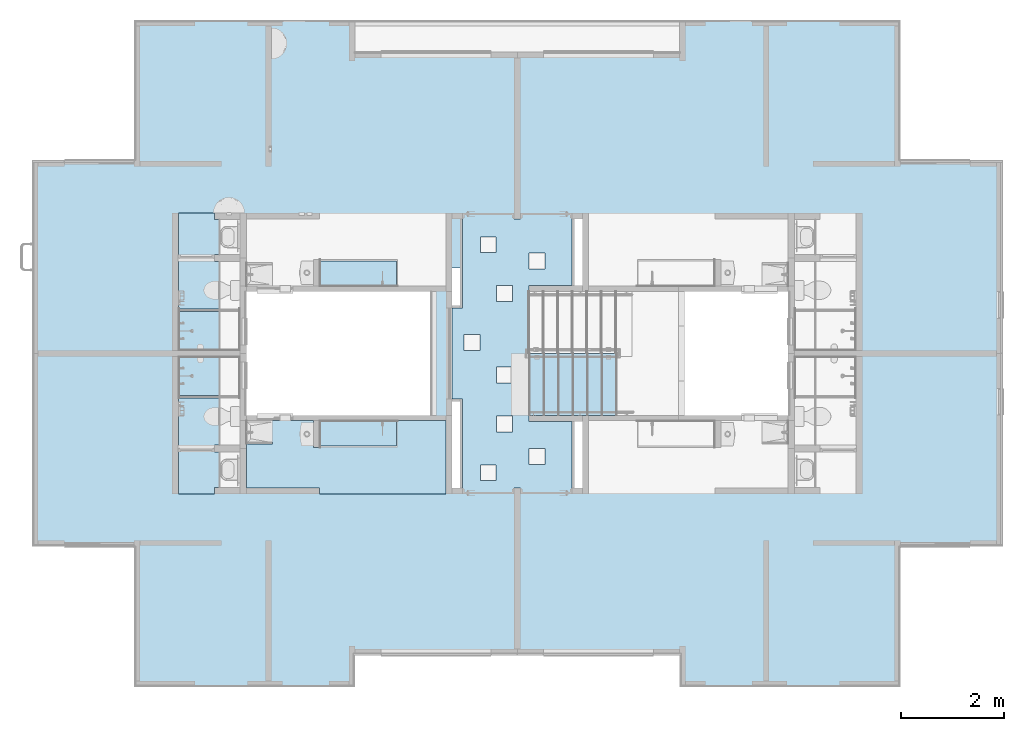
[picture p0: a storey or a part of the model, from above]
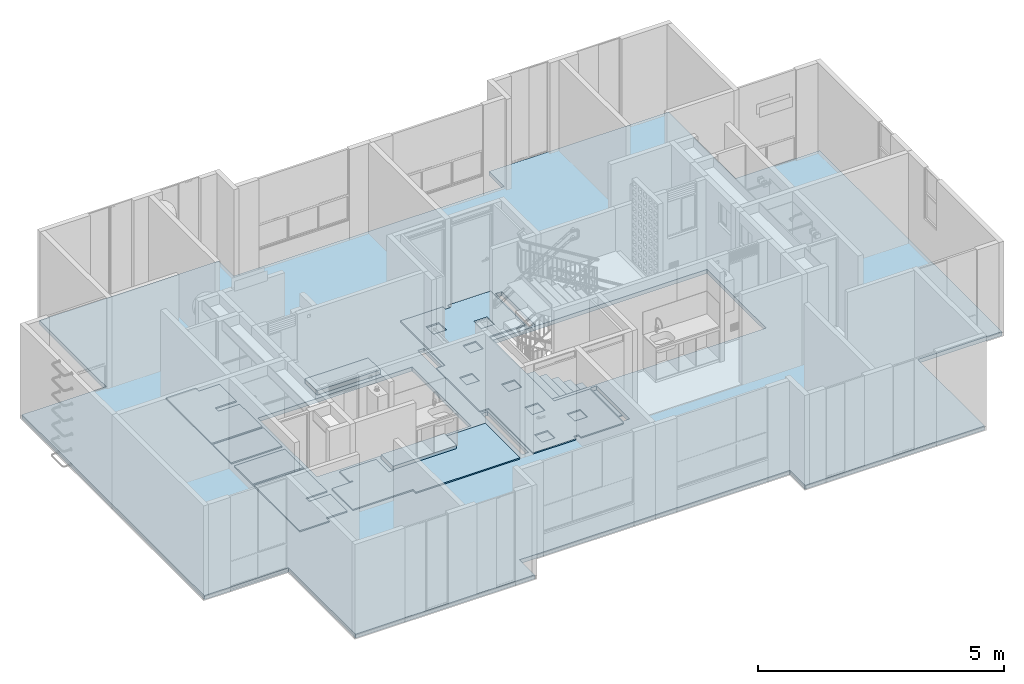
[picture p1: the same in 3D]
Properties of the parts of a building model (IFC4), part 1 of 6

# File
Description: ViewDefinition [ReferenceView_V1.2], RevitIdentifiers [VersionGUID: ac9cff58-8635-4e02-9c65-74fbef69012c, NumberOfSaves: 19], CoordinateReference [CoordinateBase: Shared Coordinates], ExchangeRequirement [Architecture]
Time: 2024-11-18T10:54:56-05:00
Written by: ODA SDAI 22.12
Made in: 23.1.40.56 - Exporter 23.2.5.0 - Alternate UI 23.2.5.0

# IfcSite, Default
RefLatitude: 4, 40, 21, 122360; RefLongitude: -74, -2, -58, -308105; RefElevation: 0 m
Pset_SiteCommon - Reference: Project Information

# IfcBuilding
Pset_BuildingCommon - Reference: Project Information; NumberOfStoreys: 7
Pset_BuildingElementProxyCommon - Reference: Project Information; IsExternal: no
Pset_BuildingStoreyCommon - Reference: Project Information; sets with these values: 2

# IfcBuildingStorey: Level:eBIM - Nivel (7)
Pset_BuildingStoreyCommon - Reference: eBIM - Nivel
Name | LongName | Elevation (m)
Nivel 1 | Nivel 1 | 0
Nivel 2 | Nivel 2 | 2.35
Nivel 3 | Nivel 3 | 4.7
Nivel 4 | Nivel 4 | 7.05
Nivel 5 | Nivel 5 | 9.4
Nivel 6 | Nivel 6 | 11.75
Nivel 7 | Nivel 7 | 14.1

# IfcSpace: APTO TIPO A 53:950452, 53
In: Nivel 2
LongName: APTO TIPO A; PredefinedType: SPACE; Group: Gross Building
Pset_SpaceCommon - IsExternal: no; Reference: APTO TIPO A 53
Pset_SpaceHeaterTypeCommon - Reference: APTO TIPO A 53
Qto_SpaceBaseQuantities - Height: 2.35 m

# IfcSpace: APTO TIPO A 54:950462, 54
In: Nivel 2
LongName: APTO TIPO A; PredefinedType: SPACE; Group: Gross Building
Pset_SpaceCommon - IsExternal: no; Reference: APTO TIPO A 54
Pset_SpaceHeaterTypeCommon - Reference: APTO TIPO A 54
Qto_SpaceBaseQuantities - Height: 2.35 m

# IfcSpace: APTO TIPO A 55:950468, 55
In: Nivel 3
LongName: APTO TIPO A; PredefinedType: SPACE; Group: Gross Building
Pset_SpaceCommon - IsExternal: no; Reference: APTO TIPO A 55
Pset_SpaceHeaterTypeCommon - Reference: APTO TIPO A 55
Qto_SpaceBaseQuantities - Height: 2.35 m

# IfcSpace: APTO TIPO A 56:950472, 56
In: Nivel 3
LongName: APTO TIPO A; PredefinedType: SPACE; Group: Gross Building
Pset_SpaceCommon - IsExternal: no; Reference: APTO TIPO A 56
Pset_SpaceHeaterTypeCommon - Reference: APTO TIPO A 56
Qto_SpaceBaseQuantities - Height: 2.35 m

# IfcSpace: APTO TIPO A 57:950475, 57
In: Nivel 3
LongName: APTO TIPO A; PredefinedType: SPACE; Group: Gross Building
Pset_SpaceCommon - IsExternal: no; Reference: APTO TIPO A 57
Pset_SpaceHeaterTypeCommon - Reference: APTO TIPO A 57
Qto_SpaceBaseQuantities - Height: 2.35 m

# IfcSpace: APTO TIPO A 58:950478, 58
In: Nivel 3
LongName: APTO TIPO A; PredefinedType: SPACE; Group: Gross Building
Pset_SpaceCommon - IsExternal: no; Reference: APTO TIPO A 58
Pset_SpaceHeaterTypeCommon - Reference: APTO TIPO A 58
Qto_SpaceBaseQuantities - Height: 2.35 m

# IfcSpace: APTO TIPO B 51:950442, 51
In: Nivel 2
LongName: APTO TIPO B; PredefinedType: SPACE; Group: Gross Building
Pset_SpaceCommon - IsExternal: no; Reference: APTO TIPO B 51
Pset_SpaceHeaterTypeCommon - Reference: APTO TIPO B 51
Qto_SpaceBaseQuantities - Height: 2.35 m

# IfcSpace: APTO TIPO B 52:950446, 52
In: Nivel 2
LongName: APTO TIPO B; PredefinedType: SPACE; Group: Gross Building
Pset_SpaceCommon - IsExternal: no; Reference: APTO TIPO B 52
Pset_SpaceHeaterTypeCommon - Reference: APTO TIPO B 52
Qto_SpaceBaseQuantities - Height: 2.35 m

# IfcSpace: APTO TIPO C 28:905856, 28
In: Nivel 1
LongName: APTO TIPO C; PredefinedType: SPACE; Group: Gross Building
Pset_SpaceCommon - IsExternal: no; Reference: APTO TIPO C 28
Pset_SpaceHeaterTypeCommon - Reference: APTO TIPO C 28
Qto_SpaceBaseQuantities - Height: 2.35 m

# IfcSpace: APTO TIPO C 29:905863, 29
In: Nivel 1
LongName: APTO TIPO C; PredefinedType: SPACE; Group: Gross Building
Pset_SpaceCommon - IsExternal: no; Reference: APTO TIPO C 29
Pset_SpaceHeaterTypeCommon - Reference: APTO TIPO C 29
Qto_SpaceBaseQuantities - Height: 2.35 m

# IfcSpace: APTO TIPO C 30:905869, 30
In: Nivel 1
LongName: APTO TIPO C; PredefinedType: SPACE; Group: Gross Building
Pset_SpaceCommon - IsExternal: no; Reference: APTO TIPO C 30
Pset_SpaceHeaterTypeCommon - Reference: APTO TIPO C 30
Qto_SpaceBaseQuantities - Height: 2.35 m

# IfcSpace: APTO TIPO D 27:905849, 27
In: Nivel 1
LongName: APTO TIPO D; PredefinedType: SPACE; Group: Gross Building
Pset_SpaceCommon - IsExternal: no; Reference: APTO TIPO D 27
Pset_SpaceHeaterTypeCommon - Reference: APTO TIPO D 27
Qto_SpaceBaseQuantities - Height: 2.35 m

# IfcSpace: Alcoba 145:749115, 145
In: Nivel 3
LongName: Alcoba; PredefinedType: SPACE
Pset_SpaceCommon - IsExternal: no; Reference: Alcoba 145
Pset_SpaceHeaterTypeCommon - Reference: Alcoba 145
Qto_SpaceBaseQuantities - Height: 2.25 m; GrossVolume: 14.4299 m3; NetVolume: 14.4299 m3

# IfcSpace: Alcoba 152:749459, 152
In: Nivel 3
LongName: Alcoba; PredefinedType: SPACE
Pset_SpaceCommon - IsExternal: no; Reference: Alcoba 152
Pset_SpaceHeaterTypeCommon - Reference: Alcoba 152
Qto_SpaceBaseQuantities - Height: 2.25 m; GrossVolume: 14.4299 m3; NetVolume: 14.4299 m3

# IfcSpace: Alcoba 160:749485, 160
In: Nivel 3
LongName: Alcoba; PredefinedType: SPACE
Pset_SpaceCommon - IsExternal: no; Reference: Alcoba 160
Pset_SpaceHeaterTypeCommon - Reference: Alcoba 160
Qto_SpaceBaseQuantities - Height: 2.25 m; GrossVolume: 14.4299 m3; NetVolume: 14.4299 m3

# IfcSpace: Alcoba 167:749660, 167
In: Nivel 3
LongName: Alcoba; PredefinedType: SPACE
Pset_SpaceCommon - IsExternal: no; Reference: Alcoba 167
Pset_SpaceHeaterTypeCommon - Reference: Alcoba 167
Qto_SpaceBaseQuantities - Height: 2.25 m; GrossVolume: 14.4299 m3; NetVolume: 14.4299 m3

# IfcSpace: Alcoba 203:750682, 203
In: Nivel 4
LongName: Alcoba; PredefinedType: SPACE
Pset_SpaceCommon - IsExternal: no; Reference: Alcoba 203
Pset_SpaceHeaterTypeCommon - Reference: Alcoba 203
Qto_SpaceBaseQuantities - Height: 2.25 m; GrossVolume: 14.4299 m3; NetVolume: 14.4299 m3

# IfcSpace: Alcoba 211:751026, 211
In: Nivel 4
LongName: Alcoba; PredefinedType: SPACE
Pset_SpaceCommon - IsExternal: no; Reference: Alcoba 211
Pset_SpaceHeaterTypeCommon - Reference: Alcoba 211
Qto_SpaceBaseQuantities - Height: 2.25 m; GrossVolume: 14.4299 m3; NetVolume: 14.4299 m3

# IfcSpace: Alcoba 219:751052, 219
In: Nivel 4
LongName: Alcoba; PredefinedType: SPACE
Pset_SpaceCommon - IsExternal: no; Reference: Alcoba 219
Pset_SpaceHeaterTypeCommon - Reference: Alcoba 219
Qto_SpaceBaseQuantities - Height: 2.25 m; GrossVolume: 14.4299 m3; NetVolume: 14.4299 m3

# IfcSpace: Alcoba 226:751227, 226
In: Nivel 4
LongName: Alcoba; PredefinedType: SPACE
Pset_SpaceCommon - IsExternal: no; Reference: Alcoba 226
Pset_SpaceHeaterTypeCommon - Reference: Alcoba 226
Qto_SpaceBaseQuantities - Height: 2.25 m; GrossVolume: 14.4299 m3; NetVolume: 14.4299 m3

# IfcSpace: Alcoba 262:752249, 262
In: Nivel 5
LongName: Alcoba; PredefinedType: SPACE
Pset_SpaceCommon - IsExternal: no; Reference: Alcoba 262
Pset_SpaceHeaterTypeCommon - Reference: Alcoba 262
Qto_SpaceBaseQuantities - Height: 2.25 m; GrossVolume: 14.4299 m3; NetVolume: 14.4299 m3

# IfcSpace: Alcoba 269:752593, 269
In: Nivel 5
LongName: Alcoba; PredefinedType: SPACE
Pset_SpaceCommon - IsExternal: no; Reference: Alcoba 269
Pset_SpaceHeaterTypeCommon - Reference: Alcoba 269
Qto_SpaceBaseQuantities - Height: 2.25 m; GrossVolume: 14.4299 m3; NetVolume: 14.4299 m3

# IfcSpace: Alcoba 277:752619, 277
In: Nivel 5
LongName: Alcoba; PredefinedType: SPACE
Pset_SpaceCommon - IsExternal: no; Reference: Alcoba 277
Pset_SpaceHeaterTypeCommon - Reference: Alcoba 277
Qto_SpaceBaseQuantities - Height: 2.25 m; GrossVolume: 14.4299 m3; NetVolume: 14.4299 m3

# IfcSpace: Alcoba 284:752794, 284
In: Nivel 5
LongName: Alcoba; PredefinedType: SPACE
Pset_SpaceCommon - IsExternal: no; Reference: Alcoba 284
Pset_SpaceHeaterTypeCommon - Reference: Alcoba 284
Qto_SpaceBaseQuantities - Height: 2.25 m; GrossVolume: 14.4299 m3; NetVolume: 14.4299 m3

# IfcSpace: Alcoba 31:728531, 31
In: Nivel 1
LongName: Alcoba; PredefinedType: SPACE
Pset_SpaceCommon - IsExternal: no; Reference: Alcoba 31
Pset_SpaceHeaterTypeCommon - Reference: Alcoba 31
Qto_SpaceBaseQuantities - Height: 2.25 m; GrossVolume: 14.4299 m3; NetVolume: 14.4299 m3

# IfcSpace: Alcoba 320:753816, 320
In: Nivel 6
LongName: Alcoba; PredefinedType: SPACE
Pset_SpaceCommon - IsExternal: no; Reference: Alcoba 320
Pset_SpaceHeaterTypeCommon - Reference: Alcoba 320
Qto_SpaceBaseQuantities - Height: 2.25 m; GrossVolume: 14.4299 m3; NetVolume: 14.4299 m3

# IfcSpace: Alcoba 327:754160, 327
In: Nivel 6
LongName: Alcoba; PredefinedType: SPACE
Pset_SpaceCommon - IsExternal: no; Reference: Alcoba 327
Pset_SpaceHeaterTypeCommon - Reference: Alcoba 327
Qto_SpaceBaseQuantities - Height: 2.25 m; GrossVolume: 14.3857 m3; NetVolume: 14.3857 m3

# IfcSpace: Alcoba 335:754186, 335
In: Nivel 6
LongName: Alcoba; PredefinedType: SPACE
Pset_SpaceCommon - IsExternal: no; Reference: Alcoba 335
Pset_SpaceHeaterTypeCommon - Reference: Alcoba 335
Qto_SpaceBaseQuantities - Height: 2.25 m; GrossVolume: 14.4299 m3; NetVolume: 14.4299 m3

# IfcSpace: Alcoba 342:754361, 342
In: Nivel 6
LongName: Alcoba; PredefinedType: SPACE
Pset_SpaceCommon - IsExternal: no; Reference: Alcoba 342
Pset_SpaceHeaterTypeCommon - Reference: Alcoba 342
Qto_SpaceBaseQuantities - Height: 2.25 m; GrossVolume: 14.4299 m3; NetVolume: 14.4299 m3

# IfcSpace: Alcoba 385:781398, 385
In: Nivel 1
LongName: Alcoba; PredefinedType: SPACE
Pset_SpaceCommon - IsExternal: no; Reference: Alcoba 385
Pset_SpaceHeaterTypeCommon - Reference: Alcoba 385
Qto_SpaceBaseQuantities - Height: 2.25 m; GrossVolume: 14.4299 m3; NetVolume: 14.4299 m3

# IfcSpace: Alcoba 405:791798, 405
In: Nivel 2
LongName: Alcoba; PredefinedType: SPACE
Pset_SpaceCommon - IsExternal: no; Reference: Alcoba 405
Pset_SpaceHeaterTypeCommon - Reference: Alcoba 405
Qto_SpaceBaseQuantities - Height: 2.25 m; GrossVolume: 14.4299 m3; NetVolume: 14.4299 m3

# IfcSpace: Alcoba 412:792138, 412
In: Nivel 2
LongName: Alcoba; PredefinedType: SPACE
Pset_SpaceCommon - IsExternal: no; Reference: Alcoba 412
Pset_SpaceHeaterTypeCommon - Reference: Alcoba 412
Qto_SpaceBaseQuantities - Height: 2.25 m; GrossVolume: 14.4299 m3; NetVolume: 14.4299 m3

# IfcSpace: Alcoba 420:792163, 420
In: Nivel 2
LongName: Alcoba; PredefinedType: SPACE
Pset_SpaceCommon - IsExternal: no; Reference: Alcoba 420
Pset_SpaceHeaterTypeCommon - Reference: Alcoba 420
Qto_SpaceBaseQuantities - Height: 2.25 m; GrossVolume: 14.4299 m3; NetVolume: 14.4299 m3

# IfcSpace: Alcoba 427:792336, 427
In: Nivel 2
LongName: Alcoba; PredefinedType: SPACE
Pset_SpaceCommon - IsExternal: no; Reference: Alcoba 427
Pset_SpaceHeaterTypeCommon - Reference: Alcoba 427
Qto_SpaceBaseQuantities - Height: 2.25 m; GrossVolume: 14.4299 m3; NetVolume: 14.4299 m3

# IfcSpace: Alcoba 474:872633, 474
In: Nivel 1
LongName: Alcoba; PredefinedType: SPACE
Pset_SpaceCommon - IsExternal: no; Reference: Alcoba 474
Pset_SpaceHeaterTypeCommon - Reference: Alcoba 474
Qto_SpaceBaseQuantities - Height: 2.25 m; GrossVolume: 14.4299 m3; NetVolume: 14.4299 m3

# IfcSpace: Alcoba 481:872831, 481
In: Nivel 1
LongName: Alcoba; PredefinedType: SPACE
Pset_SpaceCommon - IsExternal: no; Reference: Alcoba 481
Pset_SpaceHeaterTypeCommon - Reference: Alcoba 481
Qto_SpaceBaseQuantities - Height: 2.25 m; GrossVolume: 14.4161 m3; NetVolume: 14.4161 m3

# IfcSpace: Alcoba principal 143:749113, 143
In: Nivel 3
LongName: Alcoba principal; PredefinedType: SPACE
Pset_SpaceCommon - IsExternal: no; Reference: Alcoba principal 143
Pset_SpaceHeaterTypeCommon - Reference: Alcoba principal 143
Qto_SpaceBaseQuantities - Height: 2.25 m; GrossVolume: 20.8833 m3; NetVolume: 20.8833 m3

# IfcSpace: Alcoba principal 150:749457, 150
In: Nivel 3
LongName: Alcoba principal; PredefinedType: SPACE
Pset_SpaceCommon - IsExternal: no; Reference: Alcoba principal 150
Pset_SpaceHeaterTypeCommon - Reference: Alcoba principal 150
Qto_SpaceBaseQuantities - Height: 2.25 m; GrossVolume: 20.8833 m3; NetVolume: 20.8833 m3

# IfcSpace: Alcoba principal 158:749483, 158
In: Nivel 3
LongName: Alcoba principal; PredefinedType: SPACE
Pset_SpaceCommon - IsExternal: no; Reference: Alcoba principal 158
Pset_SpaceHeaterTypeCommon - Reference: Alcoba principal 158
Qto_SpaceBaseQuantities - Height: 2.25 m; GrossVolume: 20.8833 m3; NetVolume: 20.8833 m3

# IfcSpace: Alcoba principal 165:749658, 165
In: Nivel 3
LongName: Alcoba principal; PredefinedType: SPACE
Pset_SpaceCommon - IsExternal: no; Reference: Alcoba principal 165
Pset_SpaceHeaterTypeCommon - Reference: Alcoba principal 165
Qto_SpaceBaseQuantities - Height: 2.25 m; GrossVolume: 20.8833 m3; NetVolume: 20.8833 m3

# IfcSpace: Alcoba principal 201:750680, 201
In: Nivel 4
LongName: Alcoba principal; PredefinedType: SPACE
Pset_SpaceCommon - IsExternal: no; Reference: Alcoba principal 201
Pset_SpaceHeaterTypeCommon - Reference: Alcoba principal 201
Qto_SpaceBaseQuantities - Height: 2.25 m; GrossVolume: 20.8833 m3; NetVolume: 20.8833 m3

# IfcSpace: Alcoba principal 209:751024, 209
In: Nivel 4
LongName: Alcoba principal; PredefinedType: SPACE
Pset_SpaceCommon - IsExternal: no; Reference: Alcoba principal 209
Pset_SpaceHeaterTypeCommon - Reference: Alcoba principal 209
Qto_SpaceBaseQuantities - Height: 2.25 m; GrossVolume: 20.8833 m3; NetVolume: 20.8833 m3

# IfcSpace: Alcoba principal 217:751050, 217
In: Nivel 4
LongName: Alcoba principal; PredefinedType: SPACE
Pset_SpaceCommon - IsExternal: no; Reference: Alcoba principal 217
Pset_SpaceHeaterTypeCommon - Reference: Alcoba principal 217
Qto_SpaceBaseQuantities - Height: 2.25 m; GrossVolume: 20.8833 m3; NetVolume: 20.8833 m3

# IfcSpace: Alcoba principal 224:751225, 224
In: Nivel 4
LongName: Alcoba principal; PredefinedType: SPACE
Pset_SpaceCommon - IsExternal: no; Reference: Alcoba principal 224
Pset_SpaceHeaterTypeCommon - Reference: Alcoba principal 224
Qto_SpaceBaseQuantities - Height: 2.25 m; GrossVolume: 20.8833 m3; NetVolume: 20.8833 m3

# IfcSpace: Alcoba principal 260:752247, 260
In: Nivel 5
LongName: Alcoba principal; PredefinedType: SPACE
Pset_SpaceCommon - IsExternal: no; Reference: Alcoba principal 260
Pset_SpaceHeaterTypeCommon - Reference: Alcoba principal 260
Qto_SpaceBaseQuantities - Height: 2.25 m; GrossVolume: 20.8833 m3; NetVolume: 20.8833 m3

# IfcSpace: Alcoba principal 267:752591, 267
In: Nivel 5
LongName: Alcoba principal; PredefinedType: SPACE
Pset_SpaceCommon - IsExternal: no; Reference: Alcoba principal 267
Pset_SpaceHeaterTypeCommon - Reference: Alcoba principal 267
Qto_SpaceBaseQuantities - Height: 2.25 m; GrossVolume: 20.8833 m3; NetVolume: 20.8833 m3

# IfcSpace: Alcoba principal 275:752617, 275
In: Nivel 5
LongName: Alcoba principal; PredefinedType: SPACE
Pset_SpaceCommon - IsExternal: no; Reference: Alcoba principal 275
Pset_SpaceHeaterTypeCommon - Reference: Alcoba principal 275
Qto_SpaceBaseQuantities - Height: 2.25 m; GrossVolume: 20.8833 m3; NetVolume: 20.8833 m3

# IfcSpace: Alcoba principal 282:752792, 282
In: Nivel 5
LongName: Alcoba principal; PredefinedType: SPACE
Pset_SpaceCommon - IsExternal: no; Reference: Alcoba principal 282
Pset_SpaceHeaterTypeCommon - Reference: Alcoba principal 282
Qto_SpaceBaseQuantities - Height: 2.25 m; GrossVolume: 20.8833 m3; NetVolume: 20.8833 m3

# IfcSpace: Alcoba principal 29:728529, 29
In: Nivel 1
LongName: Alcoba principal; PredefinedType: SPACE
Pset_SpaceCommon - IsExternal: no; Reference: Alcoba principal 29
Pset_SpaceHeaterTypeCommon - Reference: Alcoba principal 29
Qto_SpaceBaseQuantities - Height: 2.25 m; GrossVolume: 20.8833 m3; NetVolume: 20.8833 m3

# IfcSpace: Alcoba principal 318:753814, 318
In: Nivel 6
LongName: Alcoba principal; PredefinedType: SPACE
Pset_SpaceCommon - IsExternal: no; Reference: Alcoba principal 318
Pset_SpaceHeaterTypeCommon - Reference: Alcoba principal 318
Qto_SpaceBaseQuantities - Height: 2.25 m; GrossVolume: 20.8833 m3; NetVolume: 20.8833 m3

# IfcSpace: Alcoba principal 325:754158, 325
In: Nivel 6
LongName: Alcoba principal; PredefinedType: SPACE
Pset_SpaceCommon - IsExternal: no; Reference: Alcoba principal 325
Pset_SpaceHeaterTypeCommon - Reference: Alcoba principal 325
Qto_SpaceBaseQuantities - Height: 2.25 m; GrossVolume: 20.8833 m3; NetVolume: 20.8833 m3

# IfcSpace: Alcoba principal 333:754184, 333
In: Nivel 6
LongName: Alcoba principal; PredefinedType: SPACE
Pset_SpaceCommon - IsExternal: no; Reference: Alcoba principal 333
Pset_SpaceHeaterTypeCommon - Reference: Alcoba principal 333
Qto_SpaceBaseQuantities - Height: 2.25 m; GrossVolume: 20.8833 m3; NetVolume: 20.8833 m3

# IfcSpace: Alcoba principal 340:754359, 340
In: Nivel 6
LongName: Alcoba principal; PredefinedType: SPACE
Pset_SpaceCommon - IsExternal: no; Reference: Alcoba principal 340
Pset_SpaceHeaterTypeCommon - Reference: Alcoba principal 340
Qto_SpaceBaseQuantities - Height: 2.25 m; GrossVolume: 20.8833 m3; NetVolume: 20.8833 m3

# IfcSpace: Alcoba principal 383:781396, 383
In: Nivel 1
LongName: Alcoba principal; PredefinedType: SPACE
Pset_SpaceCommon - IsExternal: no; Reference: Alcoba principal 383
Pset_SpaceHeaterTypeCommon - Reference: Alcoba principal 383
Qto_SpaceBaseQuantities - Height: 2.25 m; GrossVolume: 20.8833 m3; NetVolume: 20.8833 m3

# IfcSpace: Alcoba principal 403:791796, 403
In: Nivel 2
LongName: Alcoba principal; PredefinedType: SPACE
Pset_SpaceCommon - IsExternal: no; Reference: Alcoba principal 403
Pset_SpaceHeaterTypeCommon - Reference: Alcoba principal 403
Qto_SpaceBaseQuantities - Height: 2.25 m; GrossVolume: 20.8833 m3; NetVolume: 20.8833 m3

# IfcSpace: Alcoba principal 410:792136, 410
In: Nivel 2
LongName: Alcoba principal; PredefinedType: SPACE
Pset_SpaceCommon - IsExternal: no; Reference: Alcoba principal 410
Pset_SpaceHeaterTypeCommon - Reference: Alcoba principal 410
Qto_SpaceBaseQuantities - Height: 2.25 m; GrossVolume: 20.8833 m3; NetVolume: 20.8833 m3

# IfcSpace: Alcoba principal 418:792161, 418
In: Nivel 2
LongName: Alcoba principal; PredefinedType: SPACE
Pset_SpaceCommon - IsExternal: no; Reference: Alcoba principal 418
Pset_SpaceHeaterTypeCommon - Reference: Alcoba principal 418
Qto_SpaceBaseQuantities - Height: 2.25 m; GrossVolume: 20.8833 m3; NetVolume: 20.8833 m3

# IfcSpace: Alcoba principal 425:792334, 425
In: Nivel 2
LongName: Alcoba principal; PredefinedType: SPACE
Pset_SpaceCommon - IsExternal: no; Reference: Alcoba principal 425
Pset_SpaceHeaterTypeCommon - Reference: Alcoba principal 425
Qto_SpaceBaseQuantities - Height: 2.25 m; GrossVolume: 20.8833 m3; NetVolume: 20.8833 m3

# IfcSpace: Alcoba principal 472:872631, 472
In: Nivel 1
LongName: Alcoba principal; PredefinedType: SPACE
Pset_SpaceCommon - IsExternal: no; Reference: Alcoba principal 472
Pset_SpaceHeaterTypeCommon - Reference: Alcoba principal 472
Qto_SpaceBaseQuantities - Height: 2.25 m; GrossVolume: 20.8833 m3; NetVolume: 20.8833 m3

# IfcSpace: Alcoba principal 479:872829, 479
In: Nivel 1
LongName: Alcoba principal; PredefinedType: SPACE
Pset_SpaceCommon - IsExternal: no; Reference: Alcoba principal 479
Pset_SpaceHeaterTypeCommon - Reference: Alcoba principal 479
Qto_SpaceBaseQuantities - Height: 2.25 m; GrossVolume: 20.8833 m3; NetVolume: 20.8833 m3

# IfcSpace: Baño 144:749114, 144
In: Nivel 3
LongName: Baño; PredefinedType: SPACE
Pset_SpaceCommon - IsExternal: no; Reference: Baño 144
Pset_SpaceHeaterTypeCommon - Reference: Baño 144
Qto_SpaceBaseQuantities - Height: 2.22 m; NetVolume: 6.53629 m3

# IfcSpace: Baño 151:749458, 151
In: Nivel 3
LongName: Baño; PredefinedType: SPACE
Pset_SpaceCommon - IsExternal: no; Reference: Baño 151
Pset_SpaceHeaterTypeCommon - Reference: Baño 151
Qto_SpaceBaseQuantities - Height: 2.22 m; NetVolume: 6.53629 m3

# IfcSpace: Baño 159:749484, 159
In: Nivel 3
LongName: Baño; PredefinedType: SPACE
Pset_SpaceCommon - IsExternal: no; Reference: Baño 159
Pset_SpaceHeaterTypeCommon - Reference: Baño 159
Qto_SpaceBaseQuantities - Height: 2.22 m; NetVolume: 6.53629 m3

# IfcSpace: Baño 166:749659, 166
In: Nivel 3
LongName: Baño; PredefinedType: SPACE
Pset_SpaceCommon - IsExternal: no; Reference: Baño 166
Pset_SpaceHeaterTypeCommon - Reference: Baño 166
Qto_SpaceBaseQuantities - Height: 2.22 m; NetVolume: 6.53629 m3

# IfcSpace: Baño 202:750681, 202
In: Nivel 4
LongName: Baño; PredefinedType: SPACE
Pset_SpaceCommon - IsExternal: no; Reference: Baño 202
Pset_SpaceHeaterTypeCommon - Reference: Baño 202
Qto_SpaceBaseQuantities - Height: 2.22 m; NetVolume: 6.53629 m3

# IfcSpace: Baño 210:751025, 210
In: Nivel 4
LongName: Baño; PredefinedType: SPACE
Pset_SpaceCommon - IsExternal: no; Reference: Baño 210
Pset_SpaceHeaterTypeCommon - Reference: Baño 210
Qto_SpaceBaseQuantities - Height: 2.22 m; NetVolume: 6.53629 m3

# IfcSpace: Baño 218:751051, 218
In: Nivel 4
LongName: Baño; PredefinedType: SPACE
Pset_SpaceCommon - IsExternal: no; Reference: Baño 218
Pset_SpaceHeaterTypeCommon - Reference: Baño 218
Qto_SpaceBaseQuantities - Height: 2.22 m; NetVolume: 6.53629 m3

# IfcSpace: Baño 225:751226, 225
In: Nivel 4
LongName: Baño; PredefinedType: SPACE
Pset_SpaceCommon - IsExternal: no; Reference: Baño 225
Pset_SpaceHeaterTypeCommon - Reference: Baño 225
Qto_SpaceBaseQuantities - Height: 2.22 m; NetVolume: 6.53629 m3

# IfcSpace: Baño 261:752248, 261
In: Nivel 5
LongName: Baño; PredefinedType: SPACE
Pset_SpaceCommon - IsExternal: no; Reference: Baño 261
Pset_SpaceHeaterTypeCommon - Reference: Baño 261
Qto_SpaceBaseQuantities - Height: 2.22 m; NetVolume: 6.53629 m3

# IfcSpace: Baño 268:752592, 268
In: Nivel 5
LongName: Baño; PredefinedType: SPACE
Pset_SpaceCommon - IsExternal: no; Reference: Baño 268
Pset_SpaceHeaterTypeCommon - Reference: Baño 268
Qto_SpaceBaseQuantities - Height: 2.22 m; NetVolume: 6.53629 m3

# IfcSpace: Baño 276:752618, 276
In: Nivel 5
LongName: Baño; PredefinedType: SPACE
Pset_SpaceCommon - IsExternal: no; Reference: Baño 276
Pset_SpaceHeaterTypeCommon - Reference: Baño 276
Qto_SpaceBaseQuantities - Height: 2.22 m; NetVolume: 6.53629 m3

# IfcSpace: Baño 283:752793, 283
In: Nivel 5
LongName: Baño; PredefinedType: SPACE
Pset_SpaceCommon - IsExternal: no; Reference: Baño 283
Pset_SpaceHeaterTypeCommon - Reference: Baño 283
Qto_SpaceBaseQuantities - Height: 2.22 m; NetVolume: 6.53629 m3

# IfcSpace: Baño 30:728530, 30
In: Nivel 1
LongName: Baño; PredefinedType: SPACE
Pset_SpaceCommon - IsExternal: no; Reference: Baño 30
Pset_SpaceHeaterTypeCommon - Reference: Baño 30
Qto_SpaceBaseQuantities - Height: 2.22 m; NetVolume: 6.39589 m3

# IfcSpace: Baño 319:753815, 319
In: Nivel 6
LongName: Baño; PredefinedType: SPACE
Pset_SpaceCommon - IsExternal: no; Reference: Baño 319
Pset_SpaceHeaterTypeCommon - Reference: Baño 319
Qto_SpaceBaseQuantities - Height: 2.22 m; NetVolume: 6.53629 m3

# IfcSpace: Baño 326:754159, 326
In: Nivel 6
LongName: Baño; PredefinedType: SPACE
Pset_SpaceCommon - IsExternal: no; Reference: Baño 326
Pset_SpaceHeaterTypeCommon - Reference: Baño 326
Qto_SpaceBaseQuantities - Height: 2.22 m; NetVolume: 6.53629 m3

# IfcSpace: Baño 334:754185, 334
In: Nivel 6
LongName: Baño; PredefinedType: SPACE
Pset_SpaceCommon - IsExternal: no; Reference: Baño 334
Pset_SpaceHeaterTypeCommon - Reference: Baño 334
Qto_SpaceBaseQuantities - Height: 2.22 m; NetVolume: 6.53629 m3

# IfcSpace: Baño 341:754360, 341
In: Nivel 6
LongName: Baño; PredefinedType: SPACE
Pset_SpaceCommon - IsExternal: no; Reference: Baño 341
Pset_SpaceHeaterTypeCommon - Reference: Baño 341
Qto_SpaceBaseQuantities - Height: 2.22 m; NetVolume: 6.53629 m3

# IfcSpace: Baño 384:781397, 384
In: Nivel 1
LongName: Baño; PredefinedType: SPACE
Pset_SpaceCommon - IsExternal: no; Reference: Baño 384
Pset_SpaceHeaterTypeCommon - Reference: Baño 384
Qto_SpaceBaseQuantities - Height: 2.25 m; NetVolume: 4.26574 m3

# IfcSpace: Baño 404:791797, 404
In: Nivel 2
LongName: Baño; PredefinedType: SPACE
Pset_SpaceCommon - IsExternal: no; Reference: Baño 404
Pset_SpaceHeaterTypeCommon - Reference: Baño 404
Qto_SpaceBaseQuantities - Height: 2.22 m; NetVolume: 6.53629 m3

# IfcSpace: Baño 411:792137, 411
In: Nivel 2
LongName: Baño; PredefinedType: SPACE
Pset_SpaceCommon - IsExternal: no; Reference: Baño 411
Pset_SpaceHeaterTypeCommon - Reference: Baño 411
Qto_SpaceBaseQuantities - Height: 2.22 m; NetVolume: 6.53629 m3

# IfcSpace: Baño 419:792162, 419
In: Nivel 2
LongName: Baño; PredefinedType: SPACE
Pset_SpaceCommon - IsExternal: no; Reference: Baño 419
Pset_SpaceHeaterTypeCommon - Reference: Baño 419
Qto_SpaceBaseQuantities - Height: 2.22 m; NetVolume: 6.53629 m3

# IfcSpace: Baño 426:792335, 426
In: Nivel 2
LongName: Baño; PredefinedType: SPACE
Pset_SpaceCommon - IsExternal: no; Reference: Baño 426
Pset_SpaceHeaterTypeCommon - Reference: Baño 426
Qto_SpaceBaseQuantities - Height: 2.22 m; NetVolume: 6.53629 m3

# IfcSpace: Baño 473:872632, 473
In: Nivel 1
LongName: Baño; PredefinedType: SPACE
Pset_SpaceCommon - IsExternal: no; Reference: Baño 473
Pset_SpaceHeaterTypeCommon - Reference: Baño 473
Qto_SpaceBaseQuantities - Height: 2.22 m; NetVolume: 6.39589 m3

# IfcSpace: Baño 480:872830, 480
In: Nivel 1
LongName: Baño; PredefinedType: SPACE
Pset_SpaceCommon - IsExternal: no; Reference: Baño 480
Pset_SpaceHeaterTypeCommon - Reference: Baño 480
Qto_SpaceBaseQuantities - Height: 2.22 m; NetVolume: 6.35181 m3

# IfcSpace: Circulacion 36:1062875, 36
In: Nivel 2
LongName: Circulacion; PredefinedType: SPACE
Pset_SpaceCommon - IsExternal: no; Reference: Circulacion 36
Pset_SpaceHeaterTypeCommon - Reference: Circulacion 36
Qto_SpaceBaseQuantities - Height: 2.25 m; NetVolume: 20.3687 m3

# IfcSpace: Circulacion 37:1063138, 37
In: Nivel 3
LongName: Circulacion; PredefinedType: SPACE
Pset_SpaceCommon - IsExternal: no; Reference: Circulacion 37
Pset_SpaceHeaterTypeCommon - Reference: Circulacion 37
Qto_SpaceBaseQuantities - Height: 2.25 m; NetVolume: 20.3687 m3

# IfcSpace: Circulacion 38:1063140, 38
In: Nivel 4
LongName: Circulacion; PredefinedType: SPACE
Pset_SpaceCommon - IsExternal: no; Reference: Circulacion 38
Pset_SpaceHeaterTypeCommon - Reference: Circulacion 38
Qto_SpaceBaseQuantities - Height: 2.25 m; NetVolume: 20.3687 m3

# IfcSpace: Circulacion 39:1063142, 39
In: Nivel 5
LongName: Circulacion; PredefinedType: SPACE
Pset_SpaceCommon - IsExternal: no; Reference: Circulacion 39
Pset_SpaceHeaterTypeCommon - Reference: Circulacion 39
Qto_SpaceBaseQuantities - Height: 2.25 m; NetVolume: 20.3687 m3

# IfcSpace: Circulacion 40:1063144, 40
In: Nivel 6
LongName: Circulacion; PredefinedType: SPACE
Pset_SpaceCommon - IsExternal: no; Reference: Circulacion 40
Pset_SpaceHeaterTypeCommon - Reference: Circulacion 40
Qto_SpaceBaseQuantities - Height: 2.25 m; NetVolume: 20.4087 m3

# IfcSpace: Circulacion primer piso 401:788182, 401
In: Nivel 1
LongName: Circulacion primer piso; PredefinedType: SPACE
Pset_SpaceCommon - IsExternal: no; Reference: Circulacion primer piso 401
Pset_SpaceHeaterTypeCommon - Reference: Circulacion primer piso 401
Qto_SpaceBaseQuantities - Height: 2.25 m; NetVolume: 28.5942 m3

# IfcSpace: Cocina 147:749117, 147
In: Nivel 3
LongName: Cocina; PredefinedType: SPACE
Pset_SpaceCommon - IsExternal: no; Reference: Cocina 147
Pset_SpaceHeaterTypeCommon - Reference: Cocina 147
Qto_SpaceBaseQuantities - Height: 2.22 m; NetVolume: 7.61961 m3

# IfcSpace: Cocina 154:749461, 154
In: Nivel 3
LongName: Cocina; PredefinedType: SPACE
Pset_SpaceCommon - IsExternal: no; Reference: Cocina 154
Pset_SpaceHeaterTypeCommon - Reference: Cocina 154
Qto_SpaceBaseQuantities - Height: 2.22 m; NetVolume: 7.61961 m3

# IfcSpace: Cocina 162:749487, 162
In: Nivel 3
LongName: Cocina; PredefinedType: SPACE
Pset_SpaceCommon - IsExternal: no; Reference: Cocina 162
Pset_SpaceHeaterTypeCommon - Reference: Cocina 162
Qto_SpaceBaseQuantities - Height: 2.22 m; NetVolume: 7.61961 m3

# IfcSpace: Cocina 169:749662, 169
In: Nivel 3
LongName: Cocina; PredefinedType: SPACE
Pset_SpaceCommon - IsExternal: no; Reference: Cocina 169
Pset_SpaceHeaterTypeCommon - Reference: Cocina 169
Qto_SpaceBaseQuantities - Height: 2.22 m; NetVolume: 7.61961 m3

# IfcSpace: Cocina 205:750684, 205
In: Nivel 4
LongName: Cocina; PredefinedType: SPACE
Pset_SpaceCommon - IsExternal: no; Reference: Cocina 205
Pset_SpaceHeaterTypeCommon - Reference: Cocina 205
Qto_SpaceBaseQuantities - Height: 2.22 m; NetVolume: 7.61961 m3

# IfcSpace: Cocina 213:751028, 213
In: Nivel 4
LongName: Cocina; PredefinedType: SPACE
Pset_SpaceCommon - IsExternal: no; Reference: Cocina 213
Pset_SpaceHeaterTypeCommon - Reference: Cocina 213
Qto_SpaceBaseQuantities - Height: 2.22 m; NetVolume: 7.61961 m3

# IfcSpace: Cocina 221:751054, 221
In: Nivel 4
LongName: Cocina; PredefinedType: SPACE
Pset_SpaceCommon - IsExternal: no; Reference: Cocina 221
Pset_SpaceHeaterTypeCommon - Reference: Cocina 221
Qto_SpaceBaseQuantities - Height: 2.22 m; NetVolume: 7.61961 m3

# IfcSpace: Cocina 228:751229, 228
In: Nivel 4
LongName: Cocina; PredefinedType: SPACE
Pset_SpaceCommon - IsExternal: no; Reference: Cocina 228
Pset_SpaceHeaterTypeCommon - Reference: Cocina 228
Qto_SpaceBaseQuantities - Height: 2.22 m; NetVolume: 7.61961 m3

# IfcSpace: Cocina 264:752251, 264
In: Nivel 5
LongName: Cocina; PredefinedType: SPACE
Pset_SpaceCommon - IsExternal: no; Reference: Cocina 264
Pset_SpaceHeaterTypeCommon - Reference: Cocina 264
Qto_SpaceBaseQuantities - Height: 2.22 m; NetVolume: 7.61961 m3

# IfcSpace: Cocina 271:752595, 271
In: Nivel 5
LongName: Cocina; PredefinedType: SPACE
Pset_SpaceCommon - IsExternal: no; Reference: Cocina 271
Pset_SpaceHeaterTypeCommon - Reference: Cocina 271
Qto_SpaceBaseQuantities - Height: 2.22 m; NetVolume: 7.61961 m3

# IfcSpace: Cocina 279:752621, 279
In: Nivel 5
LongName: Cocina; PredefinedType: SPACE
Pset_SpaceCommon - IsExternal: no; Reference: Cocina 279
Pset_SpaceHeaterTypeCommon - Reference: Cocina 279
Qto_SpaceBaseQuantities - Height: 2.22 m; NetVolume: 7.61961 m3

# IfcSpace: Cocina 286:752796, 286
In: Nivel 5
LongName: Cocina; PredefinedType: SPACE
Pset_SpaceCommon - IsExternal: no; Reference: Cocina 286
Pset_SpaceHeaterTypeCommon - Reference: Cocina 286
Qto_SpaceBaseQuantities - Height: 2.22 m; NetVolume: 7.61961 m3

# IfcSpace: Cocina 322:753818, 322
In: Nivel 6
LongName: Cocina; PredefinedType: SPACE
Pset_SpaceCommon - IsExternal: no; Reference: Cocina 322
Pset_SpaceHeaterTypeCommon - Reference: Cocina 322
Qto_SpaceBaseQuantities - Height: 2.22 m; NetVolume: 7.61961 m3

# IfcSpace: Cocina 329:754162, 329
In: Nivel 6
LongName: Cocina; PredefinedType: SPACE
Pset_SpaceCommon - IsExternal: no; Reference: Cocina 329
Pset_SpaceHeaterTypeCommon - Reference: Cocina 329
Qto_SpaceBaseQuantities - Height: 2.22 m; NetVolume: 7.66454 m3

# IfcSpace: Cocina 337:754188, 337
In: Nivel 6
LongName: Cocina; PredefinedType: SPACE
Pset_SpaceCommon - IsExternal: no; Reference: Cocina 337
Pset_SpaceHeaterTypeCommon - Reference: Cocina 337
Qto_SpaceBaseQuantities - Height: 2.22 m; NetVolume: 7.61961 m3

# IfcSpace: Cocina 33:728533, 33
In: Nivel 1
LongName: Cocina; PredefinedType: SPACE
Pset_SpaceCommon - IsExternal: no; Reference: Cocina 33
Pset_SpaceHeaterTypeCommon - Reference: Cocina 33
Qto_SpaceBaseQuantities - Height: 2.22 m; NetVolume: 7.61967 m3

# IfcSpace: Cocina 344:754363, 344
In: Nivel 6
LongName: Cocina; PredefinedType: SPACE
Pset_SpaceCommon - IsExternal: no; Reference: Cocina 344
Pset_SpaceHeaterTypeCommon - Reference: Cocina 344
Qto_SpaceBaseQuantities - Height: 2.22 m; NetVolume: 7.61961 m3

# IfcSpace: Cocina 387:781400, 387
In: Nivel 1
LongName: Cocina; PredefinedType: SPACE
Pset_SpaceCommon - IsExternal: no; Reference: Cocina 387
Pset_SpaceHeaterTypeCommon - Reference: Cocina 387
Qto_SpaceBaseQuantities - Height: 2.22 m; NetVolume: 7.36176 m3

# IfcSpace: Cocina 407:791800, 407
In: Nivel 2
LongName: Cocina; PredefinedType: SPACE
Pset_SpaceCommon - IsExternal: no; Reference: Cocina 407
Pset_SpaceHeaterTypeCommon - Reference: Cocina 407
Qto_SpaceBaseQuantities - Height: 2.22 m; NetVolume: 7.61961 m3

# IfcSpace: Cocina 414:792140, 414
In: Nivel 2
LongName: Cocina; PredefinedType: SPACE
Pset_SpaceCommon - IsExternal: no; Reference: Cocina 414
Pset_SpaceHeaterTypeCommon - Reference: Cocina 414
Qto_SpaceBaseQuantities - Height: 2.22 m; NetVolume: 7.61961 m3

# IfcSpace: Cocina 422:792165, 422
In: Nivel 2
LongName: Cocina; PredefinedType: SPACE
Pset_SpaceCommon - IsExternal: no; Reference: Cocina 422
Pset_SpaceHeaterTypeCommon - Reference: Cocina 422
Qto_SpaceBaseQuantities - Height: 2.22 m; NetVolume: 7.61961 m3

# IfcSpace: Cocina 429:792338, 429
In: Nivel 2
LongName: Cocina; PredefinedType: SPACE
Pset_SpaceCommon - IsExternal: no; Reference: Cocina 429
Pset_SpaceHeaterTypeCommon - Reference: Cocina 429
Qto_SpaceBaseQuantities - Height: 2.22 m; NetVolume: 7.61961 m3

# IfcSpace: Cocina 476:872635, 476
In: Nivel 1
LongName: Cocina; PredefinedType: SPACE
Pset_SpaceCommon - IsExternal: no; Reference: Cocina 476
Pset_SpaceHeaterTypeCommon - Reference: Cocina 476
Qto_SpaceBaseQuantities - Height: 2.22 m; NetVolume: 7.58827 m3

# IfcSpace: Cocina 483:872833, 483
In: Nivel 1
LongName: Cocina; PredefinedType: SPACE
Pset_SpaceCommon - IsExternal: no; Reference: Cocina 483
Pset_SpaceHeaterTypeCommon - Reference: Cocina 483
Qto_SpaceBaseQuantities - Height: 2.22 m; NetVolume: 7.61961 m3

# IfcSpace: Contadores 41:1197159, 41
In: Nivel 1
LongName: Contadores; PredefinedType: SPACE
Pset_SpaceCommon - IsExternal: no; Reference: Contadores 41
Pset_SpaceHeaterTypeCommon - Reference: Contadores 41
Qto_SpaceBaseQuantities - Height: 2.25 m; NetVolume: 2.37509 m3

# IfcSpace: Hall 149:749119, 149
In: Nivel 3
LongName: Hall; PredefinedType: SPACE
Pset_SpaceCommon - IsExternal: no; Reference: Hall 149
Pset_SpaceHeaterTypeCommon - Reference: Hall 149
Qto_SpaceBaseQuantities - Height: 2.25 m; GrossVolume: 3.63487 m3; NetVolume: 3.63487 m3

# IfcSpace: Hall 156:749463, 156
In: Nivel 3
LongName: Hall; PredefinedType: SPACE
Pset_SpaceCommon - IsExternal: no; Reference: Hall 156
Pset_SpaceHeaterTypeCommon - Reference: Hall 156
Qto_SpaceBaseQuantities - Height: 2.25 m; GrossVolume: 3.63487 m3; NetVolume: 3.63487 m3

# IfcSpace: Hall 164:749489, 164
In: Nivel 3
LongName: Hall; PredefinedType: SPACE
Pset_SpaceCommon - IsExternal: no; Reference: Hall 164
Pset_SpaceHeaterTypeCommon - Reference: Hall 164
Qto_SpaceBaseQuantities - Height: 2.25 m; GrossVolume: 3.63487 m3; NetVolume: 3.63487 m3

# IfcSpace: Hall 171:749664, 171
In: Nivel 3
LongName: Hall; PredefinedType: SPACE
Pset_SpaceCommon - IsExternal: no; Reference: Hall 171
Pset_SpaceHeaterTypeCommon - Reference: Hall 171
Qto_SpaceBaseQuantities - Height: 2.25 m; GrossVolume: 3.63487 m3; NetVolume: 3.63487 m3

# IfcSpace: Hall 208:750686, 208
In: Nivel 4
LongName: Hall; PredefinedType: SPACE
Pset_SpaceCommon - IsExternal: no; Reference: Hall 208
Pset_SpaceHeaterTypeCommon - Reference: Hall 208
Qto_SpaceBaseQuantities - Height: 2.25 m; GrossVolume: 3.63487 m3; NetVolume: 3.63487 m3

# IfcSpace: Hall 215:751030, 215
In: Nivel 4
LongName: Hall; PredefinedType: SPACE
Pset_SpaceCommon - IsExternal: no; Reference: Hall 215
Pset_SpaceHeaterTypeCommon - Reference: Hall 215
Qto_SpaceBaseQuantities - Height: 2.25 m; GrossVolume: 3.63487 m3; NetVolume: 3.63487 m3

# IfcSpace: Hall 223:751056, 223
In: Nivel 4
LongName: Hall; PredefinedType: SPACE
Pset_SpaceCommon - IsExternal: no; Reference: Hall 223
Pset_SpaceHeaterTypeCommon - Reference: Hall 223
Qto_SpaceBaseQuantities - Height: 2.25 m; GrossVolume: 3.63487 m3; NetVolume: 3.63487 m3

# IfcSpace: Hall 230:751231, 230
In: Nivel 4
LongName: Hall; PredefinedType: SPACE
Pset_SpaceCommon - IsExternal: no; Reference: Hall 230
Pset_SpaceHeaterTypeCommon - Reference: Hall 230
Qto_SpaceBaseQuantities - Height: 2.25 m; GrossVolume: 3.63487 m3; NetVolume: 3.63487 m3

# IfcSpace: Hall 266:752253, 266
In: Nivel 5
LongName: Hall; PredefinedType: SPACE
Pset_SpaceCommon - IsExternal: no; Reference: Hall 266
Pset_SpaceHeaterTypeCommon - Reference: Hall 266
Qto_SpaceBaseQuantities - Height: 2.25 m; GrossVolume: 3.63487 m3; NetVolume: 3.63487 m3

# IfcSpace: Hall 273:752597, 273
In: Nivel 5
LongName: Hall; PredefinedType: SPACE
Pset_SpaceCommon - IsExternal: no; Reference: Hall 273
Pset_SpaceHeaterTypeCommon - Reference: Hall 273
Qto_SpaceBaseQuantities - Height: 2.25 m; GrossVolume: 3.63487 m3; NetVolume: 3.63487 m3

# IfcSpace: Hall 281:752623, 281
In: Nivel 5
LongName: Hall; PredefinedType: SPACE
Pset_SpaceCommon - IsExternal: no; Reference: Hall 281
Pset_SpaceHeaterTypeCommon - Reference: Hall 281
Qto_SpaceBaseQuantities - Height: 2.25 m; GrossVolume: 3.63487 m3; NetVolume: 3.63487 m3

# IfcSpace: Hall 288:752798, 288
In: Nivel 5
LongName: Hall; PredefinedType: SPACE
Pset_SpaceCommon - IsExternal: no; Reference: Hall 288
Pset_SpaceHeaterTypeCommon - Reference: Hall 288
Qto_SpaceBaseQuantities - Height: 2.25 m; GrossVolume: 3.63487 m3; NetVolume: 3.63487 m3

# IfcSpace: Hall 324:753820, 324
In: Nivel 6
LongName: Hall; PredefinedType: SPACE
Pset_SpaceCommon - IsExternal: no; Reference: Hall 324
Pset_SpaceHeaterTypeCommon - Reference: Hall 324
Qto_SpaceBaseQuantities - Height: 2.25 m; GrossVolume: 3.63487 m3; NetVolume: 3.63487 m3

# IfcSpace: Hall 331:754164, 331
In: Nivel 6
LongName: Hall; PredefinedType: SPACE
Pset_SpaceCommon - IsExternal: no; Reference: Hall 331
Pset_SpaceHeaterTypeCommon - Reference: Hall 331
Qto_SpaceBaseQuantities - Height: 2.25 m; GrossVolume: 3.67833 m3; NetVolume: 3.67833 m3

# IfcSpace: Hall 339:754190, 339
In: Nivel 6
LongName: Hall; PredefinedType: SPACE
Pset_SpaceCommon - IsExternal: no; Reference: Hall 339
Pset_SpaceHeaterTypeCommon - Reference: Hall 339
Qto_SpaceBaseQuantities - Height: 2.25 m; GrossVolume: 3.63487 m3; NetVolume: 3.63487 m3

# IfcSpace: Hall 346:754365, 346
In: Nivel 6
LongName: Hall; PredefinedType: SPACE
Pset_SpaceCommon - IsExternal: no; Reference: Hall 346
Pset_SpaceHeaterTypeCommon - Reference: Hall 346
Qto_SpaceBaseQuantities - Height: 2.25 m; GrossVolume: 3.63487 m3; NetVolume: 3.63487 m3

# IfcSpace: Hall 35:728535, 35
In: Nivel 1
LongName: Hall; PredefinedType: SPACE
Pset_SpaceCommon - IsExternal: no; Reference: Hall 35
Pset_SpaceHeaterTypeCommon - Reference: Hall 35
Qto_SpaceBaseQuantities - Height: 2.25 m; GrossVolume: 3.63487 m3; NetVolume: 3.63487 m3

# IfcSpace: Hall 386:781399, 386
In: Nivel 1
LongName: Hall; PredefinedType: SPACE
Pset_SpaceCommon - IsExternal: no; Reference: Hall 386
Pset_SpaceHeaterTypeCommon - Reference: Hall 386
Qto_SpaceBaseQuantities - Height: 2.25 m; GrossVolume: 3.63487 m3; NetVolume: 3.63487 m3

# IfcSpace: Hall 409:791802, 409
In: Nivel 2
LongName: Hall; PredefinedType: SPACE
Pset_SpaceCommon - IsExternal: no; Reference: Hall 409
Pset_SpaceHeaterTypeCommon - Reference: Hall 409
Qto_SpaceBaseQuantities - Height: 2.25 m; GrossVolume: 3.63487 m3; NetVolume: 3.63487 m3

# IfcSpace: Hall 416:792142, 416
In: Nivel 2
LongName: Hall; PredefinedType: SPACE
Pset_SpaceCommon - IsExternal: no; Reference: Hall 416
Pset_SpaceHeaterTypeCommon - Reference: Hall 416
Qto_SpaceBaseQuantities - Height: 2.25 m; GrossVolume: 3.63487 m3; NetVolume: 3.63487 m3

# IfcSpace: Hall 424:792167, 424
In: Nivel 2
LongName: Hall; PredefinedType: SPACE
Pset_SpaceCommon - IsExternal: no; Reference: Hall 424
Pset_SpaceHeaterTypeCommon - Reference: Hall 424
Qto_SpaceBaseQuantities - Height: 2.25 m; GrossVolume: 3.63487 m3; NetVolume: 3.63487 m3

# IfcSpace: Hall 431:792340, 431
In: Nivel 2
LongName: Hall; PredefinedType: SPACE
Pset_SpaceCommon - IsExternal: no; Reference: Hall 431
Pset_SpaceHeaterTypeCommon - Reference: Hall 431
Qto_SpaceBaseQuantities - Height: 2.25 m; GrossVolume: 3.63487 m3; NetVolume: 3.63487 m3

# IfcSpace: Hall 478:872637, 478
In: Nivel 1
LongName: Hall; PredefinedType: SPACE
Pset_SpaceCommon - IsExternal: no; Reference: Hall 478
Pset_SpaceHeaterTypeCommon - Reference: Hall 478
Qto_SpaceBaseQuantities - Height: 2.25 m; GrossVolume: 3.63487 m3; NetVolume: 3.63487 m3

# IfcSpace: Hall 485:872835, 485
In: Nivel 1
LongName: Hall; PredefinedType: SPACE
Pset_SpaceCommon - IsExternal: no; Reference: Hall 485
Pset_SpaceHeaterTypeCommon - Reference: Hall 485
Qto_SpaceBaseQuantities - Height: 2.25 m; GrossVolume: 3.67836 m3; NetVolume: 3.63336 m3

# IfcSpace: Punto fijo 157:749481, 157
In: Nivel 3
LongName: Punto fijo; PredefinedType: SPACE
Pset_SpaceCommon - IsExternal: no; Reference: Punto fijo 157
Pset_SpaceHeaterTypeCommon - Reference: Punto fijo 157
Qto_SpaceBaseQuantities - Height: 2.24988 m; NetVolume: 8.14759 m3

# IfcSpace: Punto fijo 207:728450, 207
In: Nivel 1
LongName: Punto fijo; PredefinedType: SPACE
Pset_SpaceCommon - Reference: Punto fijo 207; IsExternal: no
Pset_SpaceHeaterTypeCommon - Reference: Punto fijo 207
Qto_SpaceBaseQuantities - Height: 2.25 m; NetVolume: 8.57954 m3

# IfcSpace: Punto fijo 216:751048, 216
In: Nivel 4
LongName: Punto fijo; PredefinedType: SPACE
Pset_SpaceCommon - IsExternal: no; Reference: Punto fijo 216
Pset_SpaceHeaterTypeCommon - Reference: Punto fijo 216
Qto_SpaceBaseQuantities - Height: 2.24988 m; NetVolume: 8.14759 m3

# IfcSpace: Punto fijo 274:752615, 274
In: Nivel 5
LongName: Punto fijo; PredefinedType: SPACE
Pset_SpaceCommon - IsExternal: no; Reference: Punto fijo 274
Pset_SpaceHeaterTypeCommon - Reference: Punto fijo 274
Qto_SpaceBaseQuantities - Height: 2.24988 m; NetVolume: 8.14759 m3

# IfcSpace: Punto fijo 332:754182, 332
In: Nivel 6
LongName: Punto fijo; PredefinedType: SPACE
Pset_SpaceCommon - IsExternal: no; Reference: Punto fijo 332
Pset_SpaceHeaterTypeCommon - Reference: Punto fijo 332
Qto_SpaceBaseQuantities - Height: 2.24988 m; NetVolume: 15.601 m3

# IfcSpace: Punto fijo 417:792160, 417
In: Nivel 2
LongName: Punto fijo; PredefinedType: SPACE
Pset_SpaceCommon - IsExternal: no; Reference: Punto fijo 417
Pset_SpaceHeaterTypeCommon - Reference: Punto fijo 417
Qto_SpaceBaseQuantities - Height: 2.24988 m; NetVolume: 8.14759 m3

# IfcSpace: ROPAS 507:880551, 507
In: Nivel 1
LongName: ROPAS; PredefinedType: SPACE
Pset_SpaceCommon - IsExternal: no; Reference: ROPAS 507
Pset_SpaceHeaterTypeCommon - Reference: ROPAS 507
Qto_SpaceBaseQuantities - Height: 2.35 m; NetVolume: 9.40624 m3

# IfcSpace: ROPAS 508:880554, 508
In: Nivel 1
LongName: ROPAS; PredefinedType: SPACE
Pset_SpaceCommon - IsExternal: no; Reference: ROPAS 508
Pset_SpaceHeaterTypeCommon - Reference: ROPAS 508
Qto_SpaceBaseQuantities - Height: 2.35 m; NetVolume: 9.40624 m3

# IfcSpace: ROPAS 509:880557, 509
In: Nivel 1
LongName: ROPAS; PredefinedType: SPACE
Pset_SpaceCommon - IsExternal: no; Reference: ROPAS 509
Pset_SpaceHeaterTypeCommon - Reference: ROPAS 509
Qto_SpaceBaseQuantities - Height: 2.35 m; NetVolume: 5.27703 m3

# IfcSpace: ROPAS 510:880560, 510
In: Nivel 1
LongName: ROPAS; PredefinedType: SPACE
Pset_SpaceCommon - IsExternal: no; Reference: ROPAS 510
Pset_SpaceHeaterTypeCommon - Reference: ROPAS 510
Qto_SpaceBaseQuantities - Height: 2.35 m; NetVolume: 5.27703 m3

# IfcSpace: Ropas 146:749116, 146
In: Nivel 3
LongName: Ropas; PredefinedType: SPACE
Pset_SpaceCommon - IsExternal: no; Reference: Ropas 146
Pset_SpaceHeaterTypeCommon - Reference: Ropas 146
Qto_SpaceBaseQuantities - Height: 2.22 m; NetVolume: 3.89713 m3

# IfcSpace: Ropas 153:749460, 153
In: Nivel 3
LongName: Ropas; PredefinedType: SPACE
Pset_SpaceCommon - IsExternal: no; Reference: Ropas 153
Pset_SpaceHeaterTypeCommon - Reference: Ropas 153
Qto_SpaceBaseQuantities - Height: 2.22 m; NetVolume: 3.89713 m3

# IfcSpace: Ropas 161:749486, 161
In: Nivel 3
LongName: Ropas; PredefinedType: SPACE
Pset_SpaceCommon - IsExternal: no; Reference: Ropas 161
Pset_SpaceHeaterTypeCommon - Reference: Ropas 161
Qto_SpaceBaseQuantities - Height: 2.22 m; NetVolume: 3.89713 m3

# IfcSpace: Ropas 168:749661, 168
In: Nivel 3
LongName: Ropas; PredefinedType: SPACE
Pset_SpaceCommon - IsExternal: no; Reference: Ropas 168
Pset_SpaceHeaterTypeCommon - Reference: Ropas 168
Qto_SpaceBaseQuantities - Height: 2.22 m; NetVolume: 3.89713 m3

# IfcSpace: Ropas 204:750683, 204
In: Nivel 4
LongName: Ropas; PredefinedType: SPACE
Pset_SpaceCommon - IsExternal: no; Reference: Ropas 204
Pset_SpaceHeaterTypeCommon - Reference: Ropas 204
Qto_SpaceBaseQuantities - Height: 2.22 m; NetVolume: 3.89713 m3

# IfcSpace: Ropas 212:751027, 212
In: Nivel 4
LongName: Ropas; PredefinedType: SPACE
Pset_SpaceCommon - IsExternal: no; Reference: Ropas 212
Pset_SpaceHeaterTypeCommon - Reference: Ropas 212
Qto_SpaceBaseQuantities - Height: 2.22 m; NetVolume: 3.89713 m3

# IfcSpace: Ropas 220:751053, 220
In: Nivel 4
LongName: Ropas; PredefinedType: SPACE
Pset_SpaceCommon - IsExternal: no; Reference: Ropas 220
Pset_SpaceHeaterTypeCommon - Reference: Ropas 220
Qto_SpaceBaseQuantities - Height: 2.22 m; NetVolume: 3.89713 m3

# IfcSpace: Ropas 227:751228, 227
In: Nivel 4
LongName: Ropas; PredefinedType: SPACE
Pset_SpaceCommon - IsExternal: no; Reference: Ropas 227
Pset_SpaceHeaterTypeCommon - Reference: Ropas 227
Qto_SpaceBaseQuantities - Height: 2.22 m; NetVolume: 3.89713 m3

# IfcSpace: Ropas 263:752250, 263
In: Nivel 5
LongName: Ropas; PredefinedType: SPACE
Pset_SpaceCommon - IsExternal: no; Reference: Ropas 263
Pset_SpaceHeaterTypeCommon - Reference: Ropas 263
Qto_SpaceBaseQuantities - Height: 2.22 m; NetVolume: 3.89713 m3

# IfcSpace: Ropas 270:752594, 270
In: Nivel 5
LongName: Ropas; PredefinedType: SPACE
Pset_SpaceCommon - IsExternal: no; Reference: Ropas 270
Pset_SpaceHeaterTypeCommon - Reference: Ropas 270
Qto_SpaceBaseQuantities - Height: 2.22 m; NetVolume: 3.89713 m3

# IfcSpace: Ropas 278:752620, 278
In: Nivel 5
LongName: Ropas; PredefinedType: SPACE
Pset_SpaceCommon - IsExternal: no; Reference: Ropas 278
Pset_SpaceHeaterTypeCommon - Reference: Ropas 278
Qto_SpaceBaseQuantities - Height: 2.22 m; NetVolume: 3.89713 m3

# IfcSpace: Ropas 285:752795, 285
In: Nivel 5
LongName: Ropas; PredefinedType: SPACE
Pset_SpaceCommon - IsExternal: no; Reference: Ropas 285
Pset_SpaceHeaterTypeCommon - Reference: Ropas 285
Qto_SpaceBaseQuantities - Height: 2.22 m; NetVolume: 3.89713 m3

# IfcSpace: Ropas 321:753817, 321
In: Nivel 6
LongName: Ropas; PredefinedType: SPACE
Pset_SpaceCommon - IsExternal: no; Reference: Ropas 321
Pset_SpaceHeaterTypeCommon - Reference: Ropas 321
Qto_SpaceBaseQuantities - Height: 2.22 m; NetVolume: 3.89713 m3

# IfcSpace: Ropas 328:754161, 328
In: Nivel 6
LongName: Ropas; PredefinedType: SPACE
Pset_SpaceCommon - IsExternal: no; Reference: Ropas 328
Pset_SpaceHeaterTypeCommon - Reference: Ropas 328
Qto_SpaceBaseQuantities - Height: 2.22 m; NetVolume: 3.85021 m3

# IfcSpace: Ropas 32:728532, 32
In: Nivel 1
LongName: Ropas; PredefinedType: SPACE
Pset_SpaceCommon - IsExternal: no; Reference: Ropas 32
Pset_SpaceHeaterTypeCommon - Reference: Ropas 32
Qto_SpaceBaseQuantities - Height: 2.22 m; GrossVolume: 3.94949 m3; NetVolume: 3.94949 m3

# IfcSpace: Ropas 336:754187, 336
In: Nivel 6
LongName: Ropas; PredefinedType: SPACE
Pset_SpaceCommon - IsExternal: no; Reference: Ropas 336
Pset_SpaceHeaterTypeCommon - Reference: Ropas 336
Qto_SpaceBaseQuantities - Height: 2.22 m; NetVolume: 3.89713 m3

# IfcSpace: Ropas 343:754362, 343
In: Nivel 6
LongName: Ropas; PredefinedType: SPACE
Pset_SpaceCommon - IsExternal: no; Reference: Ropas 343
Pset_SpaceHeaterTypeCommon - Reference: Ropas 343
Qto_SpaceBaseQuantities - Height: 2.22 m; NetVolume: 3.89713 m3

# IfcSpace: Ropas 389:781402, 389
In: Nivel 1
LongName: Ropas; PredefinedType: SPACE
Pset_SpaceCommon - IsExternal: no; Reference: Ropas 389
Pset_SpaceHeaterTypeCommon - Reference: Ropas 389
Qto_SpaceBaseQuantities - Height: 2.25 m; GrossVolume: 3.94949 m3; NetVolume: 3.94949 m3

# IfcSpace: Ropas 406:791799, 406
In: Nivel 2
LongName: Ropas; PredefinedType: SPACE
Pset_SpaceCommon - IsExternal: no; Reference: Ropas 406
Pset_SpaceHeaterTypeCommon - Reference: Ropas 406
Qto_SpaceBaseQuantities - Height: 2.22 m; NetVolume: 3.89713 m3

# IfcSpace: Ropas 413:792139, 413
In: Nivel 2
LongName: Ropas; PredefinedType: SPACE
Pset_SpaceCommon - IsExternal: no; Reference: Ropas 413
Pset_SpaceHeaterTypeCommon - Reference: Ropas 413
Qto_SpaceBaseQuantities - Height: 2.22 m; NetVolume: 3.89713 m3

# IfcSpace: Ropas 421:792164, 421
In: Nivel 2
LongName: Ropas; PredefinedType: SPACE
Pset_SpaceCommon - IsExternal: no; Reference: Ropas 421
Pset_SpaceHeaterTypeCommon - Reference: Ropas 421
Qto_SpaceBaseQuantities - Height: 2.22 m; NetVolume: 3.89713 m3

# IfcSpace: Ropas 428:792337, 428
In: Nivel 2
LongName: Ropas; PredefinedType: SPACE
Pset_SpaceCommon - IsExternal: no; Reference: Ropas 428
Pset_SpaceHeaterTypeCommon - Reference: Ropas 428
Qto_SpaceBaseQuantities - Height: 2.22 m; NetVolume: 3.89713 m3

# IfcSpace: Ropas 475:872634, 475
In: Nivel 1
LongName: Ropas; PredefinedType: SPACE
Pset_SpaceCommon - IsExternal: no; Reference: Ropas 475
Pset_SpaceHeaterTypeCommon - Reference: Ropas 475
Qto_SpaceBaseQuantities - Height: 2.22 m; GrossVolume: 3.94949 m3; NetVolume: 3.94949 m3

# IfcSpace: Ropas 486:1723971, 486
In: Nivel 1
LongName: Ropas; PredefinedType: SPACE
Pset_SpaceCommon - IsExternal: no; Reference: Ropas 486
Pset_SpaceHeaterTypeCommon - Reference: Ropas 486
Qto_SpaceBaseQuantities - Height: 2.22 m; GrossVolume: 3.94215 m3; NetVolume: 3.94215 m3

# IfcSpace: Sala Comedor 148:749118, 148
In: Nivel 3
LongName: Sala Comedor; PredefinedType: SPACE
Pset_SpaceCommon - IsExternal: no; Reference: Sala Comedor 148
Pset_SpaceHeaterTypeCommon - Reference: Sala Comedor 148
Qto_SpaceBaseQuantities - Height: 2.25 m; GrossVolume: 33.8833 m3; NetVolume: 33.8833 m3

# IfcSpace: Sala Comedor 155:749462, 155
In: Nivel 3
LongName: Sala Comedor; PredefinedType: SPACE
Pset_SpaceCommon - IsExternal: no; Reference: Sala Comedor 155
Pset_SpaceHeaterTypeCommon - Reference: Sala Comedor 155
Qto_SpaceBaseQuantities - Height: 2.25 m; GrossVolume: 33.8833 m3; NetVolume: 33.8833 m3

# IfcSpace: Sala Comedor 163:749488, 163
In: Nivel 3
LongName: Sala Comedor; PredefinedType: SPACE
Pset_SpaceCommon - IsExternal: no; Reference: Sala Comedor 163
Pset_SpaceHeaterTypeCommon - Reference: Sala Comedor 163
Qto_SpaceBaseQuantities - Height: 2.25 m; GrossVolume: 33.8833 m3; NetVolume: 33.8833 m3

# IfcSpace: Sala Comedor 170:749663, 170
In: Nivel 3
LongName: Sala Comedor; PredefinedType: SPACE
Pset_SpaceCommon - IsExternal: no; Reference: Sala Comedor 170
Pset_SpaceHeaterTypeCommon - Reference: Sala Comedor 170
Qto_SpaceBaseQuantities - Height: 2.25 m; GrossVolume: 33.8833 m3; NetVolume: 33.8833 m3

# IfcSpace: Sala Comedor 206:750685, 206
In: Nivel 4
LongName: Sala Comedor; PredefinedType: SPACE
Pset_SpaceCommon - IsExternal: no; Reference: Sala Comedor 206
Pset_SpaceHeaterTypeCommon - Reference: Sala Comedor 206
Qto_SpaceBaseQuantities - Height: 2.25 m; GrossVolume: 33.8833 m3; NetVolume: 33.8833 m3

# IfcSpace: Sala Comedor 214:751029, 214
In: Nivel 4
LongName: Sala Comedor; PredefinedType: SPACE
Pset_SpaceCommon - IsExternal: no; Reference: Sala Comedor 214
Pset_SpaceHeaterTypeCommon - Reference: Sala Comedor 214
Qto_SpaceBaseQuantities - Height: 2.25 m; GrossVolume: 33.8833 m3; NetVolume: 33.8833 m3

# IfcSpace: Sala Comedor 222:751055, 222
In: Nivel 4
LongName: Sala Comedor; PredefinedType: SPACE
Pset_SpaceCommon - IsExternal: no; Reference: Sala Comedor 222
Pset_SpaceHeaterTypeCommon - Reference: Sala Comedor 222
Qto_SpaceBaseQuantities - Height: 2.25 m; GrossVolume: 33.8833 m3; NetVolume: 33.8833 m3

# IfcSpace: Sala Comedor 229:751230, 229
In: Nivel 4
LongName: Sala Comedor; PredefinedType: SPACE
Pset_SpaceCommon - IsExternal: no; Reference: Sala Comedor 229
Pset_SpaceHeaterTypeCommon - Reference: Sala Comedor 229
Qto_SpaceBaseQuantities - Height: 2.25 m; GrossVolume: 33.8833 m3; NetVolume: 33.8833 m3

# IfcSpace: Sala Comedor 265:752252, 265
In: Nivel 5
LongName: Sala Comedor; PredefinedType: SPACE
Pset_SpaceCommon - IsExternal: no; Reference: Sala Comedor 265
Pset_SpaceHeaterTypeCommon - Reference: Sala Comedor 265
Qto_SpaceBaseQuantities - Height: 2.25 m; GrossVolume: 33.8833 m3; NetVolume: 33.8833 m3

# IfcSpace: Sala Comedor 272:752596, 272
In: Nivel 5
LongName: Sala Comedor; PredefinedType: SPACE
Pset_SpaceCommon - IsExternal: no; Reference: Sala Comedor 272
Pset_SpaceHeaterTypeCommon - Reference: Sala Comedor 272
Qto_SpaceBaseQuantities - Height: 2.25 m; GrossVolume: 33.8833 m3; NetVolume: 33.8833 m3

# IfcSpace: Sala Comedor 280:752622, 280
In: Nivel 5
LongName: Sala Comedor; PredefinedType: SPACE
Pset_SpaceCommon - IsExternal: no; Reference: Sala Comedor 280
Pset_SpaceHeaterTypeCommon - Reference: Sala Comedor 280
Qto_SpaceBaseQuantities - Height: 2.25 m; GrossVolume: 33.8833 m3; NetVolume: 33.8833 m3

# IfcSpace: Sala Comedor 287:752797, 287
In: Nivel 5
LongName: Sala Comedor; PredefinedType: SPACE
Pset_SpaceCommon - IsExternal: no; Reference: Sala Comedor 287
Pset_SpaceHeaterTypeCommon - Reference: Sala Comedor 287
Qto_SpaceBaseQuantities - Height: 2.25 m; GrossVolume: 33.8833 m3; NetVolume: 33.8833 m3

# IfcSpace: Sala Comedor 323:753819, 323
In: Nivel 6
LongName: Sala Comedor; PredefinedType: SPACE
Pset_SpaceCommon - IsExternal: no; Reference: Sala Comedor 323
Pset_SpaceHeaterTypeCommon - Reference: Sala Comedor 323
Qto_SpaceBaseQuantities - Height: 2.25 m; GrossVolume: 33.8833 m3; NetVolume: 33.8833 m3

# IfcSpace: Sala Comedor 330:754163, 330
In: Nivel 6
LongName: Sala Comedor; PredefinedType: SPACE
Pset_SpaceCommon - IsExternal: no; Reference: Sala Comedor 330
Pset_SpaceHeaterTypeCommon - Reference: Sala Comedor 330
Qto_SpaceBaseQuantities - Height: 2.25 m; GrossVolume: 33.8833 m3; NetVolume: 33.8833 m3

# IfcSpace: Sala Comedor 338:754189, 338
In: Nivel 6
LongName: Sala Comedor; PredefinedType: SPACE
Pset_SpaceCommon - IsExternal: no; Reference: Sala Comedor 338
Pset_SpaceHeaterTypeCommon - Reference: Sala Comedor 338
Qto_SpaceBaseQuantities - Height: 2.25 m; GrossVolume: 33.8833 m3; NetVolume: 33.8833 m3

# IfcSpace: Sala Comedor 345:754364, 345
In: Nivel 6
LongName: Sala Comedor; PredefinedType: SPACE
Pset_SpaceCommon - IsExternal: no; Reference: Sala Comedor 345
Pset_SpaceHeaterTypeCommon - Reference: Sala Comedor 345
Qto_SpaceBaseQuantities - Height: 2.25 m; GrossVolume: 33.8833 m3; NetVolume: 33.8833 m3

# IfcSpace: Sala Comedor 34:728534, 34
In: Nivel 1
LongName: Sala Comedor; PredefinedType: SPACE
Pset_SpaceCommon - IsExternal: no; Reference: Sala Comedor 34
Pset_SpaceHeaterTypeCommon - Reference: Sala Comedor 34
Qto_SpaceBaseQuantities - Height: 2.25 m; GrossVolume: 33.8833 m3; NetVolume: 33.8833 m3

# IfcSpace: Sala Comedor 388:781401, 388
In: Nivel 1
LongName: Sala Comedor; PredefinedType: SPACE
Pset_SpaceCommon - IsExternal: no; Reference: Sala Comedor 388
Pset_SpaceHeaterTypeCommon - Reference: Sala Comedor 388
Qto_SpaceBaseQuantities - Height: 2.25 m; GrossVolume: 25.0071 m3; NetVolume: 25.0071 m3

# IfcSpace: Sala Comedor 408:791801, 408
In: Nivel 2
LongName: Sala Comedor; PredefinedType: SPACE
Pset_SpaceCommon - IsExternal: no; Reference: Sala Comedor 408
Pset_SpaceHeaterTypeCommon - Reference: Sala Comedor 408
Qto_SpaceBaseQuantities - Height: 2.25 m; GrossVolume: 33.8833 m3; NetVolume: 33.8833 m3

# IfcSpace: Sala Comedor 415:792141, 415
In: Nivel 2
LongName: Sala Comedor; PredefinedType: SPACE
Pset_SpaceCommon - IsExternal: no; Reference: Sala Comedor 415
Pset_SpaceHeaterTypeCommon - Reference: Sala Comedor 415
Qto_SpaceBaseQuantities - Height: 2.25 m; GrossVolume: 33.8833 m3; NetVolume: 33.8833 m3

# IfcSpace: Sala Comedor 423:792166, 423
In: Nivel 2
LongName: Sala Comedor; PredefinedType: SPACE
Pset_SpaceCommon - IsExternal: no; Reference: Sala Comedor 423
Pset_SpaceHeaterTypeCommon - Reference: Sala Comedor 423
Qto_SpaceBaseQuantities - Height: 2.25 m; GrossVolume: 33.8833 m3; NetVolume: 33.8833 m3

# IfcSpace: Sala Comedor 430:792339, 430
In: Nivel 2
LongName: Sala Comedor; PredefinedType: SPACE
Pset_SpaceCommon - IsExternal: no; Reference: Sala Comedor 430
Pset_SpaceHeaterTypeCommon - Reference: Sala Comedor 430
Qto_SpaceBaseQuantities - Height: 2.25 m; GrossVolume: 33.8833 m3; NetVolume: 33.8833 m3

# IfcSpace: Sala Comedor 477:872636, 477
In: Nivel 1
LongName: Sala Comedor; PredefinedType: SPACE
Pset_SpaceCommon - IsExternal: no; Reference: Sala Comedor 477
Pset_SpaceHeaterTypeCommon - Reference: Sala Comedor 477
Qto_SpaceBaseQuantities - Height: 2.25 m; GrossVolume: 33.8833 m3; NetVolume: 33.8833 m3

# IfcSpace: Sala Comedor 484:872834, 484
In: Nivel 1
LongName: Sala Comedor; PredefinedType: SPACE
Pset_SpaceCommon - IsExternal: no; Reference: Sala Comedor 484
Pset_SpaceHeaterTypeCommon - Reference: Sala Comedor 484
Qto_SpaceBaseQuantities - Height: 2.25 m; GrossVolume: 33.8833 m3; NetVolume: 33.8833 m3

# IfcBuildingElementProxy: D3020 - Calentador de agua - Metal1:D3020 - Calentador de agua - Metal (2)
Type - Material: Calentador, Plastic - Bradford White - UHMW Black, <Unnamed>
Type - Pset_BuildingElementProxyCommon - IsExternal: no
Type - Pset_ManufacturerTypeInformation - Manufacturer: Bradford White
Classification: 21-04 20 10 20 Uniformat (Uniformat)
Pset_BuildingElementProxyCommon - Reference: D3020 - Calentador de agua - Metal
Pset_EnvironmentalImpactIndicators - Reference: D3020 - Calentador de agua - Metal
Qto_BuildingElementProxyQuantities - NetSurfaceArea: 1.42632 m2; NetVolume: 0.0907033 m3
Name (D3020 - Calentador de agua - Metal1:D3020 - Calentador de agua - Metal:...) | In
728698 | 32 | Pset_BuildingElementProxyCommon - IsExternal: yes; Group: Mechanical Exhaust Air 3
872740 | 475

# IfcBuildingElementProxy: D3020 - Calentador de agua - Metal1:D3020 - Calentador de agua - Metal 2 (2)
Type - Material: Calentador, Plastic - Bradford White - UHMW Black, <Unnamed>
Type - Pset_BuildingElementProxyCommon - IsExternal: no
Type - Pset_ManufacturerTypeInformation - Manufacturer: Bradford White
Classification: 21-04 20 10 20 Uniformat (Uniformat)
Pset_BuildingElementProxyCommon - Reference: D3020 - Calentador de agua - Metal 2
Pset_EnvironmentalImpactIndicators - Reference: D3020 - Calentador de agua - Metal 2
Qto_BuildingElementProxyQuantities - NetSurfaceArea: 1.42632 m2; NetVolume: 0.0907033 m3
Name (D3020 - Calentador de agua - Metal1:D3020 - Calentador de agua - Metal 2:...) | In
781356 | 389 | Pset_BuildingElementProxyCommon - IsExternal: yes; Group: Mechanical Exhaust Air 2
872938 | 486

# IfcBuildingElementProxy: D3020 - Calentador de agua - Metal:D3020 - Calentador de agua - Metal (20)
Type - Material: Calentador, Plastic - Bradford White - UHMW Black, Metal - Bradford White - Steel Painted 421 Grey, <Unnamed>, Metal - Bradford White - Steel
Type - Pset_BuildingElementProxyCommon - IsExternal: no
Type - Pset_ManufacturerTypeInformation - Manufacturer: Bradford White
Classification: 21-04 20 10 20 Uniformat (Uniformat)
Pset_BuildingElementProxyCommon - Reference: D3020 - Calentador de agua - Metal
Pset_EnvironmentalImpactIndicators - Reference: D3020 - Calentador de agua - Metal
Qto_BuildingElementProxyQuantities - NetSurfaceArea: 1.42632 m2; NetVolume: 0.0907033 m3
Name (D3020 - Calentador de agua - Metal:D3020 - Calentador de agua - Metal:...) | In | Group
749247 | 146 | Mechanical Exhaust Air 25 | Pset_BuildingElementProxyCommon - IsExternal: yes
749413 | 153 | Mechanical Exhaust Air 27
749615 | 161 | Mechanical Exhaust Air 29
749789 | 168 | Mechanical Exhaust Air 31
750814 | 204 | Mechanical Exhaust Air 41
750980 | 212 | Mechanical Exhaust Air 43
751182 | 220 | Mechanical Exhaust Air 45
751356 | 227 | Mechanical Exhaust Air 47
752381 | 263 | Mechanical Exhaust Air 57
752547 | 270 | Mechanical Exhaust Air 59
752749 | 278 | Mechanical Exhaust Air 61
752923 | 285 | Mechanical Exhaust Air 63
753948 | 321 | Mechanical Exhaust Air 73
754114 | 328 | Mechanical Exhaust Air 75
754316 | 336 | Mechanical Exhaust Air 77
754490 | 343 | Mechanical Exhaust Air 79
791928 | 406 | Mechanical Exhaust Air 7
792093 | 413 | Mechanical Exhaust Air 10
792291 | 421 | Mechanical Exhaust Air 13
792464 | 428 | Mechanical Exhaust Air 15

# IfcBuildingElementProxy: ESCALERA gato.0001:B1080-0.60m-Escalera de gato-metálica, ESCALERA gato.0001:B1080-0.60m-Escalera de gato-metálica:2014640
In: Nivel 2
Type - Material: <Unnamed>
Type - Pset_BuildingElementProxyCommon - IsExternal: no
Classification: 21-02 10 80 80 Uniformat (Uniformat)
Pset_BuildingElementProxyCommon - IsExternal: yes; Reference: B1080-0.60m-Escalera de gato-metálica
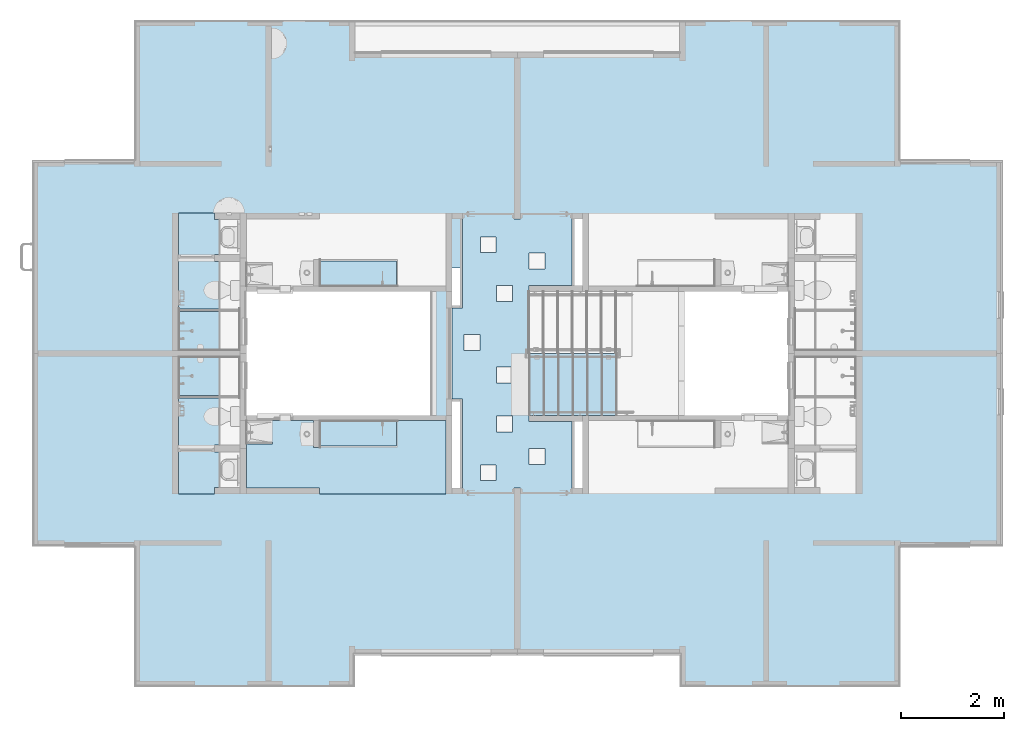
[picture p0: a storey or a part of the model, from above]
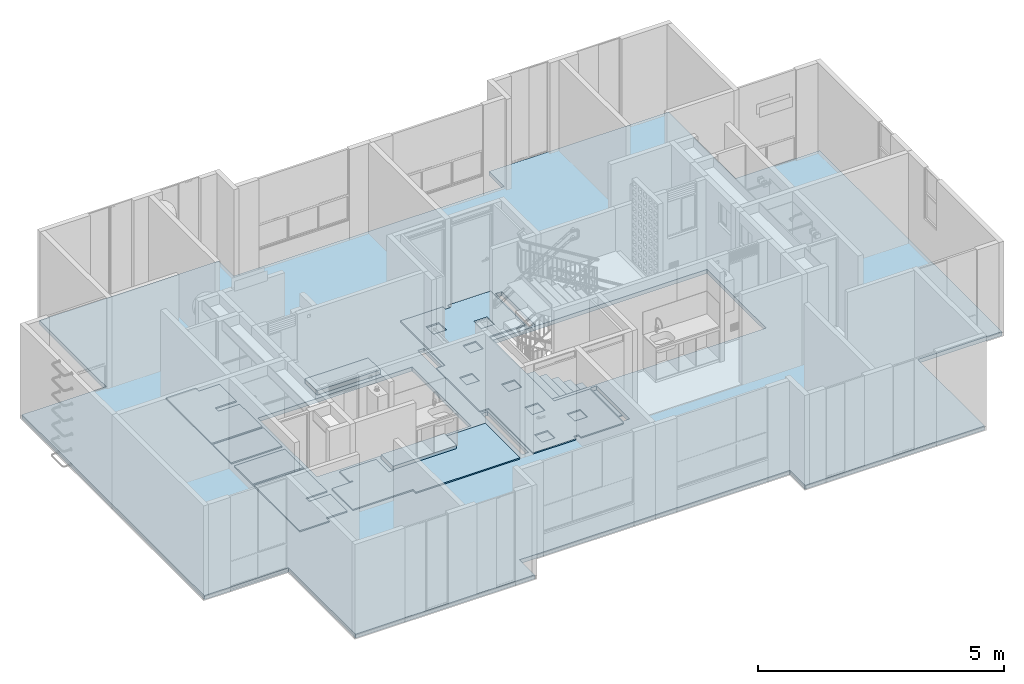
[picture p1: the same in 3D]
Properties of the parts of a building model (IFC4), part 2 of 6

# IfcBuildingElementProxy: ESCALERA gato.0001:B1080-0.60m-Escalera de gato-metálica, ESCALERA gato.0001:B1080-0.60m-Escalera de gato-metálica:2014640
Pset_EnvironmentalImpactIndicators - Reference: B1080-0.60m-Escalera de gato-metálica
Qto_BuildingElementProxyQuantities - NetSurfaceArea: 0.880911 m2; NetVolume: 0.00787152 m3

# IfcBuildingElementProxy: Interruptor Conmutable:Caja 5800, Interruptor Conmutable:Caja 5800:2062992
In: 408
Type - Material: <Unnamed>
Type - Pset_BuildingElementProxyCommon - IsExternal: no
Classification: D5040.10 Uniformat (Uniformat)
Pset_BuildingElementProxyCommon - Reference: Caja 5800
Pset_EnvironmentalImpactIndicators - Reference: Caja 5800
Qto_BuildingElementProxyQuantities - NetSurfaceArea: 0.0435184 m2; NetVolume: 0.000299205 m3

# IfcBuildingElementProxy: Interruptor Sencillo:Caja 2400, Interruptor Sencillo:Caja 2400:2061446
In: 409
Type - Material: <Unnamed>
Type - Pset_BuildingElementProxyCommon - IsExternal: no
Classification: D5040.10 Uniformat (Uniformat)
Pset_BuildingElementProxyCommon - Reference: Caja 2400
Pset_EnvironmentalImpactIndicators - Reference: Caja 2400
Qto_BuildingElementProxyQuantities - NetSurfaceArea: 0.0542377 m2; NetVolume: 0.000438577 m3

# IfcBuildingElementProxy: Model Text:600mm Arial, Model Text:600mm Arial:2063015
In: Nivel 1
Type - Pset_BuildingElementProxyCommon - IsExternal: no
Pset_BuildingElementProxyCommon - Reference: 600mm Arial
Pset_EnvironmentalImpactIndicators - Reference: 600mm Arial
Qto_BuildingElementProxyQuantities - NetSurfaceArea: 7.70456 m2; NetVolume: 0.186583 m3

# IfcBuildingElementProxy: Toma Citófono:Caja 5800, Toma Citófono:Caja 5800:2059904
In: 408
Type - Material: <Unnamed>
Type - Pset_BuildingElementProxyCommon - IsExternal: no
Classification: D6020 Uniformat (Uniformat)
Pset_BuildingElementProxyCommon - Reference: Caja 5800
Pset_EnvironmentalImpactIndicators - Reference: Caja 5800
Qto_BuildingElementProxyQuantities - NetSurfaceArea: 0.0456628 m2; NetVolume: 0.00030405 m3

# IfcBuildingElementProxy: Toma Doble Normal (Esclava):Caja 5800, Toma Doble Normal (Esclava):Caja 5800:2058754
In: 408
Type - Material: <Unnamed>
Type - Pset_BuildingElementProxyCommon - IsExternal: no
Classification: D5030.50 Uniformat (Uniformat)
Pset_BuildingElementProxyCommon - Reference: Caja 5800
Pset_EnvironmentalImpactIndicators - Reference: Caja 5800
Qto_BuildingElementProxyQuantities - NetSurfaceArea: 0.0456628 m2; NetVolume: 0.00030405 m3

# IfcBuildingElementProxy: Toma Doble Normal:Caja 2400, Toma Doble Normal:Caja 2400:2056649
In: 408
Type - Material: <Unnamed>
Type - Pset_BuildingElementProxyCommon - IsExternal: no
Classification: D5030.50 Uniformat (Uniformat)
Pset_BuildingElementProxyCommon - Reference: Caja 2400
Pset_EnvironmentalImpactIndicators - Reference: Caja 2400
Qto_BuildingElementProxyQuantities - NetSurfaceArea: 0.0563821 m2; NetVolume: 0.000443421 m3

# IfcCovering: Compound Ceiling:C1070 - 0.02m - Plafón - Drywall (24)
Type - PredefinedType: CEILING
Type - Pset_CoveringCommon - IsExternal: no
Classification: 21-03 10 70 20 Uniformat (Uniformat); Material: Plasterboard
Pset_CoveringCommon - Reference: C1070 - 0.02m - Plafón - Drywall
Pset_EnvironmentalImpactIndicators - Reference: C1070 - 0.02m - Plafón - Drywall
Name (Compound Ceiling:C1070 - 0.02m - Plafón - Drywall:...) | In | Width (m) | GrossArea (m2)
728658 | 30 | 0.41 | 0.2788
749220 | 144 | 0.69 | 0.2829
749386 | 151 | 0.41 | 0.2829
749588 | 159 | 0.41 | 0.2829
749762 | 166 | 0.69 | 0.2829
750787 | 202 | 0.69 | 0.2829
750953 | 210 | 0.41 | 0.2829
751155 | 218 | 0.41 | 0.2829
751329 | 225 | 0.69 | 0.2829
752354 | 261 | 0.69 | 0.2829
752520 | 268 | 0.41 | 0.2829
752722 | 276 | 0.41 | 0.2829
752896 | 283 | 0.69 | 0.2829
753921 | 319 | 0.69 | 0.2829
754087 | 326 | 0.41 | 0.2829
754289 | 334 | 0.41 | 0.2829
754463 | 341 | 0.69 | 0.2829
781329 | 384 | 0.685 | 0.28085
791901 | 404 | 0.69 | 0.2829
792066 | 411 | 0.41 | 0.2829
792264 | 419 | 0.41 | 0.2829
792437 | 426 | 0.69 | 0.2829
948610 | 473 | 0.68 | 0.2788
948639 | 480 | 0.41 | 0.2788

# IfcDistributionPort (223)
Description: Flow
Name | FlowDirection | PredefinedType | SystemType
Port_728676_5 | SOURCEANDSINK | PIPE | SEWAGE
Port_728676_6 | SOURCEANDSINK | PIPE | HEATING
Port_728676_7 | SOURCEANDSINK | PIPE | HEATING
Port_728676_8 | SOURCEANDSINK | PIPE | SEWAGE
InPort_728698_1 | SINK | PIPE | USERDEFINED
OutPort_728698_2 | SOURCE | PIPE | DOMESTICHOTWATER
InPort_728698_3 | SINK | PIPE | DOMESTICCOLDWATER
OutPort_728698_4 | SOURCE | DUCT | EXHAUST | Group: Mechanical Exhaust Air 3
Port_749238_5 | SOURCEANDSINK | PIPE | SEWAGE
Port_749238_6 | SOURCEANDSINK | PIPE | HEATING
Port_749238_7 | SOURCEANDSINK | PIPE | HEATING
Port_749238_8 | SOURCEANDSINK | PIPE | SEWAGE
InPort_749247_1 | SINK | PIPE | USERDEFINED
OutPort_749247_2 | SOURCE | PIPE | DOMESTICHOTWATER
InPort_749247_3 | SINK | PIPE | DOMESTICCOLDWATER
OutPort_749247_4 | SOURCE | DUCT | EXHAUST | Group: Mechanical Exhaust Air 25
Port_749275_1 | SOURCEANDSINK | PIPE | HEATING
Port_749404_5 | SOURCEANDSINK | PIPE | SEWAGE
Port_749404_6 | SOURCEANDSINK | PIPE | HEATING
Port_749404_7 | SOURCEANDSINK | PIPE | HEATING
Port_749404_8 | SOURCEANDSINK | PIPE | SEWAGE
InPort_749413_1 | SINK | PIPE | USERDEFINED
OutPort_749413_2 | SOURCE | PIPE | DOMESTICHOTWATER
InPort_749413_3 | SINK | PIPE | DOMESTICCOLDWATER
OutPort_749413_4 | SOURCE | DUCT | EXHAUST | Group: Mechanical Exhaust Air 27
Port_749441_1 | SOURCEANDSINK | PIPE | HEATING
Port_749606_5 | SOURCEANDSINK | PIPE | SEWAGE
Port_749606_6 | SOURCEANDSINK | PIPE | HEATING
Port_749606_7 | SOURCEANDSINK | PIPE | HEATING
Port_749606_8 | SOURCEANDSINK | PIPE | SEWAGE
InPort_749615_1 | SINK | PIPE | USERDEFINED
OutPort_749615_2 | SOURCE | PIPE | DOMESTICHOTWATER
InPort_749615_3 | SINK | PIPE | DOMESTICCOLDWATER
OutPort_749615_4 | SOURCE | DUCT | EXHAUST | Group: Mechanical Exhaust Air 29
Port_749643_1 | SOURCEANDSINK | PIPE | HEATING
Port_749780_5 | SOURCEANDSINK | PIPE | SEWAGE
Port_749780_6 | SOURCEANDSINK | PIPE | HEATING
Port_749780_7 | SOURCEANDSINK | PIPE | HEATING
Port_749780_8 | SOURCEANDSINK | PIPE | SEWAGE
InPort_749789_1 | SINK | PIPE | USERDEFINED
OutPort_749789_2 | SOURCE | PIPE | DOMESTICHOTWATER
InPort_749789_3 | SINK | PIPE | DOMESTICCOLDWATER
OutPort_749789_4 | SOURCE | DUCT | EXHAUST | Group: Mechanical Exhaust Air 31
Port_749817_1 | SOURCEANDSINK | PIPE | HEATING
Port_750805_5 | SOURCEANDSINK | PIPE | SEWAGE
Port_750805_6 | SOURCEANDSINK | PIPE | HEATING
Port_750805_7 | SOURCEANDSINK | PIPE | HEATING
Port_750805_8 | SOURCEANDSINK | PIPE | SEWAGE
InPort_750814_1 | SINK | PIPE | USERDEFINED
OutPort_750814_2 | SOURCE | PIPE | DOMESTICHOTWATER
InPort_750814_3 | SINK | PIPE | DOMESTICCOLDWATER
OutPort_750814_4 | SOURCE | DUCT | EXHAUST | Group: Mechanical Exhaust Air 41
Port_750842_1 | SOURCEANDSINK | PIPE | HEATING
Port_750971_5 | SOURCEANDSINK | PIPE | SEWAGE
Port_750971_6 | SOURCEANDSINK | PIPE | HEATING
Port_750971_7 | SOURCEANDSINK | PIPE | HEATING
Port_750971_8 | SOURCEANDSINK | PIPE | SEWAGE
InPort_750980_1 | SINK | PIPE | USERDEFINED
OutPort_750980_2 | SOURCE | PIPE | DOMESTICHOTWATER
InPort_750980_3 | SINK | PIPE | DOMESTICCOLDWATER
OutPort_750980_4 | SOURCE | DUCT | EXHAUST | Group: Mechanical Exhaust Air 43
Port_751008_1 | SOURCEANDSINK | PIPE | HEATING
Port_751173_5 | SOURCEANDSINK | PIPE | SEWAGE
Port_751173_6 | SOURCEANDSINK | PIPE | HEATING
Port_751173_7 | SOURCEANDSINK | PIPE | HEATING
Port_751173_8 | SOURCEANDSINK | PIPE | SEWAGE
InPort_751182_1 | SINK | PIPE | USERDEFINED
OutPort_751182_2 | SOURCE | PIPE | DOMESTICHOTWATER
InPort_751182_3 | SINK | PIPE | DOMESTICCOLDWATER
OutPort_751182_4 | SOURCE | DUCT | EXHAUST | Group: Mechanical Exhaust Air 45
Port_751210_1 | SOURCEANDSINK | PIPE | HEATING
Port_751347_5 | SOURCEANDSINK | PIPE | SEWAGE
Port_751347_6 | SOURCEANDSINK | PIPE | HEATING
Port_751347_7 | SOURCEANDSINK | PIPE | HEATING
Port_751347_8 | SOURCEANDSINK | PIPE | SEWAGE
InPort_751356_1 | SINK | PIPE | USERDEFINED
OutPort_751356_2 | SOURCE | PIPE | DOMESTICHOTWATER
InPort_751356_3 | SINK | PIPE | DOMESTICCOLDWATER
OutPort_751356_4 | SOURCE | DUCT | EXHAUST | Group: Mechanical Exhaust Air 47
Port_751384_1 | SOURCEANDSINK | PIPE | HEATING
Port_752372_5 | SOURCEANDSINK | PIPE | SEWAGE
Port_752372_6 | SOURCEANDSINK | PIPE | HEATING
Port_752372_7 | SOURCEANDSINK | PIPE | HEATING
Port_752372_8 | SOURCEANDSINK | PIPE | SEWAGE
InPort_752381_1 | SINK | PIPE | USERDEFINED
OutPort_752381_2 | SOURCE | PIPE | DOMESTICHOTWATER
InPort_752381_3 | SINK | PIPE | DOMESTICCOLDWATER
OutPort_752381_4 | SOURCE | DUCT | EXHAUST | Group: Mechanical Exhaust Air 57
Port_752409_1 | SOURCEANDSINK | PIPE | HEATING
Port_752538_5 | SOURCEANDSINK | PIPE | SEWAGE
Port_752538_6 | SOURCEANDSINK | PIPE | HEATING
Port_752538_7 | SOURCEANDSINK | PIPE | HEATING
Port_752538_8 | SOURCEANDSINK | PIPE | SEWAGE
InPort_752547_1 | SINK | PIPE | USERDEFINED
OutPort_752547_2 | SOURCE | PIPE | DOMESTICHOTWATER
InPort_752547_3 | SINK | PIPE | DOMESTICCOLDWATER
OutPort_752547_4 | SOURCE | DUCT | EXHAUST | Group: Mechanical Exhaust Air 59
Port_752575_1 | SOURCEANDSINK | PIPE | HEATING
Port_752740_5 | SOURCEANDSINK | PIPE | SEWAGE
Port_752740_6 | SOURCEANDSINK | PIPE | HEATING
Port_752740_7 | SOURCEANDSINK | PIPE | HEATING
Port_752740_8 | SOURCEANDSINK | PIPE | SEWAGE
InPort_752749_1 | SINK | PIPE | USERDEFINED
OutPort_752749_2 | SOURCE | PIPE | DOMESTICHOTWATER
InPort_752749_3 | SINK | PIPE | DOMESTICCOLDWATER
OutPort_752749_4 | SOURCE | DUCT | EXHAUST | Group: Mechanical Exhaust Air 61
Port_752777_1 | SOURCEANDSINK | PIPE | HEATING
Port_752914_5 | SOURCEANDSINK | PIPE | SEWAGE
Port_752914_6 | SOURCEANDSINK | PIPE | HEATING
Port_752914_7 | SOURCEANDSINK | PIPE | HEATING
Port_752914_8 | SOURCEANDSINK | PIPE | SEWAGE
InPort_752923_1 | SINK | PIPE | USERDEFINED
OutPort_752923_2 | SOURCE | PIPE | DOMESTICHOTWATER
InPort_752923_3 | SINK | PIPE | DOMESTICCOLDWATER
OutPort_752923_4 | SOURCE | DUCT | EXHAUST | Group: Mechanical Exhaust Air 63
Port_752951_1 | SOURCEANDSINK | PIPE | HEATING
Port_753939_5 | SOURCEANDSINK | PIPE | SEWAGE
Port_753939_6 | SOURCEANDSINK | PIPE | HEATING
Port_753939_7 | SOURCEANDSINK | PIPE | HEATING
Port_753939_8 | SOURCEANDSINK | PIPE | SEWAGE
InPort_753948_1 | SINK | PIPE | USERDEFINED
OutPort_753948_2 | SOURCE | PIPE | DOMESTICHOTWATER
InPort_753948_3 | SINK | PIPE | DOMESTICCOLDWATER
OutPort_753948_4 | SOURCE | DUCT | EXHAUST | Group: Mechanical Exhaust Air 73
Port_753976_1 | SOURCEANDSINK | PIPE | HEATING
Port_754105_5 | SOURCEANDSINK | PIPE | SEWAGE
Port_754105_6 | SOURCEANDSINK | PIPE | HEATING
Port_754105_7 | SOURCEANDSINK | PIPE | HEATING
Port_754105_8 | SOURCEANDSINK | PIPE | SEWAGE
InPort_754114_1 | SINK | PIPE | USERDEFINED
OutPort_754114_2 | SOURCE | PIPE | DOMESTICHOTWATER
InPort_754114_3 | SINK | PIPE | DOMESTICCOLDWATER
OutPort_754114_4 | SOURCE | DUCT | EXHAUST | Group: Mechanical Exhaust Air 75
Port_754142_1 | SOURCEANDSINK | PIPE | HEATING
Port_754307_5 | SOURCEANDSINK | PIPE | SEWAGE
Port_754307_6 | SOURCEANDSINK | PIPE | HEATING
Port_754307_7 | SOURCEANDSINK | PIPE | HEATING
Port_754307_8 | SOURCEANDSINK | PIPE | SEWAGE
InPort_754316_1 | SINK | PIPE | USERDEFINED
OutPort_754316_2 | SOURCE | PIPE | DOMESTICHOTWATER
InPort_754316_3 | SINK | PIPE | DOMESTICCOLDWATER
OutPort_754316_4 | SOURCE | DUCT | EXHAUST | Group: Mechanical Exhaust Air 77
Port_754344_1 | SOURCEANDSINK | PIPE | HEATING
Port_754481_5 | SOURCEANDSINK | PIPE | SEWAGE
Port_754481_6 | SOURCEANDSINK | PIPE | HEATING
Port_754481_7 | SOURCEANDSINK | PIPE | HEATING
Port_754481_8 | SOURCEANDSINK | PIPE | SEWAGE
InPort_754490_1 | SINK | PIPE | USERDEFINED
OutPort_754490_2 | SOURCE | PIPE | DOMESTICHOTWATER
InPort_754490_3 | SINK | PIPE | DOMESTICCOLDWATER
OutPort_754490_4 | SOURCE | DUCT | EXHAUST | Group: Mechanical Exhaust Air 79
Port_754518_1 | SOURCEANDSINK | PIPE | HEATING
Port_781347_5 | SOURCEANDSINK | PIPE | SEWAGE
Port_781347_6 | SOURCEANDSINK | PIPE | HEATING
Port_781347_7 | SOURCEANDSINK | PIPE | HEATING
Port_781347_8 | SOURCEANDSINK | PIPE | SEWAGE
InPort_781356_1 | SINK | PIPE | USERDEFINED
OutPort_781356_2 | SOURCE | PIPE | DOMESTICHOTWATER
InPort_781356_3 | SINK | PIPE | DOMESTICCOLDWATER
OutPort_781356_4 | SOURCE | DUCT | EXHAUST | Group: Mechanical Exhaust Air 2
Port_791919_5 | SOURCEANDSINK | PIPE | SEWAGE
Port_791919_6 | SOURCEANDSINK | PIPE | HEATING
Port_791919_7 | SOURCEANDSINK | PIPE | HEATING
Port_791919_8 | SOURCEANDSINK | PIPE | SEWAGE
InPort_791928_1 | SINK | PIPE | USERDEFINED
OutPort_791928_2 | SOURCE | PIPE | DOMESTICHOTWATER
InPort_791928_3 | SINK | PIPE | DOMESTICCOLDWATER
OutPort_791928_4 | SOURCE | DUCT | EXHAUST | Group: Mechanical Exhaust Air 7
Port_791956_1 | SOURCEANDSINK | PIPE | HEATING
Port_792084_5 | SOURCEANDSINK | PIPE | SEWAGE
Port_792084_6 | SOURCEANDSINK | PIPE | HEATING
Port_792084_7 | SOURCEANDSINK | PIPE | HEATING
Port_792084_8 | SOURCEANDSINK | PIPE | SEWAGE
InPort_792093_1 | SINK | PIPE | USERDEFINED
OutPort_792093_2 | SOURCE | PIPE | DOMESTICHOTWATER
InPort_792093_3 | SINK | PIPE | DOMESTICCOLDWATER
OutPort_792093_4 | SOURCE | DUCT | EXHAUST | Group: Mechanical Exhaust Air 10
Port_792121_1 | SOURCEANDSINK | PIPE | HEATING
Port_792282_5 | SOURCEANDSINK | PIPE | SEWAGE
Port_792282_6 | SOURCEANDSINK | PIPE | HEATING
Port_792282_7 | SOURCEANDSINK | PIPE | HEATING
Port_792282_8 | SOURCEANDSINK | PIPE | SEWAGE
InPort_792291_1 | SINK | PIPE | USERDEFINED
OutPort_792291_2 | SOURCE | PIPE | DOMESTICHOTWATER
InPort_792291_3 | SINK | PIPE | DOMESTICCOLDWATER
OutPort_792291_4 | SOURCE | DUCT | EXHAUST | Group: Mechanical Exhaust Air 13
Port_792319_1 | SOURCEANDSINK | PIPE | HEATING
Port_792455_5 | SOURCEANDSINK | PIPE | SEWAGE
Port_792455_6 | SOURCEANDSINK | PIPE | HEATING
Port_792455_7 | SOURCEANDSINK | PIPE | HEATING
Port_792455_8 | SOURCEANDSINK | PIPE | SEWAGE
InPort_792464_1 | SINK | PIPE | USERDEFINED
OutPort_792464_2 | SOURCE | PIPE | DOMESTICHOTWATER
InPort_792464_3 | SINK | PIPE | DOMESTICCOLDWATER
OutPort_792464_4 | SOURCE | DUCT | EXHAUST | Group: Mechanical Exhaust Air 15
Port_792492_1 | SOURCEANDSINK | PIPE | HEATING
Port_872736_5 | SOURCEANDSINK | PIPE | SEWAGE
Port_872736_6 | SOURCEANDSINK | PIPE | HEATING
Port_872736_7 | SOURCEANDSINK | PIPE | HEATING
Port_872736_8 | SOURCEANDSINK | PIPE | SEWAGE
InPort_872740_1 | SINK | PIPE | USERDEFINED
OutPort_872740_2 | SOURCE | PIPE | DOMESTICHOTWATER
InPort_872740_3 | SINK | PIPE | DOMESTICCOLDWATER
OutPort_872740_4 | SOURCE | DUCT
Port_872934_5 | SOURCEANDSINK | PIPE | SEWAGE
Port_872934_6 | SOURCEANDSINK | PIPE | HEATING
Port_872934_7 | SOURCEANDSINK | PIPE | HEATING
Port_872934_8 | SOURCEANDSINK | PIPE | SEWAGE
InPort_872938_1 | SINK | PIPE | USERDEFINED
OutPort_872938_2 | SOURCE | PIPE | DOMESTICHOTWATER
InPort_872938_3 | SINK | PIPE | DOMESTICCOLDWATER
OutPort_872938_4 | SOURCE | DUCT
Port_872985_1 | SOURCEANDSINK | PIPE | HEATING
Port_1311380_1 | SOURCEANDSINK | PIPE | HEATING
Port_1794235_1 | SOURCEANDSINK | PIPE | HEATING
Port_1795307_1 | SOURCEANDSINK | PIPE | HEATING
Port_2054834_1 | SOURCEANDSINK | CABLE | ELECTRICAL
Port_2054837_1 | SOURCEANDSINK | CABLE | ELECTRICAL
Port_2056649_2 | SOURCEANDSINK | CABLE | ELECTRICAL
Port_2058754_2 | SOURCEANDSINK | CABLE | ELECTRICAL
Port_2059904_8 | SOURCEANDSINK | CABLE | DATA
Port_2061446_6 | SOURCEANDSINK | CABLE | ELECTRICAL
Port_2062992_6 | SOURCEANDSINK | CABLE | ELECTRICAL

# IfcDistributionSystem: Exhaust Air (22)
PredefinedType: EXHAUST
Pset_DistributionSystemCommon - Reference: Exhaust Air
Name
Mechanical Exhaust Air 3
Mechanical Exhaust Air 25
Mechanical Exhaust Air 27
Mechanical Exhaust Air 29
Mechanical Exhaust Air 31
Mechanical Exhaust Air 41
Mechanical Exhaust Air 43
Mechanical Exhaust Air 45
Mechanical Exhaust Air 47
Mechanical Exhaust Air 57
Mechanical Exhaust Air 59
Mechanical Exhaust Air 61
Mechanical Exhaust Air 63
Mechanical Exhaust Air 73
Mechanical Exhaust Air 75
Mechanical Exhaust Air 77
Mechanical Exhaust Air 79
Mechanical Exhaust Air 2
Mechanical Exhaust Air 7
Mechanical Exhaust Air 10
Mechanical Exhaust Air 13
Mechanical Exhaust Air 15

# IfcDoor: C1030 - Puerta batiente - Aluminio+Vidrio:C1030 - 0.70 x 2.00 - Puerta batiente - Aluminio + Vidrio (2)
In: Nivel 1
Type - PredefinedType: DOOR; OperationType: SINGLE_SWING_LEFT; Material: Aluminio (2), <Unnamed>, Vidrio
Type - C1030 - Puerta batiente - Aluminio+Vidrio:C1030 - 0.70 x 2.00 - Puerta batiente - Aluminio + Vidrio:872982:1 - PanelOperation: SWINGING
Type - Pset_DoorCommon - IsExternal: no
OverallHeight: 2 m; OverallWidth: 0.7 m; Classification: 21-03 10 30 20 Uniformat (Uniformat); Material: Aluminio, <Unnamed>, Vidrio
Pset_DoorCommon - Reference: C1030 - 0.70 x 2.00 - Puerta batiente - Aluminio + Vidrio
Pset_EnvironmentalImpactIndicators - Reference: C1030 - 0.70 x 2.00 - Puerta batiente - Aluminio + Vidrio
Qto_DoorBaseQuantities - Width: 0.7 m; Height: 2 m; Area: 1.4 m2
Name (C1030 - Puerta batiente - Aluminio+Vidrio:C1030 - 0.70 x 2.00 - Puerta batiente - Aluminio + Vidrio:...)
872982
1311591

# IfcDoor: C1030 - Puerta batiente - Aluminio+Vidrio:C1030 - 0.70 x 2.00 - Puerta batiente - Aluminio + Vidrio (2)
In: Nivel 1
Type - PredefinedType: DOOR; OperationType: SINGLE_SWING_RIGHT; Material: Aluminio (2), <Unnamed>, Vidrio
Type - C1030 - Puerta batiente - Aluminio+Vidrio:C1030 - 0.70 x 2.00 - Puerta batiente - Aluminio + Vidrio:869196:1 - PanelOperation: SWINGING
Type - Pset_DoorCommon - IsExternal: no
OverallHeight: 2 m; OverallWidth: 0.7 m; Classification: 21-03 10 30 20 Uniformat (Uniformat); Material: Aluminio, <Unnamed>, Vidrio
Pset_DoorCommon - Reference: C1030 - 0.70 x 2.00 - Puerta batiente - Aluminio + Vidrio
Pset_EnvironmentalImpactIndicators - Reference: C1030 - 0.70 x 2.00 - Puerta batiente - Aluminio + Vidrio
Qto_DoorBaseQuantities - Width: 0.7 m; Height: 2 m; Area: 1.4 m2
Name (C1030 - Puerta batiente - Aluminio+Vidrio:C1030 - 0.70 x 2.00 - Puerta batiente - Aluminio + Vidrio:...)
869196
872795

# IfcDoor: C1030 - Puerta batiente - Madera + Metal:C1030 - 1.00 x 2.24 - Puerta batiente - Madera (12)
Type - PredefinedType: DOOR; Material: <Unnamed>
Type - Pset_DoorCommon - IsExternal: no; FireExit: yes; FireRating: 60
OverallHeight: 2.24 m; OverallWidth: 1 m; Classification: 21-03 10 30 10 Uniformat (Uniformat)
Pset_DoorCommon - Reference: C1030 - 1.00 x 2.24 - Puerta batiente - Madera
Pset_EnvironmentalImpactIndicators - Reference: C1030 - 1.00 x 2.24 - Puerta batiente - Madera
Qto_DoorBaseQuantities - Width: 1 m; Height: 2.24 m; Area: 2.24 m2
Name (C1030 - Puerta batiente - Madera + Metal:C1030 - 1.00 x 2.24 - Puerta batiente - Madera:...) | In
749688 | Nivel 3
751255 | Nivel 4
752822 | Nivel 5
754389 | Nivel 6
782048 | Nivel 1
792363 | Nivel 2
872660 | Nivel 1
998479 | Nivel 2
1075345 | Nivel 3
1084500 | Nivel 6
1084530 | Nivel 4
1084570 | Nivel 5

# IfcDoor: C1030 - Puerta batiente - Madera + Metal:C1030 - 1.00 x 2.24 - Puerta batiente - Madera (12)
Type - PredefinedType: DOOR; Material: <Unnamed>
Type - Pset_DoorCommon - IsExternal: no; FireRating: 60; FireExit: yes
OverallHeight: 2.24 m; OverallWidth: 1 m; Classification: 21-03 10 30 10 Uniformat (Uniformat)
Pset_DoorCommon - Reference: C1030 - 1.00 x 2.24 - Puerta batiente - Madera
Pset_EnvironmentalImpactIndicators - Reference: C1030 - 1.00 x 2.24 - Puerta batiente - Madera
Qto_DoorBaseQuantities - Width: 1 m; Height: 2.24 m; Area: 2.24 m2
Name (C1030 - Puerta batiente - Madera + Metal:C1030 - 1.00 x 2.24 - Puerta batiente - Madera:...) | In
728561 | Nivel 1
749312 | Nivel 3
749514 | Nivel 3
750879 | Nivel 4
751081 | Nivel 4
752446 | Nivel 5
752648 | Nivel 5
754013 | Nivel 6
754215 | Nivel 6
791992 | Nivel 2
792190 | Nivel 2
872858 | Nivel 1

# IfcDoor: C1030 - Puerta batiente - Madera+Aluminio:C1030 - 0.70 x 2.22 - Puerta batiente - Madera+ Metal (2)
In: Nivel 1
Type - PredefinedType: DOOR; OperationType: SINGLE_SWING_LEFT; Material: <Unnamed>
Type - C1030 - Puerta batiente - Madera+Aluminio:C1030 - 0.70 x 2.22 - Puerta batiente - Madera+ Metal:728650:1 - PanelOperation: SWINGING
Type - Pset_DoorCommon - IsExternal: no
OverallHeight: 2.22 m; OverallWidth: 0.7 m; Classification: 21-03 10 30 10 Uniformat (Uniformat)
Pset_DoorCommon - Reference: C1030 - 0.70 x 2.22 - Puerta batiente - Madera+ Metal
Pset_EnvironmentalImpactIndicators - Reference: C1030 - 0.70 x 2.22 - Puerta batiente - Madera+ Metal
Qto_DoorBaseQuantities - Width: 0.7 m; Height: 2.22 m; Area: 1.554 m2
Name (C1030 - Puerta batiente - Madera+Aluminio:C1030 - 0.70 x 2.22 - Puerta batiente - Madera+ Metal:...)
728650
872924

# IfcDoor: C1030 - Puerta batiente - Madera+Aluminio:C1030 - 0.70 x 2.22 - Puerta batiente - Madera+ Metal (10)
Type - PredefinedType: DOOR; OperationType: SINGLE_SWING_LEFT; Material: <Unnamed>
Type - C1030 - Puerta batiente - Madera+Aluminio:C1030 - 0.70 x 2.22 - Puerta batiente - Madera+ Metal:749379:1 - PanelOperation: SWINGING
Type - Pset_DoorCommon - IsExternal: no
OverallHeight: 2.22 m; OverallWidth: 0.7 m; Classification: 21-03 10 30 10 Uniformat (Uniformat)
Pset_DoorCommon - Reference: C1030 - 0.70 x 2.22 - Puerta batiente - Madera+ Metal
Pset_EnvironmentalImpactIndicators - Reference: C1030 - 0.70 x 2.22 - Puerta batiente - Madera+ Metal
Qto_DoorBaseQuantities - Width: 0.7 m; Height: 2.22 m; Area: 1.554 m2
Name (C1030 - Puerta batiente - Madera+Aluminio:C1030 - 0.70 x 2.22 - Puerta batiente - Madera+ Metal:...) | In
749379 | Nivel 3
749581 | Nivel 3
750946 | Nivel 4
751148 | Nivel 4
752513 | Nivel 5
752715 | Nivel 5
754080 | Nivel 6
754282 | Nivel 6
792059 | Nivel 2
792257 | Nivel 2

# IfcDoor: C1030 - Puerta batiente - Madera+Aluminio:C1030 - 0.70 x 2.22 - Puerta batiente - Madera+ Metal (11)
Type - PredefinedType: DOOR; OperationType: SINGLE_SWING_RIGHT; Material: <Unnamed>
Type - C1030 - Puerta batiente - Madera+Aluminio:C1030 - 0.70 x 2.22 - Puerta batiente - Madera+ Metal:749213:1 - PanelOperation: SWINGING
Type - Pset_DoorCommon - IsExternal: no
OverallHeight: 2.22 m; OverallWidth: 0.7 m; Classification: 21-03 10 30 10 Uniformat (Uniformat)
Pset_DoorCommon - Reference: C1030 - 0.70 x 2.22 - Puerta batiente - Madera+ Metal
Pset_EnvironmentalImpactIndicators - Reference: C1030 - 0.70 x 2.22 - Puerta batiente - Madera+ Metal
Qto_DoorBaseQuantities - Width: 0.7 m; Height: 2.22 m; Area: 1.554 m2
Name (C1030 - Puerta batiente - Madera+Aluminio:C1030 - 0.70 x 2.22 - Puerta batiente - Madera+ Metal:...) | In
749213 | Nivel 3
749755 | Nivel 3
750780 | Nivel 4
751322 | Nivel 4
752347 | Nivel 5
752889 | Nivel 5
753914 | Nivel 6
754456 | Nivel 6
781322 | Nivel 1
791894 | Nivel 2
792430 | Nivel 2

# IfcDoor: C1030 - Puerta batiente - Madera+Aluminio:C1030 - 0.70 x 2.22 - Puerta batiente - Madera+ Metal, C1030 - Puerta batiente - Madera+Aluminio:C1030 - 0.70 x 2.22 - Puerta batiente - Madera+ Metal:872726
In: Nivel 1
Type - PredefinedType: DOOR; OperationType: SINGLE_SWING_RIGHT; Material: <Unnamed>
Type - C1030 - Puerta batiente - Madera+Aluminio:C1030 - 0.70 x 2.22 - Puerta batiente - Madera+ Metal:872726:1 - PanelOperation: SWINGING
Type - Pset_DoorCommon - IsExternal: no
OverallHeight: 2.22 m; OverallWidth: 0.7 m; Classification: 21-03 10 30 10 Uniformat (Uniformat)
Pset_DoorCommon - Reference: C1030 - 0.70 x 2.22 - Puerta batiente - Madera+ Metal
Pset_EnvironmentalImpactIndicators - Reference: C1030 - 0.70 x 2.22 - Puerta batiente - Madera+ Metal
Qto_DoorBaseQuantities - Width: 0.7 m; Height: 2.22 m; Area: 1.554 m2

# IfcDoor: PUERTA escotilla batiente 1H:B3060- 0.94x0.94m- escotilla batiente 1H- Metálica, PUERTA escotilla batiente 1H:B3060- 0.94x0.94m- escotilla batiente 1H- Metálica:1871616
In: Nivel 7
Type - PredefinedType: DOOR; Material: <Unnamed>, Steel
Type - Pset_DoorCommon - IsExternal: no
OverallHeight: 1.18288 m; OverallWidth: 0.94 m; Classification: 21-02 30 60 50 Uniformat (Uniformat)
Pset_DoorCommon - Reference: B3060- 0.94x0.94m- escotilla batiente 1H- Metálica
Pset_EnvironmentalImpactIndicators - Reference: B3060- 0.94x0.94m- escotilla batiente 1H- Metálica
Qto_DoorBaseQuantities - Width: 0.94 m; Area: 1.00782 m2

# IfcFlowSegment: Gutter:D2030 - 0.115 m x 0.063m - Canal aguas lluvias - PVC:19886 (3)
In: Nivel 7
Type - ElementType: Gutter:D2030 - 0.115 m x 0.063m - Canal aguas lluvias - PVC:19886; PredefinedType: GUTTER
Classification: 21-02 30 20 30 Uniformat (Uniformat)
Pset_EnvironmentalImpactIndicators - Reference: D2030 - 0.115 m x 0.063m - Canal aguas lluvias - PVC; sets with these values: 2
Name (Gutter:D2030 - 0.115 m x 0.063m - Canal aguas lluvias - PVC:...)
810559
810565
810637

# IfcFlowTerminal: D2010 - Ducha - Acero Inoxidable:D2010 - Ducha - Acero Inoxidable (24)
Type - Material: <Unnamed>
Classification: 21-04 20 10 60 Uniformat (Uniformat)
Pset_EnvironmentalImpactIndicators - Reference: D2010 - Ducha - Acero Inoxidable
Name (D2010 - Ducha - Acero Inoxidable:D2010 - Ducha - Acero Inoxidable:...) | In
728691 | 30
749240 | 144
749406 | 151
749608 | 159
749782 | 166
750807 | 202
750973 | 210
751175 | 218
751349 | 225
752374 | 261
752540 | 268
752742 | 276
752916 | 283
753941 | 319
754107 | 326
754309 | 334
754483 | 341
781349 | 384
791921 | 404
792086 | 411
792284 | 419
792457 | 426
872738 | 473
1808462 | 480

# IfcFlowTerminal: D2010 - Griferia Lavaplatos - Acero Inoxidable + Plastico:D2010 - Griferia Lavaplatos - Acero Inoxidable + Plastico (24)
Type - Material: Grifería lavaplatos
Type - Pset_ManufacturerTypeInformation - ArticleNumber: 732167; Manufacturer: Mora Armatur
Classification: 21-04 20 10 60 Uniformat (Uniformat)
Pset_EnvironmentalImpactIndicators - Reference: D2010 - Griferia Lavaplatos - Acero Inoxidable + Plastico
Name (D2010 - Griferia Lavaplatos - Acero Inoxidable + Plastico:D2010 - Griferia Lavaplatos - Acero Inoxidable + Plastico:...) | In
1130231 | 33
1680339 | 476
1914648 | 387
1915302 | 483
1918805 | 422
1920277 | 147
1920288 | 154
1920299 | 162
1920310 | 169
1920321 | 205
1920332 | 213
1920343 | 221
1920354 | 228
1920365 | 264
1920376 | 271
1920387 | 279
1920398 | 286
1920409 | 322
1920420 | 329
1920431 | 337
1920442 | 344
1920453 | 407
1920464 | 414
1920475 | 429

# IfcFlowTerminal: D2010 - Grifo de Ducha - Acero Inoxidable:D2010 - Grifo de Ducha - Acero Inoxidable (24)
Type - Material: Ducha, <Unnamed>
Classification: 21-04 20 10 60 Uniformat (Uniformat)
Pset_EnvironmentalImpactIndicators - Reference: D2010 - Grifo de Ducha - Acero Inoxidable
Name (D2010 - Grifo de Ducha - Acero Inoxidable:D2010 - Grifo de Ducha - Acero Inoxidable:...) | In
728692 | 29
749241 | 143
749407 | 150
749609 | 158
749783 | 165
750808 | 201
750974 | 209
751176 | 217
751350 | 224
752375 | 260
752541 | 267
752743 | 275
752917 | 282
753942 | 318
754108 | 325
754310 | 333
754484 | 340
781350 | 383
791922 | 403
792087 | 410
792285 | 418
792458 | 425
872739 | 472
872937 | 479

# IfcFlowTerminal: D2010 - Lavadero - Granito:D2010 - Lavadero - Concreto (24)
Type - Material: Lavadero
Classification: 21-04 20 10 60 Uniformat (Uniformat)
Pset_EnvironmentalImpactIndicators - Reference: D2010 - Lavadero - Concreto
Name (D2010 - Lavadero - Granito:D2010 - Lavadero - Concreto:...) | In
749211 | 146
749377 | 153
749579 | 161
749753 | 168
750778 | 204
750944 | 212
751146 | 220
751320 | 227
752345 | 263
752511 | 270
752713 | 278
752887 | 285
753912 | 321
754078 | 328
754280 | 336
754454 | 343
791892 | 406
792057 | 413
792255 | 421
792428 | 428
1793706 | 510
1794374 | 507
1795305 | 508
1795635 | 509

# IfcFlowTerminal: D2010 - Lavamanos Ravello - Cerámica:D2010 - 0.36m x 0.41m - Lavamanos Ravello - Cerámica (24)
Type - Material: CERAMICA APARATOS, <Unnamed>
Classification: 21-04 20 10 60 Uniformat (Uniformat)
Pset_EnvironmentalImpactIndicators - Reference: D2010 - 0.36m x 0.41m - Lavamanos Ravello - Cerámica
Name (D2010 - Lavamanos Ravello - Cerámica:D2010 - 0.36m x 0.41m - Lavamanos Ravello - Cerámica:...) | In
728676 | 30
749238 | 144
749404 | 151
749606 | 159
749780 | 166
750805 | 202
750971 | 210
751173 | 218
751347 | 225
752372 | 261
752538 | 268
752740 | 276
752914 | 283
753939 | 319
754105 | 326
754307 | 334
754481 | 341
781347 | Nivel 1
791919 | 404
792084 | 411
792282 | 419
792455 | 426
872736 | 473
872934 | 480

# IfcFlowTerminal: D2020 - Sanitario - Cerámica:D2020 - Sanitario - Cerámica (24)
Type - Material: CERAMICA APARATOS
Classification: 21-04 20 10 60 Uniformat (Uniformat)
Pset_EnvironmentalImpactIndicators - Reference: D2020 - Sanitario - Cerámica
Name (D2020 - Sanitario - Cerámica:D2020 - Sanitario - Cerámica:...) | In
728591 | 30
749174 | 144
749342 | 151
749544 | 159
749718 | 166
750741 | 202
750909 | 210
751111 | 218
751285 | 225
752308 | 261
752476 | 268
752678 | 276
752852 | 283
753875 | 319
754043 | 326
754245 | 334
754419 | 341
781285 | 384
791855 | 404
792022 | 411
792220 | 419
792393 | 426
872690 | 473
872888 | 480

# IfcFurniture: Barra baño:E2050- Barra Baño- Acero inoxidable (24)
Type - Material: <Unnamed>
Classification: 21-03 10 90 40 Uniformat (Uniformat)
Pset_EnvironmentalImpactIndicators - Reference: E2050- Barra Baño- Acero inoxidable; sets with these values: 2
Name (Barra baño:E2050- Barra Baño- Acero inoxidable:...) | In
1087401 | 480
1087699 | 30
1087703 | 473
1088241 | 384
1088282 | 411
1089536 | 144
1089575 | 151
1089614 | 159
1089653 | 166
1089692 | 202
1089731 | 210
1089770 | 218
1089809 | 225
1089848 | 261
1089887 | 268
1089926 | 276
1089965 | 283
1090004 | 319
1090043 | 326
1090082 | 334
1090121 | 341
1090160 | 404
1090199 | 419
1090238 | 426

# IfcFurniture: E1060 - Meson Socoda Radiante - 1.50 X 0.52 - Acero inoxidable:E1060 - 1.50 x 0.52 - Meson de cocina, lavadero y estufa - Acero inoxidable (24)
Type - Material: Mesón cocina
Classification: 21-05 20 10 30 Uniformat (Uniformat)
Pset_EnvironmentalImpactIndicators - Reference: E1060 - 1.50 x 0.52 - Meson de cocina, lavadero y estufa - Acero inoxidable; sets with these values: 2
Name (E1060 - Meson Socoda Radiante - 1.50 X 0.52 - Acero inoxidable:E1060 - 1.50 x 0.52 - Meson de cocina, lavadero y estufa - Acero inoxidable:...) | In
1130230 | 33
1680338 | 476
1914647 | 387
1915301 | 483
1918804 | 422
1920276 | 147
1920287 | 154
1920298 | 162
1920309 | 169
1920320 | 205
1920331 | 213
1920342 | 221
1920353 | 228
1920364 | 264
1920375 | 271
1920386 | 279
1920397 | 286
1920408 | 322
1920419 | 329
1920430 | 337
1920441 | 344
1920452 | 407
1920463 | 414
1920474 | 429

# IfcFurniture: E2010 - Mueble bajo de cocina - Madera:E2010 - 1.50 x 0.52 - Mueble bajo de cocina - Madera (24)
Type - Material: mueble cocina
Classification: 21-05 20 10 30 Uniformat (Uniformat)
Pset_EnvironmentalImpactIndicators - Reference: E2010 - 1.50 x 0.52 - Mueble bajo de cocina - Madera; sets with these values: 2
Name (E2010 - Mueble bajo de cocina - Madera:E2010 - 1.50 x 0.52 - Mueble bajo de cocina - Madera:...) | In
1130229 | 33
1680337 | 476
1914646 | 387
1915300 | 483
1918803 | 422
1920275 | 147
1920286 | 154
1920297 | 162
1920308 | 169
1920319 | 205
1920330 | 213
1920341 | 221
1920352 | 228
1920363 | 264
1920374 | 271
1920385 | 279
1920396 | 286
1920407 | 322
1920418 | 329
1920429 | 337
1920440 | 344
1920451 | 407
1920462 | 414
1920473 | 429

# IfcFurniture: E2050 - Espejo:E2050 - 0.60m x 0.87m - Espejo (24)
Type - Material: Aluminio, ESPEJO
Classification: 21-03 10 90 90 Uniformat (Uniformat)
Pset_EnvironmentalImpactIndicators - Reference: E2050 - 0.60m x 0.87m - Espejo; sets with these values: 2
Name (E2050 - Espejo:E2050 - 0.60m x 0.87m - Espejo:...) | In
728690 | Nivel 1
749239 | Nivel 3
749405 | Nivel 3
749607 | Nivel 3
749781 | Nivel 3
750806 | Nivel 4
750972 | Nivel 4
751174 | Nivel 4
751348 | Nivel 4
752373 | Nivel 5
752539 | Nivel 5
752741 | Nivel 5
752915 | Nivel 5
753940 | Nivel 6
754106 | Nivel 6
754308 | Nivel 6
754482 | Nivel 6
781348 | Nivel 1
791920 | Nivel 2
792085 | Nivel 2
792283 | Nivel 2
792456 | Nivel 2
872737 | Nivel 1
872935 | Nivel 1

# IfcFurniture: E2050 - Jabonera:E2050 - Jabonera - Ceramica (24)
Type - Material: CERAMICA APARATOS
Classification: 21-03 10 90 40 Uniformat (Uniformat)
Pset_EnvironmentalImpactIndicators - Reference: E2050 - Jabonera - Ceramica; sets with these values: 2
Name (E2050 - Jabonera:E2050 - Jabonera - Ceramica:...) | In
728719 | 30
749268 | 144
749434 | 151
749636 | 159
749810 | 166
750835 | 202
751001 | 210
751203 | 218
751377 | 225
752402 | 261
752568 | 268
752770 | 276
752944 | 283
753969 | 319
754135 | 326
754337 | 334
754511 | 341
781376 | 384
791949 | 404
792114 | 411
792312 | 419
792485 | 426
872742 | 473
872940 | 480

# IfcFurniture: E2050 - Papelera:E2050 - Papelera - Ceramica (23)
Type - Material: CERAMICA APARATOS
Classification: 21-03 10 90 40 Uniformat (Uniformat)
Pset_EnvironmentalImpactIndicators - Reference: E2050 - Papelera - Ceramica; sets with these values: 2
Name (E2050 - Papelera:E2050 - Papelera - Ceramica:...) | In
910031 | 480
911092 | 30
911121 | 473
937830 | 419
937979 | 144
937981 | 151
937983 | 159
937985 | 166
937987 | 202
937989 | 210
937991 | 218
937993 | 225
937995 | 261
937997 | 268
937999 | 276
938001 | 283
938003 | 319
938005 | 326
938007 | 334
938009 | 341
938011 | 404
938013 | 411
938015 | 426

# IfcFurniture: E2050 - Toallero:E2050 - Toallero - Ceramica (24)
Type - Material: CERAMICA APARATOS
Classification: 21-03 10 90 40 Uniformat (Uniformat)
Pset_EnvironmentalImpactIndicators - Reference: E2050 - Toallero - Ceramica; sets with these values: 2
Name (E2050 - Toallero:E2050 - Toallero - Ceramica:...) | In
728724 | 30
749273 | 144
749439 | 151
749641 | 159
749815 | 166
750840 | 202
751006 | 210
751208 | 218
751382 | 225
752407 | 261
752573 | 268
752775 | 276
752949 | 283
753974 | 319
754140 | 326
754342 | 334
754516 | 341
781381 | 384
791954 | 404
792119 | 411
792317 | 419
792490 | 426
872747 | 473
872945 | 480

# IfcFurniture: flanche:flanche, flanche:flanche:1926351
In: Nivel 7
Type - Material: flacnhe
Classification: 21-02 30 40 90 Uniformat (Uniformat)
Pset_EnvironmentalImpactIndicators - Reference: flanche; sets with these values: 2

# IfcLightFixture: Aplique:60W - 120V (2)
Type - Material: Default Light Source, <Unnamed>
Classification: D5040.50 Uniformat (Uniformat)
Pset_EnvironmentalImpactIndicators - Reference: 60W - 120V; sets with these values: 2
Name (Aplique:60W - 120V:...) | In
2054834 | 409
2054837 | 408

# IfcOpeningElement (605)
PredefinedType: OPENING
Name | In | Classification | Height (m) | Width (m) | Reference | sets with these values
2 x Basic Wall:B2010 - 0.12m - Muro interior en concreto:724971 | Nivel 1 | 21-03 10 10 10 Uniformat (Uniformat) | 2.24 | 0.115 | C1030 - 1.00 x 2.24 - Puerta batiente - Madera | 2 | Qto_OpeningElementBaseQuantities - Depth: 1 m
Basic Wall:B2010 - 0.115m - ME mampostería no estructural - Ladrillo:728538 | Nivel 1 | 21-02 20 10 20 Uniformat (Uniformat) | 2.25 | 1.35 | B2020 - 1.35m x 2.25m - Ventana corrediza 2C - Aluminio + Vidrio | 2 | Qto_OpeningElementBaseQuantities - Depth: 3.048 m
Basic Wall:B2010 - 0.115m - Muro interior en mampostería - Ladrillo + Pañete:728545 | Nivel 1 | 21-03 10 10 10 Uniformat (Uniformat) | 2.22 | 0.135 | C1030 - 0.70 x 2.22 - Puerta batiente - Madera+ Metal | 2 | Qto_OpeningElementBaseQuantities - Depth: 0.7 m
4 x Basic Wall:C2010 - 0.25 x 0.35 - Enchape cerámico:446299 | Nivel 1 | 21-03 20 10 10 Uniformat (Uniformat) | 0.52 | 0.52 | C2010 - 0.25 x 0.35 - Enchape cerámico | 2
75 x Basic Wall:B2010 - 0.2x0.2 - Muro calado- concreto:1814582 | Nivel 1 | 21-02 20 10 20 Uniformat (Uniformat) | 0.12 | 0.12 | B2010 - 0.2x0.2 - Muro calado- concreto | 2
Basic Wall:B2010 - 0.115m - Muro interior en mampostería - Ladrillo + Pañete:749129 | Nivel 3 | 21-03 10 10 10 Uniformat (Uniformat) | 2.22 | 0.135 | C1030 - 0.70 x 2.22 - Puerta batiente - Madera+ Metal | 2 | Qto_OpeningElementBaseQuantities - Depth: 0.7 m
4 x Basic Wall:C2010 - 0.25 x 0.35 - Enchape cerámico:446299 | Nivel 3 | 21-03 20 10 10 Uniformat (Uniformat) | 0.52 | 0.52 | C2010 - 0.25 x 0.35 - Enchape cerámico | 2
Basic Wall:B2010 - 0.115m - Muro interior en mampostería - Ladrillo + Pañete:749297 | Nivel 3 | 21-03 10 10 10 Uniformat (Uniformat) | 2.22 | 0.135 | C1030 - 0.70 x 2.22 - Puerta batiente - Madera+ Metal | 2 | Qto_OpeningElementBaseQuantities - Depth: 0.7 m
Basic Wall:B2010 - 0.115m - Muro interior en mampostería - Ladrillo + Pañete:749499 | Nivel 3 | 21-03 10 10 10 Uniformat (Uniformat) | 2.22 | 0.135 | C1030 - 0.70 x 2.22 - Puerta batiente - Madera+ Metal | 2 | Qto_OpeningElementBaseQuantities - Depth: 0.7 m
Basic Wall:B2010 - 0.115m - Muro interior en mampostería - Ladrillo + Pañete:749673 | Nivel 3 | 21-03 10 10 10 Uniformat (Uniformat) | 2.22 | 0.135 | C1030 - 0.70 x 2.22 - Puerta batiente - Madera+ Metal | 2 | Qto_OpeningElementBaseQuantities - Depth: 0.7 m
Basic Wall:B2010 - 0.115m - Muro interior en mampostería - Ladrillo + Pañete:750696 | Nivel 4 | 21-03 10 10 10 Uniformat (Uniformat) | 2.22 | 0.135 | C1030 - 0.70 x 2.22 - Puerta batiente - Madera+ Metal | 2 | Qto_OpeningElementBaseQuantities - Depth: 0.7 m
4 x Basic Wall:C2010 - 0.25 x 0.35 - Enchape cerámico:446299 | Nivel 4 | 21-03 20 10 10 Uniformat (Uniformat) | 0.52 | 0.52 | C2010 - 0.25 x 0.35 - Enchape cerámico | 2
Basic Wall:B2010 - 0.115m - Muro interior en mampostería - Ladrillo + Pañete:750864 | Nivel 4 | 21-03 10 10 10 Uniformat (Uniformat) | 2.22 | 0.135 | C1030 - 0.70 x 2.22 - Puerta batiente - Madera+ Metal | 2 | Qto_OpeningElementBaseQuantities - Depth: 0.7 m
Basic Wall:B2010 - 0.115m - Muro interior en mampostería - Ladrillo + Pañete:751066 | Nivel 4 | 21-03 10 10 10 Uniformat (Uniformat) | 2.22 | 0.135 | C1030 - 0.70 x 2.22 - Puerta batiente - Madera+ Metal | 2 | Qto_OpeningElementBaseQuantities - Depth: 0.7 m
Basic Wall:B2010 - 0.115m - Muro interior en mampostería - Ladrillo + Pañete:751240 | Nivel 4 | 21-03 10 10 10 Uniformat (Uniformat) | 2.22 | 0.135 | C1030 - 0.70 x 2.22 - Puerta batiente - Madera+ Metal | 2 | Qto_OpeningElementBaseQuantities - Depth: 0.7 m
Basic Wall:B2010 - 0.115m - Muro interior en mampostería - Ladrillo + Pañete:752263 | Nivel 5 | 21-03 10 10 10 Uniformat (Uniformat) | 2.22 | 0.135 | C1030 - 0.70 x 2.22 - Puerta batiente - Madera+ Metal | 2 | Qto_OpeningElementBaseQuantities - Depth: 0.7 m
4 x Basic Wall:C2010 - 0.25 x 0.35 - Enchape cerámico:446299 | Nivel 5 | 21-03 20 10 10 Uniformat (Uniformat) | 0.52 | 0.52 | C2010 - 0.25 x 0.35 - Enchape cerámico | 2
Basic Wall:B2010 - 0.115m - Muro interior en mampostería - Ladrillo + Pañete:752431 | Nivel 5 | 21-03 10 10 10 Uniformat (Uniformat) | 2.22 | 0.135 | C1030 - 0.70 x 2.22 - Puerta batiente - Madera+ Metal | 2 | Qto_OpeningElementBaseQuantities - Depth: 0.7 m
Basic Wall:B2010 - 0.115m - Muro interior en mampostería - Ladrillo + Pañete:752633 | Nivel 5 | 21-03 10 10 10 Uniformat (Uniformat) | 2.22 | 0.135 | C1030 - 0.70 x 2.22 - Puerta batiente - Madera+ Metal | 2 | Qto_OpeningElementBaseQuantities - Depth: 0.7 m
Basic Wall:B2010 - 0.115m - Muro interior en mampostería - Ladrillo + Pañete:752807 | Nivel 5 | 21-03 10 10 10 Uniformat (Uniformat) | 2.22 | 0.135 | C1030 - 0.70 x 2.22 - Puerta batiente - Madera+ Metal | 2 | Qto_OpeningElementBaseQuantities - Depth: 0.7 m
Basic Wall:B2010 - 0.115m - Muro interior en mampostería - Ladrillo + Pañete:753830 | Nivel 6 | 21-03 10 10 10 Uniformat (Uniformat) | 2.22 | 0.135 | C1030 - 0.70 x 2.22 - Puerta batiente - Madera+ Metal | 2 | Qto_OpeningElementBaseQuantities - Depth: 0.7 m
4 x Basic Wall:C2010 - 0.25 x 0.35 - Enchape cerámico:446299 | Nivel 6 | 21-03 20 10 10 Uniformat (Uniformat) | 0.52 | 0.52 | C2010 - 0.25 x 0.35 - Enchape cerámico | 2
Basic Wall:B2010 - 0.115m - Muro interior en mampostería - Ladrillo + Pañete:753998 | Nivel 6 | 21-03 10 10 10 Uniformat (Uniformat) | 2.22 | 0.135 | C1030 - 0.70 x 2.22 - Puerta batiente - Madera+ Metal | 2 | Qto_OpeningElementBaseQuantities - Depth: 0.7 m
Basic Wall:B2010 - 0.115m - Muro interior en mampostería - Ladrillo + Pañete:754200 | Nivel 6 | 21-03 10 10 10 Uniformat (Uniformat) | 2.22 | 0.135 | C1030 - 0.70 x 2.22 - Puerta batiente - Madera+ Metal | 2 | Qto_OpeningElementBaseQuantities - Depth: 0.7 m
Basic Wall:B2010 - 0.115m - Muro interior en mampostería - Ladrillo + Pañete:754374 | Nivel 6 | 21-03 10 10 10 Uniformat (Uniformat) | 2.22 | 0.135 | C1030 - 0.70 x 2.22 - Puerta batiente - Madera+ Metal | 2 | Qto_OpeningElementBaseQuantities - Depth: 0.7 m
3 x Basic Wall:B2010 - 0.115m - Muro exterior en mampostería - Ladrillo:197669 | Nivel 7 | 21-02 20 10 20 Uniformat (Uniformat) | 1.2468 | 0.085 | B2010 - 0.115m - Muro exterior en mampostería - Ladrillo | 2
3 x Basic Wall:B2010 - 0.115m - Muro exterior en mampostería - Ladrillo:197669 | Nivel 7 | 21-02 20 10 20 Uniformat (Uniformat) | 0.085 | 1.2468 | B2010 - 0.115m - Muro exterior en mampostería - Ladrillo | 2
Basic Wall:B2010 - 0.115m - Muro interior en mampostería - Ladrillo + Pañete:781240 | Nivel 1 | 21-03 10 10 10 Uniformat (Uniformat) | 2.22 | 0.135 | C1030 - 0.70 x 2.22 - Puerta batiente - Madera+ Metal | 2 | Qto_OpeningElementBaseQuantities - Depth: 0.7 m
Basic Wall:B2010 - 0.115m - Muro interior en mampostería - Ladrillo + Pañete:791811 | Nivel 2 | 21-03 10 10 10 Uniformat (Uniformat) | 2.22 | 0.135 | C1030 - 0.70 x 2.22 - Puerta batiente - Madera+ Metal | 2 | Qto_OpeningElementBaseQuantities - Depth: 0.7 m
Basic Wall:B2010 - 0.10m - MI no estructural- Concreto + repello+ pintura blanca:791815 | Nivel 2 | 21-02 20 10 20 Uniformat (Uniformat) | 1.15 | 0.7 | B2020 - 1.15 x 0.70 - Ventana corrediza con rejilla - Aluminio+Vidrio | 2 | Qto_OpeningElementBaseQuantities - Depth: 3.048 m
4 x Basic Wall:C2010 - 0.25 x 0.35 - Enchape cerámico:446299 | Nivel 2 | 21-03 20 10 10 Uniformat (Uniformat) | 0.52 | 0.52 | C2010 - 0.25 x 0.35 - Enchape cerámico | 2
Basic Wall:B2010 - 0.115m - Muro interior en mampostería - Ladrillo + Pañete:791978 | Nivel 2 | 21-03 10 10 10 Uniformat (Uniformat) | 2.22 | 0.135 | C1030 - 0.70 x 2.22 - Puerta batiente - Madera+ Metal | 2 | Qto_OpeningElementBaseQuantities - Depth: 0.7 m
Basic Wall:B2010 - 0.115m - Muro interior en mampostería - Ladrillo + Pañete:792176 | Nivel 2 | 21-03 10 10 10 Uniformat (Uniformat) | 2.22 | 0.135 | C1030 - 0.70 x 2.22 - Puerta batiente - Madera+ Metal | 2 | Qto_OpeningElementBaseQuantities - Depth: 0.7 m
Basic Wall:B2010 - 0.115m - Muro interior en mampostería - Ladrillo + Pañete:792349 | Nivel 2 | 21-03 10 10 10 Uniformat (Uniformat) | 2.22 | 0.135 | C1030 - 0.70 x 2.22 - Puerta batiente - Madera+ Metal | 2 | Qto_OpeningElementBaseQuantities - Depth: 0.7 m
Basic Wall:B2010 - 0.115m - Muro interior en mampostería - Ladrillo + Pañete:872646 | Nivel 1 | 21-03 10 10 10 Uniformat (Uniformat) | 2.22 | 0.135 | C1030 - 0.70 x 2.22 - Puerta batiente - Madera+ Metal | 2 | Qto_OpeningElementBaseQuantities - Depth: 0.7 m
Basic Wall:B2010 - 0.115m - Muro interior en mampostería - Ladrillo + Pañete:872844 | Nivel 1 | 21-03 10 10 10 Uniformat (Uniformat) | 2.22 | 0.135 | C1030 - 0.70 x 2.22 - Puerta batiente - Madera+ Metal | 2 | Qto_OpeningElementBaseQuantities - Depth: 0.7 m
Basic Wall:B2010 - 0.10m - MI Concreto- Concreto+Graniplast:1318258 | Nivel 7 | 21-02 20 10 20 Uniformat (Uniformat) | 0.3 | 0.035 | B2010 - 0.10m - MI Concreto- Concreto+Graniplast | 2
Basic Wall:B2010 - 0.115m - Muro exterior en mampostería - Ladrillo:906980:1 | Nivel 7 | 21-02 20 10 20 Uniformat (Uniformat) |  | 0.115 | B2010 - 0.115m - Muro exterior en mampostería - Ladrillo | 2 | Qto_OpeningElementBaseQuantities - Area: 7.27947 m2; Volume: 2.72388 m3
Basic Wall:B2010 - 0.115m - MI mampostería no estructural - Ladrillo:1218486 | Nivel 1 | 21-02 20 10 20 Uniformat (Uniformat) | 1.75 | 0.115 | B2020 -1.26m x 1.750m - Ventana corrediza 2C - Aluminio + Vidrio | 2 | Qto_OpeningElementBaseQuantities - Depth: 1.26 m
Basic Wall:B2010 - 0.115m - MI mampostería no estructural - Ladrillo:1218486 | Nivel 1 | 21-02 20 10 20 Uniformat (Uniformat) | 2.24 | 1 | C1030 - 1.00 x 2.24 - Puerta batiente - Madera | 2 | Qto_OpeningElementBaseQuantities - Depth: 3.048 m
Basic Wall:B2010 - 0.115m - MI mampostería no estructural - Ladrillo:1218550 | Nivel 1 | 21-02 20 10 20 Uniformat (Uniformat) | 2.0575 | 0.15 | B2010 - 0.115m - MI mampostería no estructural - Ladrillo | 2
Basic Wall:B2010 - 0.10m - MI Concreto- Concreto+repello+ pintura blanca:1221018 | Nivel 1 | 21-02 20 10 20 Uniformat (Uniformat) | 0.076 | 0.076 | B2010 - 0.10m - MI Concreto- Concreto+repello+ pintura blanca | 2 | Qto_OpeningElementBaseQuantities - Depth: 0.101 m
Basic Wall:B2010 - 0.10m - MI Concreto- Concreto+repello+ pintura blanca:1223333 | Nivel 1 | 21-02 20 10 20 Uniformat (Uniformat) | 0.076 | 0.076 | B2010 - 0.10m - MI Concreto- Concreto+repello+ pintura blanca | 2 | Qto_OpeningElementBaseQuantities - Depth: 0.101 m
Basic Wall:B2010 - 0.10m - MI Concreto- Concreto+repello+ pintura blanca:1223333 | Nivel 1 | 21-02 20 10 20 Uniformat (Uniformat) | 2 | 0.7 | C1030 - 0.70 x 2.00 - Puerta batiente - Aluminio + Vidrio | 2 | Qto_OpeningElementBaseQuantities - Depth: 3.048 m
Basic Wall:B2010 - 0.115m - ME mampostería no estructural - Ladrillo:1223871 | Nivel 1 | 21-02 20 10 20 Uniformat (Uniformat) | 2.25 | 1.02 | B2020 - 1.02m x 2.25m - Ventana corrediza 2C - Aluminio + Vidrio | 2 | Qto_OpeningElementBaseQuantities - Depth: 3.048 m
Basic Wall:B2010 - 0.10m - MI Concreto- Concreto+repello+ pintura blanca:1224992 | Nivel 1 | 21-02 20 10 20 Uniformat (Uniformat) | 0.076 | 0.076 | B2010 - 0.10m - MI Concreto- Concreto+repello+ pintura blanca | 2 | Qto_OpeningElementBaseQuantities - Depth: 0.101 m
Basic Wall:B2010 - 0.10m - MI Concreto- Concreto+repello+ pintura blanca:1228554 | Nivel 1 | 21-02 20 10 20 Uniformat (Uniformat) | 0.076 | 0.076 | B2010 - 0.10m - MI Concreto- Concreto+repello+ pintura blanca | 2 | Qto_OpeningElementBaseQuantities - Depth: 0.101 m
Basic Wall:B2010 - 0.10m - MI Concreto- Concreto+repello+ pintura blanca:1228554 | Nivel 1 | 21-02 20 10 20 Uniformat (Uniformat) | 2 | 0.7 | C1030 - 0.70 x 2.00 - Puerta batiente - Aluminio + Vidrio | 2 | Qto_OpeningElementBaseQuantities - Depth: 3.048 m
Basic Wall:B2010 - 0.115m - ME mampostería no estructural - Ladrillo:1251704 | Nivel 2 | 21-02 20 10 20 Uniformat (Uniformat) | 2.25 | 1.02 | B2020 - 1.02m x 2.25m - Ventana corrediza 2C - Aluminio + Vidrio | 2 | Qto_OpeningElementBaseQuantities - Depth: 3.048 m
Basic Wall:B2010 - 0.115m - ME mampostería no estructural - Ladrillo:1252218 | Nivel 4 | 21-02 20 10 20 Uniformat (Uniformat) | 2.25 | 1.02 | B2020 - 1.02m x 2.25m - Ventana corrediza 2C - Aluminio + Vidrio | 2 | Qto_OpeningElementBaseQuantities - Depth: 3.048 m
4 x Basic Wall:B2010 - 0.10m - MI Concreto- Concreto+repello+ pintura blanca:1593868 | Nivel 2 | 21-02 20 10 20 Uniformat (Uniformat) | 0.076 | 0.076 | B2010 - 0.10m - MI Concreto- Concreto+repello+ pintura blanca | 2
Basic Wall:B2010 - 0.10m - MI no estructural- Concreto + repello+ pintura blanca:1332194 | Nivel 3 | 21-02 20 10 20 Uniformat (Uniformat) | 1.15 | 0.7 | B2020 - 1.15 x 0.70 - Ventana corrediza con rejilla - Aluminio+Vidrio | 2 | Qto_OpeningElementBaseQuantities - Depth: 3.048 m
4 x Basic Wall:B2010 - 0.10m - MI Concreto- Concreto+repello+ pintura blanca:1593868 | Nivel 3 | 21-02 20 10 20 Uniformat (Uniformat) | 0.076 | 0.076 | B2010 - 0.10m - MI Concreto- Concreto+repello+ pintura blanca | 2
Basic Wall:B2010 - 0.10m - MI no estructural- Concreto + repello+ pintura blanca:1332206 | Nivel 4 | 21-02 20 10 20 Uniformat (Uniformat) | 1.15 | 0.7 | B2020 - 1.15 x 0.70 - Ventana corrediza con rejilla - Aluminio+Vidrio | 2 | Qto_OpeningElementBaseQuantities - Depth: 3.048 m
4 x Basic Wall:B2010 - 0.10m - MI Concreto- Concreto+repello+ pintura blanca:1593868 | Nivel 4 | 21-02 20 10 20 Uniformat (Uniformat) | 0.076 | 0.076 | B2010 - 0.10m - MI Concreto- Concreto+repello+ pintura blanca | 2
Basic Wall:B2010 - 0.10m - MI no estructural- Concreto + repello+ pintura blanca:1332218 | Nivel 5 | 21-02 20 10 20 Uniformat (Uniformat) | 1.15 | 0.7 | B2020 - 1.15 x 0.70 - Ventana corrediza con rejilla - Aluminio+Vidrio | 2 | Qto_OpeningElementBaseQuantities - Depth: 3.048 m
4 x Basic Wall:B2010 - 0.10m - MI Concreto- Concreto+repello+ pintura blanca:1593868 | Nivel 5 | 21-02 20 10 20 Uniformat (Uniformat) | 0.076 | 0.076 | B2010 - 0.10m - MI Concreto- Concreto+repello+ pintura blanca | 2
Basic Wall:B2010 - 0.10m - MI no estructural- Concreto + repello+ pintura blanca:1332230 | Nivel 6 | 21-02 20 10 20 Uniformat (Uniformat) | 1.15 | 0.7 | B2020 - 1.15 x 0.70 - Ventana corrediza con rejilla - Aluminio+Vidrio | 2 | Qto_OpeningElementBaseQuantities - Depth: 3.048 m
4 x Basic Wall:B2010 - 0.10m - MI Concreto- Concreto+repello+ pintura blanca:1593868 | Nivel 6 | 21-02 20 10 20 Uniformat (Uniformat) | 0.076 | 0.076 | B2010 - 0.10m - MI Concreto- Concreto+repello+ pintura blanca | 2
Basic Wall:B2010 - 0.10m - MI no estructural- Concreto + repello+ pintura blanca:1332443 | Nivel 3 | 21-02 20 10 20 Uniformat (Uniformat) | 1.15 | 0.7 | B2020 - 1.15 x 0.70 - Ventana corrediza con rejilla - Aluminio+Vidrio | 2 | Qto_OpeningElementBaseQuantities - Depth: 3.048 m
Basic Wall:B2010 - 0.10m - MI no estructural- Concreto + repello+ pintura blanca:1332470 | Nivel 4 | 21-02 20 10 20 Uniformat (Uniformat) | 1.15 | 0.7 | B2020 - 1.15 x 0.70 - Ventana corrediza con rejilla - Aluminio+Vidrio | 2 | Qto_OpeningElementBaseQuantities - Depth: 3.048 m
Basic Wall:B2010 - 0.10m - MI no estructural- Concreto + repello+ pintura blanca:1332497 | Nivel 5 | 21-02 20 10 20 Uniformat (Uniformat) | 1.15 | 0.7 | B2020 - 1.15 x 0.70 - Ventana corrediza con rejilla - Aluminio+Vidrio | 2 | Qto_OpeningElementBaseQuantities - Depth: 3.048 m
Basic Wall:B2010 - 0.10m - MI no estructural- Concreto + repello+ pintura blanca:1332543 | Nivel 6 | 21-02 20 10 20 Uniformat (Uniformat) | 1.15 | 0.7 | B2020 - 1.15 x 0.70 - Ventana corrediza con rejilla - Aluminio+Vidrio | 2 | Qto_OpeningElementBaseQuantities - Depth: 3.048 m
50 x Basic Wall:B2010 - 0.2x0.2 - Muro calado- concreto:1814582 | Nivel 2 | 21-02 20 10 20 Uniformat (Uniformat) | 0.12 | 0.12 | B2010 - 0.2x0.2 - Muro calado- concreto | 2
50 x Basic Wall:B2010 - 0.2x0.2 - Muro calado- concreto:1814582 | Nivel 3 | 21-02 20 10 20 Uniformat (Uniformat) | 0.12 | 0.12 | B2010 - 0.2x0.2 - Muro calado- concreto | 2
50 x Basic Wall:B2010 - 0.2x0.2 - Muro calado- concreto:1814582 | Nivel 4 | 21-02 20 10 20 Uniformat (Uniformat) | 0.12 | 0.12 | B2010 - 0.2x0.2 - Muro calado- concreto | 2
50 x Basic Wall:B2010 - 0.2x0.2 - Muro calado- concreto:1814582 | Nivel 5 | 21-02 20 10 20 Uniformat (Uniformat) | 0.12 | 0.12 | B2010 - 0.2x0.2 - Muro calado- concreto | 2
30 x Basic Wall:B2010 - 0.2x0.2 - Muro calado- concreto:1814582 | Nivel 6 | 21-02 20 10 20 Uniformat (Uniformat) | 0.12 | 0.12 | B2010 - 0.2x0.2 - Muro calado- concreto | 2
B2020 - Ventana corrediza 2C - Aluminio + Vidrio:B2020 - 1.02m x 2.25m - Ventana corrediza 2C - Aluminio + Vidrio:728563:1 | Nivel 1 |  | 1.02 | 2.25 | Qto_OpeningElementBaseQuantities - Depth: 0.115 m
B2020 - Ventana corrediza 2C - Aluminio + Vidrio:B2020 - 0.90m x 2.25m - Ventana corrediza 2C - Aluminio + Vidrio:728562:1 | Nivel 1 |  | 0.9 | 2.25 | Qto_OpeningElementBaseQuantities - Depth: 0.115 m
B2020 - 6c Ventana corrediza - Aluminio + Vidrio:B2020 -2.13m x 1.750m - Ventana corrediza 2C - Aluminio + Vidrio:728590:1 | Nivel 1 |  | 2.125 | 1.75 | Qto_OpeningElementBaseQuantities - Depth: 0.115 m
C1030 - Puerta batiente - Aluminio+Vidrio:C1030 - 0.70 x 2.00 - Puerta batiente - Aluminio + Vidrio:1311591:1 | Nivel 1 |  | 0.7 | 2 | Qto_OpeningElementBaseQuantities - Depth: 0.101 m
C1030 - Puerta batiente - Madera + Metal:C1030 - 1.00 x 2.24 - Puerta batiente - Madera:728561:1 | Nivel 1 |  | 1 | 2.24 | Qto_OpeningElementBaseQuantities - Depth: 0.115 m
B2020 - Ventana corrediza - Aluminio + Vidrio:B2020 - 1.35m x 2.25m - Ventana corrediza 2C - Aluminio + Vidrio:728564:1 | Nivel 1 |  | 1.35 | 2.25 | Qto_OpeningElementBaseQuantities - Depth: 0.115 m
B2020 - Ventana corrediza - Aluminio+Vidrio:B2020 - 0.52 x 0.52 - Ventana corrediza - Aluminio+Vidrio:728614:1 | Nivel 1 |  | 0.52 | 0.52 | Qto_OpeningElementBaseQuantities - Depth: 0.125 m
B2020 - Ventana corrediza 2C - Aluminio + Vidrio:B2020 - 0.90m x 2.25m - Ventana corrediza 2C - Aluminio + Vidrio:749145:1 | Nivel 3 |  | 0.9 | 2.25 | Qto_OpeningElementBaseQuantities - Depth: 0.115 m
B2020 - Ventana corrediza 2C - Aluminio + Vidrio:B2020 - 1.02m x 2.25m - Ventana corrediza 2C - Aluminio + Vidrio:2050076:1 | Nivel 3 |  | 1.02 | 2.25 | Qto_OpeningElementBaseQuantities - Depth: 0.115 m
C1030 - Puerta batiente - Madera + Metal:C1030 - 1.00 x 2.24 - Puerta batiente - Madera:1075345:1 | Nivel 3 |  | 1 | 2.24 | Qto_OpeningElementBaseQuantities - Depth: 0.115 m
B2020 - Ventana corrediza - Aluminio+Vidrio:B2020 - 0.52 x 0.52 - Ventana corrediza - Aluminio+Vidrio:749197:1 | Nivel 3 |  | 0.52 | 0.52 | Qto_OpeningElementBaseQuantities - Depth: 0.125 m
C1030 - Puerta batiente - Madera+Aluminio:C1030 - 0.70 x 2.22 - Puerta batiente - Madera+ Metal:749213:1 | Nivel 3 |  | 0.7 | 2.22 | Qto_OpeningElementBaseQuantities - Depth: 0.135 m
B2020 - Ventana corrediza 2C - Aluminio + Vidrio:B2020 - 0.90m x 2.25m - Ventana corrediza 2C - Aluminio + Vidrio:749313:1 | Nivel 3 |  | 0.9 | 2.25 | Qto_OpeningElementBaseQuantities - Depth: 0.115 m
B2020 - Ventana corrediza 2C - Aluminio + Vidrio:B2020 - 1.02m x 2.25m - Ventana corrediza 2C - Aluminio + Vidrio:749314:1 | Nivel 3 |  | 1.02 | 2.25 | Qto_OpeningElementBaseQuantities - Depth: 0.115 m
C1030 - Puerta batiente - Madera + Metal:C1030 - 1.00 x 2.24 - Puerta batiente - Madera:749312:1 | Nivel 3 |  | 1 | 2.24 | Qto_OpeningElementBaseQuantities - Depth: 0.115 m
B2020 - Ventana corrediza - Aluminio+Vidrio:B2020 - 0.52 x 0.52 - Ventana corrediza - Aluminio+Vidrio:749365:1 | Nivel 3 |  | 0.52 | 0.52 | Qto_OpeningElementBaseQuantities - Depth: 0.125 m
C1030 - Puerta batiente - Madera+Aluminio:C1030 - 0.70 x 2.22 - Puerta batiente - Madera+ Metal:749379:1 | Nivel 3 |  | 0.7 | 2.22 | Qto_OpeningElementBaseQuantities - Depth: 0.135 m
B2020 - Ventana batiente - Aluminio + Vidrio:B2020 -0.52m x 1.1.25m - Ventana batiente 2C - Aluminio + Vidrio:1145669:1 | Nivel 3 |  | 0.52 | 1.25 | Qto_OpeningElementBaseQuantities - Depth: 0.115 m
B2020 - Ventana corrediza 2C - Aluminio + Vidrio:B2020 - 0.90m x 2.25m - Ventana corrediza 2C - Aluminio + Vidrio:749515:1 | Nivel 3 |  | 0.9 | 2.25 | Qto_OpeningElementBaseQuantities - Depth: 0.115 m
B2020 - Ventana corrediza 2C - Aluminio + Vidrio:B2020 - 1.02m x 2.25m - Ventana corrediza 2C - Aluminio + Vidrio:749516:1 | Nivel 3 |  | 1.02 | 2.25 | Qto_OpeningElementBaseQuantities - Depth: 0.115 m
C1030 - Puerta batiente - Madera + Metal:C1030 - 1.00 x 2.24 - Puerta batiente - Madera:749514:1 | Nivel 3 |  | 1 | 2.24 | Qto_OpeningElementBaseQuantities - Depth: 0.115 m
B2020 - Ventana corrediza - Aluminio+Vidrio:B2020 - 0.52 x 0.52 - Ventana corrediza - Aluminio+Vidrio:749567:1 | Nivel 3 |  | 0.52 | 0.52 | Qto_OpeningElementBaseQuantities - Depth: 0.125 m
C1030 - Puerta batiente - Madera+Aluminio:C1030 - 0.70 x 2.22 - Puerta batiente - Madera+ Metal:749581:1 | Nivel 3 |  | 0.7 | 2.22 | Qto_OpeningElementBaseQuantities - Depth: 0.135 m
B2020 - Ventana batiente - Aluminio + Vidrio:B2020 -0.52m x 1.1.25m - Ventana batiente 2C - Aluminio + Vidrio:1145670:1 | Nivel 3 |  | 0.52 | 1.25 | Qto_OpeningElementBaseQuantities - Depth: 0.115 m
B2020 - Ventana corrediza 2C - Aluminio + Vidrio:B2020 - 0.90m x 2.25m - Ventana corrediza 2C - Aluminio + Vidrio:749689:1 | Nivel 3 |  | 0.9 | 2.25 | Qto_OpeningElementBaseQuantities - Depth: 0.115 m
B2020 - Ventana corrediza 2C - Aluminio + Vidrio:B2020 - 1.02m x 2.25m - Ventana corrediza 2C - Aluminio + Vidrio:749690:1 | Nivel 3 |  | 1.02 | 2.25 | Qto_OpeningElementBaseQuantities - Depth: 0.115 m
C1030 - Puerta batiente - Madera + Metal:C1030 - 1.00 x 2.24 - Puerta batiente - Madera:749688:1 | Nivel 3 |  | 1 | 2.24 | Qto_OpeningElementBaseQuantities - Depth: 0.115 m
B2020 - Ventana corrediza - Aluminio+Vidrio:B2020 - 0.52 x 0.52 - Ventana corrediza - Aluminio+Vidrio:749741:1 | Nivel 3 |  | 0.52 | 0.52 | Qto_OpeningElementBaseQuantities - Depth: 0.125 m
C1030 - Puerta batiente - Madera+Aluminio:C1030 - 0.70 x 2.22 - Puerta batiente - Madera+ Metal:749755:1 | Nivel 3 |  | 0.7 | 2.22 | Qto_OpeningElementBaseQuantities - Depth: 0.135 m
C1030 - Puerta batiente - Madera + Metal:C1030 - 1.00 x 2.24 - Puerta batiente - Madera:1084530:1 | Nivel 4 |  | 1 | 2.24 | Qto_OpeningElementBaseQuantities - Depth: 0.115 m
B2020 - Ventana corrediza - Aluminio+Vidrio:B2020 - 0.52 x 0.52 - Ventana corrediza - Aluminio+Vidrio:750764:1 | Nivel 4 |  | 0.52 | 0.52 | Qto_OpeningElementBaseQuantities - Depth: 0.125 m
C1030 - Puerta batiente - Madera+Aluminio:C1030 - 0.70 x 2.22 - Puerta batiente - Madera+ Metal:750780:1 | Nivel 4 |  | 0.7 | 2.22 | Qto_OpeningElementBaseQuantities - Depth: 0.135 m
C1030 - Puerta batiente - Madera + Metal:C1030 - 1.00 x 2.24 - Puerta batiente - Madera:750879:1 | Nivel 4 |  | 1 | 2.24 | Qto_OpeningElementBaseQuantities - Depth: 0.115 m
B2020 - Ventana corrediza - Aluminio+Vidrio:B2020 - 0.52 x 0.52 - Ventana corrediza - Aluminio+Vidrio:750932:1 | Nivel 4 |  | 0.52 | 0.52 | Qto_OpeningElementBaseQuantities - Depth: 0.125 m
C1030 - Puerta batiente - Madera+Aluminio:C1030 - 0.70 x 2.22 - Puerta batiente - Madera+ Metal:750946:1 | Nivel 4 |  | 0.7 | 2.22 | Qto_OpeningElementBaseQuantities - Depth: 0.135 m
B2020 - Ventana batiente - Aluminio + Vidrio:B2020 -0.52m x 1.1.25m - Ventana batiente 2C - Aluminio + Vidrio:1145675:1 | Nivel 4 |  | 0.52 | 1.25 | Qto_OpeningElementBaseQuantities - Depth: 0.115 m
C1030 - Puerta batiente - Madera + Metal:C1030 - 1.00 x 2.24 - Puerta batiente - Madera:751081:1 | Nivel 4 |  | 1 | 2.24 | Qto_OpeningElementBaseQuantities - Depth: 0.115 m
B2020 - Ventana corrediza - Aluminio+Vidrio:B2020 - 0.52 x 0.52 - Ventana corrediza - Aluminio+Vidrio:751134:1 | Nivel 4 |  | 0.52 | 0.52 | Qto_OpeningElementBaseQuantities - Depth: 0.125 m
C1030 - Puerta batiente - Madera+Aluminio:C1030 - 0.70 x 2.22 - Puerta batiente - Madera+ Metal:751148:1 | Nivel 4 |  | 0.7 | 2.22 | Qto_OpeningElementBaseQuantities - Depth: 0.135 m
B2020 - Ventana batiente - Aluminio + Vidrio:B2020 -0.52m x 1.1.25m - Ventana batiente 2C - Aluminio + Vidrio:1145676:1 | Nivel 4 |  | 0.52 | 1.25 | Qto_OpeningElementBaseQuantities - Depth: 0.115 m
C1030 - Puerta batiente - Madera + Metal:C1030 - 1.00 x 2.24 - Puerta batiente - Madera:751255:1 | Nivel 4 |  | 1 | 2.24 | Qto_OpeningElementBaseQuantities - Depth: 0.115 m
B2020 - Ventana corrediza - Aluminio+Vidrio:B2020 - 0.52 x 0.52 - Ventana corrediza - Aluminio+Vidrio:751308:1 | Nivel 4 |  | 0.52 | 0.52 | Qto_OpeningElementBaseQuantities - Depth: 0.125 m
C1030 - Puerta batiente - Madera+Aluminio:C1030 - 0.70 x 2.22 - Puerta batiente - Madera+ Metal:751322:1 | Nivel 4 |  | 0.7 | 2.22 | Qto_OpeningElementBaseQuantities - Depth: 0.135 m
B2020 - Ventana corrediza 2C - Aluminio + Vidrio:B2020 - 0.90m x 2.25m - Ventana corrediza 2C - Aluminio + Vidrio:752279:1 | Nivel 5 |  | 0.9 | 2.25 | Qto_OpeningElementBaseQuantities - Depth: 0.115 m
B2020 - Ventana corrediza 2C - Aluminio + Vidrio:B2020 - 1.02m x 2.25m - Ventana corrediza 2C - Aluminio + Vidrio:752280:1 | Nivel 5 |  | 1.02 | 2.25 | Qto_OpeningElementBaseQuantities - Depth: 0.115 m
C1030 - Puerta batiente - Madera + Metal:C1030 - 1.00 x 2.24 - Puerta batiente - Madera:1084570:1 | Nivel 5 |  | 1 | 2.24 | Qto_OpeningElementBaseQuantities - Depth: 0.115 m
B2020 - Ventana corrediza - Aluminio+Vidrio:B2020 - 0.52 x 0.52 - Ventana corrediza - Aluminio+Vidrio:752331:1 | Nivel 5 |  | 0.52 | 0.52 | Qto_OpeningElementBaseQuantities - Depth: 0.125 m
C1030 - Puerta batiente - Madera+Aluminio:C1030 - 0.70 x 2.22 - Puerta batiente - Madera+ Metal:752347:1 | Nivel 5 |  | 0.7 | 2.22 | Qto_OpeningElementBaseQuantities - Depth: 0.135 m
B2020 - Ventana corrediza 2C - Aluminio + Vidrio:B2020 - 1.02m x 2.25m - Ventana corrediza 2C - Aluminio + Vidrio:752448:1 | Nivel 5 |  | 1.02 | 2.25 | Qto_OpeningElementBaseQuantities - Depth: 0.115 m
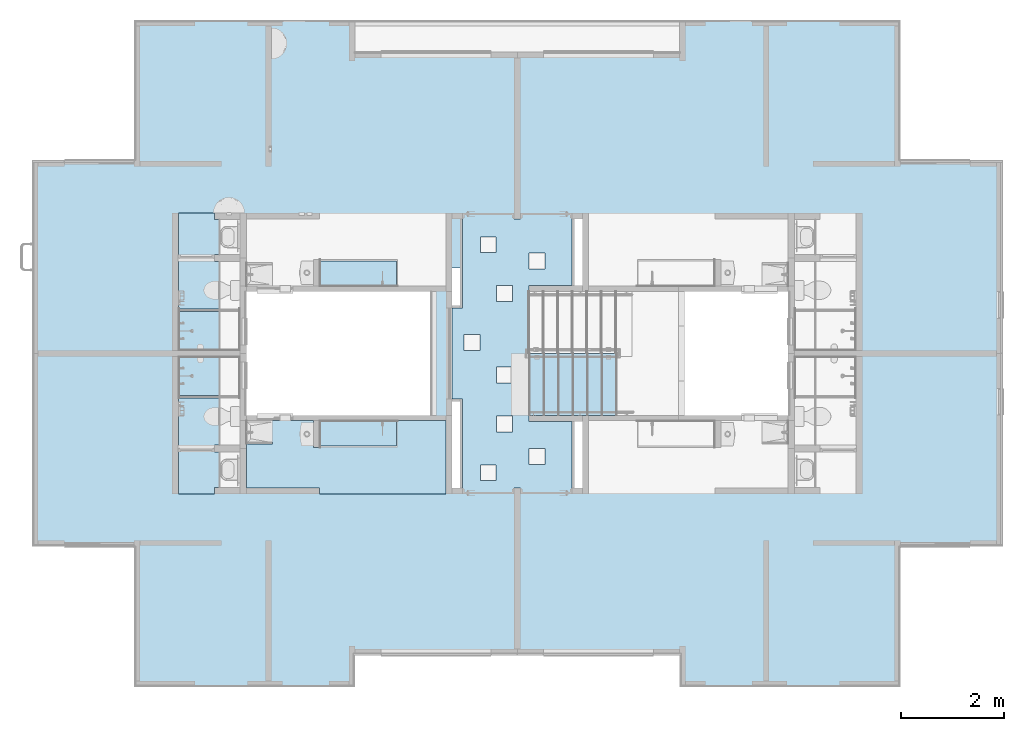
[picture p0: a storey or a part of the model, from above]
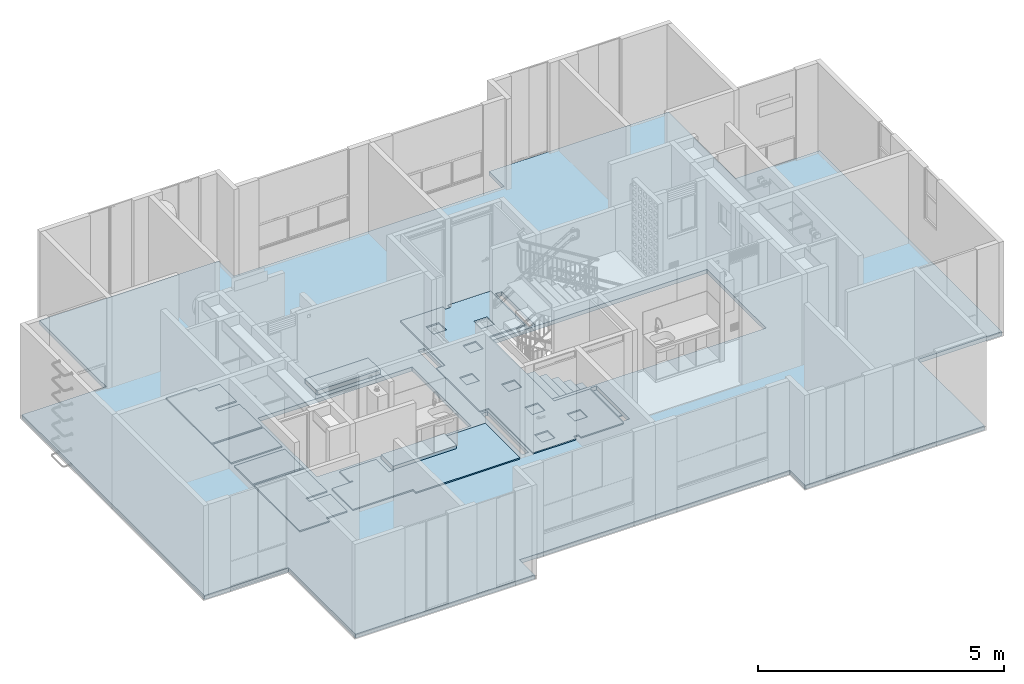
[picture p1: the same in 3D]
Properties of the parts of a building model (IFC4), part 3 of 6

# IfcOpeningElement (605)
Name | In | Classification | Height (m) | Width (m) | Reference | sets with these values
B2020 - Ventana corrediza 2C - Aluminio + Vidrio:B2020 - 0.90m x 2.25m - Ventana corrediza 2C - Aluminio + Vidrio:752447:1 | Nivel 5 |  | 0.9 | 2.25 | Qto_OpeningElementBaseQuantities - Depth: 0.115 m
C1030 - Puerta batiente - Madera + Metal:C1030 - 1.00 x 2.24 - Puerta batiente - Madera:752446:1 | Nivel 5 |  | 1 | 2.24 | Qto_OpeningElementBaseQuantities - Depth: 0.115 m
B2020 - Ventana corrediza - Aluminio+Vidrio:B2020 - 0.52 x 0.52 - Ventana corrediza - Aluminio+Vidrio:752499:1 | Nivel 5 |  | 0.52 | 0.52 | Qto_OpeningElementBaseQuantities - Depth: 0.125 m
C1030 - Puerta batiente - Madera+Aluminio:C1030 - 0.70 x 2.22 - Puerta batiente - Madera+ Metal:752513:1 | Nivel 5 |  | 0.7 | 2.22 | Qto_OpeningElementBaseQuantities - Depth: 0.135 m
B2020 - Ventana batiente - Aluminio + Vidrio:B2020 -0.52m x 1.1.25m - Ventana batiente 2C - Aluminio + Vidrio:1145681:1 | Nivel 5 |  | 0.52 | 1.25 | Qto_OpeningElementBaseQuantities - Depth: 0.115 m
B2020 - Ventana corrediza 2C - Aluminio + Vidrio:B2020 - 0.90m x 2.25m - Ventana corrediza 2C - Aluminio + Vidrio:752649:1 | Nivel 5 |  | 0.9 | 2.25 | Qto_OpeningElementBaseQuantities - Depth: 0.115 m
B2020 - Ventana corrediza 2C - Aluminio + Vidrio:B2020 - 1.02m x 2.25m - Ventana corrediza 2C - Aluminio + Vidrio:752650:1 | Nivel 5 |  | 1.02 | 2.25 | Qto_OpeningElementBaseQuantities - Depth: 0.115 m
C1030 - Puerta batiente - Madera + Metal:C1030 - 1.00 x 2.24 - Puerta batiente - Madera:752648:1 | Nivel 5 |  | 1 | 2.24 | Qto_OpeningElementBaseQuantities - Depth: 0.115 m
B2020 - Ventana corrediza - Aluminio+Vidrio:B2020 - 0.52 x 0.52 - Ventana corrediza - Aluminio+Vidrio:752701:1 | Nivel 5 |  | 0.52 | 0.52 | Qto_OpeningElementBaseQuantities - Depth: 0.125 m
C1030 - Puerta batiente - Madera+Aluminio:C1030 - 0.70 x 2.22 - Puerta batiente - Madera+ Metal:752715:1 | Nivel 5 |  | 0.7 | 2.22 | Qto_OpeningElementBaseQuantities - Depth: 0.135 m
B2020 - Ventana batiente - Aluminio + Vidrio:B2020 -0.52m x 1.1.25m - Ventana batiente 2C - Aluminio + Vidrio:1145682:1 | Nivel 5 |  | 0.52 | 1.25 | Qto_OpeningElementBaseQuantities - Depth: 0.115 m
B2020 - Ventana corrediza 2C - Aluminio + Vidrio:B2020 - 0.90m x 2.25m - Ventana corrediza 2C - Aluminio + Vidrio:752823:1 | Nivel 5 |  | 0.9 | 2.25 | Qto_OpeningElementBaseQuantities - Depth: 0.115 m
B2020 - Ventana corrediza 2C - Aluminio + Vidrio:B2020 - 1.02m x 2.25m - Ventana corrediza 2C - Aluminio + Vidrio:752824:1 | Nivel 5 |  | 1.02 | 2.25 | Qto_OpeningElementBaseQuantities - Depth: 0.115 m
C1030 - Puerta batiente - Madera + Metal:C1030 - 1.00 x 2.24 - Puerta batiente - Madera:752822:1 | Nivel 5 |  | 1 | 2.24 | Qto_OpeningElementBaseQuantities - Depth: 0.115 m
B2020 - Ventana corrediza - Aluminio+Vidrio:B2020 - 0.52 x 0.52 - Ventana corrediza - Aluminio+Vidrio:752875:1 | Nivel 5 |  | 0.52 | 0.52 | Qto_OpeningElementBaseQuantities - Depth: 0.125 m
C1030 - Puerta batiente - Madera+Aluminio:C1030 - 0.70 x 2.22 - Puerta batiente - Madera+ Metal:752889:1 | Nivel 5 |  | 0.7 | 2.22 | Qto_OpeningElementBaseQuantities - Depth: 0.135 m
C1030 - Puerta batiente - Madera + Metal:C1030 - 1.00 x 2.24 - Puerta batiente - Madera:1084500:1 | Nivel 6 |  | 1 | 2.24 | Qto_OpeningElementBaseQuantities - Depth: 0.115 m
B2020 - Ventana corrediza - Aluminio+Vidrio:B2020 - 0.52 x 0.52 - Ventana corrediza - Aluminio+Vidrio:753898:1 | Nivel 6 |  | 0.52 | 0.52 | Qto_OpeningElementBaseQuantities - Depth: 0.125 m
C1030 - Puerta batiente - Madera+Aluminio:C1030 - 0.70 x 2.22 - Puerta batiente - Madera+ Metal:753914:1 | Nivel 6 |  | 0.7 | 2.22 | Qto_OpeningElementBaseQuantities - Depth: 0.135 m
C1030 - Puerta batiente - Madera + Metal:C1030 - 1.00 x 2.24 - Puerta batiente - Madera:754013:1 | Nivel 6 |  | 1 | 2.24 | Qto_OpeningElementBaseQuantities - Depth: 0.115 m
B2020 - Ventana corrediza - Aluminio+Vidrio:B2020 - 0.52 x 0.52 - Ventana corrediza - Aluminio+Vidrio:754066:1 | Nivel 6 |  | 0.52 | 0.52 | Qto_OpeningElementBaseQuantities - Depth: 0.125 m
C1030 - Puerta batiente - Madera+Aluminio:C1030 - 0.70 x 2.22 - Puerta batiente - Madera+ Metal:754080:1 | Nivel 6 |  | 0.7 | 2.22 | Qto_OpeningElementBaseQuantities - Depth: 0.135 m
B2020 - Ventana batiente - Aluminio + Vidrio:B2020 -0.52m x 1.1.25m - Ventana batiente 2C - Aluminio + Vidrio:1145687:1 | Nivel 6 |  | 0.52 | 1.25 | Qto_OpeningElementBaseQuantities - Depth: 0.115 m
C1030 - Puerta batiente - Madera + Metal:C1030 - 1.00 x 2.24 - Puerta batiente - Madera:754215:1 | Nivel 6 |  | 1 | 2.24 | Qto_OpeningElementBaseQuantities - Depth: 0.115 m
B2020 - Ventana corrediza - Aluminio+Vidrio:B2020 - 0.52 x 0.52 - Ventana corrediza - Aluminio+Vidrio:754268:1 | Nivel 6 |  | 0.52 | 0.52 | Qto_OpeningElementBaseQuantities - Depth: 0.125 m
C1030 - Puerta batiente - Madera+Aluminio:C1030 - 0.70 x 2.22 - Puerta batiente - Madera+ Metal:754282:1 | Nivel 6 |  | 0.7 | 2.22 | Qto_OpeningElementBaseQuantities - Depth: 0.135 m
B2020 - Ventana batiente - Aluminio + Vidrio:B2020 -0.52m x 1.1.25m - Ventana batiente 2C - Aluminio + Vidrio:1145688:1 | Nivel 6 |  | 0.52 | 1.25 | Qto_OpeningElementBaseQuantities - Depth: 0.115 m
C1030 - Puerta batiente - Madera + Metal:C1030 - 1.00 x 2.24 - Puerta batiente - Madera:754389:1 | Nivel 6 |  | 1 | 2.24 | Qto_OpeningElementBaseQuantities - Depth: 0.115 m
B2020 - Ventana corrediza - Aluminio+Vidrio:B2020 - 0.52 x 0.52 - Ventana corrediza - Aluminio+Vidrio:754442:1 | Nivel 6 |  | 0.52 | 0.52 | Qto_OpeningElementBaseQuantities - Depth: 0.125 m
C1030 - Puerta batiente - Madera+Aluminio:C1030 - 0.70 x 2.22 - Puerta batiente - Madera+ Metal:754456:1 | Nivel 6 |  | 0.7 | 2.22 | Qto_OpeningElementBaseQuantities - Depth: 0.135 m
B2020 - Ventana corrediza 2C - Aluminio + Vidrio:B2020 - 1.02m x 2.25m - Ventana corrediza 2C - Aluminio + Vidrio:781257:1 | Nivel 1 |  | 1.02 | 2.25 | Qto_OpeningElementBaseQuantities - Depth: 0.115 m
B2020 - Ventana corrediza 2C - Aluminio + Vidrio:B2020 - 0.90m x 2.25m - Ventana corrediza 2C - Aluminio + Vidrio:781256:1 | Nivel 1 |  | 0.9 | 2.25 | Qto_OpeningElementBaseQuantities - Depth: 0.115 m
C1030 - Puerta batiente - Madera+Aluminio:C1030 - 0.70 x 2.22 - Puerta batiente - Madera+ Metal:781322:1 | Nivel 1 |  | 0.7 | 2.22 | Qto_OpeningElementBaseQuantities - Depth: 0.135 m
C1030 - Puerta batiente - Aluminio+Vidrio:C1030 - 0.70 x 2.00 - Puerta batiente - Aluminio + Vidrio:869196:1 | Nivel 1 |  | 0.7 | 2 | Qto_OpeningElementBaseQuantities - Depth: 0.101 m
C1030 - Puerta batiente - Madera + Metal:C1030 - 1.00 x 2.24 - Puerta batiente - Madera:782048:1 | Nivel 1 |  | 1 | 2.24 | Qto_OpeningElementBaseQuantities - Depth: 0.115 m
B2020 - Ventana corrediza - Aluminio+Vidrio:B2020 - 0.52 x 0.52 - Ventana corrediza - Aluminio+Vidrio:781308:1 | Nivel 1 |  | 0.52 | 0.52 | Qto_OpeningElementBaseQuantities - Depth: 0.125 m
B2020 - Ventana corrediza - Aluminio + Vidrio:B2020 - 1.35m x 2.25m - Ventana corrediza 2C - Aluminio + Vidrio:781258:1 | Nivel 1 |  | 1.35 | 2.25 | Qto_OpeningElementBaseQuantities - Depth: 0.115 m
C1030 - Puerta batiente - Madera + Metal:C1030 - 1.00 x 2.24 - Puerta batiente - Madera:998479:1 | Nivel 2 |  | 1 | 2.24 | Qto_OpeningElementBaseQuantities - Depth: 0.115 m
B2020 - Ventana corrediza - Aluminio+Vidrio:B2020 - 0.52 x 0.52 - Ventana corrediza - Aluminio+Vidrio:791878:1 | Nivel 2 |  | 0.52 | 0.52 | Qto_OpeningElementBaseQuantities - Depth: 0.125 m
C1030 - Puerta batiente - Madera+Aluminio:C1030 - 0.70 x 2.22 - Puerta batiente - Madera+ Metal:791894:1 | Nivel 2 |  | 0.7 | 2.22 | Qto_OpeningElementBaseQuantities - Depth: 0.135 m
B2020 - Ventana corrediza con rejilla - Aluminio+Vidrio:B2020 - 1.15 x 0.70 - Ventana corrediza con rejilla - Aluminio+Vidrio:791896:1 | Nivel 2 |  | 0.7 | 1.15 | Qto_OpeningElementBaseQuantities - Depth: 0.101 m
B2070 - Rejilla de ventilación - Aluminio:B2070 - 0.15m x 0.20m - Rejilla de ventilación - Aluminio:791957:1 | Nivel 2 |  | 0.2 | 0.15 | Qto_OpeningElementBaseQuantities - Depth: 0.101 m
C1030 - Puerta batiente - Madera + Metal:C1030 - 1.00 x 2.24 - Puerta batiente - Madera:791992:1 | Nivel 2 |  | 1 | 2.24 | Qto_OpeningElementBaseQuantities - Depth: 0.115 m
B2020 - Ventana corrediza - Aluminio+Vidrio:B2020 - 0.52 x 0.52 - Ventana corrediza - Aluminio+Vidrio:792045:1 | Nivel 2 |  | 0.52 | 0.52 | Qto_OpeningElementBaseQuantities - Depth: 0.125 m
C1030 - Puerta batiente - Madera+Aluminio:C1030 - 0.70 x 2.22 - Puerta batiente - Madera+ Metal:792059:1 | Nivel 2 |  | 0.7 | 2.22 | Qto_OpeningElementBaseQuantities - Depth: 0.135 m
B2020 - Ventana batiente - Aluminio + Vidrio:B2020 -0.52m x 1.1.25m - Ventana batiente 2C - Aluminio + Vidrio:1143134:1 | Nivel 2 |  | 0.52 | 1.25 | Qto_OpeningElementBaseQuantities - Depth: 0.115 m
C1030 - Puerta batiente - Madera + Metal:C1030 - 1.00 x 2.24 - Puerta batiente - Madera:792190:1 | Nivel 2 |  | 1 | 2.24 | Qto_OpeningElementBaseQuantities - Depth: 0.115 m
B2020 - Ventana corrediza - Aluminio+Vidrio:B2020 - 0.52 x 0.52 - Ventana corrediza - Aluminio+Vidrio:792243:1 | Nivel 2 |  | 0.52 | 0.52 | Qto_OpeningElementBaseQuantities - Depth: 0.125 m
C1030 - Puerta batiente - Madera+Aluminio:C1030 - 0.70 x 2.22 - Puerta batiente - Madera+ Metal:792257:1 | Nivel 2 |  | 0.7 | 2.22 | Qto_OpeningElementBaseQuantities - Depth: 0.135 m
B2020 - Ventana corrediza con rejilla - Aluminio+Vidrio:B2020 - 1.15 x 0.70 - Ventana corrediza con rejilla - Aluminio+Vidrio:792259:1 | Nivel 2 |  | 0.7 | 1.15 | Qto_OpeningElementBaseQuantities - Depth: 0.101 m
B2070 - Rejilla de ventilación - Aluminio:B2070 - 0.15m x 0.20m - Rejilla de ventilación - Aluminio:792320:1 | Nivel 2 |  | 0.2 | 0.15 | Qto_OpeningElementBaseQuantities - Depth: 0.101 m
B2020 - Ventana batiente - Aluminio + Vidrio:B2020 -0.52m x 1.1.25m - Ventana batiente 2C - Aluminio + Vidrio:1145660:1 | Nivel 2 |  | 0.52 | 1.25 | Qto_OpeningElementBaseQuantities - Depth: 0.115 m
C1030 - Puerta batiente - Madera + Metal:C1030 - 1.00 x 2.24 - Puerta batiente - Madera:792363:1 | Nivel 2 |  | 1 | 2.24 | Qto_OpeningElementBaseQuantities - Depth: 0.115 m
B2020 - Ventana corrediza - Aluminio+Vidrio:B2020 - 0.52 x 0.52 - Ventana corrediza - Aluminio+Vidrio:792416:1 | Nivel 2 |  | 0.52 | 0.52 | Qto_OpeningElementBaseQuantities - Depth: 0.125 m
C1030 - Puerta batiente - Madera+Aluminio:C1030 - 0.70 x 2.22 - Puerta batiente - Madera+ Metal:792430:1 | Nivel 2 |  | 0.7 | 2.22 | Qto_OpeningElementBaseQuantities - Depth: 0.135 m
B2020 - Ventana corrediza 2C - Aluminio + Vidrio:B2020 - 0.90m x 2.25m - Ventana corrediza 2C - Aluminio + Vidrio:801582:1 | Nivel 2 |  | 0.9 | 2.25 | Qto_OpeningElementBaseQuantities - Depth: 0.115 m
B2020 - Ventana corrediza 2C - Aluminio + Vidrio:B2020 - 1.02m x 2.25m - Ventana corrediza 2C - Aluminio + Vidrio:801583:1 | Nivel 2 |  | 1.02 | 2.25 | Qto_OpeningElementBaseQuantities - Depth: 0.115 m
B2020 - Ventana corrediza 2C - Aluminio + Vidrio:B2020 - 0.90m x 2.25m - Ventana corrediza 2C - Aluminio + Vidrio:801631:1 | Nivel 2 |  | 0.9 | 2.25 | Qto_OpeningElementBaseQuantities - Depth: 0.115 m
B2020 - Ventana corrediza 2C - Aluminio + Vidrio:B2020 - 1.02m x 2.25m - Ventana corrediza 2C - Aluminio + Vidrio:801632:1 | Nivel 2 |  | 1.02 | 2.25 | Qto_OpeningElementBaseQuantities - Depth: 0.115 m
B2020 - Ventana corrediza 2C - Aluminio + Vidrio:B2020 - 0.90m x 2.25m - Ventana corrediza 2C - Aluminio + Vidrio:801680:1 | Nivel 2 |  | 0.9 | 2.25 | Qto_OpeningElementBaseQuantities - Depth: 0.115 m
B2020 - Ventana corrediza 2C - Aluminio + Vidrio:B2020 - 1.02m x 2.25m - Ventana corrediza 2C - Aluminio + Vidrio:801681:1 | Nivel 2 |  | 1.02 | 2.25 | Qto_OpeningElementBaseQuantities - Depth: 0.115 m
B2020 - Ventana corrediza 2C - Aluminio + Vidrio:B2020 - 0.90m x 2.25m - Ventana corrediza 2C - Aluminio + Vidrio:801907:1 | Nivel 4 |  | 0.9 | 2.25 | Qto_OpeningElementBaseQuantities - Depth: 0.115 m
B2020 - Ventana corrediza 2C - Aluminio + Vidrio:B2020 - 1.02m x 2.25m - Ventana corrediza 2C - Aluminio + Vidrio:801908:1 | Nivel 4 |  | 1.02 | 2.25 | Qto_OpeningElementBaseQuantities - Depth: 0.115 m
B2020 - Ventana corrediza 2C - Aluminio + Vidrio:B2020 - 0.90m x 2.25m - Ventana corrediza 2C - Aluminio + Vidrio:801925:1 | Nivel 4 |  | 0.9 | 2.25 | Qto_OpeningElementBaseQuantities - Depth: 0.115 m
B2020 - Ventana corrediza 2C - Aluminio + Vidrio:B2020 - 1.02m x 2.25m - Ventana corrediza 2C - Aluminio + Vidrio:801926:1 | Nivel 4 |  | 1.02 | 2.25 | Qto_OpeningElementBaseQuantities - Depth: 0.115 m
B2020 - Ventana corrediza 2C - Aluminio + Vidrio:B2020 - 0.90m x 2.25m - Ventana corrediza 2C - Aluminio + Vidrio:801943:1 | Nivel 4 |  | 0.9 | 2.25 | Qto_OpeningElementBaseQuantities - Depth: 0.115 m
B2020 - Ventana corrediza 2C - Aluminio + Vidrio:B2020 - 1.02m x 2.25m - Ventana corrediza 2C - Aluminio + Vidrio:801944:1 | Nivel 4 |  | 1.02 | 2.25 | Qto_OpeningElementBaseQuantities - Depth: 0.115 m
B2020 - Ventana corrediza 2C - Aluminio + Vidrio:B2020 - 0.90m x 2.25m - Ventana corrediza 2C - Aluminio + Vidrio:801961:1 | Nivel 4 |  | 0.9 | 2.25 | Qto_OpeningElementBaseQuantities - Depth: 0.115 m
B2020 - Ventana corrediza 2C - Aluminio + Vidrio:B2020 - 1.02m x 2.25m - Ventana corrediza 2C - Aluminio + Vidrio:801962:1 | Nivel 4 |  | 1.02 | 2.25 | Qto_OpeningElementBaseQuantities - Depth: 0.115 m
B2020 - Ventana corrediza 2C - Aluminio + Vidrio:B2020 - 1.02m x 2.25m - Ventana corrediza 2C - Aluminio + Vidrio:802128:1 | Nivel 6 |  | 1.02 | 2.25 | Qto_OpeningElementBaseQuantities - Depth: 0.115 m
B2020 - Ventana corrediza 2C - Aluminio + Vidrio:B2020 - 0.90m x 2.25m - Ventana corrediza 2C - Aluminio + Vidrio:802127:1 | Nivel 6 |  | 0.9 | 2.25 | Qto_OpeningElementBaseQuantities - Depth: 0.115 m
B2020 - Ventana corrediza 2C - Aluminio + Vidrio:B2020 - 1.02m x 2.25m - Ventana corrediza 2C - Aluminio + Vidrio:802146:1 | Nivel 6 |  | 1.02 | 2.25 | Qto_OpeningElementBaseQuantities - Depth: 0.115 m
B2020 - Ventana corrediza 2C - Aluminio + Vidrio:B2020 - 0.90m x 2.25m - Ventana corrediza 2C - Aluminio + Vidrio:802145:1 | Nivel 6 |  | 0.9 | 2.25 | Qto_OpeningElementBaseQuantities - Depth: 0.115 m
B2020 - Ventana corrediza 2C - Aluminio + Vidrio:B2020 - 1.02m x 2.25m - Ventana corrediza 2C - Aluminio + Vidrio:802164:1 | Nivel 6 |  | 1.02 | 2.25 | Qto_OpeningElementBaseQuantities - Depth: 0.115 m
B2020 - Ventana corrediza 2C - Aluminio + Vidrio:B2020 - 0.90m x 2.25m - Ventana corrediza 2C - Aluminio + Vidrio:802163:1 | Nivel 6 |  | 0.9 | 2.25 | Qto_OpeningElementBaseQuantities - Depth: 0.115 m
B2020 - Ventana corrediza 2C - Aluminio + Vidrio:B2020 - 0.90m x 2.25m - Ventana corrediza 2C - Aluminio + Vidrio:802181:1 | Nivel 6 |  | 0.9 | 2.25 | Qto_OpeningElementBaseQuantities - Depth: 0.115 m
B2020 - Ventana corrediza 2C - Aluminio + Vidrio:B2020 - 1.02m x 2.25m - Ventana corrediza 2C - Aluminio + Vidrio:802182:1 | Nivel 6 |  | 1.02 | 2.25 | Qto_OpeningElementBaseQuantities - Depth: 0.115 m
B2020 - Ventana corrediza 2C - Aluminio + Vidrio:B2020 - 1.02m x 2.25m - Ventana corrediza 2C - Aluminio + Vidrio:872662:1 | Nivel 1 |  | 1.02 | 2.25 | Qto_OpeningElementBaseQuantities - Depth: 0.115 m
B2020 - Ventana corrediza 2C - Aluminio + Vidrio:B2020 - 0.90m x 2.25m - Ventana corrediza 2C - Aluminio + Vidrio:872661:1 | Nivel 1 |  | 0.9 | 2.25 | Qto_OpeningElementBaseQuantities - Depth: 0.115 m
B2020 - 6c Ventana corrediza - Aluminio + Vidrio:B2020 -2.13m x 1.750m - Ventana corrediza 2C - Aluminio + Vidrio:872689:1 | Nivel 1 |  | 2.125 | 1.75 | Qto_OpeningElementBaseQuantities - Depth: 0.115 m
C1030 - Puerta batiente - Aluminio+Vidrio:C1030 - 0.70 x 2.00 - Puerta batiente - Aluminio + Vidrio:872795:1 | Nivel 1 |  | 0.7 | 2 | Qto_OpeningElementBaseQuantities - Depth: 0.101 m
C1030 - Puerta batiente - Madera + Metal:C1030 - 1.00 x 2.24 - Puerta batiente - Madera:872660:1 | Nivel 1 |  | 1 | 2.24 | Qto_OpeningElementBaseQuantities - Depth: 0.115 m
B2020 - Ventana corrediza - Aluminio+Vidrio:B2020 - 0.52 x 0.52 - Ventana corrediza - Aluminio+Vidrio:872713:1 | Nivel 1 |  | 0.52 | 0.52 | Qto_OpeningElementBaseQuantities - Depth: 0.125 m
B2020 - Ventana corrediza - Aluminio + Vidrio:B2020 - 1.35m x 2.25m - Ventana corrediza 2C - Aluminio + Vidrio:872663:1 | Nivel 1 |  | 1.35 | 2.25 | Qto_OpeningElementBaseQuantities - Depth: 0.115 m
B2020 - Ventana corrediza 2C - Aluminio + Vidrio:B2020 - 1.02m x 2.25m - Ventana corrediza 2C - Aluminio + Vidrio:872860:1 | Nivel 1 |  | 1.02 | 2.25 | Qto_OpeningElementBaseQuantities - Depth: 0.115 m
B2020 - Ventana corrediza 2C - Aluminio + Vidrio:B2020 - 0.90m x 2.25m - Ventana corrediza 2C - Aluminio + Vidrio:872859:1 | Nivel 1 |  | 0.9 | 2.25 | Qto_OpeningElementBaseQuantities - Depth: 0.115 m
B2020 - 6c Ventana corrediza - Aluminio + Vidrio:B2020 -2.13m x 1.750m - Ventana corrediza 2C - Aluminio + Vidrio:872887:1 | Nivel 1 |  | 2.125 | 1.75 | Qto_OpeningElementBaseQuantities - Depth: 0.115 m
C1030 - Puerta batiente - Aluminio+Vidrio:C1030 - 0.70 x 2.00 - Puerta batiente - Aluminio + Vidrio:872982:1 | Nivel 1 |  | 0.7 | 2 | Qto_OpeningElementBaseQuantities - Depth: 0.101 m
C1030 - Puerta batiente - Madera + Metal:C1030 - 1.00 x 2.24 - Puerta batiente - Madera:872858:1 | Nivel 1 |  | 1 | 2.24 | Qto_OpeningElementBaseQuantities - Depth: 0.115 m
B2020 - Ventana corrediza - Aluminio+Vidrio:B2020 - 0.52 x 0.52 - Ventana corrediza - Aluminio+Vidrio:872911:1 | Nivel 1 |  | 0.52 | 0.52 | Qto_OpeningElementBaseQuantities - Depth: 0.125 m
B2020 - Ventana corrediza - Aluminio + Vidrio:B2020 - 1.35m x 2.25m - Ventana corrediza 2C - Aluminio + Vidrio:872861:1 | Nivel 1 |  | 1.35 | 2.25 | Qto_OpeningElementBaseQuantities - Depth: 0.115 m
B2020 - Ventana corrediza 2C - Aluminio + Vidrio:B2020 - 0.90m x 2.25m - Ventana corrediza 2C - Aluminio + Vidrio:998480:1 | Nivel 2 |  | 0.9 | 2.25 | Qto_OpeningElementBaseQuantities - Depth: 0.115 m
B2020 - Ventana corrediza 2C - Aluminio + Vidrio:B2020 - 1.02m x 2.25m - Ventana corrediza 2C - Aluminio + Vidrio:998481:1 | Nivel 2 |  | 1.02 | 2.25 | Qto_OpeningElementBaseQuantities - Depth: 0.115 m
B2020 - Ventana corrediza - Aluminio + Vidrio:B2020 - 1.35m x 2.25m - Ventana corrediza 2C - Aluminio + Vidrio:1250795:1 | Nivel 6 |  | 1.35 | 2.25 | Qto_OpeningElementBaseQuantities - Depth: 0.115 m
B2020 - Ventana corrediza - Aluminio + Vidrio:B2020 -1.26m x 1.750m - Ventana corrediza 2C - Aluminio + Vidrio:1141275:1 | Nivel 1 |  | 1.26 | 1.75 | Qto_OpeningElementBaseQuantities - Depth: 0.115 m
B2020 - 6c Ventana corrediza - Aluminio + Vidrio:B2020 -2.13m x 1.750m - Ventana corrediza 2C - Aluminio + Vidrio:1984315:1 | Nivel 2 |  | 2.125 | 1.75 | Qto_OpeningElementBaseQuantities - Depth: 0.115 m
B2020 - 6c Ventana corrediza - Aluminio + Vidrio:B2020 -2.13m x 1.750m - Ventana corrediza 2C - Aluminio + Vidrio:1984267:1 | Nivel 3 |  | 2.125 | 1.75 | Qto_OpeningElementBaseQuantities - Depth: 0.115 m
B2020 - 6c Ventana corrediza - Aluminio + Vidrio:B2020 -2.13m x 1.750m - Ventana corrediza 2C - Aluminio + Vidrio:1984270:1 | Nivel 3 |  | 2.125 | 1.75 | Qto_OpeningElementBaseQuantities - Depth: 0.115 m
B2020 - 6c Ventana corrediza - Aluminio + Vidrio:B2020 -2.13m x 1.750m - Ventana corrediza 2C - Aluminio + Vidrio:1984273:1 | Nivel 3 |  | 2.125 | 1.75 | Qto_OpeningElementBaseQuantities - Depth: 0.115 m
B2020 - 6c Ventana corrediza - Aluminio + Vidrio:B2020 -2.13m x 1.750m - Ventana corrediza 2C - Aluminio + Vidrio:1984276:1 | Nivel 3 |  | 2.125 | 1.75 | Qto_OpeningElementBaseQuantities - Depth: 0.115 m
B2020 - 6c Ventana corrediza - Aluminio + Vidrio:B2020 -2.13m x 1.750m - Ventana corrediza 2C - Aluminio + Vidrio:1984279:1 | Nivel 4 |  | 2.125 | 1.75 | Qto_OpeningElementBaseQuantities - Depth: 0.115 m
B2020 - 6c Ventana corrediza - Aluminio + Vidrio:B2020 -2.13m x 1.750m - Ventana corrediza 2C - Aluminio + Vidrio:1984282:1 | Nivel 4 |  | 2.125 | 1.75 | Qto_OpeningElementBaseQuantities - Depth: 0.115 m
B2020 - 6c Ventana corrediza - Aluminio + Vidrio:B2020 -2.13m x 1.750m - Ventana corrediza 2C - Aluminio + Vidrio:1984285:1 | Nivel 4 |  | 2.125 | 1.75 | Qto_OpeningElementBaseQuantities - Depth: 0.115 m
B2020 - 6c Ventana corrediza - Aluminio + Vidrio:B2020 -2.13m x 1.750m - Ventana corrediza 2C - Aluminio + Vidrio:1984288:1 | Nivel 4 |  | 2.125 | 1.75 | Qto_OpeningElementBaseQuantities - Depth: 0.115 m
B2020 - 6c Ventana corrediza - Aluminio + Vidrio:B2020 -2.13m x 1.750m - Ventana corrediza 2C - Aluminio + Vidrio:1984291:1 | Nivel 5 |  | 2.125 | 1.75 | Qto_OpeningElementBaseQuantities - Depth: 0.115 m
B2020 - 6c Ventana corrediza - Aluminio + Vidrio:B2020 -2.13m x 1.750m - Ventana corrediza 2C - Aluminio + Vidrio:1984294:1 | Nivel 5 |  | 2.125 | 1.75 | Qto_OpeningElementBaseQuantities - Depth: 0.115 m
B2020 - 6c Ventana corrediza - Aluminio + Vidrio:B2020 -2.13m x 1.750m - Ventana corrediza 2C - Aluminio + Vidrio:1984297:1 | Nivel 5 |  | 2.125 | 1.75 | Qto_OpeningElementBaseQuantities - Depth: 0.115 m
B2020 - 6c Ventana corrediza - Aluminio + Vidrio:B2020 -2.13m x 1.750m - Ventana corrediza 2C - Aluminio + Vidrio:1984300:1 | Nivel 5 |  | 2.125 | 1.75 | Qto_OpeningElementBaseQuantities - Depth: 0.115 m
B2020 - 6c Ventana corrediza - Aluminio + Vidrio:B2020 -2.13m x 1.750m - Ventana corrediza 2C - Aluminio + Vidrio:1984303:1 | Nivel 6 |  | 2.125 | 1.75 | Qto_OpeningElementBaseQuantities - Depth: 0.115 m
B2020 - 6c Ventana corrediza - Aluminio + Vidrio:B2020 -2.13m x 1.750m - Ventana corrediza 2C - Aluminio + Vidrio:1984306:1 | Nivel 6 |  | 2.125 | 1.75 | Qto_OpeningElementBaseQuantities - Depth: 0.115 m
B2020 - 6c Ventana corrediza - Aluminio + Vidrio:B2020 -2.13m x 1.750m - Ventana corrediza 2C - Aluminio + Vidrio:1984309:1 | Nivel 6 |  | 2.125 | 1.75 | Qto_OpeningElementBaseQuantities - Depth: 0.115 m
B2020 - 6c Ventana corrediza - Aluminio + Vidrio:B2020 -2.13m x 1.750m - Ventana corrediza 2C - Aluminio + Vidrio:1984312:1 | Nivel 6 |  | 2.125 | 1.75 | Qto_OpeningElementBaseQuantities - Depth: 0.115 m
B2020 - 6c Ventana corrediza - Aluminio + Vidrio:B2020 -2.13m x 1.750m - Ventana corrediza 2C - Aluminio + Vidrio:1984318:1 | Nivel 2 |  | 2.125 | 1.75 | Qto_OpeningElementBaseQuantities - Depth: 0.115 m
B2020 - 6c Ventana corrediza - Aluminio + Vidrio:B2020 -2.13m x 1.750m - Ventana corrediza 2C - Aluminio + Vidrio:1984321:1 | Nivel 2 |  | 2.125 | 1.75 | Qto_OpeningElementBaseQuantities - Depth: 0.115 m
B2020 - 6c Ventana corrediza - Aluminio + Vidrio:B2020 -2.13m x 1.750m - Ventana corrediza 2C - Aluminio + Vidrio:1984143:1 | Nivel 2 |  | 2.125 | 1.75 | Qto_OpeningElementBaseQuantities - Depth: 0.115 m
B2020 - Ventana corrediza con rejilla - Aluminio+Vidrio:B2020 - 1.15 x 0.70 - Ventana corrediza con rejilla - Aluminio+Vidrio:1330990:1 | Nivel 2 |  | 0.7 | 1.15 | Qto_OpeningElementBaseQuantities - Depth: 0.101 m
B2070 - Rejilla de ventilación - Aluminio:B2070 - 0.15m x 0.20m - Rejilla de ventilación - Aluminio:1330991:1 | Nivel 2 |  | 0.2 | 0.15 | Qto_OpeningElementBaseQuantities - Depth: 0.101 m
B2020 - Ventana corrediza con rejilla - Aluminio+Vidrio:B2020 - 1.15 x 0.70 - Ventana corrediza con rejilla - Aluminio+Vidrio:1330992:1 | Nivel 2 |  | 0.7 | 1.15 | Qto_OpeningElementBaseQuantities - Depth: 0.101 m
B2070 - Rejilla de ventilación - Aluminio:B2070 - 0.15m x 0.20m - Rejilla de ventilación - Aluminio:1330993:1 | Nivel 2 |  | 0.2 | 0.15 | Qto_OpeningElementBaseQuantities - Depth: 0.101 m
B2020 - Ventana corrediza con rejilla - Aluminio+Vidrio:B2020 - 1.15 x 0.70 - Ventana corrediza con rejilla - Aluminio+Vidrio:1332195:1 | Nivel 3 |  | 0.7 | 1.15 | Qto_OpeningElementBaseQuantities - Depth: 0.101 m
B2070 - Rejilla de ventilación - Aluminio:B2070 - 0.15m x 0.20m - Rejilla de ventilación - Aluminio:1332196:1 | Nivel 3 |  | 0.2 | 0.15 | Qto_OpeningElementBaseQuantities - Depth: 0.101 m
B2020 - Ventana corrediza con rejilla - Aluminio+Vidrio:B2020 - 1.15 x 0.70 - Ventana corrediza con rejilla - Aluminio+Vidrio:1332198:1 | Nivel 3 |  | 0.7 | 1.15 | Qto_OpeningElementBaseQuantities - Depth: 0.101 m
B2070 - Rejilla de ventilación - Aluminio:B2070 - 0.15m x 0.20m - Rejilla de ventilación - Aluminio:1332199:1 | Nivel 3 |  | 0.2 | 0.15 | Qto_OpeningElementBaseQuantities - Depth: 0.101 m
B2020 - Ventana corrediza con rejilla - Aluminio+Vidrio:B2020 - 1.15 x 0.70 - Ventana corrediza con rejilla - Aluminio+Vidrio:1332207:1 | Nivel 4 |  | 0.7 | 1.15 | Qto_OpeningElementBaseQuantities - Depth: 0.101 m
B2070 - Rejilla de ventilación - Aluminio:B2070 - 0.15m x 0.20m - Rejilla de ventilación - Aluminio:1332208:1 | Nivel 4 |  | 0.2 | 0.15 | Qto_OpeningElementBaseQuantities - Depth: 0.101 m
B2020 - Ventana corrediza con rejilla - Aluminio+Vidrio:B2020 - 1.15 x 0.70 - Ventana corrediza con rejilla - Aluminio+Vidrio:1332210:1 | Nivel 4 |  | 0.7 | 1.15 | Qto_OpeningElementBaseQuantities - Depth: 0.101 m
B2070 - Rejilla de ventilación - Aluminio:B2070 - 0.15m x 0.20m - Rejilla de ventilación - Aluminio:1332211:1 | Nivel 4 |  | 0.2 | 0.15 | Qto_OpeningElementBaseQuantities - Depth: 0.101 m
B2020 - Ventana corrediza con rejilla - Aluminio+Vidrio:B2020 - 1.15 x 0.70 - Ventana corrediza con rejilla - Aluminio+Vidrio:1332219:1 | Nivel 5 |  | 0.7 | 1.15 | Qto_OpeningElementBaseQuantities - Depth: 0.101 m
B2070 - Rejilla de ventilación - Aluminio:B2070 - 0.15m x 0.20m - Rejilla de ventilación - Aluminio:1332220:1 | Nivel 5 |  | 0.2 | 0.15 | Qto_OpeningElementBaseQuantities - Depth: 0.101 m
B2020 - Ventana corrediza con rejilla - Aluminio+Vidrio:B2020 - 1.15 x 0.70 - Ventana corrediza con rejilla - Aluminio+Vidrio:1332222:1 | Nivel 5 |  | 0.7 | 1.15 | Qto_OpeningElementBaseQuantities - Depth: 0.101 m
B2070 - Rejilla de ventilación - Aluminio:B2070 - 0.15m x 0.20m - Rejilla de ventilación - Aluminio:1332223:1 | Nivel 5 |  | 0.2 | 0.15 | Qto_OpeningElementBaseQuantities - Depth: 0.101 m
B2020 - Ventana corrediza con rejilla - Aluminio+Vidrio:B2020 - 1.15 x 0.70 - Ventana corrediza con rejilla - Aluminio+Vidrio:1332231:1 | Nivel 6 |  | 0.7 | 1.15 | Qto_OpeningElementBaseQuantities - Depth: 0.101 m
B2070 - Rejilla de ventilación - Aluminio:B2070 - 0.15m x 0.20m - Rejilla de ventilación - Aluminio:1332232:1 | Nivel 6 |  | 0.2 | 0.15 | Qto_OpeningElementBaseQuantities - Depth: 0.101 m
B2020 - Ventana corrediza con rejilla - Aluminio+Vidrio:B2020 - 1.15 x 0.70 - Ventana corrediza con rejilla - Aluminio+Vidrio:1332234:1 | Nivel 6 |  | 0.7 | 1.15 | Qto_OpeningElementBaseQuantities - Depth: 0.101 m
B2070 - Rejilla de ventilación - Aluminio:B2070 - 0.15m x 0.20m - Rejilla de ventilación - Aluminio:1332235:1 | Nivel 6 |  | 0.2 | 0.15 | Qto_OpeningElementBaseQuantities - Depth: 0.101 m
B2020 - Ventana corrediza con rejilla - Aluminio+Vidrio:B2020 - 1.15 x 0.70 - Ventana corrediza con rejilla - Aluminio+Vidrio:1332444:1 | Nivel 3 |  | 0.7 | 1.15 | Qto_OpeningElementBaseQuantities - Depth: 0.101 m
B2070 - Rejilla de ventilación - Aluminio:B2070 - 0.15m x 0.20m - Rejilla de ventilación - Aluminio:1332445:1 | Nivel 3 |  | 0.2 | 0.15 | Qto_OpeningElementBaseQuantities - Depth: 0.101 m
B2020 - Ventana corrediza con rejilla - Aluminio+Vidrio:B2020 - 1.15 x 0.70 - Ventana corrediza con rejilla - Aluminio+Vidrio:1332447:1 | Nivel 3 |  | 0.7 | 1.15 | Qto_OpeningElementBaseQuantities - Depth: 0.101 m
B2070 - Rejilla de ventilación - Aluminio:B2070 - 0.15m x 0.20m - Rejilla de ventilación - Aluminio:1332448:1 | Nivel 3 |  | 0.2 | 0.15 | Qto_OpeningElementBaseQuantities - Depth: 0.101 m
B2020 - Ventana corrediza con rejilla - Aluminio+Vidrio:B2020 - 1.15 x 0.70 - Ventana corrediza con rejilla - Aluminio+Vidrio:1332471:1 | Nivel 4 |  | 0.7 | 1.15 | Qto_OpeningElementBaseQuantities - Depth: 0.101 m
B2070 - Rejilla de ventilación - Aluminio:B2070 - 0.15m x 0.20m - Rejilla de ventilación - Aluminio:1332472:1 | Nivel 4 |  | 0.2 | 0.15 | Qto_OpeningElementBaseQuantities - Depth: 0.101 m
B2020 - Ventana corrediza con rejilla - Aluminio+Vidrio:B2020 - 1.15 x 0.70 - Ventana corrediza con rejilla - Aluminio+Vidrio:1332474:1 | Nivel 4 |  | 0.7 | 1.15 | Qto_OpeningElementBaseQuantities - Depth: 0.101 m
B2070 - Rejilla de ventilación - Aluminio:B2070 - 0.15m x 0.20m - Rejilla de ventilación - Aluminio:1332475:1 | Nivel 4 |  | 0.2 | 0.15 | Qto_OpeningElementBaseQuantities - Depth: 0.101 m
B2020 - Ventana corrediza con rejilla - Aluminio+Vidrio:B2020 - 1.15 x 0.70 - Ventana corrediza con rejilla - Aluminio+Vidrio:1332498:1 | Nivel 5 |  | 0.7 | 1.15 | Qto_OpeningElementBaseQuantities - Depth: 0.101 m
B2070 - Rejilla de ventilación - Aluminio:B2070 - 0.15m x 0.20m - Rejilla de ventilación - Aluminio:1332499:1 | Nivel 5 |  | 0.2 | 0.15 | Qto_OpeningElementBaseQuantities - Depth: 0.101 m
B2020 - Ventana corrediza con rejilla - Aluminio+Vidrio:B2020 - 1.15 x 0.70 - Ventana corrediza con rejilla - Aluminio+Vidrio:1332501:1 | Nivel 5 |  | 0.7 | 1.15 | Qto_OpeningElementBaseQuantities - Depth: 0.101 m
B2070 - Rejilla de ventilación - Aluminio:B2070 - 0.15m x 0.20m - Rejilla de ventilación - Aluminio:1332502:1 | Nivel 5 |  | 0.2 | 0.15 | Qto_OpeningElementBaseQuantities - Depth: 0.101 m
B2020 - Ventana corrediza con rejilla - Aluminio+Vidrio:B2020 - 1.15 x 0.70 - Ventana corrediza con rejilla - Aluminio+Vidrio:1332544:1 | Nivel 6 |  | 0.7 | 1.15 | Qto_OpeningElementBaseQuantities - Depth: 0.101 m
B2070 - Rejilla de ventilación - Aluminio:B2070 - 0.15m x 0.20m - Rejilla de ventilación - Aluminio:1332545:1 | Nivel 6 |  | 0.2 | 0.15 | Qto_OpeningElementBaseQuantities - Depth: 0.101 m
B2020 - Ventana corrediza con rejilla - Aluminio+Vidrio:B2020 - 1.15 x 0.70 - Ventana corrediza con rejilla - Aluminio+Vidrio:1332547:1 | Nivel 6 |  | 0.7 | 1.15 | Qto_OpeningElementBaseQuantities - Depth: 0.101 m
B2070 - Rejilla de ventilación - Aluminio:B2070 - 0.15m x 0.20m - Rejilla de ventilación - Aluminio:1332548:1 | Nivel 6 |  | 0.2 | 0.15 | Qto_OpeningElementBaseQuantities - Depth: 0.101 m

# IfcRailing: Baranda perimetral piso 1:B1080- Baranda Piso Tipo- metálica (5)
Type - Material: platina, PASAMANOS
Type - Pset_RailingCommon - IsExternal: no
Classification: 21-02 10 80 50 Uniformat (Uniformat)
Pset_EnvironmentalImpactIndicators - Reference: B1080- Baranda Piso Tipo- metálica
Pset_RailingCommon - Reference: B1080- Baranda Piso Tipo- metálica
Name (Baranda perimetral piso 1:B1080- Baranda Piso Tipo- metálica:...) | In
1837755 | Nivel 1
1839284 | Nivel 2
1839301 | Nivel 3
1839303 | Nivel 4
1839305 | Nivel 5

# IfcRailing: Pasamanos anclaje lateral y perfiles verticales 1:B1080- Baranda Piso 1- metálica, Pasamanos anclaje lateral y perfiles verticales 1:B1080- Baranda Piso 1- metálica:1837754
In: Nivel 2
Type - Material: PASAMANOS, <Unnamed>
Type - Pset_RailingCommon - IsExternal: no
Classification: 21-02 10 80 50 Uniformat (Uniformat)
Pset_EnvironmentalImpactIndicators - Reference: B1080- Baranda Piso 1- metálica
Pset_RailingCommon - Reference: B1080- Baranda Piso 1- metálica

# IfcRailing: Pasamanos anclaje lateral y perfiles verticales piso tipo1:Baranda Piso Tipo 2 (3)
Type - Material: BARANDA, Perfil vertical, PASAMANOS, platina cuadrada
Type - Pset_RailingCommon - IsExternal: no
Classification: 21-02 10 80 50 Uniformat (Uniformat)
Pset_EnvironmentalImpactIndicators - Reference: Baranda Piso Tipo 2
Pset_RailingCommon - Reference: Baranda Piso Tipo 2
Name (Pasamanos anclaje lateral y perfiles verticales piso tipo1:Baranda Piso Tipo 2:...) | In
1839136 | Nivel 2
1839199 | Nivel 3
1839202 | Nivel 4

# IfcRailing: Pasamanos anclaje lateral y perfiles verticales ultimo piso1:Baranda Piso Tipo 2, Pasamanos anclaje lateral y perfiles verticales ultimo piso1:Baranda Piso Tipo 2:1840811
In: Nivel 6
Type - Material: BARANDA, platina cuadrada, Perfil vertical, PASAMANOS
Type - Pset_RailingCommon - IsExternal: no
Classification: 21-02 10 80 50 Uniformat (Uniformat)
Pset_EnvironmentalImpactIndicators - Reference: Baranda Piso Tipo 2
Pset_RailingCommon - Reference: Baranda Piso Tipo 2

# IfcRailing: Railing:C1090 - Baranda - Aluminio (5)
Classification: 21-03 10 90 10 Uniformat (Uniformat); Material: <Unnamed>, Aluminio
Pset_EnvironmentalImpactIndicators - Reference: C1090 - Baranda - Aluminio
Pset_RailingCommon - IsExternal: no; Reference: C1090 - Baranda - Aluminio; Height: 1.2192 m
Qto_RailingBaseQuantities - Length: 1.76 m
Name (Railing:C1090 - Baranda - Aluminio:...) | In
749476 | Nivel 3
751043 | Nivel 4
752610 | Nivel 5
754177 | Nivel 6
792155 | Nivel 2

# IfcRoof: Basic Roof:B3010 - 0.0825 m - Teja Ondulada - Fibrocemento, Basic Roof:B3010 - 0.0825 m - Teja Ondulada - Fibrocemento:755540
In: Nivel 7
Classification: 21-02 30 10 10 Uniformat (Uniformat)
Pset_EnvironmentalImpactIndicators - Reference: B3010 - 0.0825 m - Teja Ondulada - Fibrocemento
Pset_RoofCommon - IsExternal: yes; Reference: B3010 - 0.0825 m - Teja Ondulada - Fibrocemento
Qto_RoofBaseQuantities - ProjectedArea: 88.8702 m2

# IfcRoof: Basic Roof:B3010 - 0.0825 m - Teja Ondulada - Fibrocemento, Basic Roof:B3010 - 0.0825 m - Teja Ondulada - Fibrocemento:764547
In: Nivel 7
Type - Pset_RoofCommon - IsExternal: yes
Classification: 21-02 30 10 10 Uniformat (Uniformat); Material: Fibrocemento
Pset_EnvironmentalImpactIndicators - Reference: B3010 - 0.0825 m - Teja Ondulada - Fibrocemento
Pset_RoofCommon - Reference: B3010 - 0.0825 m - Teja Ondulada - Fibrocemento
Qto_RoofBaseQuantities - ProjectedArea: 88.7902 m2

# IfcRoof: Basic Roof:B3010 - cubierta - policarbonato, Basic Roof:B3010 - cubierta - policarbonato:1910617
In: Nivel 7
Classification: 21-02 30 10 10 Uniformat (Uniformat)
Pset_EnvironmentalImpactIndicators - Reference: B3010 - cubierta - policarbonato
Pset_RoofCommon - IsExternal: yes; Reference: B3010 - cubierta - policarbonato
Qto_RoofBaseQuantities - ProjectedArea: 3.59925 m2

# IfcSlab: Basic Roof:B3010 - 0.0825 m - Teja Ondulada - Fibrocemento, Basic Roof:B3010 - 0.0825 m - Teja Ondulada - Fibrocemento:755540
In: Nivel 7
Type - PredefinedType: ROOF
Type - Pset_ReinforcementBarPitchOfSlab - Description: Teja Ondulada
Type - Pset_SlabCommon - IsExternal: yes
Classification: 21-02 30 10 10 Uniformat (Uniformat); Material: Fibrocemento
Pset_EnvironmentalImpactIndicators - Reference: B3010 - 0.0825 m - Teja Ondulada - Fibrocemento; sets with these values: 2
Pset_SlabCommon - Reference: B3010 - 0.0825 m - Teja Ondulada - Fibrocemento; PitchAngle: 8.53077 deg
Qto_SlabBaseQuantities - Length: 0.0875 m; Perimeter: 53.7443 m; GrossArea: 8.34868 m2; GrossVolume: 0.730509 m3; NetVolume: 7.86314 m3

# IfcSlab: Basic Roof:B3010 - cubierta - policarbonato, Basic Roof:B3010 - cubierta - policarbonato:1910617
In: Nivel 7
Type - PredefinedType: ROOF
Type - Pset_ReinforcementBarPitchOfSlab - Description: Teja Policarbonato
Type - Pset_SlabCommon - IsExternal: yes
Classification: 21-02 30 10 10 Uniformat (Uniformat); Material: cubierta policarbonato
Pset_EnvironmentalImpactIndicators - Reference: B3010 - cubierta - policarbonato; sets with these values: 2
Pset_SlabCommon - Reference: B3010 - cubierta - policarbonato; PitchAngle: 8.53077 deg
Qto_SlabBaseQuantities - Length: 0.0875 m; Perimeter: 7.83256 m; GrossArea: 0.338122 m2; GrossVolume: 0.0295857 m3; NetVolume: 0.318458 m3

# IfcSlab: Floor:A4010 - 0.15m - Placa Contrapiso - Concreto (6)
In: Nivel 1
Type - PredefinedType: FLOOR; Material: Concreto (Aire)
Type - Pset_SlabCommon - IsExternal: no; ThermalTransmittance: 0.166667 kg/K/s3
Classification: 21-01 40 10 10 Uniformat (Uniformat)
Pset_EnvironmentalImpactIndicators - Reference: A4010 - 0.15m - Placa Contrapiso - Concreto; sets with these values: 2
Pset_SlabCommon - LoadBearing: no; PitchAngle: 0 deg; Reference: A4010 - 0.15m - Placa Contrapiso - Concreto
Name (Floor:A4010 - 0.15m - Placa Contrapiso - Concreto:...) | Perimeter (m) | GrossArea (m2) | NetVolume (m3)
732289 | 331.955 | 176.563 | 26.4845 | Qto_SlabBaseQuantities - Depth: 0.15 m; GrossVolume: 26.4845 m3
1310024 | 124.016 | 36.0698 | 5.41046 | Qto_SlabBaseQuantities - Depth: 0.15 m; GrossVolume: 5.41046 m3
1898158 | 348.556 | 3.8622 | 15.3004
1898158:2 | 348.556 | 47.139 | 15.3004
1898158:3 | 348.556 | 3.8622 | 15.3004
1898158:4 | 348.556 | 47.139 | 15.3004

# IfcSlab: Floor:B1010 - 0.10m - Placa Entrepiso - Concreto (15)
Type - PredefinedType: FLOOR; Material: Concreto (Aire)
Type - Pset_SlabCommon - IsExternal: no; LoadBearing: yes; ThermalTransmittance: 0.25 kg/K/s3; FireRating: 45
Classification: 21-02 10 10 20 Uniformat (Uniformat)
Pset_EnvironmentalImpactIndicators - Reference: B1010 - 0.10m - Placa Entrepiso - Concreto; sets with these values: 2
Pset_SlabCommon - LoadBearing: no; PitchAngle: 0 deg; Reference: B1010 - 0.10m - Placa Entrepiso - Concreto
Name (Floor:B1010 - 0.10m - Placa Entrepiso - Concreto:...) | In | Perimeter (m) | NetVolume (m3) | GrossArea (m2)
750381 | Nivel 3 | 305.217 | 18.8276
751948 | Nivel 4 | 305.217 | 18.8276
753515 | Nivel 5 | 305.217 | 18.8276
755082 | Nivel 6 | 305.217 | 18.8276
793047 | Nivel 2 | 303.212 | 18.9153
1578333 | Nivel 7 | 242.717 | 0.30719 | 0.342975
1578333:2 | Nivel 7 | 242.717 | 0.30719 | 0.5338
1578333:3 | Nivel 7 | 242.717 | 0.30719 | 0.342975
1578333:4 | Nivel 7 | 242.717 | 0.30719 | 0.1581
1578333:5 | Nivel 7 | 242.717 | 0.30719 | 0.1581
1578333:6 | Nivel 7 | 242.717 | 0.30719 | 0.342975
1578333:7 | Nivel 7 | 242.717 | 0.30719 | 0.5338
1578333:8 | Nivel 7 | 242.717 | 0.30719 | 0.342975
1578333:9 | Nivel 7 | 242.717 | 0.30719 | 0.1581
1578333:10 | Nivel 7 | 242.717 | 0.30719 | 0.1581

# IfcSlab: Floor:B1010 - 0.10m - Poyo - Concreto (24)
Type - PredefinedType: FLOOR; Material: Concreto (Aire)
Type - Pset_SlabCommon - IsExternal: no; ThermalTransmittance: 0.227273 kg/K/s3
Classification: 21-03 20 30 20 Uniformat (Uniformat)
Pset_EnvironmentalImpactIndicators - Reference: B1010 - 0.10m - Poyo - Concreto; sets with these values: 2
Pset_SlabCommon - LoadBearing: no; PitchAngle: 0 deg; Reference: B1010 - 0.10m - Poyo - Concreto
Qto_SlabBaseQuantities - Width: 1.485 m; Length: 0.4895 m; Depth: 0.11 m; Perimeter: 12.956 m; GrossVolume: 0.0799598 m3; NetVolume: 0.0799598 m3
Name (Floor:B1010 - 0.10m - Poyo - Concreto:...) | In | GrossArea (m2)
1946363 | Nivel 1 | 0.726907
1946536 | Nivel 1 | 0.726907
1946949 | Nivel 1 | 0.726908
1947667 | Nivel 1 | 0.726907
1947876 | Nivel 2 | 0.726908
1950195 | Nivel 3 | 0.726908
1950205 | Nivel 3 | 0.726908
1950215 | Nivel 3 | 0.726908
1950226 | Nivel 3 | 0.726908
1950236 | Nivel 4 | 0.726908
1950246 | Nivel 4 | 0.726908
1950256 | Nivel 4 | 0.726908
1950267 | Nivel 4 | 0.726908
1950277 | Nivel 5 | 0.726908
1950287 | Nivel 5 | 0.726908
1950297 | Nivel 5 | 0.726908
1950308 | Nivel 5 | 0.726908
1950318 | Nivel 6 | 0.726908
1950328 | Nivel 6 | 0.726908
1950338 | Nivel 6 | 0.726908
1950349 | Nivel 6 | 0.726908
1950359 | Nivel 2 | 0.726908
1950369 | Nivel 2 | 0.726908
1950379 | Nivel 2 | 0.726908

# IfcSlab: Floor:B1010 - 0.10m - Poyo - Concreto+ cerámica (20)
Type - PredefinedType: FLOOR; Material: Ceramica 0.45m x 0.45m gris, Concreto (Aire)
Type - Pset_SlabCommon - IsExternal: no; ThermalTransmittance: 0.25 kg/K/s3
Classification: 21-03 20 30 20 Uniformat (Uniformat)
Pset_EnvironmentalImpactIndicators - Reference: B1010 - 0.10m - Poyo - Concreto+ cerámica; sets with these values: 2
Pset_SlabCommon - LoadBearing: no; PitchAngle: 0 deg; Reference: B1010 - 0.10m - Poyo - Concreto+ cerámica
Qto_SlabBaseQuantities - Ceramica 0.45m x 0.45m gris, Width: 0.01 m; Concreto (Aire), Width: 0.1 m; Width: 0.11 m; Depth: 0.1 m; Perimeter: 5.61352 m; GrossArea: 0.18282 m2; GrossVolume: 0.018282 m3; NetVolume: 0.0201102 m3
Name (Floor:B1010 - 0.10m - Poyo - Concreto+ cerámica:...) | In | Length (m)
1950451 | Nivel 2 | 0.44
1952393 | Nivel 3 | 0.44
1952422 | Nivel 3 | 0.4155
1952451 | Nivel 3 | 0.4155
1952480 | Nivel 3 | 0.44
1952509 | Nivel 4 | 0.44
1952538 | Nivel 4 | 0.4155
1952567 | Nivel 4 | 0.4155
1952596 | Nivel 4 | 0.44
1952625 | Nivel 5 | 0.44
1952654 | Nivel 5 | 0.4155
1952683 | Nivel 5 | 0.4155
1952712 | Nivel 5 | 0.44
1952741 | Nivel 6 | 0.44
1952770 | Nivel 6 | 0.4155
1952799 | Nivel 6 | 0.4155
1952828 | Nivel 6 | 0.44
1952857 | Nivel 2 | 0.4155
1952886 | Nivel 2 | 0.4155
1952915 | Nivel 2 | 0.44

# IfcSlab: Floor:B1020 - 0.10m - Placa de cubierta - Concreto (4)
Type - PredefinedType: FLOOR; Material: Concreto (Aire)
Type - Pset_SlabCommon - IsExternal: no; ThermalTransmittance: 0.25 kg/K/s3
Classification: 21-02 10 20 20 Uniformat (Uniformat)
Pset_EnvironmentalImpactIndicators - Reference: B1020 - 0.10m - Placa de cubierta - Concreto; sets with these values: 2
Pset_SlabCommon - LoadBearing: no; PitchAngle: 0 deg; Reference: B1020 - 0.10m - Placa de cubierta - Concreto
Name (Floor:B1020 - 0.10m - Placa de cubierta - Concreto:...) | In | Width (m) | Length (m) | Depth (m) | Perimeter (m) | GrossArea (m2) | GrossVolume (m3) | NetVolume (m3)
755915 | Nivel 7 | 4.0575 | 1.2 | 0.1 | 34.498 | 4.869 | 0.4869 | 0.4869
756409 | Nivel 7 |  |  |  | 56.168 |  |  | 1.13345
757272 | Nivel 7 | 4.0575 | 1.2 | 0.1 | 34.498 | 4.869 | 0.4869 | 0.4869
810065 | Nivel 2 | 6.28 | 0.585 | 0.1 | 45.0459 | 3.6738 | 0.36738 | 0.36738

# IfcSlab: Floor:C2030.20 - 0.45 x 0.45 - Enchape cerámico - Mortero de Pega + Cerámica gris (48)
Type - PredefinedType: FLOOR; Material: Ceramica 0.45m x 0.45m gris, Mortero de pega
Type - Pset_SlabCommon - IsExternal: no; ThermalTransmittance: 52.3 kg/K/s3
Classification: 21-03 20 30 20 Uniformat (Uniformat)
Pset_EnvironmentalImpactIndicators - Reference: C2030.20 - 0.45 x 0.45 - Enchape cerámico - Mortero de Pega + Cerámica gris; sets with these values: 2
Pset_SlabCommon - LoadBearing: no; Reference: C2030.20 - 0.45 x 0.45 - Enchape cerámico - Mortero de Pega + Cerámica gris; PitchAngle: 0 deg
Qto_SlabBaseQuantities - Ceramica 0.45m x 0.45m gris, Width: 0.01 m; Mortero de pega, Width: 0.02 m; Width: 0.03 m; Depth: 0.02 m
Name (Floor:C2030.20 - 0.45 x 0.45 - Enchape cerámico - Mortero de Pega + Cerámica gris:...) | In | Perimeter (m) | GrossArea (m2) | GrossVolume (m3) | NetVolume (m3)
728567 | Nivel 1 | 35.8924 | 0.888749 | 0.017775 | 0.0887654 | Qto_SlabBaseQuantities - Length: 1.185 m
728578 | Nivel 1 | 38.0184 | 4.51059 | 0.0902119 | 0.135318
749150 | Nivel 3 | 35.8924 | 0.888749 | 0.017775 | 0.0887654 | Qto_SlabBaseQuantities - Length: 0.75 m
749161 | Nivel 3 | 38.4121 | 4.31077 | 0.0862155 | 0.129323
749318 | Nivel 3 | 35.8924 | 0.888749 | 0.017775 | 0.0887654 | Qto_SlabBaseQuantities - Length: 1.185 m
749329 | Nivel 3 | 38.4121 | 4.31077 | 0.0862155 | 0.129323
749520 | Nivel 3 | 35.8924 | 0.888749 | 0.017775 | 0.0887654 | Qto_SlabBaseQuantities - Length: 1.185 m
749531 | Nivel 3 | 38.4121 | 4.31077 | 0.0862155 | 0.129323
749694 | Nivel 3 | 35.8924 | 0.888749 | 0.017775 | 0.0887654 | Qto_SlabBaseQuantities - Length: 0.75 m
749705 | Nivel 3 | 38.4121 | 4.31077 | 0.0862155 | 0.129323
750717 | Nivel 4 | 35.8924 | 0.888749 | 0.017775 | 0.0887654 | Qto_SlabBaseQuantities - Length: 0.75 m
750728 | Nivel 4 | 38.4121 | 4.31077 | 0.0862155 | 0.129323
750885 | Nivel 4 | 35.8924 | 0.888749 | 0.017775 | 0.0887654 | Qto_SlabBaseQuantities - Length: 1.185 m
750896 | Nivel 4 | 38.4121 | 4.31077 | 0.0862155 | 0.129323
751087 | Nivel 4 | 35.8924 | 0.888749 | 0.017775 | 0.0887654 | Qto_SlabBaseQuantities - Length: 1.185 m
751098 | Nivel 4 | 38.4121 | 4.31077 | 0.0862155 | 0.129323
751261 | Nivel 4 | 35.8924 | 0.888749 | 0.017775 | 0.0887654 | Qto_SlabBaseQuantities - Length: 0.75 m
751272 | Nivel 4 | 38.4121 | 4.31077 | 0.0862155 | 0.129323
752284 | Nivel 5 | 35.8924 | 0.888749 | 0.017775 | 0.0887654 | Qto_SlabBaseQuantities - Length: 0.75 m
752295 | Nivel 5 | 38.4121 | 4.31077 | 0.0862155 | 0.129323
752452 | Nivel 5 | 35.8924 | 0.888749 | 0.017775 | 0.0887654 | Qto_SlabBaseQuantities - Length: 1.185 m
752463 | Nivel 5 | 38.4121 | 4.31077 | 0.0862155 | 0.129323
752654 | Nivel 5 | 35.8924 | 0.888749 | 0.017775 | 0.0887654 | Qto_SlabBaseQuantities - Length: 1.185 m
752665 | Nivel 5 | 38.4121 | 4.31077 | 0.0862155 | 0.129323
752828 | Nivel 5 | 35.8924 | 0.888749 | 0.017775 | 0.0887654 | Qto_SlabBaseQuantities - Length: 0.75 m
752839 | Nivel 5 | 38.4121 | 4.31077 | 0.0862155 | 0.129323
753851 | Nivel 6 | 35.8924 | 0.888749 | 0.017775 | 0.0887654 | Qto_SlabBaseQuantities - Length: 0.75 m
753862 | Nivel 6 | 38.4121 | 4.31077 | 0.0862155 | 0.129323
754019 | Nivel 6 | 35.8924 | 0.888749 | 0.017775 | 0.0887654 | Qto_SlabBaseQuantities - Length: 1.185 m
754030 | Nivel 6 | 38.4121 | 4.31077 | 0.0862155 | 0.129323
754221 | Nivel 6 | 35.8924 | 0.888749 | 0.017775 | 0.0887654 | Qto_SlabBaseQuantities - Length: 1.185 m
754232 | Nivel 6 | 38.4121 | 4.31077 | 0.0862155 | 0.129323
754395 | Nivel 6 | 35.8924 | 0.888749 | 0.017775 | 0.0887654 | Qto_SlabBaseQuantities - Length: 0.75 m
754406 | Nivel 6 | 38.4121 | 4.31077 | 0.0862155 | 0.129323
781261 | Nivel 1 | 35.8268 | 0.900599 | 0.018012 | 0.0888059 | Qto_SlabBaseQuantities - Length: 0.76 m
781272 | Nivel 1 | 38.0184 | 4.39444 | 0.0878889 | 0.131833
791831 | Nivel 2 | 35.8924 | 0.888749 | 0.017775 | 0.0887654 | Qto_SlabBaseQuantities - Length: 0.75 m
791842 | Nivel 2 | 38.4121 | 4.31077 | 0.0862155 | 0.129323
791998 | Nivel 2 | 35.8924 | 0.888749 | 0.017775 | 0.0887654 | Qto_SlabBaseQuantities - Length: 1.185 m
792009 | Nivel 2 | 38.4121 | 4.31077 | 0.0862155 | 0.129323
792196 | Nivel 2 | 35.8924 | 0.888749 | 0.017775 | 0.0887654 | Qto_SlabBaseQuantities - Length: 1.185 m
792207 | Nivel 2 | 38.4121 | 4.31077 | 0.0862155 | 0.129323
792369 | Nivel 2 | 35.8924 | 0.888749 | 0.017775 | 0.0887654 | Qto_SlabBaseQuantities - Length: 0.75 m
792380 | Nivel 2 | 38.4121 | 4.31077 | 0.0862155 | 0.129323
872666 | Nivel 1 | 35.8924 | 0.888749 | 0.017775 | 0.0887654 | Qto_SlabBaseQuantities - Length: 0.75 m
872677 | Nivel 1 | 37.9528 | 4.49645 | 0.089929 | 0.134893
872864 | Nivel 1 | 35.8924 | 0.888749 | 0.017775 | 0.0887654 | Qto_SlabBaseQuantities - Length: 1.185 m
872875 | Nivel 1 | 38.0184 | 4.51059 | 0.0902119 | 0.135318

# IfcSlab: Floor:C2030.20 - 30x30- Piso en gres - Gres (8)
Type - PredefinedType: FLOOR; Material: PISO GRES SAHARA 30X30, Mortero de pega
Type - Pset_SlabCommon - IsExternal: no; ThermalTransmittance: 36.4248 kg/K/s3
Classification: 21-03 20 30 20 Uniformat (Uniformat)
Pset_EnvironmentalImpactIndicators - Reference: C2030.20 - 30x30- Piso en gres - Gres; sets with these values: 2
Pset_SlabCommon - LoadBearing: no; Reference: C2030.20 - 30x30- Piso en gres - Gres
Qto_SlabBaseQuantities - PISO GRES SAHARA 30X30, Width: 0.01 m; Mortero de pega, Width: 0.02 m; Width: 0.03 m
Name (Floor:C2030.20 - 30x30- Piso en gres - Gres:...) | In | PitchAngle (deg) | Perimeter (m) | NetVolume (m3) | Depth (m) | GrossArea (m2) | GrossVolume (m3)
997936 | Nivel 1 | 3.81407 | 23.393 | 0.0462021
1813046 | Nivel 1 | 0 | 23.6877 | 0.08712 | 0.02 | 2.904 | 0.05808 | Qto_SlabBaseQuantities - Length: 1.21 m
1817239 | Nivel 2 | 0 | 89.357 | 0.265107 | 0.02 | 8.8369 | 0.176738
1819820 | Nivel 3 | 0 | 89.357 | 0.265107 | 0.02 | 8.8369 | 0.176738
1820134 | Nivel 4 | 0 | 89.357 | 0.265107 | 0.02 | 8.8369 | 0.176738
1820448 | Nivel 5 | 0 | 89.357 | 0.265107 | 0.02 | 8.8369 | 0.176738
1820762 | Nivel 6 | 0 | 89.357 | 0.265107 | 0.02 | 8.8369 | 0.176738
1960763 | Nivel 1 | 0 | 28.7927 | 0.01164 | 0.02 | 0.097 | 0.00194 | Qto_SlabBaseQuantities - Length: 0.097 m

# IfcSlab: Floor:C2030.20 - Piso en gres - Gres (4)
In: Nivel 1
Type - PredefinedType: FLOOR; Material: Tile, Porcelain, 6in, Mortero de pega
Type - Pset_SlabCommon - IsExternal: no; ThermalTransmittance: 36.4248 kg/K/s3
Classification: 21-03 20 30 20 Uniformat (Uniformat)
Pset_EnvironmentalImpactIndicators - Reference: C2030.20 - Piso en gres - Gres; sets with these values: 2
Pset_SlabCommon - LoadBearing: no; PitchAngle: 0 deg; Reference: C2030.20 - Piso en gres - Gres
Qto_SlabBaseQuantities - Tile, Porcelain, 6in, Width: 0.01 m; Mortero de pega, Width: 0.02 m; Width: 0.03 m; Depth: 0.02 m
Name (Floor:C2030.20 - Piso en gres - Gres:...) | Perimeter (m) | GrossArea (m2) | GrossVolume (m3) | NetVolume (m3)
950092 | 30.8169 | 3.14683 | 0.0629365 | 0.0944048
950276 | 20.6135 | 1.68202 | 0.0336403 | 0.0504605
950324 | 20.6135 | 1.68202 | 0.0336403 | 0.0504605
1549319 | 30.8169 | 3.14683 | 0.0629365 | 0.0944048

# IfcSlab: Floor:C2030.20 - Piso en gres - Gres + relleno, Floor:C2030.20 - Piso en gres - Gres + relleno:1812702
In: Nivel 1
Type - PredefinedType: FLOOR; Material: PISO GRES SAHARA 30X30, Mortero de pega, Tierra
Type - Pset_SlabCommon - IsExternal: no; ThermalTransmittance: 6.80605 kg/K/s3
Classification: 21-03 20 30 20 Uniformat (Uniformat)
Pset_EnvironmentalImpactIndicators - Reference: C2030.20 - Piso en gres - Gres + relleno; sets with these values: 2
Pset_SlabCommon - LoadBearing: no; PitchAngle: 0 deg; Reference: C2030.20 - Piso en gres - Gres + relleno
Qto_SlabBaseQuantities - PISO GRES SAHARA 30X30, Width: 0.01 m; Mortero de pega, Width: 0.02 m; Tierra, Width: 0.1 m; Width: 0.13 m; Depth: 0.1 m; Perimeter: 140.184 m; GrossArea: 17.7292 m2; GrossVolume: 1.77292 m3; NetVolume: 2.30479 m3

# IfcSlab: Floor:C2030.20 - Piso en gres - Gres moca (6)
Type - PredefinedType: FLOOR; Material: PISO GRES moca 30X30, Mortero de pega
Type - Pset_SlabCommon - IsExternal: no; ThermalTransmittance: 36.4248 kg/K/s3
Classification: 21-03 20 30 20 Uniformat (Uniformat)
Pset_EnvironmentalImpactIndicators - Reference: C2030.20 - Piso en gres - Gres moca; sets with these values: 2
Pset_SlabCommon - LoadBearing: no; Reference: C2030.20 - Piso en gres - Gres moca
Qto_SlabBaseQuantities - PISO GRES moca 30X30, Width: 0.01 m; Mortero de pega, Width: 0.02 m; Width: 0.03 m
Name (Floor:C2030.20 - Piso en gres - Gres moca:...) | In | PitchAngle (deg) | Depth (m) | Perimeter (m) | GrossArea (m2) | GrossVolume (m3) | NetVolume (m3) | Length (m)
1961538 | Nivel 1 | 3.81407 | 0.305 | 11.6686 | 0.00611537 | 0.00186519 | 0.00791776
1962961 | Nivel 2 | 0 | 0.02 | 32.021 | 0.093025 | 0.0018605 | 0.022326 | 0.305
1964505 | Nivel 3 | 0 | 0.02 | 32.021 | 0.093025 | 0.0018605 | 0.022326 | 0.305
1964573 | Nivel 4 | 0 | 0.02 | 32.021 | 0.093025 | 0.0018605 | 0.022326 | 0.305
1964641 | Nivel 5 | 0 | 0.02 | 32.021 | 0.093025 | 0.0018605 | 0.022326 | 0.305
1964709 | Nivel 6 | 0 | 0.02 | 32.021 | 0.093025 | 0.0018605 | 0.022326 | 0.305

# IfcSlab: Floor:C2030.20 - Piso en gres - Gres moca + relleno, Floor:C2030.20 - Piso en gres - Gres moca + relleno:1961814
In: Nivel 1
Type - PredefinedType: FLOOR; Material: PISO GRES moca 30X30, Mortero de pega, Tierra
Type - Pset_SlabCommon - IsExternal: no; ThermalTransmittance: 6.80605 kg/K/s3
Classification: 21-03 20 30 20 Uniformat (Uniformat)
Pset_EnvironmentalImpactIndicators - Reference: C2030.20 - Piso en gres - Gres moca + relleno; sets with these values: 2
Pset_SlabCommon - LoadBearing: no; PitchAngle: 0 deg; Reference: C2030.20 - Piso en gres - Gres moca + relleno
Qto_SlabBaseQuantities - PISO GRES moca 30X30, Width: 0.01 m; Mortero de pega, Width: 0.02 m; Tierra, Width: 0.1 m; Width: 0.13 m; Length: 0.305 m; Depth: 0.1 m; Perimeter: 43.7008 m; GrossArea: 0.093025 m2; GrossVolume: 0.0093025 m3; NetVolume: 0.131043 m3

# IfcSlab: Floor:C2030.20 -30x30- Escalgres - Gres (67)
Type - PredefinedType: FLOOR; Material: escalgres, Mortero de pega
Type - Pset_SlabCommon - IsExternal: no; ThermalTransmittance: 36.4248 kg/K/s3
Classification: 21-03 20 40 20 Uniformat (Uniformat)
Pset_EnvironmentalImpactIndicators - Reference: C2030.20 -30x30- Escalgres - Gres; sets with these values: 2
Pset_SlabCommon - LoadBearing: no; PitchAngle: 0 deg; Reference: C2030.20 -30x30- Escalgres - Gres
Qto_SlabBaseQuantities - escalgres, Width: 0.01 m; Mortero de pega, Width: 0.02 m; Width: 0.03 m; Depth: 0.02 m
Name (Floor:C2030.20 -30x30- Escalgres - Gres:...) | In | Length (m) | Perimeter (m) | GrossArea (m2) | GrossVolume (m3) | NetVolume (m3)
1813016 | Nivel 1 | 0.295 | 9.80971 | 0.354 | 0.00708 | 0.01062
1813022 | Nivel 1 | 0.295 | 9.80971 | 0.354 | 0.00708 | 0.01062
1813028 | Nivel 1 | 0.295 | 9.80971 | 0.354 | 0.00708 | 0.01062
1813034 | Nivel 1 | 0.295 | 9.80971 | 0.354 | 0.00708 | 0.01062
1813040 | Nivel 1 | 0.295 | 9.80971 | 0.354 | 0.00708 | 0.01062
1813599 | Nivel 2 | 1.2 | 9.80971 | 0.354 | 0.00708 | 0.01062
1813605 | Nivel 2 | 1.2 | 9.80971 | 0.354 | 0.00708 | 0.01062
1813611 | Nivel 2 | 1.2 | 9.80971 | 0.354 | 0.00708 | 0.01062
1813617 | Nivel 2 | 1.2 | 9.80971 | 0.354 | 0.00708 | 0.01062
1813623 | Nivel 2 | 1.2 | 9.80971 | 0.354 | 0.00708 | 0.01062
1813629 | Nivel 2 | 1.2 | 9.80971 | 0.354 | 0.00708 | 0.01062
1817256 | Nivel 2 | 0.295 | 9.80971 | 0.354 | 0.00708 | 0.01062
1817262 | Nivel 2 | 0.295 | 9.80971 | 0.354 | 0.00708 | 0.01062
1817268 | Nivel 2 | 0.295 | 9.80971 | 0.354 | 0.00708 | 0.01062
1817274 | Nivel 2 | 0.295 | 9.80971 | 0.354 | 0.00708 | 0.01062
1817280 | Nivel 2 | 0.295 | 9.80971 | 0.354 | 0.00708 | 0.01062
1817286 | Nivel 2 | 0.295 | 9.80971 | 0.354 | 0.00708 | 0.01062
1817292 | Nivel 2 |  | 23.6877 | 2.51955 | 0.050391 | 0.0755864
1817420 | Nivel 3 | 1.2 | 9.80971 | 0.354 | 0.00708 | 0.01062
1817426 | Nivel 3 | 1.2 | 9.80971 | 0.354 | 0.00708 | 0.01062
1817432 | Nivel 3 | 1.2 | 9.80971 | 0.354 | 0.00708 | 0.01062
1817438 | Nivel 3 | 1.2 | 9.80971 | 0.354 | 0.00708 | 0.01062
1817444 | Nivel 3 | 1.2 | 9.80971 | 0.354 | 0.00708 | 0.01062
1817450 | Nivel 3 | 1.2 | 9.80971 | 0.354 | 0.00708 | 0.01062
1819837 | Nivel 3 | 0.295 | 9.80971 | 0.354 | 0.00708 | 0.01062
1819843 | Nivel 3 | 0.295 | 9.80971 | 0.354 | 0.00708 | 0.01062
1819849 | Nivel 3 | 0.295 | 9.80971 | 0.354 | 0.00708 | 0.01062
1819855 | Nivel 3 | 0.295 | 9.80971 | 0.354 | 0.00708 | 0.01062
1819861 | Nivel 3 | 0.295 | 9.80971 | 0.354 | 0.00708 | 0.01062
1819867 | Nivel 3 | 0.295 | 9.80971 | 0.354 | 0.00708 | 0.01062
1819873 | Nivel 3 |  | 23.6877 | 2.51955 | 0.050391 | 0.0755864
1820001 | Nivel 4 | 1.2 | 9.80971 | 0.354 | 0.00708 | 0.01062
1820007 | Nivel 4 | 1.2 | 9.80971 | 0.354 | 0.00708 | 0.01062
1820013 | Nivel 4 | 1.2 | 9.80971 | 0.354 | 0.00708 | 0.01062
1820019 | Nivel 4 | 1.2 | 9.80971 | 0.354 | 0.00708 | 0.01062
1820025 | Nivel 4 | 1.2 | 9.80971 | 0.354 | 0.00708 | 0.01062
1820031 | Nivel 4 | 1.2 | 9.80971 | 0.354 | 0.00708 | 0.01062
1820151 | Nivel 4 | 0.295 | 9.80971 | 0.354 | 0.00708 | 0.01062
1820157 | Nivel 4 | 0.295 | 9.80971 | 0.354 | 0.00708 | 0.01062
1820163 | Nivel 4 | 0.295 | 9.80971 | 0.354 | 0.00708 | 0.01062
1820169 | Nivel 4 | 0.295 | 9.80971 | 0.354 | 0.00708 | 0.01062
1820175 | Nivel 4 | 0.295 | 9.80971 | 0.354 | 0.00708 | 0.01062
1820181 | Nivel 4 | 0.295 | 9.80971 | 0.354 | 0.00708 | 0.01062
1820187 | Nivel 4 |  | 23.6877 | 2.51955 | 0.050391 | 0.0755864
1820315 | Nivel 5 | 1.2 | 9.80971 | 0.354 | 0.00708 | 0.01062
1820321 | Nivel 5 | 1.2 | 9.80971 | 0.354 | 0.00708 | 0.01062
1820327 | Nivel 5 | 1.2 | 9.80971 | 0.354 | 0.00708 | 0.01062
1820333 | Nivel 5 | 1.2 | 9.80971 | 0.354 | 0.00708 | 0.01062
1820339 | Nivel 5 | 1.2 | 9.80971 | 0.354 | 0.00708 | 0.01062
1820345 | Nivel 5 | 1.2 | 9.80971 | 0.354 | 0.00708 | 0.01062
1820465 | Nivel 5 | 0.295 | 9.80971 | 0.354 | 0.00708 | 0.01062
1820471 | Nivel 5 | 0.295 | 9.80971 | 0.354 | 0.00708 | 0.01062
1820477 | Nivel 5 | 0.295 | 9.80971 | 0.354 | 0.00708 | 0.01062
1820483 | Nivel 5 | 0.295 | 9.80971 | 0.354 | 0.00708 | 0.01062
1820489 | Nivel 5 | 0.295 | 9.80971 | 0.354 | 0.00708 | 0.01062
1820495 | Nivel 5 | 0.295 | 9.80971 | 0.354 | 0.00708 | 0.01062
1820501 | Nivel 5 |  | 23.6877 | 2.51955 | 0.050391 | 0.0755864
1820629 | Nivel 6 | 1.2 | 9.80971 | 0.354 | 0.00708 | 0.01062
1820635 | Nivel 6 | 1.2 | 9.80971 | 0.354 | 0.00708 | 0.01062
1820641 | Nivel 6 | 1.2 | 9.80971 | 0.354 | 0.00708 | 0.01062
1820647 | Nivel 6 | 1.2 | 9.80971 | 0.354 | 0.00708 | 0.01062
1820653 | Nivel 6 | 1.2 | 9.80971 | 0.354 | 0.00708 | 0.01062
1820659 | Nivel 6 | 1.2 | 9.80971 | 0.354 | 0.00708 | 0.01062
1958269 | Nivel 2 |  | 10.3707 | 0.402453 | 0.00804905 | 0.0120736
1958942 | Nivel 3 |  | 10.3707 | 0.402453 | 0.00804905 | 0.0120736
1958955 | Nivel 4 |  | 10.3707 | 0.402453 | 0.00804905 | 0.0120736
1958968 | Nivel 5 |  | 10.3707 | 0.402453 | 0.00804905 | 0.0120736

# IfcSlab: Floors 11:Floors 1, Floors 11:Floors 1:1968432
In: Nivel 1
Type - PredefinedType: FLOOR; Material: PISO GRES SAHARA 30X30 guardaescoba sin hatch
Type - Pset_ReinforcementBarPitchOfSlab - Description: Guardaescobas Escalera Gres
Type - Pset_SlabCommon - IsExternal: no
Classification: 21-03 20 40 20 Uniformat (Uniformat)
Pset_EnvironmentalImpactIndicators - Reference: Floors 1; sets with these values: 2
Pset_SlabCommon - Reference: Floors 1
Qto_SlabBaseQuantities - Depth: 0.01 m; Perimeter: 7.95429 m; GrossArea: 0.311771 m2; GrossVolume: 0.00311771 m3; NetVolume: 0.00311771 m3

# IfcSlab: Floors 12:Floors 2, Floors 12:Floors 2:1968465
In: Nivel 1
Type - PredefinedType: FLOOR; Material: PISO GRES SAHARA 30X30 guardaescoba sin hatch
Type - Pset_ReinforcementBarPitchOfSlab - Description: Guardaescobas Escalera Gres
Type - Pset_SlabCommon - IsExternal: no
Classification: 21-03 20 40 20 Uniformat (Uniformat)
Pset_EnvironmentalImpactIndicators - Reference: Floors 2; sets with these values: 2
Pset_SlabCommon - Reference: Floors 2
Qto_SlabBaseQuantities - Depth: 0.01 m; Perimeter: 8.23976 m; GrossArea: 0.323191 m2; GrossVolume: 0.00323191 m3; NetVolume: 0.00323191 m3

# IfcSlab: Floors 1:Floors 1, Floors 1:Floors 1:1965090
In: Nivel 3
Type - PredefinedType: FLOOR; Material: PISO GRES SAHARA 30X30 guardaescoba sin hatch
Type - Pset_ReinforcementBarPitchOfSlab - Description: Guardaescobas Escalera en Gres
Type - Pset_SlabCommon - IsExternal: no
Classification: 21-03 20 40 20 Uniformat (Uniformat)
Pset_EnvironmentalImpactIndicators - Reference: Floors 1; sets with these values: 2
Pset_SlabCommon - Reference: Floors 1
Qto_SlabBaseQuantities - Depth: 0.01 m; Perimeter: 7.95429 m; GrossArea: 0.311771 m2; GrossVolume: 0.00311771 m3; NetVolume: 0.00311771 m3

# IfcSlab: Floors 2:Floors 2, Floors 2:Floors 2:1965123
In: Nivel 3
Type - PredefinedType: FLOOR; Material: PISO GRES SAHARA 30X30 guardaescoba sin hatch
Type - Pset_ReinforcementBarPitchOfSlab - Description: Guardaescobas Escalera Gres
Type - Pset_SlabCommon - IsExternal: no
Classification: 21-03 20 40 20 Uniformat (Uniformat)
Pset_EnvironmentalImpactIndicators - Reference: Floors 2; sets with these values: 2
Pset_SlabCommon - Reference: Floors 2
Qto_SlabBaseQuantities - Depth: 0.01 m; Perimeter: 8.23976 m; GrossArea: 0.323191 m2; GrossVolume: 0.00323191 m3; NetVolume: 0.00323191 m3

# IfcSlab: Floors 3:Floors 1, Floors 3:Floors 1:1966619
In: Nivel 4
Type - PredefinedType: FLOOR; Material: PISO GRES SAHARA 30X30 guardaescoba sin hatch
Type - Pset_ReinforcementBarPitchOfSlab - Description: Guardaescobas Escalera en Gres
Type - Pset_SlabCommon - IsExternal: no
Classification: 21-03 20 40 20 Uniformat (Uniformat)
Pset_EnvironmentalImpactIndicators - Reference: Floors 1; sets with these values: 2
Pset_SlabCommon - Reference: Floors 1
Qto_SlabBaseQuantities - Depth: 0.01 m; Perimeter: 7.95429 m; GrossArea: 0.311771 m2; GrossVolume: 0.00311771 m3; NetVolume: 0.00311771 m3

# IfcSlab: Floors 4:Floors 2, Floors 4:Floors 2:1966652
In: Nivel 4
Type - PredefinedType: FLOOR; Material: PISO GRES SAHARA 30X30 guardaescoba sin hatch
Type - Pset_ReinforcementBarPitchOfSlab - Description: Guardaescobas Escalera Gres
Type - Pset_SlabCommon - IsExternal: no
Classification: 21-03 20 40 20 Uniformat (Uniformat)
Pset_EnvironmentalImpactIndicators - Reference: Floors 2; sets with these values: 2
Pset_SlabCommon - Reference: Floors 2
Qto_SlabBaseQuantities - Depth: 0.01 m; Perimeter: 8.23976 m; GrossArea: 0.323191 m2; GrossVolume: 0.00323191 m3; NetVolume: 0.00323191 m3

# IfcSlab: Floors 5:Floors 1, Floors 5:Floors 1:1966687
In: Nivel 5
Type - PredefinedType: FLOOR; Material: PISO GRES SAHARA 30X30 guardaescoba sin hatch
Type - Pset_ReinforcementBarPitchOfSlab - Description: Guardaescobas Escalera en Gres
Type - Pset_SlabCommon - IsExternal: no
Classification: 21-03 20 40 20 Uniformat (Uniformat)
Pset_EnvironmentalImpactIndicators - Reference: Floors 1; sets with these values: 2
Pset_SlabCommon - Reference: Floors 1
Qto_SlabBaseQuantities - Depth: 0.01 m; Perimeter: 7.95429 m; GrossArea: 0.311771 m2; GrossVolume: 0.00311771 m3; NetVolume: 0.00311771 m3

# IfcSlab: Floors 6:Floors 2, Floors 6:Floors 2:1966720
In: Nivel 5
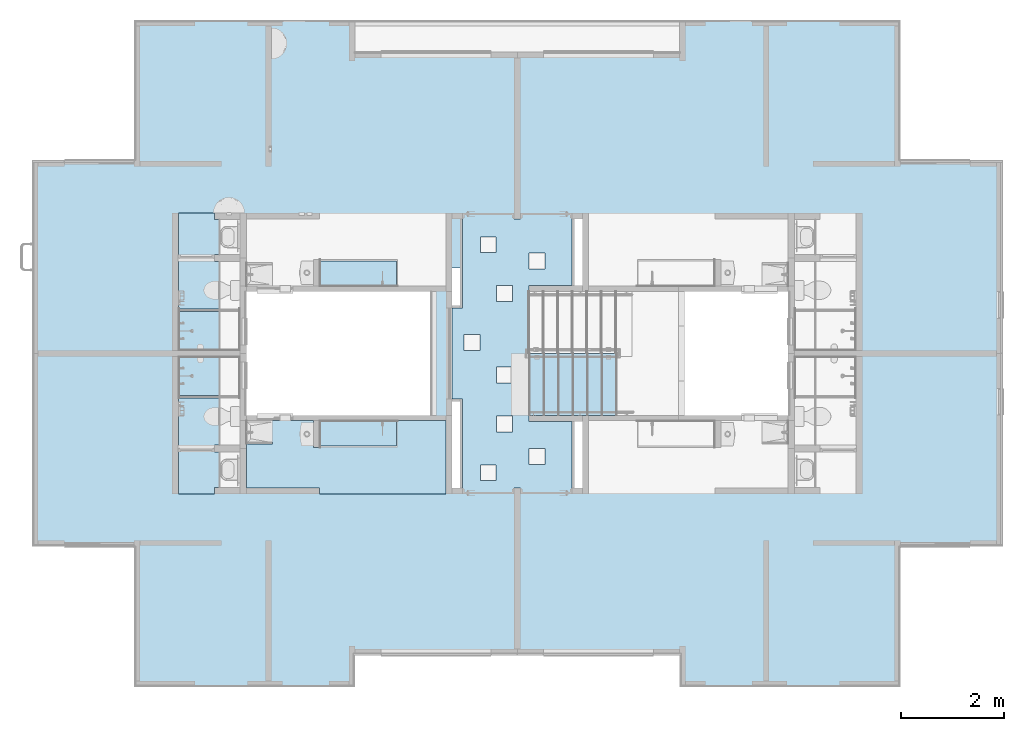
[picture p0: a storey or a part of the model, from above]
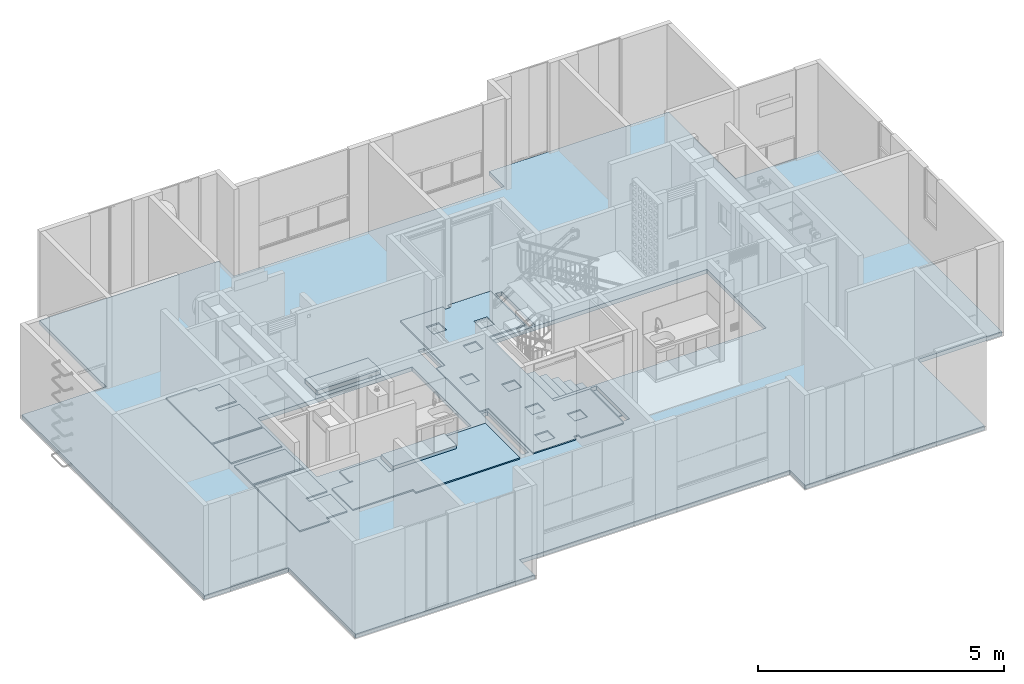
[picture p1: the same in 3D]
Properties of the parts of a building model (IFC4), part 4 of 6

# IfcSlab: Floors 6:Floors 2, Floors 6:Floors 2:1966720
Type - PredefinedType: FLOOR; Material: PISO GRES SAHARA 30X30 guardaescoba sin hatch
Type - Pset_ReinforcementBarPitchOfSlab - Description: Guardaescobas Escalera Gres
Type - Pset_SlabCommon - IsExternal: no
Classification: 21-03 20 40 20 Uniformat (Uniformat)
Pset_EnvironmentalImpactIndicators - Reference: Floors 2; sets with these values: 2
Pset_SlabCommon - Reference: Floors 2
Qto_SlabBaseQuantities - Depth: 0.01 m; Perimeter: 8.23976 m; GrossArea: 0.323191 m2; GrossVolume: 0.00323191 m3; NetVolume: 0.00323191 m3

# IfcSlab: Floors 7:Floors 1, Floors 7:Floors 1:1966755
In: Nivel 6
Type - PredefinedType: FLOOR; Material: PISO GRES SAHARA 30X30 guardaescoba sin hatch
Type - Pset_ReinforcementBarPitchOfSlab - Description: Guardaescobas Escalera en Gres
Type - Pset_SlabCommon - IsExternal: no
Classification: 21-03 20 40 20 Uniformat (Uniformat)
Pset_EnvironmentalImpactIndicators - Reference: Floors 1; sets with these values: 2
Pset_SlabCommon - Reference: Floors 1
Qto_SlabBaseQuantities - Depth: 0.01 m; Perimeter: 7.95429 m; GrossArea: 0.311771 m2; GrossVolume: 0.00311771 m3; NetVolume: 0.00311771 m3

# IfcSlab: Floors 8:Floors 2, Floors 8:Floors 2:1966788
In: Nivel 6
Type - PredefinedType: FLOOR; Material: PISO GRES SAHARA 30X30 guardaescoba sin hatch
Type - Pset_ReinforcementBarPitchOfSlab - Description: Guardaescobas Escalera Gres
Type - Pset_SlabCommon - IsExternal: no
Classification: 21-03 20 40 20 Uniformat (Uniformat)
Pset_EnvironmentalImpactIndicators - Reference: Floors 2; sets with these values: 2
Pset_SlabCommon - Reference: Floors 2
Qto_SlabBaseQuantities - Depth: 0.01 m; Perimeter: 8.23976 m; GrossArea: 0.323191 m2; GrossVolume: 0.00323191 m3; NetVolume: 0.00323191 m3

# IfcStair: ESCALON1:ESCALON, ESCALON1:ESCALON:1096037
In: Nivel 2
Type - Pset_StairCommon - IsExternal: no; NosingLength: 0 m; NumberOfRiser: 0; NumberOfTreads: 0
Type - Pset_StairFlightCommon - NosingLength: 0 m; NumberOfRiser: 0; NumberOfTreads: 0
Classification: 21-02 10 80 10 Uniformat (Uniformat); Material: Concreto (Aire)
Pset_EnvironmentalImpactIndicators - Reference: ESCALON; sets with these values: 2
Pset_StairCommon - Reference: ESCALON

# IfcStair: ESCALON3:ESCALON, ESCALON3:ESCALON:1096537
In: Nivel 3
Type - Pset_StairCommon - IsExternal: no; NosingLength: 0 m; NumberOfRiser: 0; NumberOfTreads: 0
Type - Pset_StairFlightCommon - NosingLength: 0 m; NumberOfRiser: 0; NumberOfTreads: 0
Classification: 21-02 10 80 10 Uniformat (Uniformat); Material: Concreto (Aire)
Pset_EnvironmentalImpactIndicators - Reference: ESCALON; sets with these values: 2
Pset_StairCommon - Reference: ESCALON

# IfcStair: ESCALON4:ESCALON, ESCALON4:ESCALON:1096594
In: Nivel 4
Type - Pset_StairCommon - IsExternal: no; NosingLength: 0 m; NumberOfRiser: 0; NumberOfTreads: 0
Type - Pset_StairFlightCommon - NosingLength: 0 m; NumberOfRiser: 0; NumberOfTreads: 0
Classification: 21-02 10 80 10 Uniformat (Uniformat); Material: Concreto (Aire)
Pset_EnvironmentalImpactIndicators - Reference: ESCALON; sets with these values: 2
Pset_StairCommon - Reference: ESCALON

# IfcStair: ESCALON5:ESCALON, ESCALON5:ESCALON:1096651
In: Nivel 5
Type - Pset_StairCommon - IsExternal: no; NosingLength: 0 m; NumberOfRiser: 0; NumberOfTreads: 0
Type - Pset_StairFlightCommon - NosingLength: 0 m; NumberOfRiser: 0; NumberOfTreads: 0
Classification: 21-02 10 80 10 Uniformat (Uniformat); Material: Concreto (Aire)
Pset_EnvironmentalImpactIndicators - Reference: ESCALON; sets with these values: 2
Pset_StairCommon - Reference: ESCALON

# IfcStair: ESCALON:ESCALON, ESCALON:ESCALON:1095251
In: Nivel 1
Type - Pset_StairCommon - IsExternal: no; NumberOfRiser: 0; NumberOfTreads: 0; NosingLength: 0 m
Type - Pset_StairFlightCommon - NosingLength: 0 m; NumberOfRiser: 0; NumberOfTreads: 0
Classification: 21-02 10 80 10 Uniformat (Uniformat); Material: Concreto (Aire)
Pset_EnvironmentalImpactIndicators - Reference: ESCALON; sets with these values: 2
Pset_StairCommon - Reference: ESCALON

# IfcStair: Stair:B1080 - 2.40 x 2.88 - Escalera en concreto de dos tramos piso 1, Stair:B1080 - 2.40 x 2.88 - Escalera en concreto de dos tramos piso 1:1812085
In: Nivel 1
Type - Pset_StairCommon - IsExternal: no; LoadBearing: yes; FireExit: yes; NumberOfRiser: 0; NumberOfTreads: 0; NosingLength: 0.025 m
Type - Pset_StairFlightCommon - NumberOfRiser: 0; NumberOfTreads: 0; NosingLength: 0.025 m
Classification: 21-02 10 80 10 Uniformat (Uniformat); Material: Concreto (Aire)
Pset_EnvironmentalImpactIndicators - Reference: B1080 - 2.40 x 2.88 - Escalera en concreto de dos tramos piso 1
Pset_StairCommon - NosingLength: 0 m; Reference: B1080 - 2.40 x 2.88 - Escalera en concreto de dos tramos piso 1; NumberOfRiser: 14; NumberOfTreads: 13; RiserHeight: 0.167857 m; TreadLength: 0.25 m; TreadLengthAtOffset: 0.25 m; HandicapAccessible: yes; HasNonSkidSurface: yes
Pset_StairFlightCommon - NosingLength: 0 m; Reference: B1080 - 2.40 x 2.88 - Escalera en concreto de dos tramos piso 1; NumberOfRiser: 14; NumberOfTreads: 13; RiserHeight: 0.167857 m; TreadLength: 0.25 m; TreadLengthAtOffset: 0.25 m

# IfcStair: Stair:B1080 - 2.40 x 2.88 - Escalera en concreto de dos tramos piso tipo (4)
Type - Pset_StairCommon - IsExternal: no; NosingLength: 0 m; NumberOfRiser: 0; NumberOfTreads: 0
Type - Pset_StairFlightCommon - NosingLength: 0 m; NumberOfRiser: 0; NumberOfTreads: 0
Classification: 21-02 10 80 10 Uniformat (Uniformat); Material: Concreto (Aire)
Pset_EnvironmentalImpactIndicators - Reference: B1080 - 2.40 x 2.88 - Escalera en concreto de dos tramos piso tipo
Pset_StairCommon - Reference: B1080 - 2.40 x 2.88 - Escalera en concreto de dos tramos piso tipo; NumberOfRiser: 14; NumberOfTreads: 13; RiserHeight: 0.167857 m; TreadLength: 0.25 m; TreadLengthAtOffset: 0.25 m
Pset_StairFlightCommon - Reference: B1080 - 2.40 x 2.88 - Escalera en concreto de dos tramos piso tipo; NumberOfRiser: 14; NumberOfTreads: 13; RiserHeight: 0.167857 m; TreadLength: 0.25 m; TreadLengthAtOffset: 0.25 m
Name (Stair:B1080 - 2.40 x 2.88 - Escalera en concreto de dos tramos piso tipo:...) | In
1096047 | Nivel 2
1096540 | Nivel 3
1096597 | Nivel 4
1096654 | Nivel 5

# IfcValve: D2010 - Llave pesada de suministro - Metal:D2010 - Llave pesada de suministro - Metal (24)
Type - Material: Acero inoxidable
Classification: 21-04 20 10 60 Uniformat (Uniformat)
Pset_EnvironmentalImpactIndicators - Reference: D2010 - Llave pesada de suministro - Metal; sets with these values: 2
Name (D2010 - Llave pesada de suministro - Metal:D2010 - Llave pesada de suministro - Metal:...) | In
749275 | 146
749441 | 153
749643 | 161
749817 | 168
750842 | 204
751008 | 212
751210 | 220
751384 | 227
752409 | 263
752575 | 270
752777 | 278
752951 | 285
753976 | 321
754142 | 328
754344 | 336
754518 | 343
791956 | 406
792121 | 413
792319 | 421
792492 | 428
872985 | 507
1311380 | 509
1794235 | 510
1795307 | 508

# IfcWall: Basic Wall:B2010 - 0.015-Enchape- Gres (70)
Type - PredefinedType: STANDARD
Type - Pset_WallCommon - IsExternal: yes; ThermalTransmittance: 80 kg/K/s3
Classification: 21-03 20 10 10 Uniformat (Uniformat); Material: PISO GRES SAHARA 30X30
Qto_WallBaseQuantities - Height: 0.137857 m; Width: 0.015 m
Pset_EnvironmentalImpactIndicators - Reference: B2010 - 0.015-Enchape- Gres; sets with these values: 2
Pset_WallCommon - LoadBearing: no; ExtendToStructure: no; Reference: B2010 - 0.015-Enchape- Gres
Name (Basic Wall:B2010 - 0.015-Enchape- Gres:...) | In | Length (m) | GrossFootprintArea (m2) | GrossVolume (m3) = NetVolume (m3) | GrossSideArea (m2) = NetSideArea (m2)
1813056 | Nivel 1 | 1.2 | 0.018 | 0.00248143 | 0.165429
1813057 | Nivel 1 | 1.2 | 0.018 | 0.00248143 | 0.165429
1813058 | Nivel 1 | 1.2 | 0.018 | 0.00248143 | 0.165429
1813059 | Nivel 1 | 1.2 | 0.018 | 0.00248143 | 0.165429
1813060 | Nivel 1 | 1.1995 | 0.0179925 | 0.00248039 | 0.16536
1813061 | Nivel 1 | 1.1995 | 0.0179925 | 0.00248039 | 0.16536
1813062 | Nivel 1 | 1.1995 | 0.0179925 | 0.00248039 | 0.16536
1813634 | Nivel 1 | 1.2 | 0.018 | 0.00248143 | 0.165429
1813635 | Nivel 1 | 1.2 | 0.018 | 0.00248143 | 0.165429
1813636 | Nivel 1 | 1.2 | 0.018 | 0.00248143 | 0.165429
1813637 | Nivel 1 | 1.2 | 0.018 | 0.00248143 | 0.165429
1813638 | Nivel 1 | 1.2 | 0.018 | 0.00248143 | 0.165429
1813639 | Nivel 1 | 1.2 | 0.018 | 0.00248143 | 0.165429
1813640 | Nivel 1 | 1.2 | 0.018 | 0.00248143 | 0.165429
1817302 | Nivel 2 | 1.2 | 0.018 | 0.00248143 | 0.165429
1817303 | Nivel 2 | 1.2 | 0.018 | 0.00248143 | 0.165429
1817304 | Nivel 2 | 1.2 | 0.018 | 0.00248143 | 0.165429
1817305 | Nivel 2 | 1.2 | 0.018 | 0.00248143 | 0.165429
1817306 | Nivel 2 | 1.2 | 0.018 | 0.00248143 | 0.165429
1817307 | Nivel 2 | 1.2 | 0.018 | 0.00248143 | 0.165429
1817308 | Nivel 2 | 1.2 | 0.018 | 0.00248143 | 0.165429
1817455 | Nivel 2 | 1.2 | 0.018 | 0.00248143 | 0.165429
1817456 | Nivel 2 | 1.2 | 0.018 | 0.00248143 | 0.165429
1817457 | Nivel 2 | 1.2 | 0.018 | 0.00248143 | 0.165429
1817458 | Nivel 2 | 1.2 | 0.018 | 0.00248143 | 0.165429
1817459 | Nivel 2 | 1.2 | 0.018 | 0.00248143 | 0.165429
1817460 | Nivel 2 | 1.2 | 0.018 | 0.00248143 | 0.165429
1817461 | Nivel 2 | 1.2 | 0.018 | 0.00248143 | 0.165429
1819883 | Nivel 3 | 1.2 | 0.018 | 0.00248143 | 0.165429
1819884 | Nivel 3 | 1.2 | 0.018 | 0.00248143 | 0.165429
1819885 | Nivel 3 | 1.2 | 0.018 | 0.00248143 | 0.165429
1819886 | Nivel 3 | 1.2 | 0.018 | 0.00248143 | 0.165429
1819887 | Nivel 3 | 1.2 | 0.018 | 0.00248143 | 0.165429
1819888 | Nivel 3 | 1.2 | 0.018 | 0.00248143 | 0.165429
1819889 | Nivel 3 | 1.2 | 0.018 | 0.00248143 | 0.165429
1820036 | Nivel 3 | 1.2 | 0.018 | 0.00248143 | 0.165429
1820037 | Nivel 3 | 1.2 | 0.018 | 0.00248143 | 0.165429
1820038 | Nivel 3 | 1.2 | 0.018 | 0.00248143 | 0.165429
1820039 | Nivel 3 | 1.2 | 0.018 | 0.00248143 | 0.165429
1820040 | Nivel 3 | 1.2 | 0.018 | 0.00248143 | 0.165429
1820041 | Nivel 3 | 1.2 | 0.018 | 0.00248143 | 0.165429
1820042 | Nivel 3 | 1.2 | 0.018 | 0.00248143 | 0.165429
1820197 | Nivel 4 | 1.2 | 0.018 | 0.00248143 | 0.165429
1820198 | Nivel 4 | 1.2 | 0.018 | 0.00248143 | 0.165429
1820199 | Nivel 4 | 1.2 | 0.018 | 0.00248143 | 0.165429
1820200 | Nivel 4 | 1.2 | 0.018 | 0.00248143 | 0.165429
1820201 | Nivel 4 | 1.2 | 0.018 | 0.00248143 | 0.165429
1820202 | Nivel 4 | 1.2 | 0.018 | 0.00248143 | 0.165429
1820203 | Nivel 4 | 1.2 | 0.018 | 0.00248143 | 0.165429
1820350 | Nivel 4 | 1.2 | 0.018 | 0.00248143 | 0.165429
1820351 | Nivel 4 | 1.2 | 0.018 | 0.00248143 | 0.165429
1820352 | Nivel 4 | 1.2 | 0.018 | 0.00248143 | 0.165429
1820353 | Nivel 4 | 1.2 | 0.018 | 0.00248143 | 0.165429
1820354 | Nivel 4 | 1.2 | 0.018 | 0.00248143 | 0.165429
1820355 | Nivel 4 | 1.2 | 0.018 | 0.00248143 | 0.165429
1820356 | Nivel 4 | 1.2 | 0.018 | 0.00248143 | 0.165429
1820511 | Nivel 5 | 1.2 | 0.018 | 0.00248143 | 0.165429
1820512 | Nivel 5 | 1.2 | 0.018 | 0.00248143 | 0.165429
1820513 | Nivel 5 | 1.2 | 0.018 | 0.00248143 | 0.165429
1820514 | Nivel 5 | 1.2 | 0.018 | 0.00248143 | 0.165429
1820515 | Nivel 5 | 1.2 | 0.018 | 0.00248143 | 0.165429
1820516 | Nivel 5 | 1.2 | 0.018 | 0.00248143 | 0.165429
1820517 | Nivel 5 | 1.2 | 0.018 | 0.00248143 | 0.165429
1820664 | Nivel 5 | 1.2 | 0.018 | 0.00248143 | 0.165429
1820665 | Nivel 5 | 1.2 | 0.018 | 0.00248143 | 0.165429
1820666 | Nivel 5 | 1.2 | 0.018 | 0.00248143 | 0.165429
1820667 | Nivel 5 | 1.2 | 0.018 | 0.00248143 | 0.165429
1820668 | Nivel 5 | 1.2 | 0.018 | 0.00248143 | 0.165429
1820669 | Nivel 5 | 1.2 | 0.018 | 0.00248143 | 0.165429
1820670 | Nivel 5 | 1.2 | 0.018 | 0.00248143 | 0.165429

# IfcWall: Basic Wall:B2010 - 0.03m - ME enchape no estructural - Ladrillo (256)
Type - PredefinedType: STANDARD
Type - Pset_WallCommon - IsExternal: yes; ThermalTransmittance: 24 kg/K/s3
Classification: 21-02 20 10 10 Uniformat (Uniformat); Material: LADRILLO CLARO
Qto_WallBaseQuantities - Height: 0.1 m; Width: 0.03 m
Pset_EnvironmentalImpactIndicators - Reference: B2010 - 0.03m - ME enchape no estructural - Ladrillo; sets with these values: 2
Pset_WallCommon - LoadBearing: no; ExtendToStructure: no; Reference: B2010 - 0.03m - ME enchape no estructural - Ladrillo
Name (Basic Wall:B2010 - 0.03m - ME enchape no estructural - Ladrillo:...) | In | Length (m) | GrossFootprintArea (m2) | GrossVolume (m3) = NetVolume (m3) | GrossSideArea (m2) = NetSideArea (m2)
1269139 | Nivel 3 | 2.4 | 0.072 | 0.0072 | 0.24
1269363 | Nivel 4 | 2.4 | 0.072 | 0.0072 | 0.24
1269365 | Nivel 5 | 2.4 | 0.072 | 0.0072 | 0.24
1269367 | Nivel 6 | 2.4 | 0.072 | 0.0072 | 0.24
1279103 | Nivel 7 | 4.25 | 0.1275 | 0.01275 | 0.425
1279240 | Nivel 7 | 6.28 | 0.1884 | 0.01884 | 0.628
1279357 | Nivel 7 | 4.25 | 0.1275 | 0.01275 | 0.425
1279526 | Nivel 7 | 1.86 | 0.0558 | 0.00558 | 0.186
1279634 | Nivel 7 | 1.875 | 0.05625 | 0.005625 | 0.1875
1279755 | Nivel 7 | 4.265 | 0.12795 | 0.012795 | 0.4265
1279873 | Nivel 7 | 6.28 | 0.1884 | 0.01884 | 0.628
1279969 | Nivel 7 | 4.15 | 0.1245 | 0.01245 | 0.415
1280102 | Nivel 7 | 1.975 | 0.05925 | 0.005925 | 0.1975
1280211 | Nivel 7 | 1.975 | 0.05925 | 0.005925 | 0.1975
1285233 | Nivel 5 | 0.505 | 0.01515 | 0.001515 | 0.0505
1285234 | Nivel 5 | 0.615 | 0.01845 | 0.001845 | 0.0615
1285235 | Nivel 5 | 0.47 | 0.0141 | 0.00141 | 0.047
1285236 | Nivel 5 | 2.68366 | 0.0805098 | 0.00805098 | 0.268366
1285237 | Nivel 5 | 0.625 | 0.01875 | 0.001875 | 0.0625
1285238 | Nivel 5 | 3.7 | 0.111 | 0.0111 | 0.37
1285240 | Nivel 5 | 0.505 | 0.01515 | 0.001515 | 0.0505
1285241 | Nivel 5 | 0.615 | 0.01845 | 0.001845 | 0.0615
1285242 | Nivel 5 | 0.47 | 0.0141 | 0.00141 | 0.047
1285243 | Nivel 5 | 2.68366 | 0.0805098 | 0.00805098 | 0.268366
1285244 | Nivel 5 | 0.625 | 0.01875 | 0.001875 | 0.0625
1285245 | Nivel 5 | 3.7 | 0.111 | 0.0111 | 0.37
1285247 | Nivel 5 | 0.505 | 0.01515 | 0.001515 | 0.0505
1285248 | Nivel 5 | 0.615 | 0.01845 | 0.001845 | 0.0615
1285249 | Nivel 5 | 0.47 | 0.0141 | 0.00141 | 0.047
1285250 | Nivel 5 | 2.68366 | 0.0805098 | 0.00805098 | 0.268366
1285251 | Nivel 5 | 0.625 | 0.01875 | 0.001875 | 0.0625
1285252 | Nivel 5 | 3.7 | 0.111 | 0.0111 | 0.37
1285254 | Nivel 5 | 0.505 | 0.01515 | 0.001515 | 0.0505
1285255 | Nivel 5 | 0.615 | 0.01845 | 0.001845 | 0.0615
1285256 | Nivel 5 | 0.47 | 0.0141 | 0.00141 | 0.047
1285257 | Nivel 5 | 2.68366 | 0.0805098 | 0.00805098 | 0.268366
1285258 | Nivel 5 | 0.625 | 0.01875 | 0.001875 | 0.0625
1285259 | Nivel 5 | 3.7 | 0.111 | 0.0111 | 0.37
1285261 | Nivel 6 | 0.505 | 0.01515 | 0.001515 | 0.0505
1285262 | Nivel 6 | 0.615 | 0.01845 | 0.001845 | 0.0615
1285263 | Nivel 6 | 0.47 | 0.0141 | 0.00141 | 0.047
1285264 | Nivel 6 | 2.68366 | 0.0805098 | 0.00805098 | 0.268366
1285265 | Nivel 6 | 0.625 | 0.01875 | 0.001875 | 0.0625
1285266 | Nivel 6 | 3.7 | 0.111 | 0.0111 | 0.37
1285268 | Nivel 6 | 0.505 | 0.01515 | 0.001515 | 0.0505
1285269 | Nivel 6 | 0.615 | 0.01845 | 0.001845 | 0.0615
1285270 | Nivel 6 | 0.47 | 0.0141 | 0.00141 | 0.047
1285271 | Nivel 6 | 2.68366 | 0.0805098 | 0.00805098 | 0.268366
1285272 | Nivel 6 | 0.625 | 0.01875 | 0.001875 | 0.0625
1285273 | Nivel 6 | 3.7 | 0.111 | 0.0111 | 0.37
1285275 | Nivel 6 | 0.505 | 0.01515 | 0.001515 | 0.0505
1285276 | Nivel 6 | 0.615 | 0.01845 | 0.001845 | 0.0615
1285277 | Nivel 6 | 0.47 | 0.0141 | 0.00141 | 0.047
1285278 | Nivel 6 | 2.68366 | 0.0805098 | 0.00805098 | 0.268366
1285279 | Nivel 6 | 0.625 | 0.01875 | 0.001875 | 0.0625
1285280 | Nivel 6 | 3.7 | 0.111 | 0.0111 | 0.37
1285282 | Nivel 6 | 0.505 | 0.01515 | 0.001515 | 0.0505
1285283 | Nivel 6 | 0.615 | 0.01845 | 0.001845 | 0.0615
1285284 | Nivel 6 | 0.47 | 0.0141 | 0.00141 | 0.047
1285285 | Nivel 6 | 2.68366 | 0.0805098 | 0.00805098 | 0.268366
1285286 | Nivel 6 | 0.625 | 0.01875 | 0.001875 | 0.0625
1285287 | Nivel 6 | 3.7 | 0.111 | 0.0111 | 0.37
1286119 | Nivel 5 | 1.175 | 0.03525 | 0.003525 | 0.1175
1286120 | Nivel 5 | 2.59 | 0.0777 | 0.00777 | 0.259
1286122 | Nivel 5 | 1.175 | 0.03525 | 0.003525 | 0.1175
1286123 | Nivel 5 | 2.59 | 0.0777 | 0.00777 | 0.259
1286125 | Nivel 5 | 1.175 | 0.03525 | 0.003525 | 0.1175
1286126 | Nivel 5 | 2.59 | 0.0777 | 0.00777 | 0.259
1286128 | Nivel 5 | 1.175 | 0.03525 | 0.003525 | 0.1175
1286129 | Nivel 5 | 2.59 | 0.0777 | 0.00777 | 0.259
1286131 | Nivel 6 | 1.175 | 0.03525 | 0.003525 | 0.1175
1286132 | Nivel 6 | 2.59 | 0.0777 | 0.00777 | 0.259
1286134 | Nivel 6 | 1.175 | 0.03525 | 0.003525 | 0.1175
1286135 | Nivel 6 | 2.59 | 0.0777 | 0.00777 | 0.259
1286137 | Nivel 6 | 1.175 | 0.03525 | 0.003525 | 0.1175
1286138 | Nivel 6 | 2.59 | 0.0777 | 0.00777 | 0.259
1286140 | Nivel 6 | 1.175 | 0.03525 | 0.003525 | 0.1175
1286141 | Nivel 6 | 2.59 | 0.0777 | 0.00777 | 0.259
1286833 | Nivel 5 | 1.35 | 0.0405 | 0.00405 | 0.135
1286835 | Nivel 5 | 1.35 | 0.0405 | 0.00405 | 0.135
1286837 | Nivel 5 | 1.35 | 0.0405 | 0.00405 | 0.135
1286839 | Nivel 5 | 1.35 | 0.0405 | 0.00405 | 0.135
1286841 | Nivel 6 | 1.35 | 0.0405 | 0.00405 | 0.135
1286843 | Nivel 6 | 1.35 | 0.0405 | 0.00405 | 0.135
1286845 | Nivel 6 | 1.35 | 0.0405 | 0.00405 | 0.135
1286847 | Nivel 6 | 1.35 | 0.0405 | 0.00405 | 0.135
1287062 | Nivel 2 | 0.5 | 0.015 | 0.0015 | 0.05
1287063 | Nivel 2 | 2.68366 | 0.0805098 | 0.00805098 | 0.268366
1287064 | Nivel 2 | 0.625 | 0.01875 | 0.001875 | 0.0625
1287065 | Nivel 2 | 3.7 | 0.111 | 0.0111 | 0.37
1287066 | Nivel 2 | 0.505 | 0.01515 | 0.001515 | 0.0505
1287067 | Nivel 2 | 0.615 | 0.01845 | 0.001845 | 0.0615
1287068 | Nivel 2 | 0.47 | 0.0141 | 0.00141 | 0.047
1287069 | Nivel 2 | 2.68366 | 0.0805098 | 0.00805098 | 0.268366
1287070 | Nivel 2 | 0.625 | 0.01875 | 0.001875 | 0.0625
1287071 | Nivel 2 | 3.7 | 0.111 | 0.0111 | 0.37
1287074 | Nivel 2 | 0.5 | 0.015 | 0.0015 | 0.05
1287075 | Nivel 2 | 2.68366 | 0.0805098 | 0.00805098 | 0.268366
1287076 | Nivel 2 | 0.625 | 0.01875 | 0.001875 | 0.0625
1287077 | Nivel 2 | 3.7 | 0.111 | 0.0111 | 0.37
1287078 | Nivel 2 | 0.505 | 0.01515 | 0.001515 | 0.0505
1287079 | Nivel 2 | 0.615 | 0.01845 | 0.001845 | 0.0615
1287080 | Nivel 2 | 0.47 | 0.0141 | 0.00141 | 0.047
1287081 | Nivel 2 | 2.68366 | 0.0805098 | 0.00805098 | 0.268366
1287082 | Nivel 2 | 0.625 | 0.01875 | 0.001875 | 0.0625
1287083 | Nivel 2 | 3.7 | 0.111 | 0.0111 | 0.37
1287084 | Nivel 2 | 1.175 | 0.03525 | 0.003525 | 0.1175
1287085 | Nivel 2 | 2.59 | 0.0777 | 0.00777 | 0.259
1287086 | Nivel 2 | 1.175 | 0.03525 | 0.003525 | 0.1175
1287087 | Nivel 2 | 2.59 | 0.0777 | 0.00777 | 0.259
1287088 | Nivel 2 | 1.175 | 0.03525 | 0.003525 | 0.1175
1287089 | Nivel 2 | 2.59 | 0.0777 | 0.00777 | 0.259
1287090 | Nivel 2 | 1.175 | 0.03525 | 0.003525 | 0.1175
1287091 | Nivel 2 | 2.59 | 0.0777 | 0.00777 | 0.259
1287092 | Nivel 2 | 1.35 | 0.0405 | 0.00405 | 0.135
1287093 | Nivel 2 | 1.35 | 0.0405 | 0.00405 | 0.135
1287094 | Nivel 2 | 1.35 | 0.0405 | 0.00405 | 0.135
1287095 | Nivel 2 | 1.35 | 0.0405 | 0.00405 | 0.135
1287098 | Nivel 4 | 0.505 | 0.01515 | 0.001515 | 0.0505
1287099 | Nivel 4 | 0.615 | 0.01845 | 0.001845 | 0.0615
1287100 | Nivel 4 | 0.47 | 0.0141 | 0.00141 | 0.047
1287101 | Nivel 4 | 2.68366 | 0.0805098 | 0.00805098 | 0.268366
1287102 | Nivel 4 | 0.625 | 0.01875 | 0.001875 | 0.0625
1287103 | Nivel 4 | 3.7 | 0.111 | 0.0111 | 0.37
1287104 | Nivel 4 | 0.505 | 0.01515 | 0.001515 | 0.0505
1287105 | Nivel 4 | 0.615 | 0.01845 | 0.001845 | 0.0615
1287106 | Nivel 4 | 0.47 | 0.0141 | 0.00141 | 0.047
1287107 | Nivel 4 | 2.68366 | 0.0805098 | 0.00805098 | 0.268366
1287108 | Nivel 4 | 0.625 | 0.01875 | 0.001875 | 0.0625
1287109 | Nivel 4 | 3.7 | 0.111 | 0.0111 | 0.37
1287110 | Nivel 4 | 0.505 | 0.01515 | 0.001515 | 0.0505
1287111 | Nivel 4 | 0.615 | 0.01845 | 0.001845 | 0.0615
1287112 | Nivel 4 | 0.47 | 0.0141 | 0.00141 | 0.047
1287113 | Nivel 4 | 2.68366 | 0.0805098 | 0.00805098 | 0.268366
1287114 | Nivel 4 | 0.625 | 0.01875 | 0.001875 | 0.0625
1287115 | Nivel 4 | 3.7 | 0.111 | 0.0111 | 0.37
1287116 | Nivel 4 | 0.505 | 0.01515 | 0.001515 | 0.0505
1287117 | Nivel 4 | 0.615 | 0.01845 | 0.001845 | 0.0615
1287118 | Nivel 4 | 0.47 | 0.0141 | 0.00141 | 0.047
1287119 | Nivel 4 | 2.68366 | 0.0805098 | 0.00805098 | 0.268366
1287120 | Nivel 4 | 0.625 | 0.01875 | 0.001875 | 0.0625
1287121 | Nivel 4 | 3.7 | 0.111 | 0.0111 | 0.37
1287122 | Nivel 4 | 1.175 | 0.03525 | 0.003525 | 0.1175
1287123 | Nivel 4 | 2.59 | 0.0777 | 0.00777 | 0.259
1287124 | Nivel 4 | 1.175 | 0.03525 | 0.003525 | 0.1175
1287125 | Nivel 4 | 2.59 | 0.0777 | 0.00777 | 0.259
1287126 | Nivel 4 | 1.175 | 0.03525 | 0.003525 | 0.1175
1287127 | Nivel 4 | 2.59 | 0.0777 | 0.00777 | 0.259
1287128 | Nivel 4 | 1.175 | 0.03525 | 0.003525 | 0.1175
1287129 | Nivel 4 | 2.59 | 0.0777 | 0.00777 | 0.259
1287130 | Nivel 4 | 1.35 | 0.0405 | 0.00405 | 0.135
1287131 | Nivel 4 | 1.35 | 0.0405 | 0.00405 | 0.135
1287132 | Nivel 4 | 1.35 | 0.0405 | 0.00405 | 0.135
1287133 | Nivel 4 | 1.35 | 0.0405 | 0.00405 | 0.135
1287224 | Nivel 3 | 0.505 | 0.01515 | 0.001515 | 0.0505
1287225 | Nivel 3 | 0.615 | 0.01845 | 0.001845 | 0.0615
1287226 | Nivel 3 | 0.47 | 0.0141 | 0.00141 | 0.047
1287227 | Nivel 3 | 2.68366 | 0.0805098 | 0.00805098 | 0.268366
1287228 | Nivel 3 | 0.625 | 0.01875 | 0.001875 | 0.0625
1287229 | Nivel 3 | 3.7 | 0.111 | 0.0111 | 0.37
1287230 | Nivel 3 | 0.505 | 0.01515 | 0.001515 | 0.0505
1287231 | Nivel 3 | 0.615 | 0.01845 | 0.001845 | 0.0615
1287232 | Nivel 3 | 0.47 | 0.0141 | 0.00141 | 0.047
1287233 | Nivel 3 | 2.68366 | 0.0805098 | 0.00805098 | 0.268366
1287234 | Nivel 3 | 0.625 | 0.01875 | 0.001875 | 0.0625
1287235 | Nivel 3 | 3.7 | 0.111 | 0.0111 | 0.37
1287236 | Nivel 3 | 0.505 | 0.01515 | 0.001515 | 0.0505
1287237 | Nivel 3 | 0.615 | 0.01845 | 0.001845 | 0.0615
1287238 | Nivel 3 | 0.47 | 0.0141 | 0.00141 | 0.047
1287239 | Nivel 3 | 2.68366 | 0.0805098 | 0.00805098 | 0.268366
1287240 | Nivel 3 | 0.625 | 0.01875 | 0.001875 | 0.0625
1287241 | Nivel 3 | 3.7 | 0.111 | 0.0111 | 0.37
1287242 | Nivel 3 | 0.505 | 0.01515 | 0.001515 | 0.0505
1287243 | Nivel 3 | 0.615 | 0.01845 | 0.001845 | 0.0615
1287244 | Nivel 3 | 0.47 | 0.0141 | 0.00141 | 0.047
1287245 | Nivel 3 | 2.68366 | 0.0805098 | 0.00805098 | 0.268366
1287246 | Nivel 3 | 0.625 | 0.01875 | 0.001875 | 0.0625
1287247 | Nivel 3 | 3.7 | 0.111 | 0.0111 | 0.37
1287248 | Nivel 3 | 1.175 | 0.03525 | 0.003525 | 0.1175
1287249 | Nivel 3 | 2.59 | 0.0777 | 0.00777 | 0.259
1287250 | Nivel 3 | 1.175 | 0.03525 | 0.003525 | 0.1175
1287251 | Nivel 3 | 2.59 | 0.0777 | 0.00777 | 0.259
1287252 | Nivel 3 | 1.175 | 0.03525 | 0.003525 | 0.1175
1287253 | Nivel 3 | 2.59 | 0.0777 | 0.00777 | 0.259
1287254 | Nivel 3 | 1.175 | 0.03525 | 0.003525 | 0.1175
1287255 | Nivel 3 | 2.59 | 0.0777 | 0.00777 | 0.259
1287256 | Nivel 3 | 1.35 | 0.0405 | 0.00405 | 0.135
1287257 | Nivel 3 | 1.35 | 0.0405 | 0.00405 | 0.135
1287258 | Nivel 3 | 1.35 | 0.0405 | 0.00405 | 0.135
1287259 | Nivel 3 | 1.35 | 0.0405 | 0.00405 | 0.135
1289247 | Nivel 3 | 2.125 | 0.06375 | 0.006375 | 0.2125
1289279 | Nivel 3 | 0.54 | 0.0162 | 0.00162 | 0.054
1289326 | Nivel 3 | 2.125 | 0.06375 | 0.006375 | 0.2125
1289424 | Nivel 3 | 0.54 | 0.0162 | 0.00162 | 0.054
1289455 | Nivel 5 | 2.125 | 0.06375 | 0.006375 | 0.2125
1289456 | Nivel 5 | 0.54 | 0.0162 | 0.00162 | 0.054
1289457 | Nivel 5 | 2.125 | 0.06375 | 0.006375 | 0.2125
1289458 | Nivel 5 | 0.54 | 0.0162 | 0.00162 | 0.054
1289588 | Nivel 3 | 0.54 | 0.0162 | 0.00162 | 0.054
1289638 | Nivel 3 | 2.125 | 0.06375 | 0.006375 | 0.2125
1289700 | Nivel 3 | 2.125 | 0.06375 | 0.006375 | 0.2125
1289747 | Nivel 3 | 0.54 | 0.0162 | 0.00162 | 0.054
1289778 | Nivel 5 | 0.54 | 0.0162 | 0.00162 | 0.054
1289779 | Nivel 5 | 2.125 | 0.06375 | 0.006375 | 0.2125
1289780 | Nivel 5 | 2.125 | 0.06375 | 0.006375 | 0.2125
1289781 | Nivel 5 | 0.54 | 0.0162 | 0.00162 | 0.054
1289855 | Nivel 2 | 0.54 | 0.0162 | 0.00162 | 0.054
1289926 | Nivel 2 | 2.125 | 0.06375 | 0.006375 | 0.2125
1290053 | Nivel 2 | 2.125 | 0.06375 | 0.006375 | 0.2125
1290091 | Nivel 2 | 0.54 | 0.0162 | 0.00162 | 0.054
1290130 | Nivel 6 | 0.54 | 0.0162 | 0.00162 | 0.054
1290131 | Nivel 6 | 2.125 | 0.06375 | 0.006375 | 0.2125
1290132 | Nivel 6 | 2.125 | 0.06375 | 0.006375 | 0.2125
1290133 | Nivel 6 | 0.54 | 0.0162 | 0.00162 | 0.054
1290140 | Nivel 4 | 0.54 | 0.0162 | 0.00162 | 0.054
1290141 | Nivel 4 | 2.125 | 0.06375 | 0.006375 | 0.2125
1290142 | Nivel 4 | 2.125 | 0.06375 | 0.006375 | 0.2125
1290143 | Nivel 4 | 0.54 | 0.0162 | 0.00162 | 0.054
1290267 | Nivel 4 | 2.125 | 0.06375 | 0.006375 | 0.2125
1290431 | Nivel 4 | 0.54 | 0.0162 | 0.00162 | 0.054
1290556 | Nivel 4 | 2.125 | 0.06375 | 0.006375 | 0.2125
1290585 | Nivel 4 | 0.54 | 0.0162 | 0.00162 | 0.054
1290657 | Nivel 6 | 2.125 | 0.06375 | 0.006375 | 0.2125
1290658 | Nivel 6 | 0.54 | 0.0162 | 0.00162 | 0.054
1290659 | Nivel 6 | 2.125 | 0.06375 | 0.006375 | 0.2125
1290660 | Nivel 6 | 0.54 | 0.0162 | 0.00162 | 0.054
1290671 | Nivel 2 | 2.125 | 0.06375 | 0.006375 | 0.2125
1290672 | Nivel 2 | 0.525 | 0.01575 | 0.001575 | 0.0525
1290673 | Nivel 2 | 2.125 | 0.06375 | 0.006375 | 0.2125
1290674 | Nivel 2 | 0.525 | 0.01575 | 0.001575 | 0.0525
1299793 | Nivel 4 | 1.2 | 0.036 | 0.0036 | 0.12
1299882 | Nivel 3 | 1.2 | 0.036 | 0.0036 | 0.12
1299884 | Nivel 3 | 1.2 | 0.036 | 0.0036 | 0.12
1299886 | Nivel 3 | 1.2 | 0.036 | 0.0036 | 0.12
1299888 | Nivel 3 | 1.2 | 0.036 | 0.0036 | 0.12
1299890 | Nivel 4 | 1.2 | 0.036 | 0.0036 | 0.12
1299892 | Nivel 4 | 1.2 | 0.036 | 0.0036 | 0.12
1299894 | Nivel 4 | 1.2 | 0.036 | 0.0036 | 0.12
1299896 | Nivel 5 | 1.2 | 0.036 | 0.0036 | 0.12
1299898 | Nivel 5 | 1.2 | 0.036 | 0.0036 | 0.12
1299900 | Nivel 5 | 1.2 | 0.036 | 0.0036 | 0.12
1299902 | Nivel 5 | 1.2 | 0.036 | 0.0036 | 0.12
1299904 | Nivel 6 | 1.2 | 0.036 | 0.0036 | 0.12
1299906 | Nivel 6 | 1.2 | 0.036 | 0.0036 | 0.12
1299908 | Nivel 6 | 1.2 | 0.036 | 0.0036 | 0.12
1299910 | Nivel 6 | 1.2 | 0.036 | 0.0036 | 0.12
1299912 | Nivel 2 | 1.2 | 0.036 | 0.0036 | 0.12
1299914 | Nivel 2 | 1.2 | 0.036 | 0.0036 | 0.12
1299916 | Nivel 2 | 1.2 | 0.036 | 0.0036 | 0.12
1299918 | Nivel 2 | 1.2 | 0.036 | 0.0036 | 0.12
1300566 | Nivel 7 | 2.3995 | 0.071985 | 0.0071985 | 0.23995
1300822 | Nivel 7 | 2.3995 | 0.071985 | 0.0071985 | 0.23995
1300927 | Nivel 7 | 2.399 | 0.07197 | 0.007197 | 0.2399
1300982 | Nivel 7 | 2.399 | 0.07197 | 0.007197 | 0.2399
1302764 | Nivel 2 | 6.28 | 0.1884 | 0.01884 | 0.628
1339187 | Nivel 2 | 2.4 | 0.072 | 0.0072 | 0.24

# IfcWall: Basic Wall:B2010 - 0.03m - Muro exterior- pintura+ concreto+ pintura (4)
In: Nivel 1
Type - PredefinedType: STANDARD; Material: PINTURA BLANCA PARA EXTERIORES (2), 0 muro divisorio
Type - Pset_WallCommon - IsExternal: yes
Classification: 21-02 20 10 20 Uniformat (Uniformat)
Qto_WallBaseQuantities - PINTURA BLANCA PARA EXTERIORES, Width: 0.002 m; 0 muro divisorio, Width: 0.03 m; PINTURA BLANCA PARA EXTERIORES (2), Width: 0.002 m; Width: 0.034 m; Height: 0.79 m; Length: 0.495 m; GrossVolume: 0.0132957 m3; GrossSideArea: 0.39105 m2; NetSideArea: 0.39105 m2; NetVolume: 0.0132957 m3
Pset_EnvironmentalImpactIndicators - Reference: B2010 - 0.03m - Muro exterior- pintura+ concreto+ pintura; sets with these values: 2
Pset_WallCommon - LoadBearing: no; ExtendToStructure: no; Reference: B2010 - 0.03m - Muro exterior- pintura+ concreto+ pintura
Name (Basic Wall:B2010 - 0.03m - Muro exterior- pintura+ concreto+ pintura:...)
1793721
1794375
1794849
1795650

# IfcWall: Basic Wall:B2010 - 0.03m - Muro interior en estuco+pintura+ concreto+ estuco+ pintura (20)
Type - PredefinedType: STANDARD; Material: Estuco y pintura (2), 0 muro divisorio
Type - Pset_WallCommon - IsExternal: yes; ThermalTransmittance: 52.25 kg/K/s3
Classification: 21-03 10 10 10 Uniformat (Uniformat)
Qto_WallBaseQuantities - Estuco y pintura, Width: 0.002 m; 0 muro divisorio, Width: 0.03 m; Estuco y pintura (2), Width: 0.002 m; Width: 0.034 m; Height: 0.78 m; Length: 0.5625 m; GrossVolume: 0.01326 m3; GrossSideArea: 0.39 m2; NetSideArea: 0.39 m2; NetVolume: 0.01326 m3
Pset_EnvironmentalImpactIndicators - Reference: B2010 - 0.03m - Muro interior en estuco+pintura+ concreto+ estuco+ pintura; sets with these values: 2
Pset_WallCommon - LoadBearing: no; ExtendToStructure: no; Reference: B2010 - 0.03m - Muro interior en estuco+pintura+ concreto+ estuco+ pintura
Name (Basic Wall:B2010 - 0.03m - Muro interior en estuco+pintura+ concreto+ estuco+ pintura:...) | In
1111730 | Nivel 2
1113538 | Nivel 3
1113543 | Nivel 3
1113548 | Nivel 3
1113553 | Nivel 3
1113558 | Nivel 4
1113563 | Nivel 4
1113568 | Nivel 4
1113573 | Nivel 4
1113578 | Nivel 5
1113583 | Nivel 5
1113588 | Nivel 5
1113593 | Nivel 5
1113598 | Nivel 6
1113603 | Nivel 6
1113608 | Nivel 6
1113613 | Nivel 6
1113618 | Nivel 2
1113623 | Nivel 2
1113628 | Nivel 2

# IfcWall: Basic Wall:B2010 - 0.05m - MI No estructural- Concreto (44)
Type - PredefinedType: STANDARD
Type - Pset_WallCommon - IsExternal: yes
Classification: 21-03 10 10 10 Uniformat (Uniformat); Material: 0 muro divisorio
Qto_WallBaseQuantities - Width: 0.05 m
Pset_EnvironmentalImpactIndicators - Reference: B2010 - 0.05m - MI No estructural- Concreto; sets with these values: 2
Pset_WallCommon - LoadBearing: no; Reference: B2010 - 0.05m - MI No estructural- Concreto
Name (Basic Wall:B2010 - 0.05m - MI No estructural- Concreto:...) | In | Height (m) | Length (m) | GrossFootprintArea (m2) | GrossVolume (m3) = NetVolume (m3) | GrossSideArea (m2) = NetSideArea (m2) | ExtendToStructure
728553 | Nivel 1 | 2.35 | 1.285 | 0.06425 | 0.150988 | 3.01975 | no
760622 | Nivel 7 | 0.5762 | 1.3 | 0.065 | 0.0311155 | 0.62231 | yes
764404 | Nivel 7 | 0.5762 | 1.3 | 0.065 | 0.0311155 | 0.62231 | yes
767780 | Nivel 7 | 0.5762 | 1.3 | 0.065 | 0.0311155 | 0.62231 | yes
767979 | Nivel 7 | 0.8 | 1.35 | 0.0675 | 0.054 | 1.08 | no
791819 | Nivel 2 | 2.25 | 1.72 | 0.086 | 0.1935 | 3.87 | no
791820 | Nivel 2 | 2.25 | 0.15 | 0.0075 | 0.016875 | 0.3375 | no
791986 | Nivel 2 | 2.25 | 1.72 | 0.086 | 0.1935 | 3.87 | no
791987 | Nivel 2 | 2.25 | 0.15 | 0.0075 | 0.016875 | 0.3375 | no
792184 | Nivel 2 | 2.25 | 1.285 | 0.06425 | 0.144562 | 2.89125 | no
792357 | Nivel 2 | 2.25 | 1.285 | 0.06425 | 0.144562 | 2.89125 | no
872654 | Nivel 1 | 2.35 | 1.285 | 0.06425 | 0.150988 | 3.01975 | no
872852 | Nivel 1 | 2.35 | 1.72 | 0.086 | 0.2021 | 4.042 | no
872853 | Nivel 1 | 2.35 | 0.15 | 0.0075 | 0.017625 | 0.3525 | no
1195791 | Nivel 1 | 2.35 | 0.32 | 0.016 | 0.0376 | 0.752 | no
1196225 | Nivel 1 | 2.35 | 0.2 | 0.01 | 0.0235 | 0.47 | no
1196327 | Nivel 1 | 2.35 | 0.71832 | 0.035916 | 0.0844026 | 1.68805 | no
1196389 | Nivel 1 | 2.35 | 0.25 | 0.0125 | 0.029375 | 0.5875 | no
1196447 | Nivel 1 | 2.35 | 0.27 | 0.0135 | 0.031725 | 0.6345 | no
1200354 | Nivel 3 | 2.25 | 1.72 | 0.086 | 0.1935 | 3.87 | no
1200355 | Nivel 3 | 2.25 | 0.15 | 0.0075 | 0.016875 | 0.3375 | no
1200356 | Nivel 3 | 2.25 | 1.72 | 0.086 | 0.1935 | 3.87 | no
1200357 | Nivel 3 | 2.25 | 0.15 | 0.0075 | 0.016875 | 0.3375 | no
1200358 | Nivel 3 | 2.25 | 1.285 | 0.06425 | 0.144562 | 2.89125 | no
1200360 | Nivel 3 | 2.25 | 1.285 | 0.06425 | 0.144562 | 2.89125 | no
1200365 | Nivel 4 | 2.25 | 1.72 | 0.086 | 0.1935 | 3.87 | no
1200366 | Nivel 4 | 2.25 | 0.15 | 0.0075 | 0.016875 | 0.3375 | no
1200367 | Nivel 4 | 2.25 | 1.72 | 0.086 | 0.1935 | 3.87 | no
1200368 | Nivel 4 | 2.25 | 0.15 | 0.0075 | 0.016875 | 0.3375 | no
1200369 | Nivel 4 | 2.25 | 1.285 | 0.06425 | 0.144562 | 2.89125 | no
1200371 | Nivel 4 | 2.25 | 1.285 | 0.06425 | 0.144562 | 2.89125 | no
1200376 | Nivel 5 | 2.25 | 1.72 | 0.086 | 0.1935 | 3.87 | no
1200377 | Nivel 5 | 2.25 | 0.15 | 0.0075 | 0.016875 | 0.3375 | no
1200378 | Nivel 5 | 2.25 | 1.72 | 0.086 | 0.1935 | 3.87 | no
1200379 | Nivel 5 | 2.25 | 0.15 | 0.0075 | 0.016875 | 0.3375 | no
1200380 | Nivel 5 | 2.25 | 1.285 | 0.06425 | 0.144562 | 2.89125 | no
1200382 | Nivel 5 | 2.25 | 1.285 | 0.06425 | 0.144562 | 2.89125 | no
1200387 | Nivel 6 | 2.25 | 1.72 | 0.086 | 0.1935 | 3.87 | no
1200388 | Nivel 6 | 2.25 | 0.15 | 0.0075 | 0.016875 | 0.3375 | no
1200389 | Nivel 6 | 2.25 | 1.72 | 0.086 | 0.1935 | 3.87 | no
1200390 | Nivel 6 | 2.25 | 0.15 | 0.0075 | 0.016875 | 0.3375 | no
1200391 | Nivel 6 | 2.25 | 1.285 | 0.06425 | 0.144562 | 2.89125 | no
1200393 | Nivel 6 | 2.25 | 1.285 | 0.06425 | 0.144562 | 2.89125 | no
1209527 | Nivel 7 | 0.7 | 0.2 | 0.01 | 0.007 | 0.14 | no

# IfcWall: Basic Wall:B2010 - 0.05m - Poyo para duchas - Concreto (24)
Type - PredefinedType: STANDARD
Type - Pset_WallCommon - IsExternal: yes
Classification: 21-03 20 10 10 Uniformat (Uniformat); Material: 0 muro divisorio
Qto_WallBaseQuantities - Height: 0.11 m; Length: 1.175 m; Width: 0.05 m; GrossFootprintArea: 0.0587499 m2; GrossVolume: 0.00646249 m3; GrossSideArea: 0.12925 m2; NetSideArea: 0.12925 m2; NetVolume: 0.00646249 m3
Pset_EnvironmentalImpactIndicators - Reference: B2010 - 0.05m - Poyo para duchas - Concreto; sets with these values: 2
Pset_WallCommon - LoadBearing: no; ExtendToStructure: no; Reference: B2010 - 0.05m - Poyo para duchas - Concreto
Name (Basic Wall:B2010 - 0.05m - Poyo para duchas - Concreto:...) | In
728631 | Nivel 1
749200 | Nivel 3
749366 | Nivel 3
749568 | Nivel 3
749742 | Nivel 3
750767 | Nivel 4
750933 | Nivel 4
751135 | Nivel 4
751309 | Nivel 4
752334 | Nivel 5
752500 | Nivel 5
752702 | Nivel 5
752876 | Nivel 5
753901 | Nivel 6
754067 | Nivel 6
754269 | Nivel 6
754443 | Nivel 6
781309 | Nivel 1
791881 | Nivel 2
792046 | Nivel 2
792244 | Nivel 2
792417 | Nivel 2
872714 | Nivel 1
872912 | Nivel 1

# IfcWall: Basic Wall:B2010 - 0.10m - MI Concreto- Concreto+ Pintura (12)
Type - PredefinedType: STANDARD; Material: Pintura blanca, Concreto (Aire)
Type - Pset_WallCommon - LoadBearing: yes; IsExternal: yes; ThermalTransmittance: 0.25 kg/K/s3
Classification: 21-03 10 10 10 Uniformat (Uniformat)
Qto_WallBaseQuantities - Pintura blanca, Width: 0.001 m; Concreto (Aire), Width: 0.1 m; Width: 0.101 m; Height: 2.25 m
Pset_EnvironmentalImpactIndicators - Reference: B2010 - 0.10m - MI Concreto- Concreto+ Pintura; sets with these values: 2
Pset_WallCommon - LoadBearing: no; ExtendToStructure: no; Reference: B2010 - 0.10m - MI Concreto- Concreto+ Pintura
Name (Basic Wall:B2010 - 0.10m - MI Concreto- Concreto+ Pintura:...) | In | Length (m) | GrossVolume (m3) = NetVolume (m3) | GrossSideArea (m2) = NetSideArea (m2)
1330995 | Nivel 2 | 1.745 | 0.396551 | 3.92625
1331411 | Nivel 2 | 1.745 | 0.396551 | 3.92625
1332203 | Nivel 3 | 1.745 | 0.396551 | 3.92625
1332215 | Nivel 4 | 1.745 | 0.396551 | 3.92625
1332227 | Nivel 5 | 1.745 | 0.396551 | 3.92625
1332239 | Nivel 6 | 1.745 | 0.396551 | 3.92625
1332452 | Nivel 3 | 1.745 | 0.396551 | 3.92625
1332479 | Nivel 4 | 1.745 | 0.396551 | 3.92625
1332506 | Nivel 5 | 1.745 | 0.396551 | 3.92625
1332552 | Nivel 6 | 1.745 | 0.396551 | 3.92625
1336081 | Nivel 1 | 1.9175 | 0.422685 | 4.185
1336605 | Nivel 1 | 1.9075 | 0.420413 | 4.1625

# IfcWall: Basic Wall:B2010 - 0.10m - MI Concreto- Concreto+Graniplast (4)
In: Nivel 7
Type - PredefinedType: STANDARD; Material: Graniplast, Concreto (Aire)
Type - Pset_WallCommon - IsExternal: yes; ThermalTransmittance: 0.25 kg/K/s3
Classification: 21-02 20 10 20 Uniformat (Uniformat)
Qto_WallBaseQuantities - Graniplast, Width: 0.001 m; Concreto (Aire), Width: 0.1 m; Width: 0.101 m
Pset_EnvironmentalImpactIndicators - Reference: B2010 - 0.10m - MI Concreto- Concreto+Graniplast; sets with these values: 2
Pset_WallCommon - ExtendToStructure: yes; Reference: B2010 - 0.10m - MI Concreto- Concreto+Graniplast
Name (Basic Wall:B2010 - 0.10m - MI Concreto- Concreto+Graniplast:...) | Height (m) | Length (m) | GrossVolume (m3) | GrossSideArea (m2) = NetSideArea (m2) | NetVolume (m3) | LoadBearing
757987 | 0.381275 | 3.975 | 0.148644 | 1.47172 | 0.145691 | yes
758166 | 0.38135 | 3.975 | 0.148673 | 1.47201 | 0.14572 | yes
882883 | 0.381275 | 2.0875 | 0.0771785 | 0.764144 | 0.0756522 | no
882884 | 0.381275 | 2.115 | 0.0770175 | 0.76255 | 0.0754874 | no

# IfcWall: Basic Wall:B2010 - 0.10m - MI Concreto- Concreto+repello+ pintura blanca (24)
Type - PredefinedType: STANDARD; Material: PINTURA BLANCA PARA EXTERIORES, Concreto (Aire)
Type - Pset_WallCommon - LoadBearing: yes; IsExternal: yes; ThermalTransmittance: 0.25 kg/K/s3; FireRating: 60
Classification: 21-02 20 10 20 Uniformat (Uniformat)
Qto_WallBaseQuantities - PINTURA BLANCA PARA EXTERIORES, Width: 0.001 m; Concreto (Aire), Width: 0.1 m; Width: 0.101 m; Height: 2.25 m
Pset_EnvironmentalImpactIndicators - Reference: B2010 - 0.10m - MI Concreto- Concreto+repello+ pintura blanca; sets with these values: 2
Pset_WallCommon - LoadBearing: no; ExtendToStructure: no; Reference: B2010 - 0.10m - MI Concreto- Concreto+repello+ pintura blanca
Name (Basic Wall:B2010 - 0.10m - MI Concreto- Concreto+repello+ pintura blanca:...) | In | Length (m) | GrossVolume (m3) | GrossSideArea (m2) | NetSideArea (m2) | NetVolume (m3)
1221018 | Nivel 1 | 1.1 | 0.249975 | 2.475 | 2.46922 | 0.249392
1223333 | Nivel 1 | 1.1 | 0.249975 | 2.475 | 2.46922 | 0.249392
1224992 | Nivel 1 | 2.655 | 0.603349 | 5.97375 | 5.96797 | 0.602765
1228554 | Nivel 1 | 2.7125 | 0.603349 | 5.97375 | 5.96797 | 0.602765
1328799 | Nivel 2 | 3.66 | 0.75043 | 7.43 | 7.39422 | 0.746817
1330994 | Nivel 2 | 3.66 | 0.75043 | 7.43 | 7.39422 | 0.746817
1331168 | Nivel 2 | 1.915 | 0.353879 | 3.50375 | 3.46797 | 0.350265
1331365 | Nivel 2 | 1.915 | 0.353879 | 3.50375 | 3.46797 | 0.350265
1332200 | Nivel 3 | 3.66 | 0.75043 | 7.43 | 7.39422 | 0.746817
1332202 | Nivel 3 | 1.915 | 0.353879 | 3.50375 | 3.46797 | 0.350265
1332212 | Nivel 4 | 3.66 | 0.75043 | 7.43 | 7.39422 | 0.746817
1332214 | Nivel 4 | 1.915 | 0.353879 | 3.50375 | 3.46797 | 0.350265
1332224 | Nivel 5 | 3.66 | 0.75043 | 7.43 | 7.39422 | 0.746817
1332226 | Nivel 5 | 1.915 | 0.353879 | 3.50375 | 3.46797 | 0.350265
1332236 | Nivel 6 | 3.66 | 0.75043 | 7.43 | 7.39422 | 0.746817
1332238 | Nivel 6 | 1.915 | 0.353879 | 3.50375 | 3.46797 | 0.350265
1332449 | Nivel 3 | 3.66 | 0.75043 | 7.43 | 7.39422 | 0.746817
1332451 | Nivel 3 | 1.915 | 0.353879 | 3.50375 | 3.46797 | 0.350265
1332476 | Nivel 4 | 3.66 | 0.75043 | 7.43 | 7.39422 | 0.746817
1332478 | Nivel 4 | 1.915 | 0.353879 | 3.50375 | 3.46797 | 0.350265
1332503 | Nivel 5 | 3.66 | 0.75043 | 7.43 | 7.39422 | 0.746817
1332505 | Nivel 5 | 1.915 | 0.353879 | 3.50375 | 3.46797 | 0.350265
1332549 | Nivel 6 | 3.66 | 0.75043 | 7.43 | 7.39422 | 0.746817
1332551 | Nivel 6 | 1.915 | 0.353879 | 3.50375 | 3.46797 | 0.350265

# IfcWall: Basic Wall:B2010 - 0.10m - MI no estructural- Concreto, Basic Wall:B2010 - 0.10m - MI no estructural- Concreto:766049
In: Nivel 7
Type - PredefinedType: STANDARD
Type - Pset_WallCommon - IsExternal: yes
Classification: 21-02 20 10 20 Uniformat (Uniformat); Material: Concreto - Fundido in situ
Qto_WallBaseQuantities - Height: 0.2812 m; Length: 2.315 m; Width: 0.1 m; GrossFootprintArea: 0.2315 m2; GrossVolume: 0.0650978 m3; GrossSideArea: 0.650978 m2; NetSideArea: 0.650978 m2; NetVolume: 0.0633615 m3
Pset_EnvironmentalImpactIndicators - Reference: B2010 - 0.10m - MI no estructural- Concreto; sets with these values: 2
Pset_WallCommon - LoadBearing: no; ExtendToStructure: yes; Reference: B2010 - 0.10m - MI no estructural- Concreto

# IfcWall: Basic Wall:B2010 - 0.10m - MI no estructural- Concreto + repello+ pintura blanca (24)
Type - PredefinedType: STANDARD; Material: PINTURA BLANCA PARA EXTERIORES, Concreto - Fundido in situ
Type - Pset_WallCommon - IsExternal: yes
Classification: 21-02 20 10 20 Uniformat (Uniformat)
Qto_WallBaseQuantities - PINTURA BLANCA PARA EXTERIORES, Width: 0.001 m; Concreto - Fundido in situ, Width: 0.1 m; Width: 0.101 m; Height: 2.25 m
Pset_EnvironmentalImpactIndicators - Reference: B2010 - 0.10m - MI no estructural- Concreto + repello+ pintura blanca; sets with these values: 2
Pset_WallCommon - LoadBearing: no; ExtendToStructure: no; Reference: B2010 - 0.10m - MI no estructural- Concreto + repello+ pintura blanca
Name (Basic Wall:B2010 - 0.10m - MI no estructural- Concreto + repello+ pintura blanca:...) | In | Length (m) | GrossVolume (m3) = NetVolume (m3) | GrossSideArea (m2) = NetSideArea (m2)
728549 | Nivel 1 | 0.9 | 0.063125 | 0.625
781244 | Nivel 1 | 0.9 | 0.063125 | 0.625
791815 | Nivel 2 | 0.2 | 0.04545 | 0.45
792180 | Nivel 2 | 0.2 | 0.04545 | 0.45
872650 | Nivel 1 | 0.9 | 0.063125 | 0.625
872848 | Nivel 1 | 0.9 | 0.063125 | 0.625
1330989 | Nivel 2 | 0.2 | 0.04545 | 0.45
1332030 | Nivel 2 | 0.2 | 0.04545 | 0.45
1332194 | Nivel 3 | 0.2 | 0.04545 | 0.45
1332197 | Nivel 3 | 0.2 | 0.04545 | 0.45
1332206 | Nivel 4 | 0.2 | 0.04545 | 0.45
1332209 | Nivel 4 | 0.2 | 0.04545 | 0.45
1332218 | Nivel 5 | 0.2 | 0.04545 | 0.45
1332221 | Nivel 5 | 0.2 | 0.04545 | 0.45
1332230 | Nivel 6 | 0.2 | 0.04545 | 0.45
1332233 | Nivel 6 | 0.2 | 0.04545 | 0.45
1332443 | Nivel 3 | 0.2 | 0.04545 | 0.45
1332446 | Nivel 3 | 0.2 | 0.04545 | 0.45
1332470 | Nivel 4 | 0.2 | 0.04545 | 0.45
1332473 | Nivel 4 | 0.2 | 0.04545 | 0.45
1332497 | Nivel 5 | 0.2 | 0.04545 | 0.45
1332500 | Nivel 5 | 0.2 | 0.04545 | 0.45
1332543 | Nivel 6 | 0.2 | 0.04545 | 0.45
1332546 | Nivel 6 | 0.2 | 0.04545 | 0.45

# IfcWall: Basic Wall:B2010 - 0.10m - Muro interior en concreto (31)
Type - PredefinedType: STANDARD
Type - Pset_WallCommon - IsExternal: yes; ThermalTransmittance: 0.25 kg/K/s3
Classification: 21-03 10 10 10 Uniformat (Uniformat); Material: Concreto (Aire)
Qto_WallBaseQuantities - Width: 0.1 m
Pset_EnvironmentalImpactIndicators - Reference: B2010 - 0.10m - Muro interior en concreto; sets with these values: 2
Pset_WallCommon - LoadBearing: no; Reference: B2010 - 0.10m - Muro interior en concreto
Name (Basic Wall:B2010 - 0.10m - Muro interior en concreto:...) | In | Height (m) | Length (m) | GrossFootprintArea (m2) | GrossVolume (m3) | GrossSideArea (m2) = NetSideArea (m2) | NetVolume (m3) | ExtendToStructure
728544 | Nivel 1 | 2.25 | 1.57 | 0.157 | 0.35325 | 3.5325 | 0.35325 | no
749128 | Nivel 3 | 2.25 | 1.57 | 0.157 | 0.35325 | 3.5325 | 0.35325 | no
749296 | Nivel 3 | 2.25 | 1.57 | 0.157 | 0.35325 | 3.5325 | 0.35325 | no
749498 | Nivel 3 | 2.25 | 1.57 | 0.157 | 0.35325 | 3.5325 | 0.35325 | no
749672 | Nivel 3 | 2.25 | 1.57 | 0.157 | 0.35325 | 3.5325 | 0.35325 | no
750695 | Nivel 4 | 2.25 | 1.57 | 0.157 | 0.35325 | 3.5325 | 0.35325 | no
750863 | Nivel 4 | 2.25 | 1.57 | 0.157 | 0.35325 | 3.5325 | 0.35325 | no
751065 | Nivel 4 | 2.25 | 1.57 | 0.157 | 0.35325 | 3.5325 | 0.35325 | no
751239 | Nivel 4 | 2.25 | 1.57 | 0.157 | 0.35325 | 3.5325 | 0.35325 | no
752262 | Nivel 5 | 2.25 | 1.57 | 0.157 | 0.35325 | 3.5325 | 0.35325 | no
752430 | Nivel 5 | 2.25 | 1.57 | 0.157 | 0.35325 | 3.5325 | 0.35325 | no
752632 | Nivel 5 | 2.25 | 1.57 | 0.157 | 0.35325 | 3.5325 | 0.35325 | no
752806 | Nivel 5 | 2.25 | 1.57 | 0.157 | 0.35325 | 3.5325 | 0.35325 | no
753829 | Nivel 6 | 2.25 | 1.57 | 0.157 | 0.35325 | 3.5325 | 0.35325 | no
753997 | Nivel 6 | 2.25 | 1.57 | 0.157 | 0.35325 | 3.5325 | 0.35325 | no
754199 | Nivel 6 | 2.25 | 1.57 | 0.157 | 0.35325 | 3.5325 | 0.35325 | no
754373 | Nivel 6 | 2.25 | 1.57 | 0.157 | 0.35325 | 3.5325 | 0.35325 | no
760154 | Nivel 7 | 0.74345 | 1.57 | 0.157 | 0.116722 | 1.16722 | 0.115544 | yes
764400 | Nivel 7 | 0.74345 | 1.57 | 0.157 | 0.116722 | 1.16722 | 0.115544 | yes
767776 | Nivel 7 | 0.74345 | 1.57 | 0.157 | 0.116722 | 1.16722 | 0.115544 | yes
767975 | Nivel 7 | 0.74345 | 1.57 | 0.157 | 0.116722 | 1.16722 | 0.115544 | yes
781239 | Nivel 1 | 2.25 | 1.57 | 0.157 | 0.35325 | 3.5325 | 0.35325 | no
791810 | Nivel 2 | 2.25 | 1.57 | 0.157 | 0.35325 | 3.5325 | 0.35325 | no
791977 | Nivel 2 | 2.25 | 1.57 | 0.157 | 0.35325 | 3.5325 | 0.35325 | no
792175 | Nivel 2 | 2.25 | 1.57 | 0.157 | 0.35325 | 3.5325 | 0.35325 | no
792348 | Nivel 2 | 2.25 | 1.57 | 0.157 | 0.35325 | 3.5325 | 0.35325 | no
872645 | Nivel 1 | 2.25 | 1.57 | 0.157 | 0.35325 | 3.5325 | 0.35325 | no
872843 | Nivel 1 | 2.25 | 1.57 | 0.157 | 0.35325 | 3.5325 | 0.35325 | no
1209565 | Nivel 7 | 0.2812 | 1.745 | 0.1745 | 0.0490694 | 0.490694 | 0.0477606 | yes
1335434 | Nivel 1 | 2.25 | 0.305 | 0.0305 | 0.068625 | 0.68625 | 0.068625 | no
1336770 | Nivel 1 | 2.25 | 0.305 | 0.0305 | 0.068625 | 0.68625 | 0.068625 | no

# IfcWall: Basic Wall:B2010 - 0.115m - ME mampostería no estructural - Ladrillo (115)
Type - PredefinedType: STANDARD
Type - Pset_WallCommon - IsExternal: yes; FireRating: 120; ThermalTransmittance: 6.26087 kg/K/s3
Classification: 21-02 20 10 20 Uniformat (Uniformat); Material: LADRILLO CLARO
Qto_WallBaseQuantities - Width: 0.115 m
Pset_EnvironmentalImpactIndicators - Reference: B2010 - 0.115m - ME mampostería no estructural - Ladrillo; sets with these values: 2
Pset_WallCommon - LoadBearing: no; Reference: B2010 - 0.115m - ME mampostería no estructural - Ladrillo
Name (Basic Wall:B2010 - 0.115m - ME mampostería no estructural - Ladrillo:...) | In | Height (m) | Length (m) | GrossFootprintArea (m2) | GrossVolume (m3) = NetVolume (m3) | GrossSideArea (m2) = NetSideArea (m2) | ExtendToStructure
728538 | Nivel 1 | 2.25 | 0.51 | 0.05865 | 0.131963 | 1.1475 | no
728542 | Nivel 1 | 2.25 | 3.2 | 0.368 | 0.400344 | 3.48125 | no
749122 | Nivel 3 | 2.25 | 0.51 | 0.05865 | 0.131962 | 1.1475 | no
749126 | Nivel 3 | 2.25 | 0.51 | 0.05865 | 0.131963 | 1.1475 | no
749290 | Nivel 3 | 2.25 | 0.51 | 0.05865 | 0.131962 | 1.1475 | no
749294 | Nivel 3 | 2.25 | 0.51 | 0.05865 | 0.131963 | 1.1475 | no
749492 | Nivel 3 | 2.25 | 0.51 | 0.05865 | 0.131962 | 1.1475 | no
749496 | Nivel 3 | 2.25 | 0.51 | 0.05865 | 0.131963 | 1.1475 | no
749666 | Nivel 3 | 2.25 | 0.51 | 0.05865 | 0.131962 | 1.1475 | no
749670 | Nivel 3 | 2.25 | 0.51 | 0.05865 | 0.131963 | 1.1475 | no
750689 | Nivel 4 | 2.25 | 0.51 | 0.05865 | 0.131962 | 1.1475 | no
750693 | Nivel 4 | 2.25 | 0.51 | 0.05865 | 0.131963 | 1.1475 | no
750857 | Nivel 4 | 2.25 | 0.51 | 0.05865 | 0.131962 | 1.1475 | no
750861 | Nivel 4 | 2.25 | 0.51 | 0.05865 | 0.131963 | 1.1475 | no
751059 | Nivel 4 | 2.25 | 0.51 | 0.05865 | 0.131962 | 1.1475 | no
751063 | Nivel 4 | 2.25 | 0.51 | 0.05865 | 0.131963 | 1.1475 | no
751233 | Nivel 4 | 2.25 | 0.51 | 0.05865 | 0.131962 | 1.1475 | no
751237 | Nivel 4 | 2.25 | 0.51 | 0.05865 | 0.131963 | 1.1475 | no
752256 | Nivel 5 | 2.25 | 0.51 | 0.05865 | 0.131962 | 1.1475 | no
752260 | Nivel 5 | 2.25 | 0.51 | 0.05865 | 0.131963 | 1.1475 | no
752424 | Nivel 5 | 2.25 | 0.51 | 0.05865 | 0.131962 | 1.1475 | no
752428 | Nivel 5 | 2.25 | 0.51 | 0.05865 | 0.131963 | 1.1475 | no
752626 | Nivel 5 | 2.25 | 0.51 | 0.05865 | 0.131962 | 1.1475 | no
752630 | Nivel 5 | 2.25 | 0.51 | 0.05865 | 0.131963 | 1.1475 | no
752800 | Nivel 5 | 2.25 | 0.51 | 0.05865 | 0.131962 | 1.1475 | no
752804 | Nivel 5 | 2.25 | 0.51 | 0.05865 | 0.131963 | 1.1475 | no
753823 | Nivel 6 | 2.25 | 0.51 | 0.05865 | 0.131962 | 1.1475 | no
753827 | Nivel 6 | 2.25 | 0.51 | 0.05865 | 0.131963 | 1.1475 | no
753991 | Nivel 6 | 2.25 | 0.51 | 0.05865 | 0.131962 | 1.1475 | no
753995 | Nivel 6 | 2.25 | 0.51 | 0.05865 | 0.131963 | 1.1475 | no
754193 | Nivel 6 | 2.25 | 0.51 | 0.05865 | 0.131962 | 1.1475 | no
754197 | Nivel 6 | 2.25 | 0.51 | 0.05865 | 0.131963 | 1.1475 | no
754367 | Nivel 6 | 2.25 | 0.51 | 0.05865 | 0.131962 | 1.1475 | no
754371 | Nivel 6 | 2.25 | 0.51 | 0.05865 | 0.131963 | 1.1475 | no
764962 | Nivel 7 | 0.8758 | 1.975 | 0.227125 | 0.198916 | 1.7297 | no
765166 | Nivel 7 | 0.8758 | 1.975 | 0.227125 | 0.198916 | 1.7297 | no
765230 | Nivel 7 | 1.2468 | 6.28 | 0.7222 | 0.900439 | 7.8299 | no
766682 | Nivel 7 | 0.8758 | 1.975 | 0.227125 | 0.198916 | 1.7297 | no
767984 | Nivel 7 | 0.4592 | 0.5195 | 0.0597425 | 0.025106 | 0.218313 | yes
781233 | Nivel 1 | 2.25 | 0.51 | 0.05865 | 0.131962 | 1.1475 | no
781237 | Nivel 1 | 2.25 | 0.505 | 0.058075 | 0.130669 | 1.13625 | no
781254 | Nivel 1 | 2.25 | 0.5195 | 0.0597425 | 0.134421 | 1.16888 | no
791804 | Nivel 2 | 2.25 | 0.51 | 0.05865 | 0.131962 | 1.1475 | no
791808 | Nivel 2 | 2.25 | 0.51 | 0.05865 | 0.131963 | 1.1475 | no
791971 | Nivel 2 | 2.25 | 0.51 | 0.05865 | 0.131962 | 1.1475 | no
791975 | Nivel 2 | 2.25 | 0.51 | 0.05865 | 0.131963 | 1.1475 | no
792169 | Nivel 2 | 2.25 | 0.51 | 0.05865 | 0.131962 | 1.1475 | no
792173 | Nivel 2 | 2.25 | 0.51 | 0.05865 | 0.131963 | 1.1475 | no
792342 | Nivel 2 | 2.25 | 0.51 | 0.05865 | 0.131962 | 1.1475 | no
792346 | Nivel 2 | 2.25 | 0.51 | 0.05865 | 0.131963 | 1.1475 | no
872639 | Nivel 1 | 2.25 | 0.51 | 0.05865 | 0.131962 | 1.1475 | no
872643 | Nivel 1 | 2.25 | 3.14 | 0.3611 | 0.384819 | 3.34625 | no
872837 | Nivel 1 | 2.25 | 0.51 | 0.05865 | 0.131962 | 1.1475 | no
872841 | Nivel 1 | 2.25 | 3.14 | 0.3611 | 0.384819 | 3.34625 | no
872857 | Nivel 1 | 2.25 | 0.5195 | 0.0597425 | 0.134421 | 1.16888 | no
1217255 | Nivel 1 | 2.25 | 1.0592 | 0.121808 | 0.274068 | 2.3832 | no
1220418 | Nivel 1 | 2.25 | 1.1742 | 0.135033 | 0.303824 | 2.64195 | no
1223022 | Nivel 1 | 2.25 | 1.1742 | 0.135033 | 0.303824 | 2.64195 | no
1223871 | Nivel 1 | 2.25 | 1.1742 | 0.135033 | 0.303824 | 2.64195 | no
1246953 | Nivel 2 | 2.25 | 0.505 | 0.058075 | 0.130669 | 1.13625 | no
1247970 | Nivel 3 | 2.25 | 0.505 | 0.058075 | 0.130669 | 1.13625 | no
1247974 | Nivel 3 | 2.25 | 0.505 | 0.058075 | 0.130669 | 1.13625 | no
1247978 | Nivel 3 | 2.25 | 0.505 | 0.058075 | 0.130669 | 1.13625 | no
1247982 | Nivel 3 | 2.25 | 0.505 | 0.058075 | 0.130669 | 1.13625 | no
1247986 | Nivel 4 | 2.25 | 0.505 | 0.058075 | 0.130669 | 1.13625 | no
1247990 | Nivel 4 | 2.25 | 0.505 | 0.058075 | 0.130669 | 1.13625 | no
1247994 | Nivel 4 | 2.25 | 0.505 | 0.058075 | 0.130669 | 1.13625 | no
1247998 | Nivel 4 | 2.25 | 0.505 | 0.058075 | 0.130669 | 1.13625 | no
1248002 | Nivel 5 | 2.25 | 0.505 | 0.058075 | 0.130669 | 1.13625 | no
1248006 | Nivel 5 | 2.25 | 0.505 | 0.058075 | 0.130669 | 1.13625 | no
1248010 | Nivel 5 | 2.25 | 0.505 | 0.058075 | 0.130669 | 1.13625 | no
1248014 | Nivel 5 | 2.25 | 0.505 | 0.058075 | 0.130669 | 1.13625 | no
1248018 | Nivel 6 | 2.25 | 0.505 | 0.058075 | 0.130669 | 1.13625 | no
1248022 | Nivel 6 | 2.25 | 0.505 | 0.058075 | 0.130669 | 1.13625 | no
1248026 | Nivel 6 | 2.25 | 0.505 | 0.058075 | 0.130669 | 1.13625 | no
1248030 | Nivel 6 | 2.25 | 0.505 | 0.058075 | 0.130669 | 1.13625 | no
1248034 | Nivel 2 | 2.25 | 0.505 | 0.058075 | 0.130669 | 1.13625 | no
1248038 | Nivel 2 | 2.25 | 0.505 | 0.058075 | 0.130669 | 1.13625 | no
1248042 | Nivel 2 | 2.25 | 0.505 | 0.058075 | 0.130669 | 1.13625 | no
1250584 | Nivel 3 | 2.25 | 1.1742 | 0.135033 | 0.303824 | 2.64195 | no
1250587 | Nivel 3 | 2.25 | 1.1742 | 0.135033 | 0.303824 | 2.64195 | no
1250590 | Nivel 3 | 2.25 | 1.1742 | 0.135033 | 0.303824 | 2.64195 | no
1250593 | Nivel 3 | 2.25 | 1.1742 | 0.135033 | 0.303824 | 2.64195 | no
1250620 | Nivel 5 | 2.25 | 1.1742 | 0.135033 | 0.303824 | 2.64195 | no
1250623 | Nivel 5 | 2.25 | 1.1742 | 0.135033 | 0.303824 | 2.64195 | no
1250626 | Nivel 5 | 2.25 | 1.1742 | 0.135033 | 0.303824 | 2.64195 | no
1250629 | Nivel 5 | 2.25 | 1.1742 | 0.135033 | 0.303824 | 2.64195 | no
1251704 | Nivel 2 | 2.25 | 1.1742 | 0.135033 | 0.303824 | 2.64195 | no
1251886 | Nivel 2 | 2.25 | 1.1742 | 0.135033 | 0.303824 | 2.64195 | no
1252053 | Nivel 2 | 2.25 | 1.1742 | 0.135033 | 0.303824 | 2.64195 | no
1252218 | Nivel 4 | 2.25 | 1.1742 | 0.135033 | 0.303824 | 2.64195 | no
1252219 | Nivel 4 | 2.25 | 1.1742 | 0.135033 | 0.303824 | 2.64195 | no
1252220 | Nivel 4 | 2.25 | 1.1742 | 0.135033 | 0.303824 | 2.64195 | no
1252925 | Nivel 6 | 2.25 | 1.1742 | 0.135033 | 0.303824 | 2.64195 | no
1253134 | Nivel 6 | 2.25 | 1.1742 | 0.135033 | 0.303824 | 2.64195 | no
1253334 | Nivel 6 | 2.25 | 1.1742 | 0.135033 | 0.303824 | 2.64195 | no
1253623 | Nivel 6 | 2.25 | 1.1742 | 0.135033 | 0.303824 | 2.64195 | no
1256220 | Nivel 4 | 2.25 | 1.1742 | 0.135033 | 0.303824 | 2.64195 | no
1256412 | Nivel 2 | 2.25 | 1.1742 | 0.135033 | 0.303824 | 2.64195 | no
1275109 | Nivel 7 | 1.2468 | 2.1942 | 0.252333 | 0.314609 | 2.73573 | no
1275110 | Nivel 7 | 1.2468 | 0.9 | 0.1035 | 0.129044 | 1.12212 | no
1276087 | Nivel 7 | 1.2468 | 2.1942 | 0.252333 | 0.314609 | 2.73573 | no
1276088 | Nivel 7 | 1.2468 | 0.9 | 0.1035 | 0.129044 | 1.12212 | no
1277775 | Nivel 7 | 1.2468 | 2.1942 | 0.252333 | 0.314609 | 2.73573 | no
1277776 | Nivel 7 | 1.2468 | 0.9 | 0.1035 | 0.129044 | 1.12212 | no
1277915 | Nivel 7 | 0.8758 | 1.86 | 0.2139 | 0.187334 | 1.62899 | no
1277917 | Nivel 7 | 1.2468 | 6.28 | 0.7222 | 0.900439 | 7.8299 | no
1277918 | Nivel 7 | 1.2468 | 2.1942 | 0.252333 | 0.314609 | 2.73573 | no
1277919 | Nivel 7 | 1.2468 | 0.9 | 0.1035 | 0.129044 | 1.12212 | no
1871617 | Nivel 7 | 0.4 | 0.935 | 0.107525 | 0.04301 | 0.374 | no
1871618 | Nivel 7 | 0.4 | 0.815 | 0.093725 | 0.03749 | 0.326 | no
1871619 | Nivel 7 | 0.4 | 0.82 | 0.0943 | 0.03772 | 0.328 | no
1871620 | Nivel 7 | 0.4 | 0.7 | 0.0805 | 0.0322 | 0.28 | no
1897958 | Nivel 1 | 2.4 | 0.265 | 0.030475 | 0.07314 | 0.636 | no
1898005 | Nivel 1 | 2.4 | 0.395 | 0.045425 | 0.10902 | 0.948 | no

# IfcWall: Basic Wall:B2010 - 0.115m - MI No estructural- Concreto (5)
In: Nivel 7
Type - PredefinedType: STANDARD
Type - Pset_WallCommon - IsExternal: yes
Classification: 21-02 20 10 20 Uniformat (Uniformat); Material: Concreto - Fundido in situ
Qto_WallBaseQuantities - Width: 0.115 m
Pset_EnvironmentalImpactIndicators - Reference: B2010 - 0.115m - MI No estructural- Concreto; sets with these values: 2
Pset_WallCommon - Reference: B2010 - 0.115m - MI No estructural- Concreto; ExtendToStructure: yes
Name (Basic Wall:B2010 - 0.115m - MI No estructural- Concreto:...) | Height (m) | Length (m) | GrossFootprintArea (m2) | GrossVolume (m3) | GrossSideArea (m2) = NetSideArea (m2) | NetVolume (m3) | LoadBearing
755920 | 0.1762 | 3.915 | 0.450225 | 0.0793296 | 0.689823 | 0.0754465 | yes
755921 | 0.1762 | 3.915 | 0.450225 | 0.0793296 | 0.689823 | 0.0754465 | yes
756684 | 0.2812 | 2.63 | 0.30245 | 0.0850489 | 0.739556 | 0.0824403 | no
757308 | 0.1762 | 3.915 | 0.450225 | 0.0793296 | 0.689823 | 0.0754465 | yes
757312 | 0.1762 | 3.915 | 0.450225 | 0.0793296 | 0.689823 | 0.0754465 | yes

# IfcWall: Basic Wall:B2010 - 0.115m - MI mampostería no estructural - Ladrillo (80)
Type - PredefinedType: STANDARD
Type - Pset_WallCommon - IsExternal: yes; ThermalTransmittance: 6.26087 kg/K/s3
Classification: 21-02 20 10 20 Uniformat (Uniformat); Material: LADRILLO CLARO
Qto_WallBaseQuantities - Width: 0.115 m
Pset_EnvironmentalImpactIndicators - Reference: B2010 - 0.115m - MI mampostería no estructural - Ladrillo; sets with these values: 2
Pset_WallCommon - LoadBearing: no; Reference: B2010 - 0.115m - MI mampostería no estructural - Ladrillo
Name (Basic Wall:B2010 - 0.115m - MI mampostería no estructural - Ladrillo:...) | In | Height (m) | Length (m) | GrossFootprintArea (m2) | GrossVolume (m3) | GrossSideArea (m2) = NetSideArea (m2) | NetVolume (m3) | ExtendToStructure
728551 | Nivel 1 | 2.25 | 1.2 | 0.138 | 0.0529 | 0.46 | 0.0529 | no
728560 | Nivel 1 | 2.25 | 0.5195 | 0.0597425 | 0.134421 | 1.16888 | 0.134421 | no
749135 | Nivel 3 | 2.25 | 1.2 | 0.138 | 0.0529 | 0.46 | 0.0529 | no
749143 | Nivel 3 | 2.25 | 0.5195 | 0.0597425 | 0.134421 | 1.16888 | 0.134421 | no
749303 | Nivel 3 | 2.25 | 1.2 | 0.138 | 0.0529 | 0.46 | 0.0529 | no
749311 | Nivel 3 | 2.25 | 0.5195 | 0.0597425 | 0.134421 | 1.16888 | 0.134421 | no
749473 | Nivel 3 | 0.975 | 1.76 | 0.2024 | 0.19734 | 1.716 | 0.19734 | no
749505 | Nivel 3 | 2.25 | 1.2 | 0.138 | 0.0529 | 0.46 | 0.0529 | no
749513 | Nivel 3 | 2.25 | 0.5195 | 0.0597425 | 0.134421 | 1.16888 | 0.134421 | no
749679 | Nivel 3 | 2.25 | 1.2 | 0.138 | 0.0529 | 0.46 | 0.0529 | no
749687 | Nivel 3 | 2.25 | 0.5195 | 0.0597425 | 0.134421 | 1.16888 | 0.134421 | no
750702 | Nivel 4 | 2.25 | 1.2 | 0.138 | 0.0529 | 0.46 | 0.0529 | no
750710 | Nivel 4 | 2.25 | 0.5195 | 0.0597425 | 0.134421 | 1.16888 | 0.134421 | no
750870 | Nivel 4 | 2.25 | 1.2 | 0.138 | 0.0529 | 0.46 | 0.0529 | no
750878 | Nivel 4 | 2.25 | 0.5195 | 0.0597425 | 0.134421 | 1.16888 | 0.134421 | no
751040 | Nivel 4 | 0.975 | 1.76 | 0.2024 | 0.19734 | 1.716 | 0.19734 | no
751072 | Nivel 4 | 2.25 | 1.2 | 0.138 | 0.0529 | 0.46 | 0.0529 | no
751080 | Nivel 4 | 2.25 | 0.5195 | 0.0597425 | 0.134421 | 1.16888 | 0.134421 | no
751246 | Nivel 4 | 2.25 | 1.2 | 0.138 | 0.0529 | 0.46 | 0.0529 | no
751254 | Nivel 4 | 2.25 | 0.5195 | 0.0597425 | 0.134421 | 1.16888 | 0.134421 | no
752269 | Nivel 5 | 2.25 | 1.2 | 0.138 | 0.0529 | 0.46 | 0.0529 | no
752277 | Nivel 5 | 2.25 | 0.5195 | 0.0597425 | 0.134421 | 1.16888 | 0.134421 | no
752437 | Nivel 5 | 2.25 | 1.2 | 0.138 | 0.0529 | 0.46 | 0.0529 | no
752445 | Nivel 5 | 2.25 | 0.5195 | 0.0597425 | 0.134421 | 1.16888 | 0.134421 | no
752607 | Nivel 5 | 0.975 | 1.76 | 0.2024 | 0.19734 | 1.716 | 0.19734 | no
752639 | Nivel 5 | 2.25 | 1.2 | 0.138 | 0.0529 | 0.46 | 0.0529 | no
752647 | Nivel 5 | 2.25 | 0.5195 | 0.0597425 | 0.134421 | 1.16888 | 0.134421 | no
752813 | Nivel 5 | 2.25 | 1.2 | 0.138 | 0.0529 | 0.46 | 0.0529 | no
752821 | Nivel 5 | 2.25 | 0.5195 | 0.0597425 | 0.134421 | 1.16888 | 0.134421 | no
753836 | Nivel 6 | 2.25 | 1.2 | 0.138 | 0.0529 | 0.46 | 0.0529 | no
753844 | Nivel 6 | 2.25 | 0.5195 | 0.0597425 | 0.134421 | 1.16888 | 0.134421 | no
754004 | Nivel 6 | 2.25 | 1.2 | 0.138 | 0.0529 | 0.46 | 0.0529 | no
754012 | Nivel 6 | 2.25 | 0.5195 | 0.0597425 | 0.134421 | 1.16888 | 0.134421 | no
754174 | Nivel 6 | 0.975 | 1.76 | 0.2024 | 0.19734 | 1.716 | 0.19734 | no
754206 | Nivel 6 | 2.25 | 1.2 | 0.138 | 0.0529 | 0.46 | 0.0529 | no
754214 | Nivel 6 | 2.25 | 0.5195 | 0.0597425 | 0.134421 | 1.16888 | 0.134421 | no
754380 | Nivel 6 | 2.25 | 1.2 | 0.138 | 0.0529 | 0.46 | 0.0529 | no
754388 | Nivel 6 | 2.25 | 0.5195 | 0.0597425 | 0.134421 | 1.16888 | 0.134421 | no
756414 | Nivel 7 |  | 2.551 |  |  |  | 0.119662 | no
757045 | Nivel 7 | 0.4 | 2.6015 | 0.299173 | 0.119669 | 1.0406 | 0.119669 | no
757310 | Nivel 7 |  | 2.5 |  |  |  | 0.117591 | no
760504 | Nivel 7 | 0.59345 | 1.32 | 0.1518 | 0.0900857 | 0.783354 | 0.0887764 | yes
761733 | Nivel 7 |  | 1.3575 |  |  |  | 0.0712348 | yes
761961 | Nivel 7 | 0.4592 | 0.5195 | 0.0597425 | 0.025106 | 0.218313 | 0.025106 | yes
764403 | Nivel 7 | 0.59345 | 1.2 | 0.138 | 0.0818961 | 0.71214 | 0.0807058 | yes
764408 | Nivel 7 |  | 1.3575 |  |  |  | 0.0712348 | yes
764409 | Nivel 7 | 0.4592 | 0.5195 | 0.0597425 | 0.025106 | 0.218313 | 0.025106 | yes
767779 | Nivel 7 | 0.59345 | 1.32 | 0.1518 | 0.0900857 | 0.783354 | 0.0887764 | yes
767784 | Nivel 7 |  | 1.3575 |  |  |  | 0.0712348 | yes
767785 | Nivel 7 | 0.4592 | 0.519 | 0.059685 | 0.0250841 | 0.218123 | 0.0250841 | yes
767978 | Nivel 7 | 0.8 | 0.2 | 0.023 | 0.0184 | 0.16 | 0.0184 | no
782583 | Nivel 1 | 2.25 | 1.01 | 0.11615 | 0.261338 | 2.2725 | 0.261338 | no
791816 | Nivel 2 | 2.25 | 0.32 | 0.0368 | 0.0828 | 0.72 | 0.0828 | no
791817 | Nivel 2 | 2.25 | 1.2 | 0.138 | 0.0529 | 0.46 | 0.0529 | no
791824 | Nivel 2 | 2.25 | 0.5195 | 0.0597425 | 0.134421 | 1.16888 | 0.134421 | no
791983 | Nivel 2 | 2.25 | 0.32 | 0.0368 | 0.0828 | 0.72 | 0.0828 | no
791984 | Nivel 2 | 2.25 | 1.2 | 0.138 | 0.0529 | 0.46 | 0.0529 | no
791991 | Nivel 2 | 2.25 | 0.5195 | 0.0597425 | 0.134421 | 1.16888 | 0.134421 | no
792152 | Nivel 2 | 0.975 | 1.76 | 0.2024 | 0.19734 | 1.716 | 0.19734 | no
792182 | Nivel 2 | 2.25 | 1.2 | 0.138 | 0.0529 | 0.46 | 0.0529 | no
792189 | Nivel 2 | 2.25 | 0.5195 | 0.0597425 | 0.134421 | 1.16888 | 0.134421 | no
792355 | Nivel 2 | 2.25 | 1.2 | 0.138 | 0.0529 | 0.46 | 0.0529 | no
792362 | Nivel 2 | 2.25 | 0.5195 | 0.0597425 | 0.134421 | 1.16888 | 0.134421 | no
859794 | Nivel 1 | 2.25 | 2.401 | 0.276115 | 0.621259 | 5.40225 | 0.621259 | no
868993 | Nivel 1 | 2.03 | 3.505 | 0.403075 | 0.818242 | 7.11515 | 0.818242 | no
872076 | Nivel 1 | 2.03 | 1.96 | 0.2254 | 0.457562 | 3.9788 | 0.457562 | no
872652 | Nivel 1 | 2.25 | 1.2 | 0.138 | 0.0529 | 0.46 | 0.0529 | no
872659 | Nivel 1 | 2.25 | 0.52 | 0.0598 | 0.13455 | 1.17 | 0.13455 | no
872850 | Nivel 1 | 2.25 | 1.2 | 0.138 | 0.0529 | 0.46 | 0.0529 | no
1188219 | Nivel 2 | 0.22 | 2.399 | 0.275885 | 0.0606947 | 0.52778 | 0.0606947 | no
1205276 | Nivel 3 | 2.25 | 0.32 | 0.0368 | 0.0828 | 0.72 | 0.0828 | no
1205277 | Nivel 3 | 2.25 | 0.32 | 0.0368 | 0.0828 | 0.72 | 0.0828 | no
1205282 | Nivel 4 | 2.25 | 0.32 | 0.0368 | 0.0828 | 0.72 | 0.0828 | no
1205283 | Nivel 4 | 2.25 | 0.32 | 0.0368 | 0.0828 | 0.72 | 0.0828 | no
1205288 | Nivel 5 | 2.25 | 0.32 | 0.0368 | 0.0828 | 0.72 | 0.0828 | no
1205289 | Nivel 5 | 2.25 | 0.32 | 0.0368 | 0.0828 | 0.72 | 0.0828 | no
1205294 | Nivel 6 | 2.25 | 0.32 | 0.0368 | 0.0828 | 0.72 | 0.0828 | no
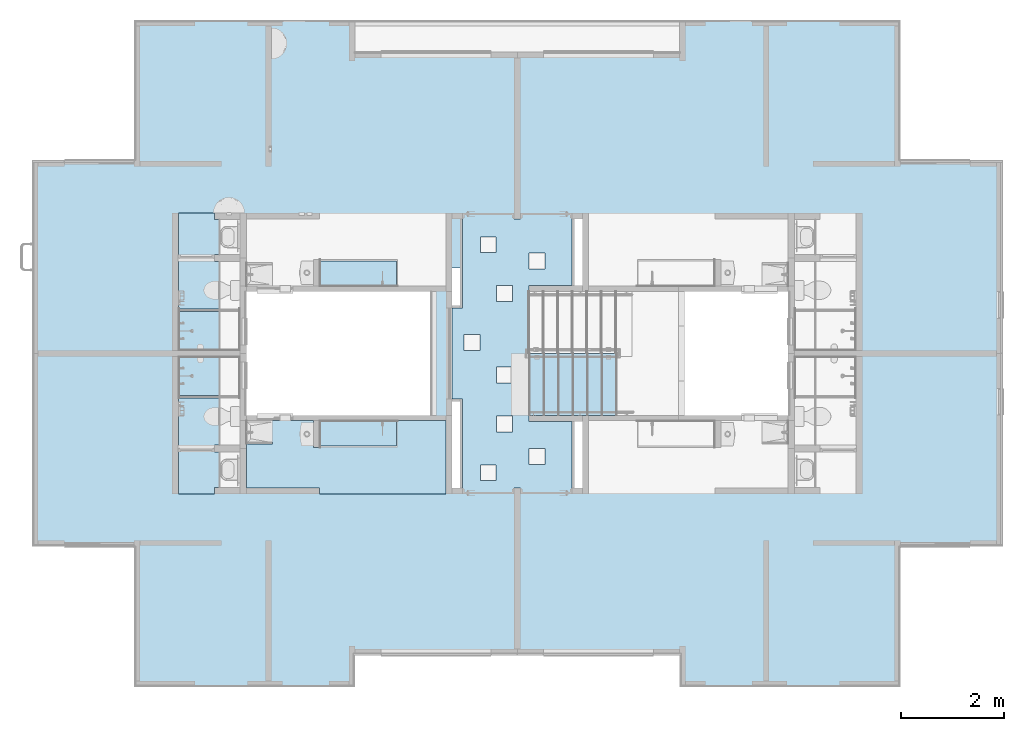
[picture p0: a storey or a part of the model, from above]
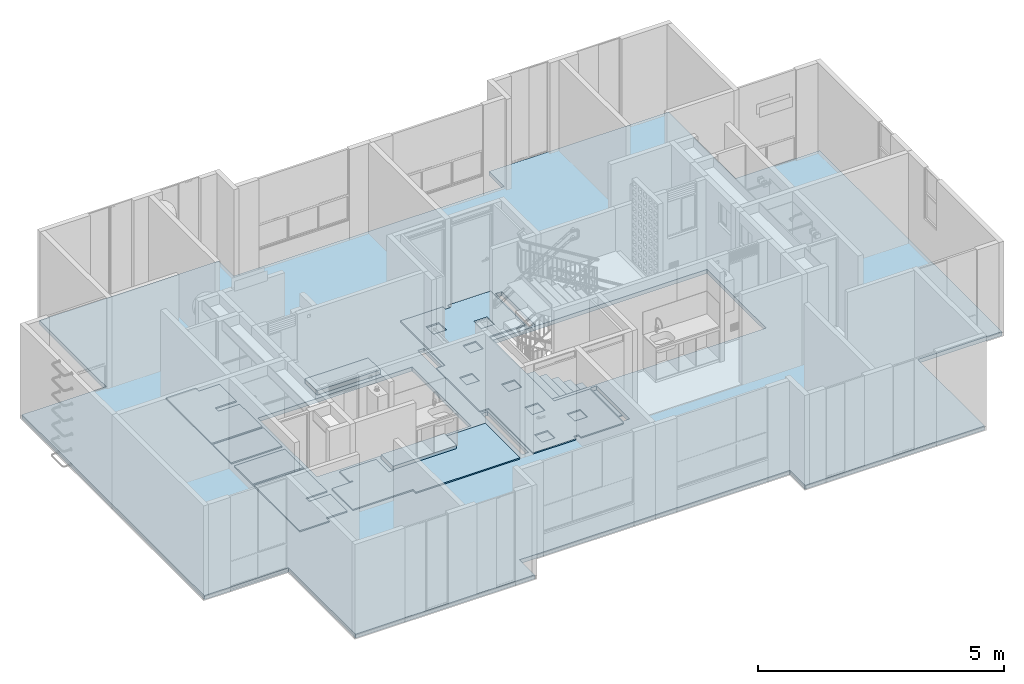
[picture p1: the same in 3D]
Properties of the parts of a building model (IFC4), part 5 of 6

# IfcWall: Basic Wall:B2010 - 0.115m - MI mampostería no estructural - Ladrillo (80)
Name (Basic Wall:B2010 - 0.115m - MI mampostería no estructural - Ladrillo:...) | In | Height (m) | Length (m) | GrossFootprintArea (m2) | GrossVolume (m3) | GrossSideArea (m2) = NetSideArea (m2) | NetVolume (m3) | ExtendToStructure
1205295 | Nivel 6 | 2.25 | 0.32 | 0.0368 | 0.0828 | 0.72 | 0.0828 | no
1209121 | Nivel 7 | 0.59345 | 1.01 | 0.11615 | 0.0689292 | 0.599384 | 0.0679274 | yes
1218486 | Nivel 1 | 2.4 | 2.73 | 0.31395 | 0.716996 | 6.23475 | 0.716996 | no

# IfcWall: Basic Wall:B2010 - 0.115m - MI mampostería no estructural - Ladrillo + Pañete (24)
Type - PredefinedType: STANDARD; Material: Pañete, LADRILLO CLARO
Type - Pset_WallCommon - IsExternal: yes; ThermalTransmittance: 4.81767 kg/K/s3
Classification: 21-02 20 10 20 Uniformat (Uniformat)
Qto_WallBaseQuantities - Pañete, Width: 0.01 m; LADRILLO CLARO, Width: 0.115 m; Width: 0.125 m; Height: 2.25 m
Pset_EnvironmentalImpactIndicators - Reference: B2010 - 0.115m - MI mampostería no estructural - Ladrillo + Pañete; sets with these values: 2
Pset_WallCommon - LoadBearing: no; ExtendToStructure: no; Reference: B2010 - 0.115m - MI mampostería no estructural - Ladrillo + Pañete
Name (Basic Wall:B2010 - 0.115m - MI mampostería no estructural - Ladrillo + Pañete:...) | In | Length (m) | GrossVolume (m3) = NetVolume (m3) | GrossSideArea (m2) = NetSideArea (m2)
1221949 | Nivel 1 | 0.16703 | 0.0469772 | 0.375818
1222097 | Nivel 1 | 0.167188 | 0.0470215 | 0.376172
1228330 | Nivel 1 | 0.167187 | 0.0470215 | 0.376172
1229160 | Nivel 1 | 0.167187 | 0.0470215 | 0.376172
1240592 | Nivel 2 | 0.167188 | 0.0470215 | 0.376172
1243517 | Nivel 3 | 0.167188 | 0.0470215 | 0.376172
1243523 | Nivel 3 | 0.167188 | 0.0470215 | 0.376172
1243529 | Nivel 3 | 0.167188 | 0.0470215 | 0.376172
1243535 | Nivel 3 | 0.167188 | 0.0470215 | 0.376172
1243541 | Nivel 4 | 0.167188 | 0.0470215 | 0.376172
1243547 | Nivel 4 | 0.167188 | 0.0470215 | 0.376172
1243553 | Nivel 4 | 0.167188 | 0.0470215 | 0.376172
1243559 | Nivel 4 | 0.167188 | 0.0470215 | 0.376172
1243565 | Nivel 5 | 0.167188 | 0.0470215 | 0.376172
1243571 | Nivel 5 | 0.167188 | 0.0470215 | 0.376172
1243577 | Nivel 5 | 0.167188 | 0.0470215 | 0.376172
1243583 | Nivel 5 | 0.167188 | 0.0470215 | 0.376172
1243589 | Nivel 6 | 0.167188 | 0.0470215 | 0.376172
1243595 | Nivel 6 | 0.167188 | 0.0470215 | 0.376172
1243601 | Nivel 6 | 0.167188 | 0.0470215 | 0.376172
1243607 | Nivel 6 | 0.167188 | 0.0470215 | 0.376172
1243614 | Nivel 2 | 0.167188 | 0.0470215 | 0.376172
1243620 | Nivel 2 | 0.167188 | 0.0470215 | 0.376172
1243626 | Nivel 2 | 0.167188 | 0.0470215 | 0.376172

# IfcWall: Basic Wall:B2010 - 0.115m - MI mampostería no estructural - Ladrillo 2 (12)
Type - PredefinedType: STANDARD
Type - Pset_WallCommon - IsExternal: yes; ThermalTransmittance: 6.26087 kg/K/s3
Classification: 21-03 10 10 10 Uniformat (Uniformat); Material: LADRILLO CLARO
Qto_WallBaseQuantities - Length: 1.03 m; Width: 0.115 m; GrossFootprintArea: 0.11845 m2
Pset_EnvironmentalImpactIndicators - Reference: B2010 - 0.115m - MI mampostería no estructural - Ladrillo 2; sets with these values: 2
Pset_WallCommon - LoadBearing: no; ExtendToStructure: no; Reference: B2010 - 0.115m - MI mampostería no estructural - Ladrillo 2
Name (Basic Wall:B2010 - 0.115m - MI mampostería no estructural - Ladrillo 2:...) | In | Height (m) | GrossVolume (m3) = NetVolume (m3) | GrossSideArea (m2) = NetSideArea (m2)
1821624 | Nivel 2 | 2.25 | 0.266512 | 2.3175
1821625 | Nivel 2 | 2.25 | 0.266512 | 2.3175
1821787 | Nivel 3 | 2.25 | 0.266512 | 2.3175
1821788 | Nivel 3 | 2.25 | 0.266512 | 2.3175
1821792 | Nivel 4 | 2.25 | 0.266512 | 2.3175
1821793 | Nivel 4 | 2.25 | 0.266512 | 2.3175
1821797 | Nivel 5 | 2.25 | 0.266512 | 2.3175
1821798 | Nivel 5 | 2.25 | 0.266512 | 2.3175
1821802 | Nivel 6 | 2.25 | 0.266512 | 2.3175
1821803 | Nivel 6 | 2.25 | 0.266512 | 2.3175
1822748 | Nivel 1 | 2.35 | 0.278357 | 2.4205
1822749 | Nivel 1 | 2.35 | 0.278357 | 2.4205

# IfcWall: Basic Wall:B2010 - 0.115m - MI mampostería no estructural - Pañete + Ladrillo + Pañete (27)
Type - PredefinedType: STANDARD; Material: Pañete (2), LADRILLO CLARO
Type - Pset_WallCommon - IsExternal: yes; ThermalTransmittance: 3.91518 kg/K/s3
Classification: 21-03 10 10 10 Uniformat (Uniformat)
Qto_WallBaseQuantities - Pañete, Width: 0.01 m; LADRILLO CLARO, Width: 0.115 m; Pañete (2), Width: 0.01 m; Width: 0.135 m
Pset_EnvironmentalImpactIndicators - Reference: B2010 - 0.115m - MI mampostería no estructural - Pañete + Ladrillo + Pañete; sets with these values: 2
Pset_WallCommon - LoadBearing: no; Reference: B2010 - 0.115m - MI mampostería no estructural - Pañete + Ladrillo + Pañete
Name (Basic Wall:B2010 - 0.115m - MI mampostería no estructural - Pañete + Ladrillo + Pañete:...) | In | Height (m) | Length (m) | GrossVolume (m3) | GrossSideArea (m2) = NetSideArea (m2) | NetVolume (m3) | ExtendToStructure
728548 | Nivel 1 | 2.25 | 0.557499 | 0.150356 | 1.11375 | 0.150356 | no
749212 | Nivel 3 | 2.25 | 1.31 | 0.15315 | 1.13445 | 0.15315 | no
749378 | Nivel 3 | 2.25 | 1.31 | 0.15315 | 1.13445 | 0.15315 | no
749580 | Nivel 3 | 2.25 | 1.31 | 0.15315 | 1.13445 | 0.15315 | no
749754 | Nivel 3 | 2.25 | 1.31 | 0.15315 | 1.13445 | 0.15315 | no
750779 | Nivel 4 | 2.25 | 1.31 | 0.15315 | 1.13445 | 0.15315 | no
750945 | Nivel 4 | 2.25 | 1.31 | 0.15315 | 1.13445 | 0.15315 | no
751147 | Nivel 4 | 2.25 | 1.31 | 0.15315 | 1.13445 | 0.15315 | no
751321 | Nivel 4 | 2.25 | 1.31 | 0.15315 | 1.13445 | 0.15315 | no
752346 | Nivel 5 | 2.25 | 1.31 | 0.15315 | 1.13445 | 0.15315 | no
752512 | Nivel 5 | 2.25 | 1.31 | 0.15315 | 1.13445 | 0.15315 | no
752714 | Nivel 5 | 2.25 | 1.31 | 0.15315 | 1.13445 | 0.15315 | no
752888 | Nivel 5 | 2.25 | 1.31 | 0.15315 | 1.13445 | 0.15315 | no
753913 | Nivel 6 | 2.25 | 1.31 | 0.15315 | 1.13445 | 0.15315 | no
754079 | Nivel 6 | 2.25 | 1.31 | 0.15315 | 1.13445 | 0.15315 | no
754281 | Nivel 6 | 2.25 | 1.31 | 0.15315 | 1.13445 | 0.15315 | no
754455 | Nivel 6 | 2.25 | 1.31 | 0.15315 | 1.13445 | 0.15315 | no
760832 | Nivel 7 | 0.4727 | 1.315 | 0.0762583 | 0.564876 | 0.0746248 | yes
764406 | Nivel 7 | 0.4727 | 1.315 | 0.0762583 | 0.564876 | 0.0746248 | yes
767782 | Nivel 7 | 0.4727 | 1.315 | 0.0762583 | 0.564876 | 0.0746248 | yes
781243 | Nivel 1 | 2.25 | 1.31 | 0.150153 | 1.11225 | 0.150153 | no
791893 | Nivel 2 | 2.25 | 1.31 | 0.15315 | 1.13445 | 0.15315 | no
792058 | Nivel 2 | 2.25 | 1.31 | 0.15315 | 1.13445 | 0.15315 | no
792256 | Nivel 2 | 2.25 | 1.31 | 0.15315 | 1.13445 | 0.15315 | no
792429 | Nivel 2 | 2.25 | 1.31 | 0.15315 | 1.13445 | 0.15315 | no
872649 | Nivel 1 | 2.25 | 0.557499 | 0.150356 | 1.11375 | 0.150356 | no
872847 | Nivel 1 | 2.25 | 0.557499 | 0.150356 | 1.11375 | 0.150356 | no

# IfcWall: Basic Wall:B2010 - 0.115m - Muro exterior en mampostería - Ladrillo (140)
Type - PredefinedType: STANDARD
Type - Pset_WallCommon - IsExternal: yes; ThermalTransmittance: 0.217391 kg/K/s3
Classification: 21-02 20 10 20 Uniformat (Uniformat); Material: Ladrillo claro (Aire)
Qto_WallBaseQuantities - Width: 0.115 m
Pset_EnvironmentalImpactIndicators - Reference: B2010 - 0.115m - Muro exterior en mampostería - Ladrillo; sets with these values: 2
Pset_WallCommon - LoadBearing: no; ExtendToStructure: no; Reference: B2010 - 0.115m - Muro exterior en mampostería - Ladrillo
Name (Basic Wall:B2010 - 0.115m - Muro exterior en mampostería - Ladrillo:...) | In | Height (m) | Length (m) | GrossFootprintArea (m2) | GrossVolume (m3) | GrossSideArea (m2) = NetSideArea (m2) | NetVolume (m3)
728537 | Nivel 1 | 2.25 | 3.72976 | 0.428923 | 0.965076 | 8.39197 | 0.965076
728539 | Nivel 1 | 2.25 | 2.6 | 0.299 | 0.67275 | 5.85 | 0.67275
728540 | Nivel 1 | 2.25 | 2.0708 | 0.238142 | 0.302944 | 2.6343 | 0.302944
728541 | Nivel 1 | 2.25 | 0.674918 | 0.0776156 | 0.174635 | 1.51857 | 0.174635
749121 | Nivel 3 | 2.25 | 3.73 | 0.42895 | 0.965137 | 8.3925 | 0.965137
749123 | Nivel 3 | 2.25 | 2.715 | 0.312225 | 0.702506 | 6.10875 | 0.702506
749124 | Nivel 3 | 2.25 | 2.0708 | 0.238142 | 0.302944 | 2.6343 | 0.302944
749125 | Nivel 3 | 2.25 | 0.674918 | 0.0776156 | 0.174635 | 1.51857 | 0.174635
749289 | Nivel 3 | 2.25 | 3.73 | 0.42895 | 0.965137 | 8.3925 | 0.965137
749291 | Nivel 3 | 2.25 | 2.715 | 0.312225 | 0.702506 | 6.10875 | 0.702506
749292 | Nivel 3 | 2.25 | 2.0708 | 0.238142 | 0.302944 | 2.6343 | 0.302944
749293 | Nivel 3 | 2.25 | 0.674918 | 0.0776156 | 0.174635 | 1.51857 | 0.174635
749491 | Nivel 3 | 2.25 | 3.73 | 0.42895 | 0.890387 | 7.7425 | 0.890387
749493 | Nivel 3 | 2.25 | 2.715 | 0.312225 | 0.702506 | 6.10875 | 0.702506
749494 | Nivel 3 | 2.25 | 2.0708 | 0.238142 | 0.302944 | 2.6343 | 0.302944
749495 | Nivel 3 | 2.25 | 0.674918 | 0.0776156 | 0.174635 | 1.51857 | 0.174635
749665 | Nivel 3 | 2.25 | 3.73 | 0.42895 | 0.890387 | 7.7425 | 0.890387
749667 | Nivel 3 | 2.25 | 2.715 | 0.312225 | 0.702506 | 6.10875 | 0.702506
749668 | Nivel 3 | 2.25 | 2.0708 | 0.238142 | 0.302944 | 2.6343 | 0.302944
749669 | Nivel 3 | 2.25 | 0.674918 | 0.0776156 | 0.174635 | 1.51857 | 0.174635
750688 | Nivel 4 | 2.25 | 3.73 | 0.42895 | 0.965137 | 8.3925 | 0.965137
750690 | Nivel 4 | 2.25 | 2.715 | 0.312225 | 0.702506 | 6.10875 | 0.702506
750692 | Nivel 4 | 2.25 | 0.789918 | 0.0908406 | 0.204391 | 1.77732 | 0.204391
750856 | Nivel 4 | 2.25 | 3.73 | 0.42895 | 0.965137 | 8.3925 | 0.965137
750858 | Nivel 4 | 2.25 | 2.715 | 0.312225 | 0.702506 | 6.10875 | 0.702506
750860 | Nivel 4 | 2.25 | 0.789918 | 0.0908406 | 0.204391 | 1.77732 | 0.204391
751058 | Nivel 4 | 2.25 | 3.73 | 0.42895 | 0.890387 | 7.7425 | 0.890387
751060 | Nivel 4 | 2.25 | 2.715 | 0.312225 | 0.702506 | 6.10875 | 0.702506
751062 | Nivel 4 | 2.25 | 0.789918 | 0.0908406 | 0.204391 | 1.77732 | 0.204391
751232 | Nivel 4 | 2.25 | 3.73 | 0.42895 | 0.890387 | 7.7425 | 0.890387
751234 | Nivel 4 | 2.25 | 2.715 | 0.312225 | 0.702506 | 6.10875 | 0.702506
751236 | Nivel 4 | 2.25 | 0.789918 | 0.0908406 | 0.204391 | 1.77732 | 0.204391
752255 | Nivel 5 | 2.25 | 3.73 | 0.42895 | 0.965137 | 8.3925 | 0.965137
752257 | Nivel 5 | 2.25 | 2.715 | 0.312225 | 0.702506 | 6.10875 | 0.702506
752258 | Nivel 5 | 2.25 | 2.0708 | 0.238142 | 0.302944 | 2.6343 | 0.302944
752259 | Nivel 5 | 2.25 | 0.674918 | 0.0776156 | 0.174635 | 1.51857 | 0.174635
752423 | Nivel 5 | 2.25 | 3.73 | 0.42895 | 0.965137 | 8.3925 | 0.965137
752425 | Nivel 5 | 2.25 | 2.715 | 0.312225 | 0.702506 | 6.10875 | 0.702506
752426 | Nivel 5 | 2.25 | 2.0708 | 0.238142 | 0.302944 | 2.6343 | 0.302944
752427 | Nivel 5 | 2.25 | 0.674918 | 0.0776156 | 0.174635 | 1.51857 | 0.174635
752625 | Nivel 5 | 2.25 | 3.73 | 0.42895 | 0.890387 | 7.7425 | 0.890387
752627 | Nivel 5 | 2.25 | 2.715 | 0.312225 | 0.702506 | 6.10875 | 0.702506
752628 | Nivel 5 | 2.25 | 2.0708 | 0.238142 | 0.302944 | 2.6343 | 0.302944
752629 | Nivel 5 | 2.25 | 0.674918 | 0.0776156 | 0.174635 | 1.51857 | 0.174635
752799 | Nivel 5 | 2.25 | 3.73 | 0.42895 | 0.890387 | 7.7425 | 0.890387
752801 | Nivel 5 | 2.25 | 2.715 | 0.312225 | 0.702506 | 6.10875 | 0.702506
752802 | Nivel 5 | 2.25 | 2.0708 | 0.238142 | 0.302944 | 2.6343 | 0.302944
752803 | Nivel 5 | 2.25 | 0.674918 | 0.0776156 | 0.174635 | 1.51857 | 0.174635
753822 | Nivel 6 | 2.25 | 3.73 | 0.42895 | 0.965137 | 8.3925 | 0.965137
753824 | Nivel 6 | 2.25 | 2.715 | 0.312225 | 0.702506 | 6.10875 | 0.702506
753826 | Nivel 6 | 2.25 | 0.789918 | 0.0908406 | 0.204391 | 1.77732 | 0.204391
753990 | Nivel 6 | 2.25 | 3.73 | 0.42895 | 0.965137 | 8.3925 | 0.965137
753992 | Nivel 6 | 2.25 | 2.715 | 0.312225 | 0.702506 | 6.10875 | 0.702506
753994 | Nivel 6 | 2.25 | 0.789918 | 0.0908406 | 0.204391 | 1.77732 | 0.204391
754192 | Nivel 6 | 2.25 | 3.73 | 0.42895 | 0.890387 | 7.7425 | 0.890387
754194 | Nivel 6 | 2.25 | 2.6 | 0.299 | 0.67275 | 5.85 | 0.67275
754196 | Nivel 6 | 2.25 | 0.789918 | 0.0908406 | 0.204391 | 1.77732 | 0.204391
754366 | Nivel 6 | 2.25 | 3.73 | 0.42895 | 0.890387 | 7.7425 | 0.890387
754368 | Nivel 6 | 2.25 | 2.715 | 0.312225 | 0.702506 | 6.10875 | 0.702506
754370 | Nivel 6 | 2.25 | 0.789918 | 0.0908406 | 0.204391 | 1.77732 | 0.204391
759247 | Nivel 7 |  | 7.3725 |  |  |  | 0.818311
764323 | Nivel 7 | 1.3468 | 0.759918 | 0.0873906 | 0.10551 | 0.91748 | 0.10551
764463 | Nivel 7 | 1.3468 | 0.759918 | 0.0873906 | 0.10551 | 0.91748 | 0.10551
764963 | Nivel 7 | 1.3468 | 2.685 | 0.308775 | 0.403671 | 3.51018 | 0.403671
765167 | Nivel 7 | 1.3468 | 2.8 | 0.322 | 0.421482 | 3.66506 | 0.421482
765284 | Nivel 7 |  | 2.75 |  |  |  | 0.4099
781232 | Nivel 1 | 2.25 | 3.715 | 0.427225 | 0.961256 | 8.35875 | 0.961256
781234 | Nivel 1 | 2.25 | 2.715 | 0.312225 | 0.702506 | 6.10875 | 0.702506
781235 | Nivel 1 | 2.25 | 2.0708 | 0.238142 | 0.302944 | 2.6343 | 0.302944
781236 | Nivel 1 | 2.25 | 0.674918 | 0.0776156 | 0.174635 | 1.51857 | 0.174635
791803 | Nivel 2 | 2.25 | 3.73 | 0.42895 | 0.965137 | 8.3925 | 0.965137
791805 | Nivel 2 | 2.25 | 2.715 | 0.312225 | 0.702506 | 6.10875 | 0.702506
791807 | Nivel 2 | 2.25 | 0.789918 | 0.0908406 | 0.204391 | 1.77732 | 0.204391
791970 | Nivel 2 | 2.25 | 3.73 | 0.42895 | 0.965137 | 8.3925 | 0.965137
791972 | Nivel 2 | 2.25 | 2.715 | 0.312225 | 0.702506 | 6.10875 | 0.702506
791974 | Nivel 2 | 2.25 | 0.789918 | 0.0908406 | 0.204391 | 1.77732 | 0.204391
792168 | Nivel 2 | 2.25 | 3.73 | 0.42895 | 0.890387 | 7.7425 | 0.890387
792170 | Nivel 2 | 2.25 | 2.715 | 0.312225 | 0.702506 | 6.10875 | 0.702506
792172 | Nivel 2 | 2.25 | 0.789918 | 0.0908406 | 0.204391 | 1.77732 | 0.204391
792341 | Nivel 2 | 2.25 | 3.73 | 0.42895 | 0.890387 | 7.7425 | 0.890387
792343 | Nivel 2 | 2.25 | 2.715 | 0.312225 | 0.702506 | 6.10875 | 0.702506
792345 | Nivel 2 | 2.25 | 0.789918 | 0.0908406 | 0.204391 | 1.77732 | 0.204391
801581 | Nivel 2 | 2.25 | 1.9558 | 0.224917 | 0.273188 | 2.37555 | 0.273188
801630 | Nivel 2 | 2.25 | 1.9558 | 0.224917 | 0.273188 | 2.37555 | 0.273188
801679 | Nivel 2 | 2.25 | 1.9558 | 0.224917 | 0.273188 | 2.37555 | 0.273188
801906 | Nivel 4 | 2.25 | 1.9558 | 0.224917 | 0.273188 | 2.37555 | 0.273188
801924 | Nivel 4 | 2.25 | 1.9558 | 0.224917 | 0.273188 | 2.37555 | 0.273188
801942 | Nivel 4 | 2.25 | 1.9558 | 0.224917 | 0.273188 | 2.37555 | 0.273188
801960 | Nivel 4 | 2.25 | 1.9558 | 0.224917 | 0.273188 | 2.37555 | 0.273188
802126 | Nivel 6 | 2.25 | 1.9558 | 0.224917 | 0.273188 | 2.37555 | 0.273188
802144 | Nivel 6 | 2.25 | 1.9558 | 0.224917 | 0.273188 | 2.37555 | 0.273188
802162 | Nivel 6 | 2.25 | 1.9558 | 0.224917 | 0.273188 | 2.37555 | 0.273188
802180 | Nivel 6 | 2.25 | 1.9558 | 0.224917 | 0.273188 | 2.37555 | 0.273188
872638 | Nivel 1 | 2.25 | 3.72976 | 0.428923 | 0.965076 | 8.39197 | 0.965076
872640 | Nivel 1 | 2.25 | 2.6 | 0.299 | 0.67275 | 5.85 | 0.67275
872641 | Nivel 1 | 2.25 | 2.0708 | 0.238142 | 0.302944 | 2.6343 | 0.302944
872642 | Nivel 1 | 2.25 | 0.674918 | 0.0776156 | 0.174635 | 1.51857 | 0.174635
872836 | Nivel 1 | 2.25 | 3.73 | 0.42895 | 0.965137 | 8.3925 | 0.965137
872838 | Nivel 1 | 2.25 | 2.6 | 0.299 | 0.67275 | 5.85 | 0.67275
872839 | Nivel 1 | 2.25 | 2.0708 | 0.238142 | 0.302944 | 2.6343 | 0.302944
872840 | Nivel 1 | 2.25 | 0.674918 | 0.0776156 | 0.174635 | 1.51857 | 0.174635
906980 | Nivel 7 | 0.9758 | 7.46 | 0.8579 | 0.837139 | 7.27947 | 0.830239
1097792 | Nivel 6 | 2.25 | 0.115 | 0.013225 | 0.0297563 | 0.25875 | 0.0297563
1217764 | Nivel 1 | 0.5 | 1.26 | 0.1449 | 0.07245 | 0.63 | 0.07245
1218679 | Nivel 1 | 2.25 | 0.115 | 0.013225 | 0.0297563 | 0.25875 | 0.0297563
1220793 | Nivel 1 | 2.25 | 0.115 | 0.013225 | 0.0297563 | 0.25875 | 0.0297563
1222604 | Nivel 1 | 2.25 | 0.115 | 0.013225 | 0.0297563 | 0.25875 | 0.0297563
1224043 | Nivel 1 | 2.25 | 0.115 | 0.013225 | 0.0297563 | 0.25875 | 0.0297563
1246867 | Nivel 2 | 0.5 | 2.125 | 0.244375 | 0.122187 | 1.0625 | 0.122187
1247969 | Nivel 3 | 0.5 | 2.125 | 0.244375 | 0.122188 | 1.0625 | 0.122188
1247973 | Nivel 3 | 0.5 | 2.125 | 0.244375 | 0.122188 | 1.0625 | 0.122188
1247977 | Nivel 3 | 0.5 | 2.125 | 0.244375 | 0.122188 | 1.0625 | 0.122188
1247981 | Nivel 3 | 0.5 | 2.125 | 0.244375 | 0.122188 | 1.0625 | 0.122188
1247985 | Nivel 4 | 0.5 | 2.125 | 0.244375 | 0.122188 | 1.0625 | 0.122188
1247989 | Nivel 4 | 0.5 | 2.125 | 0.244375 | 0.122188 | 1.0625 | 0.122188
1247993 | Nivel 4 | 0.5 | 2.125 | 0.244375 | 0.122188 | 1.0625 | 0.122188
1247997 | Nivel 4 | 0.5 | 2.125 | 0.244375 | 0.122188 | 1.0625 | 0.122188
1248001 | Nivel 5 | 0.5 | 2.125 | 0.244375 | 0.122188 | 1.0625 | 0.122188
1248005 | Nivel 5 | 0.5 | 2.125 | 0.244375 | 0.122188 | 1.0625 | 0.122188
1248009 | Nivel 5 | 0.5 | 2.125 | 0.244375 | 0.122188 | 1.0625 | 0.122188
1248013 | Nivel 5 | 0.5 | 2.125 | 0.244375 | 0.122188 | 1.0625 | 0.122188
1248017 | Nivel 6 | 0.5 | 2.125 | 0.244375 | 0.122188 | 1.0625 | 0.122188
1248021 | Nivel 6 | 0.5 | 2.125 | 0.244375 | 0.122188 | 1.0625 | 0.122188
1248025 | Nivel 6 | 0.5 | 2.125 | 0.244375 | 0.122188 | 1.0625 | 0.122188
1248029 | Nivel 6 | 0.5 | 2.125 | 0.244375 | 0.122188 | 1.0625 | 0.122188
1248033 | Nivel 2 | 0.5 | 2.125 | 0.244375 | 0.122187 | 1.0625 | 0.122187
1248037 | Nivel 2 | 0.5 | 2.125 | 0.244375 | 0.122187 | 1.0625 | 0.122187
1248041 | Nivel 2 | 0.5 | 2.125 | 0.244375 | 0.122187 | 1.0625 | 0.122187
1256411 | Nivel 2 | 2.25 | 1.9558 | 0.224917 | 0.273188 | 2.37555 | 0.273188
1275111 | Nivel 7 | 1.2468 | 0.6708 | 0.077142 | 0.0961806 | 0.836353 | 0.0961806
1275336 | Nivel 7 | 1.2468 | 0.5 | 0.0575 | 0.071691 | 0.6234 | 0.071691
1276089 | Nivel 7 | 1.2468 | 0.6708 | 0.077142 | 0.0961806 | 0.836353 | 0.0961806
1276090 | Nivel 7 | 1.2468 | 0.385 | 0.044275 | 0.0552021 | 0.480018 | 0.0552021
1277774 | Nivel 7 | 1.3468 | 0.759918 | 0.0873906 | 0.10551 | 0.91748 | 0.10551
1277777 | Nivel 7 | 1.2468 | 0.6708 | 0.077142 | 0.0961806 | 0.836353 | 0.0961806
1277778 | Nivel 7 | 1.2468 | 0.5 | 0.0575 | 0.071691 | 0.6234 | 0.071691
1277914 | Nivel 7 | 1.3468 | 0.789918 | 0.0908406 | 0.122344 | 1.06386 | 0.122344
1277916 | Nivel 7 | 1.3468 | 2.8 | 0.322 | 0.421482 | 3.66506 | 0.421482
1277920 | Nivel 7 | 1.2468 | 0.6708 | 0.077142 | 0.0961806 | 0.836353 | 0.0961806
1277921 | Nivel 7 | 1.2468 | 0.385 | 0.044275 | 0.0552021 | 0.480018 | 0.0552021

# IfcWall: Basic Wall:B2010 - 0.115m - Muro interior en concreto (2)
In: Nivel 7
Type - PredefinedType: STANDARD
Type - Pset_WallCommon - IsExternal: yes; ThermalTransmittance: 0.217391 kg/K/s3
Classification: 21-02 20 10 20 Uniformat (Uniformat); Material: Concreto (Aire)
Qto_WallBaseQuantities - Height: 0.2812 m; Length: 0.935 m; Width: 0.115 m; GrossFootprintArea: 0.107525 m2; GrossVolume: 0.030236 m3; GrossSideArea: 0.262922 m2; NetSideArea: 0.262922 m2; NetVolume: 0.0293086 m3
Pset_EnvironmentalImpactIndicators - Reference: B2010 - 0.115m - Muro interior en concreto; sets with these values: 2
Pset_WallCommon - LoadBearing: no; ExtendToStructure: yes; Reference: B2010 - 0.115m - Muro interior en concreto
Name (Basic Wall:B2010 - 0.115m - Muro interior en concreto:...)
1160815
1290978

# IfcWall: Basic Wall:B2010 - 0.115m - Muro interior en mampostería - Ladrillo (107)
Type - PredefinedType: STANDARD
Type - Pset_WallCommon - IsExternal: yes; ThermalTransmittance: 0.217391 kg/K/s3
Classification: 21-03 10 10 10 Uniformat (Uniformat); Material: Ladrillo claro (Aire)
Qto_WallBaseQuantities - Width: 0.115 m
Pset_EnvironmentalImpactIndicators - Reference: B2010 - 0.115m - Muro interior en mampostería - Ladrillo; sets with these values: 2
Pset_WallCommon - LoadBearing: no; Reference: B2010 - 0.115m - Muro interior en mampostería - Ladrillo
Name (Basic Wall:B2010 - 0.115m - Muro interior en mampostería - Ladrillo:...) | In | Height (m) | Length (m) | GrossFootprintArea (m2) | GrossVolume (m3) | GrossSideArea (m2) = NetSideArea (m2) | NetVolume (m3) | ExtendToStructure
728543 | Nivel 1 | 2.25 | 2.715 | 0.312225 | 0.702506 | 6.10875 | 0.702506 | no
728546 | Nivel 1 | 2.25 | 1.53 | 0.17595 | 0.395887 | 3.4425 | 0.395887 | no
728550 | Nivel 1 | 2.25 | 1.5155 | 0.174282 | 0.392136 | 3.40987 | 0.392136 | no
749127 | Nivel 3 | 2.25 | 2.715 | 0.312225 | 0.702506 | 6.10875 | 0.702506 | no
749130 | Nivel 3 | 2.25 | 1.415 | 0.162725 | 0.366131 | 3.18375 | 0.366131 | no
749295 | Nivel 3 | 2.25 | 2.715 | 0.312225 | 0.702506 | 6.10875 | 0.702506 | no
749298 | Nivel 3 | 2.25 | 1.415 | 0.162725 | 0.366131 | 3.18375 | 0.366131 | no
749497 | Nivel 3 | 2.25 | 2.715 | 0.312225 | 0.702506 | 6.10875 | 0.702506 | no
749500 | Nivel 3 | 2.25 | 1.415 | 0.162725 | 0.366131 | 3.18375 | 0.366131 | no
749671 | Nivel 3 | 2.25 | 2.715 | 0.312225 | 0.702506 | 6.10875 | 0.702506 | no
749674 | Nivel 3 | 2.25 | 1.415 | 0.162725 | 0.366131 | 3.18375 | 0.366131 | no
749832 | Nivel 3 | 2.23 | 0.669595 | 0.0770034 | 0.171718 | 1.4932 | 0.171718 | no
750694 | Nivel 4 | 2.25 | 2.715 | 0.312225 | 0.702506 | 6.10875 | 0.702506 | no
750697 | Nivel 4 | 2.25 | 1.415 | 0.162725 | 0.366131 | 3.18375 | 0.366131 | no
750862 | Nivel 4 | 2.25 | 2.715 | 0.312225 | 0.702506 | 6.10875 | 0.702506 | no
750865 | Nivel 4 | 2.25 | 1.415 | 0.162725 | 0.366131 | 3.18375 | 0.366131 | no
751064 | Nivel 4 | 2.25 | 2.715 | 0.312225 | 0.702506 | 6.10875 | 0.702506 | no
751067 | Nivel 4 | 2.25 | 1.415 | 0.162725 | 0.366131 | 3.18375 | 0.366131 | no
751238 | Nivel 4 | 2.25 | 2.715 | 0.312225 | 0.702506 | 6.10875 | 0.702506 | no
751241 | Nivel 4 | 2.25 | 1.415 | 0.162725 | 0.366131 | 3.18375 | 0.366131 | no
751399 | Nivel 4 | 2.23 | 0.669595 | 0.0770034 | 0.171718 | 1.4932 | 0.171718 | no
752261 | Nivel 5 | 2.25 | 2.715 | 0.312225 | 0.702506 | 6.10875 | 0.702506 | no
752264 | Nivel 5 | 2.25 | 1.415 | 0.162725 | 0.366131 | 3.18375 | 0.366131 | no
752429 | Nivel 5 | 2.25 | 2.715 | 0.312225 | 0.702506 | 6.10875 | 0.702506 | no
752432 | Nivel 5 | 2.25 | 1.415 | 0.162725 | 0.366131 | 3.18375 | 0.366131 | no
752631 | Nivel 5 | 2.25 | 2.715 | 0.312225 | 0.702506 | 6.10875 | 0.702506 | no
752634 | Nivel 5 | 2.25 | 1.415 | 0.162725 | 0.366131 | 3.18375 | 0.366131 | no
752805 | Nivel 5 | 2.25 | 2.715 | 0.312225 | 0.702506 | 6.10875 | 0.702506 | no
752808 | Nivel 5 | 2.25 | 1.415 | 0.162725 | 0.366131 | 3.18375 | 0.366131 | no
752966 | Nivel 5 | 2.23 | 0.669595 | 0.0770034 | 0.171718 | 1.4932 | 0.171718 | no
753828 | Nivel 6 | 2.25 | 2.715 | 0.312225 | 0.702506 | 6.10875 | 0.702506 | no
753831 | Nivel 6 | 2.25 | 1.415 | 0.162725 | 0.366131 | 3.18375 | 0.366131 | no
753996 | Nivel 6 | 2.25 | 2.715 | 0.312225 | 0.702506 | 6.10875 | 0.702506 | no
753999 | Nivel 6 | 2.25 | 1.415 | 0.162725 | 0.366131 | 3.18375 | 0.366131 | no
754198 | Nivel 6 | 2.25 | 2.715 | 0.312225 | 0.702506 | 6.10875 | 0.702506 | no
754201 | Nivel 6 | 2.25 | 1.415 | 0.162725 | 0.366131 | 3.18375 | 0.366131 | no
754372 | Nivel 6 | 2.25 | 2.715 | 0.312225 | 0.702506 | 6.10875 | 0.702506 | no
754375 | Nivel 6 | 2.25 | 1.415 | 0.162725 | 0.366131 | 3.18375 | 0.366131 | no
754533 | Nivel 6 | 2.23 | 0.669595 | 0.0770034 | 0.171718 | 1.4932 | 0.171718 | no
756415 | Nivel 7 | 0.4 | 2.485 | 0.285775 | 0.11431 | 0.994 | 0.11431 | no
759992 | Nivel 7 | 1.1357 | 2.715 | 0.312225 | 0.291017 | 2.53058 | 0.291017 | yes
760284 | Nivel 7 | 0.59345 | 1.4725 | 0.169337 | 0.100493 | 0.873855 | 0.0990328 | yes
760446 | Nivel 7 | 0.59345 | 1.414 | 0.16261 | 0.0792561 | 0.689184 | 0.0792561 | yes
764399 | Nivel 7 | 1.1357 | 2.715 | 0.312225 | 0.291017 | 2.53058 | 0.291017 | yes
764401 | Nivel 7 | 0.59345 | 1.4725 | 0.169337 | 0.100493 | 0.873855 | 0.0990328 | yes
764402 | Nivel 7 | 0.59345 | 1.414 | 0.16261 | 0.0792561 | 0.689184 | 0.0792561 | yes
767775 | Nivel 7 | 1.1357 | 2.715 | 0.312225 | 0.291017 | 2.53058 | 0.291017 | yes
767777 | Nivel 7 | 0.59345 | 1.4725 | 0.169337 | 0.100493 | 0.873855 | 0.0990328 | yes
767778 | Nivel 7 | 0.59345 | 1.414 | 0.16261 | 0.0792561 | 0.689184 | 0.0792561 | yes
767974 | Nivel 7 | 1.1357 | 2.715 | 0.312225 | 0.291017 | 2.53058 | 0.291017 | yes
767976 | Nivel 7 | 0.59345 | 1.4725 | 0.169337 | 0.100493 | 0.873855 | 0.0990328 | yes
767977 | Nivel 7 | 0.8 | 1.515 | 0.174225 | 0.13938 | 1.212 | 0.13938 | no
767983 | Nivel 7 |  | 1.3575 |  |  |  | 0.0712348 | yes
781238 | Nivel 1 | 2.25 | 2.715 | 0.312225 | 0.702506 | 6.10875 | 0.702506 | no
781241 | Nivel 1 | 2.25 | 1.415 | 0.162725 | 0.366131 | 3.18375 | 0.366131 | no
781245 | Nivel 1 | 2.25 | 2.515 | 0.289225 | 0.393156 | 3.41875 | 0.393156 | no
791809 | Nivel 2 | 2.25 | 2.715 | 0.312225 | 0.702506 | 6.10875 | 0.702506 | no
791812 | Nivel 2 | 2.25 | 1.415 | 0.162725 | 0.366131 | 3.18375 | 0.366131 | no
791976 | Nivel 2 | 2.25 | 2.715 | 0.312225 | 0.702506 | 6.10875 | 0.702506 | no
791979 | Nivel 2 | 2.25 | 1.415 | 0.162725 | 0.366131 | 3.18375 | 0.366131 | no
792174 | Nivel 2 | 2.25 | 2.715 | 0.312225 | 0.702506 | 6.10875 | 0.702506 | no
792177 | Nivel 2 | 2.25 | 1.415 | 0.162725 | 0.366131 | 3.18375 | 0.366131 | no
792181 | Nivel 2 | 2.25 | 1.515 | 0.174225 | 0.392006 | 3.40875 | 0.392006 | no
792347 | Nivel 2 | 2.25 | 2.715 | 0.312225 | 0.702506 | 6.10875 | 0.702506 | no
792350 | Nivel 2 | 2.25 | 1.415 | 0.162725 | 0.366131 | 3.18375 | 0.366131 | no
792354 | Nivel 2 | 2.25 | 1.515 | 0.174225 | 0.392006 | 3.40875 | 0.392006 | no
792507 | Nivel 2 | 2.23 | 0.669595 | 0.0770034 | 0.171718 | 1.4932 | 0.171718 | no
809999 | Nivel 2 | 0.54 | 6.28 | 0.7222 | 0.389988 | 3.3912 | 0.389988 | no
872644 | Nivel 1 | 2.25 | 2.715 | 0.312225 | 0.702506 | 6.10875 | 0.702506 | no
872647 | Nivel 1 | 2.25 | 1.54 | 0.1771 | 0.398475 | 3.465 | 0.398475 | no
872651 | Nivel 1 | 2.25 | 1.5155 | 0.174282 | 0.392136 | 3.40987 | 0.392136 | no
872842 | Nivel 1 | 2.25 | 2.715 | 0.312225 | 0.702506 | 6.10875 | 0.702506 | no
872845 | Nivel 1 | 2.25 | 1.54 | 0.1771 | 0.398475 | 3.465 | 0.398475 | no
872849 | Nivel 1 | 2.25 | 1.5145 | 0.174167 | 0.391877 | 3.40762 | 0.391877 | no
1205278 | Nivel 3 | 2.25 | 1.515 | 0.174225 | 0.392006 | 3.40875 | 0.392006 | no
1205279 | Nivel 3 | 2.25 | 1.515 | 0.174225 | 0.392006 | 3.40875 | 0.392006 | no
1205284 | Nivel 4 | 2.25 | 1.515 | 0.174225 | 0.392006 | 3.40875 | 0.392006 | no
1205285 | Nivel 4 | 2.25 | 1.515 | 0.174225 | 0.392006 | 3.40875 | 0.392006 | no
1205290 | Nivel 5 | 2.25 | 1.515 | 0.174225 | 0.392006 | 3.40875 | 0.392006 | no
1205291 | Nivel 5 | 2.25 | 1.515 | 0.174225 | 0.392006 | 3.40875 | 0.392006 | no
1205296 | Nivel 6 | 2.25 | 1.515 | 0.174225 | 0.392006 | 3.40875 | 0.392006 | no
1205297 | Nivel 6 | 2.25 | 1.515 | 0.174225 | 0.392006 | 3.40875 | 0.392006 | no
1259687 | Nivel 2 | 2.25 | 1.515 | 0.174225 | 0.392006 | 3.40875 | 0.392006 | no
1259898 | Nivel 2 | 2.25 | 1.515 | 0.174225 | 0.392006 | 3.40875 | 0.392006 | no
1260248 | Nivel 3 | 2.25 | 1.515 | 0.174225 | 0.392006 | 3.40875 | 0.392006 | no
1260249 | Nivel 3 | 2.25 | 1.515 | 0.174225 | 0.392006 | 3.40875 | 0.392006 | no
1260252 | Nivel 4 | 2.25 | 1.515 | 0.174225 | 0.392006 | 3.40875 | 0.392006 | no
1260253 | Nivel 4 | 2.25 | 1.515 | 0.174225 | 0.392006 | 3.40875 | 0.392006 | no
1260256 | Nivel 5 | 2.25 | 1.515 | 0.174225 | 0.392006 | 3.40875 | 0.392006 | no
1260257 | Nivel 5 | 2.25 | 1.515 | 0.174225 | 0.392006 | 3.40875 | 0.392006 | no
1260260 | Nivel 6 | 2.25 | 1.515 | 0.174225 | 0.392006 | 3.40875 | 0.392006 | no
1260261 | Nivel 6 | 2.25 | 1.515 | 0.174225 | 0.392006 | 3.40875 | 0.392006 | no
1824540 | Nivel 3 | 2.23 | 0.672 | 0.07728 | 0.172334 | 1.49856 | 0.172334 | no
1827430 | Nivel 4 | 2.23 | 0.672 | 0.07728 | 0.172334 | 1.49856 | 0.172334 | no
1827779 | Nivel 5 | 2.23 | 0.672 | 0.07728 | 0.172334 | 1.49856 | 0.172334 | no
1828128 | Nivel 6 | 2.23 | 0.672 | 0.07728 | 0.172334 | 1.49856 | 0.172334 | no
1828477 | Nivel 2 | 2.23 | 0.672 | 0.07728 | 0.172334 | 1.49856 | 0.172334 | no
1833045 | Nivel 7 | 1.195 | 0.724 | 0.08326 | 0.0994957 | 0.86518 | 0.0994957 | yes
1833046 | Nivel 7 | 1.195 | 0.672 | 0.07728 | 0.0923496 | 0.80304 | 0.0923496 | yes
1895386 | Nivel 1 | 1.155 | 0.672 | 0.07728 | 0.0892584 | 0.77616 | 0.0892584 | no
1897001 | Nivel 1 | 1.155 | 0.669595 | 0.0770034 | 0.0889389 | 0.773382 | 0.0889389 | no
1911018 | Nivel 1 | 0.11 | 1.05741 | 0.121602 | 0.0133762 | 0.116315 | 0.0133762 | no
1923092 | Nivel 2 | 0.2 | 1.05741 | 0.121602 | 0.0243203 | 0.211481 | 0.0243203 | no
1924233 | Nivel 3 | 0.2 | 1.05741 | 0.121602 | 0.0243203 | 0.211481 | 0.0243203 | no
1924238 | Nivel 4 | 0.2 | 1.05741 | 0.121602 | 0.0243203 | 0.211481 | 0.0243203 | no
1924243 | Nivel 5 | 0.2 | 1.05741 | 0.121602 | 0.0243203 | 0.211481 | 0.0243203 | no
1924248 | Nivel 6 | 0.2 | 1.05741 | 0.121602 | 0.0243203 | 0.211481 | 0.0243203 | no

# IfcWall: Basic Wall:B2010 - 0.115m - Muro interior en mampostería - Ladrillo + Pañete (80)
Type - PredefinedType: STANDARD; Material: Pañete, Ladrillo claro (Aire)
Type - Pset_WallCommon - IsExternal: yes; ThermalTransmittance: 0.215153 kg/K/s3
Classification: 21-03 10 10 10 Uniformat (Uniformat)
Qto_WallBaseQuantities - Pañete, Width: 0.01 m; Ladrillo claro (Aire), Width: 0.115 m; Width: 0.125 m
Pset_EnvironmentalImpactIndicators - Reference: B2010 - 0.115m - Muro interior en mampostería - Ladrillo + Pañete; sets with these values: 2
Pset_WallCommon - LoadBearing: no; Reference: B2010 - 0.115m - Muro interior en mampostería - Ladrillo + Pañete
Name (Basic Wall:B2010 - 0.115m - Muro interior en mampostería - Ladrillo + Pañete:...) | In | Height (m) | Length (m) | GrossVolume (m3) | GrossSideArea (m2) = NetSideArea (m2) | NetVolume (m3) | ExtendToStructure
728545 | Nivel 1 | 2.25 | 2.715 | 0.746719 | 5.97375 | 0.743722 | no
728673 | Nivel 1 | 2.25 | 0.5 | 0.140625 | 1.125 | 0.140625 | no
749129 | Nivel 3 | 2.25 | 2.715 | 0.746719 | 5.97375 | 0.743722 | no
749136 | Nivel 3 | 2.25 | 1.1333 | 0.28494 | 2.27952 | 0.28494 | no
749235 | Nivel 3 | 2.25 | 0.5525 | 0.137813 | 1.1025 | 0.137813 | no
749297 | Nivel 3 | 2.25 | 2.715 | 0.746719 | 5.97375 | 0.743722 | no
749304 | Nivel 3 | 2.25 | 1.1333 | 0.28494 | 2.27952 | 0.28494 | no
749401 | Nivel 3 | 2.25 | 0.5525 | 0.137813 | 1.1025 | 0.137813 | no
749499 | Nivel 3 | 2.25 | 2.715 | 0.746719 | 5.97375 | 0.743722 | no
749506 | Nivel 3 | 2.25 | 1.1333 | 0.28494 | 2.27952 | 0.28494 | no
749603 | Nivel 3 | 2.25 | 0.5525 | 0.137813 | 1.1025 | 0.137813 | no
749673 | Nivel 3 | 2.25 | 2.715 | 0.746719 | 5.97375 | 0.743722 | no
749680 | Nivel 3 | 2.25 | 1.1333 | 0.28494 | 2.27952 | 0.28494 | no
749777 | Nivel 3 | 2.25 | 0.5525 | 0.137813 | 1.1025 | 0.137813 | no
750696 | Nivel 4 | 2.25 | 2.715 | 0.746719 | 5.97375 | 0.743722 | no
750703 | Nivel 4 | 2.25 | 1.1333 | 0.28494 | 2.27952 | 0.28494 | no
750802 | Nivel 4 | 2.25 | 0.5525 | 0.137813 | 1.1025 | 0.137813 | no
750864 | Nivel 4 | 2.25 | 2.715 | 0.746719 | 5.97375 | 0.743722 | no
750871 | Nivel 4 | 2.25 | 1.1333 | 0.28494 | 2.27952 | 0.28494 | no
750968 | Nivel 4 | 2.25 | 0.5525 | 0.137813 | 1.1025 | 0.137813 | no
751066 | Nivel 4 | 2.25 | 2.715 | 0.746719 | 5.97375 | 0.743722 | no
751073 | Nivel 4 | 2.25 | 1.1333 | 0.28494 | 2.27952 | 0.28494 | no
751170 | Nivel 4 | 2.25 | 0.5525 | 0.137813 | 1.1025 | 0.137813 | no
751240 | Nivel 4 | 2.25 | 2.715 | 0.746719 | 5.97375 | 0.743722 | no
751247 | Nivel 4 | 2.25 | 1.1333 | 0.28494 | 2.27952 | 0.28494 | no
751344 | Nivel 4 | 2.25 | 0.5525 | 0.137813 | 1.1025 | 0.137813 | no
752263 | Nivel 5 | 2.25 | 2.715 | 0.746719 | 5.97375 | 0.743722 | no
752270 | Nivel 5 | 2.25 | 1.1333 | 0.28494 | 2.27952 | 0.28494 | no
752369 | Nivel 5 | 2.25 | 0.5525 | 0.137813 | 1.1025 | 0.137813 | no
752431 | Nivel 5 | 2.25 | 2.715 | 0.746719 | 5.97375 | 0.743722 | no
752438 | Nivel 5 | 2.25 | 1.1333 | 0.28494 | 2.27952 | 0.28494 | no
752535 | Nivel 5 | 2.25 | 0.5525 | 0.137813 | 1.1025 | 0.137813 | no
752633 | Nivel 5 | 2.25 | 2.715 | 0.746719 | 5.97375 | 0.743722 | no
752640 | Nivel 5 | 2.25 | 1.1333 | 0.28494 | 2.27952 | 0.28494 | no
752737 | Nivel 5 | 2.25 | 0.5525 | 0.137813 | 1.1025 | 0.137813 | no
752807 | Nivel 5 | 2.25 | 2.715 | 0.746719 | 5.97375 | 0.743722 | no
752814 | Nivel 5 | 2.25 | 1.1333 | 0.28494 | 2.27952 | 0.28494 | no
752911 | Nivel 5 | 2.25 | 0.5525 | 0.137813 | 1.1025 | 0.137813 | no
753830 | Nivel 6 | 2.25 | 2.715 | 0.746719 | 5.97375 | 0.743722 | no
753837 | Nivel 6 | 2.25 | 1.1333 | 0.28494 | 2.27952 | 0.28494 | no
753936 | Nivel 6 | 2.25 | 0.5525 | 0.137813 | 1.1025 | 0.137813 | no
753998 | Nivel 6 | 2.25 | 2.715 | 0.746719 | 5.97375 | 0.743722 | no
754005 | Nivel 6 | 2.25 | 1.1333 | 0.28494 | 2.27952 | 0.28494 | no
754102 | Nivel 6 | 2.25 | 0.5525 | 0.137813 | 1.1025 | 0.137813 | no
754200 | Nivel 6 | 2.25 | 2.715 | 0.746719 | 5.97375 | 0.743722 | no
754207 | Nivel 6 | 2.25 | 1.1333 | 0.28494 | 2.27952 | 0.28494 | no
754304 | Nivel 6 | 2.25 | 0.5525 | 0.137813 | 1.1025 | 0.137813 | no
754374 | Nivel 6 | 2.25 | 2.715 | 0.746719 | 5.97375 | 0.743722 | no
754381 | Nivel 6 | 2.25 | 1.1333 | 0.28494 | 2.27952 | 0.28494 | no
754478 | Nivel 6 | 2.25 | 0.5525 | 0.137813 | 1.1025 | 0.137813 | no
760719 | Nivel 7 | 0.59345 | 2.1725 | 0.114957 | 0.919655 | 0.114957 | yes
761025 | Nivel 7 | 0.59345 | 0.5575 | 0.041356 | 0.330848 | 0.0407027 | yes
764405 | Nivel 7 | 0.59345 | 2.1725 | 0.114957 | 0.919655 | 0.114957 | yes
764407 | Nivel 7 | 0.59345 | 0.5575 | 0.041356 | 0.330848 | 0.0407027 | yes
767781 | Nivel 7 | 0.59345 | 2.1725 | 0.114957 | 0.919655 | 0.114957 | yes
767783 | Nivel 7 | 0.59345 | 0.5575 | 0.041356 | 0.330848 | 0.0407027 | yes
767980 | Nivel 7 | 0.59345 | 2.1725 | 0.114957 | 0.919655 | 0.114957 | yes
767982 | Nivel 7 | 0.59345 | 0.5575 | 0.041356 | 0.330848 | 0.0407027 | yes
781240 | Nivel 1 | 2.25 | 2.715 | 0.746719 | 5.97375 | 0.746719 | no
781247 | Nivel 1 | 2.25 | 1.08281 | 0.270741 | 2.16593 | 0.270741 | no
781344 | Nivel 1 | 2.25 | 0.5525 | 0.137813 | 1.1025 | 0.137813 | no
791811 | Nivel 2 | 2.25 | 2.715 | 0.746719 | 5.97375 | 0.743722 | no
791818 | Nivel 2 | 2.25 | 1.1333 | 0.28494 | 2.27952 | 0.28494 | no
791916 | Nivel 2 | 2.25 | 0.5525 | 0.137813 | 1.1025 | 0.137813 | no
791978 | Nivel 2 | 2.25 | 2.715 | 0.746719 | 5.97375 | 0.743722 | no
791985 | Nivel 2 | 2.25 | 1.1333 | 0.28494 | 2.27952 | 0.28494 | no
792081 | Nivel 2 | 2.25 | 0.5525 | 0.137813 | 1.1025 | 0.137813 | no
792176 | Nivel 2 | 2.25 | 2.715 | 0.746719 | 5.97375 | 0.743722 | no
792183 | Nivel 2 | 2.25 | 1.1333 | 0.28494 | 2.27952 | 0.28494 | no
792279 | Nivel 2 | 2.25 | 0.5525 | 0.137813 | 1.1025 | 0.137813 | no
792349 | Nivel 2 | 2.25 | 2.715 | 0.746719 | 5.97375 | 0.743722 | no
792356 | Nivel 2 | 2.25 | 1.1333 | 0.28494 | 2.27952 | 0.28494 | no
792452 | Nivel 2 | 2.25 | 0.5525 | 0.137813 | 1.1025 | 0.137813 | no
872646 | Nivel 1 | 2.25 | 2.715 | 0.746719 | 5.97375 | 0.743722 | no
872653 | Nivel 1 | 2.25 | 1.13331 | 0.284944 | 2.27955 | 0.284944 | no
872734 | Nivel 1 | 2.25 | 0.49 | 0.137813 | 1.1025 | 0.137813 | no
872844 | Nivel 1 | 2.25 | 2.715 | 0.746719 | 5.97375 | 0.743722 | no
872851 | Nivel 1 | 2.25 | 1.08281 | 0.270741 | 2.16593 | 0.270741 | no
872932 | Nivel 1 | 2.25 | 0.49 | 0.137813 | 1.1025 | 0.137813 | no
1684356 | Nivel 1 | 2.25 | 1.13346 | 0.284957 | 2.27966 | 0.284972 | no

# IfcWall: Basic Wall:B2010 - 0.115m - Muro interior en mampostería - Ladrillo + Pañete+ estuco+ pintura (47)
Type - PredefinedType: STANDARD; Material: Pañete, estuco y pintura, Ladrillo claro (Aire)
Type - Pset_WallCommon - IsExternal: yes; ThermalTransmittance: 0.215153 kg/K/s3
Classification: 21-03 10 10 10 Uniformat (Uniformat)
Qto_WallBaseQuantities - Pañete, estuco y pintura, Width: 0.01 m; Ladrillo claro (Aire), Width: 0.115 m; Width: 0.125 m; Height: 2.25 m
Pset_EnvironmentalImpactIndicators - Reference: B2010 - 0.115m - Muro interior en mampostería - Ladrillo + Pañete+ estuco+ pintura; sets with these values: 2
Pset_WallCommon - LoadBearing: no; ExtendToStructure: no; Reference: B2010 - 0.115m - Muro interior en mampostería - Ladrillo + Pañete+ estuco+ pintura
Name (Basic Wall:B2010 - 0.115m - Muro interior en mampostería - Ladrillo + Pañete+ estuco+ pintura:...) | In | Length (m) | GrossVolume (m3) = NetVolume (m3) | GrossSideArea (m2) = NetSideArea (m2)
728552 | Nivel 1 | 0.7575 | 0.213047 | 1.70438
749131 | Nivel 3 | 0.815 | 0.245391 | 1.96313
749299 | Nivel 3 | 0.815 | 0.245391 | 1.96313
749501 | Nivel 3 | 0.815 | 0.245391 | 1.96313
749675 | Nivel 3 | 0.815 | 0.245391 | 1.96313
750698 | Nivel 4 | 0.815 | 0.245391 | 1.96313
750866 | Nivel 4 | 0.815 | 0.245391 | 1.96313
751068 | Nivel 4 | 0.815 | 0.245391 | 1.96313
751242 | Nivel 4 | 0.815 | 0.245391 | 1.96313
752265 | Nivel 5 | 0.815 | 0.245391 | 1.96313
752433 | Nivel 5 | 0.815 | 0.245391 | 1.96313
752635 | Nivel 5 | 0.815 | 0.245391 | 1.96313
752809 | Nivel 5 | 0.815 | 0.245391 | 1.96313
753832 | Nivel 6 | 0.815 | 0.245391 | 1.96313
754000 | Nivel 6 | 0.815 | 0.245391 | 1.96313
754202 | Nivel 6 | 0.815 | 0.245391 | 1.96313
754376 | Nivel 6 | 0.815 | 0.245391 | 1.96313
781242 | Nivel 1 | 1.4075 | 0.412031 | 3.29625
791813 | Nivel 2 | 0.815 | 0.245391 | 1.96313
791980 | Nivel 2 | 0.815 | 0.245391 | 1.96313
792178 | Nivel 2 | 0.815 | 0.245391 | 1.96313
792351 | Nivel 2 | 0.815 | 0.245391 | 1.96313
872648 | Nivel 1 | 0.7575 | 0.213047 | 1.70438
872846 | Nivel 1 | 0.7575 | 0.213047 | 1.70438
910201 | Nivel 1 | 0.5925 | 0.166641 | 1.33312
911123 | Nivel 1 | 0.542 | 0.152437 | 1.2195
938050 | Nivel 2 | 0.542014 | 0.152442 | 1.21953
942240 | Nivel 3 | 0.542014 | 0.152442 | 1.21953
942257 | Nivel 3 | 0.542014 | 0.152442 | 1.21953
942273 | Nivel 3 | 0.542014 | 0.152442 | 1.21953
942289 | Nivel 3 | 0.542014 | 0.152442 | 1.21953
942305 | Nivel 4 | 0.542014 | 0.152442 | 1.21953
942322 | Nivel 4 | 0.542014 | 0.152442 | 1.21953
942338 | Nivel 4 | 0.542014 | 0.152442 | 1.21953
942354 | Nivel 4 | 0.542014 | 0.152442 | 1.21953
942371 | Nivel 5 | 0.542014 | 0.152442 | 1.21953
942388 | Nivel 5 | 0.542014 | 0.152442 | 1.21953
942404 | Nivel 5 | 0.542014 | 0.152442 | 1.21953
942420 | Nivel 5 | 0.542014 | 0.152442 | 1.21953
942436 | Nivel 6 | 0.542014 | 0.152442 | 1.21953
942453 | Nivel 6 | 0.542014 | 0.152442 | 1.21953
942469 | Nivel 6 | 0.542014 | 0.152442 | 1.21953
942485 | Nivel 6 | 0.542014 | 0.152442 | 1.21953
942501 | Nivel 2 | 0.542014 | 0.152442 | 1.21953
942517 | Nivel 2 | 0.542014 | 0.152442 | 1.21953
942533 | Nivel 2 | 0.542014 | 0.152442 | 1.21953
1683811 | Nivel 1 | 0.542014 | 0.152442 | 1.21953

# IfcWall: Basic Wall:B2010 - 0.115m - Muro interior en mampostería - Pañete + Ladrillo + Pañete, Basic Wall:B2010 - 0.115m - Muro interior en mampostería - Pañete + Ladrillo + Pañete:767981
In: Nivel 7
Type - PredefinedType: STANDARD; Material: Pañete (2), LADRILLO CLARO
Type - Pset_WallCommon - IsExternal: yes; ThermalTransmittance: 3.91518 kg/K/s3
Classification: 21-03 10 10 10 Uniformat (Uniformat)
Qto_WallBaseQuantities - Pañete, Width: 0.01 m; LADRILLO CLARO, Width: 0.115 m; Pañete (2), Width: 0.01 m; Width: 0.135 m; Height: 0.4727 m; Length: 1.315 m; GrossVolume: 0.0762583 m3; GrossSideArea: 0.564876 m2; NetSideArea: 0.564876 m2; NetVolume: 0.0746248 m3
Pset_EnvironmentalImpactIndicators - Reference: B2010 - 0.115m - Muro interior en mampostería - Pañete + Ladrillo + Pañete; sets with these values: 2
Pset_WallCommon - LoadBearing: no; ExtendToStructure: yes; Reference: B2010 - 0.115m - Muro interior en mampostería - Pañete + Ladrillo + Pañete

# IfcWall: Basic Wall:B2010 - 0.12m - Muro interior en concreto (26)
Type - PredefinedType: STANDARD
Type - Pset_WallCommon - IsExternal: no; FireRating: 60; ThermalTransmittance: 0.208333 kg/K/s3; LoadBearing: yes
Classification: 21-03 10 10 10 Uniformat (Uniformat); Material: Concreto (Aire)
Qto_WallBaseQuantities - Width: 0.12 m
Pset_EnvironmentalImpactIndicators - Reference: B2010 - 0.12m - Muro interior en concreto; sets with these values: 2
Pset_WallCommon - Reference: B2010 - 0.12m - Muro interior en concreto; LoadBearing: no
Name (Basic Wall:B2010 - 0.12m - Muro interior en concreto:...) | In | Height (m) | Length (m) | GrossFootprintArea (m2) | GrossVolume (m3) = NetVolume (m3) | GrossSideArea (m2) = NetSideArea (m2) | ExtendToStructure
722438 | Nivel 1 | 2.25 | 3.115 | 0.3738 | 0.84105 | 7.00875 | no
722439 | Nivel 1 | 2.25 | 3.915 | 0.4698 | 1.05705 | 8.80875 | no
724940 | Nivel 1 | 2.25 | 3.915 | 0.4698 | 1.05705 | 8.80875 | no
724971 | Nivel 1 | 2.25 | 3.115 | 0.3738 | 0.84105 | 7.00875 | no
749198 | Nivel 3 | 2.25 | 3.115 | 0.3738 | 0.84105 | 7.00875 | no
749199 | Nivel 3 | 2.25 | 3.915 | 0.4698 | 1.05705 | 8.80875 | no
749455 | Nivel 3 | 2.25 | 3.915 | 0.4698 | 1.05705 | 8.80875 | no
749456 | Nivel 3 | 2.25 | 3.115 | 0.3738 | 0.84105 | 7.00875 | no
750765 | Nivel 4 | 2.25 | 3.115 | 0.3738 | 0.84105 | 7.00875 | no
750766 | Nivel 4 | 2.25 | 3.915 | 0.4698 | 1.05705 | 8.80875 | no
751022 | Nivel 4 | 2.25 | 3.915 | 0.4698 | 1.05705 | 8.80875 | no
751023 | Nivel 4 | 2.25 | 3.115 | 0.3738 | 0.84105 | 7.00875 | no
752332 | Nivel 5 | 2.25 | 3.115 | 0.3738 | 0.84105 | 7.00875 | no
752333 | Nivel 5 | 2.25 | 3.915 | 0.4698 | 1.05705 | 8.80875 | no
752589 | Nivel 5 | 2.25 | 3.915 | 0.4698 | 1.05705 | 8.80875 | no
752590 | Nivel 5 | 2.25 | 3.115 | 0.3738 | 0.84105 | 7.00875 | no
753899 | Nivel 6 | 2.25 | 3.115 | 0.3738 | 0.84105 | 7.00875 | no
753900 | Nivel 6 | 2.25 | 3.915 | 0.4698 | 1.05705 | 8.80875 | no
754156 | Nivel 6 | 2.25 | 3.915 | 0.4698 | 1.05705 | 8.80875 | no
754157 | Nivel 6 | 2.25 | 3.115 | 0.3738 | 0.84105 | 7.00875 | no
762305 | Nivel 7 | 1.04345 | 3 | 0.36 | 0.294642 | 2.45535 | yes
767786 | Nivel 7 | 1.04345 | 3 | 0.36 | 0.294642 | 2.45535 | yes
791879 | Nivel 2 | 2.25 | 3.115 | 0.3738 | 0.84105 | 7.00875 | no
791880 | Nivel 2 | 2.25 | 3.915 | 0.4698 | 1.05705 | 8.80875 | no
792134 | Nivel 2 | 2.25 | 3.915 | 0.4698 | 1.05705 | 8.80875 | no
792135 | Nivel 2 | 2.25 | 3.115 | 0.3738 | 0.84105 | 7.00875 | no

# IfcWall: Basic Wall:B2010 - 0.2x0.2 - Muro calado- concreto (7)
Type - PredefinedType: STANDARD
Type - Pset_WallCommon - IsExternal: yes; ThermalTransmittance: 9.09565 kg/K/s3
Classification: 21-02 20 10 20 Uniformat (Uniformat); Material: Concret Calados
Qto_WallBaseQuantities - Length: 1.05741 m; Width: 0.115 m; GrossFootprintArea: 0.121602 m2
Pset_EnvironmentalImpactIndicators - Reference: B2010 - 0.2x0.2 - Muro calado- concreto; sets with these values: 2
Pset_WallCommon - LoadBearing: no; ExtendToStructure: no; Reference: B2010 - 0.2x0.2 - Muro calado- concreto
Name (Basic Wall:B2010 - 0.2x0.2 - Muro calado- concreto:...) | In | Height (m) | GrossVolume (m3) | GrossSideArea (m2) | NetSideArea (m2) | NetVolume (m3)
729509 | Nivel 1 | 1.045 | 0.127074 | 1.10499 | 0.744989 | 0.0856737
1831430 | Nivel 2 | 2.03 | 0.246851 | 2.14653 | 1.42653 | 0.164051
1831777 | Nivel 3 | 2.03 | 0.246851 | 2.14653 | 1.42653 | 0.164051
1832124 | Nivel 4 | 2.03 | 0.246851 | 2.14653 | 1.42653 | 0.164051
1832471 | Nivel 5 | 2.03 | 0.246851 | 2.14653 | 1.42653 | 0.164051
1833776 | Nivel 6 | 1.195 | 0.145314 | 1.2636 | 0.8316 | 0.0956339
1893673 | Nivel 1 | 2.03 | 0.246851 | 2.14653 | 1.42653 | 0.164051

# IfcWall: Basic Wall:C1070 - 0.02m - Plafón - Drywall (56)
Type - PredefinedType: STANDARD
Type - Pset_WallCommon - IsExternal: yes
Classification: 21-03 10 70 20 Uniformat (Uniformat); Material: Plasterboard
Qto_WallBaseQuantities - Width: 0.02 m
Pset_EnvironmentalImpactIndicators - Reference: C1070 - 0.02m - Plafón - Drywall; sets with these values: 2
Pset_WallCommon - LoadBearing: no; Reference: C1070 - 0.02m - Plafón - Drywall
Name (Basic Wall:C1070 - 0.02m - Plafón - Drywall:...) | In | Height (m) | Length (m) | GrossFootprintArea (m2) | GrossVolume (m3) = NetVolume (m3) | GrossSideArea (m2) = NetSideArea (m2) | ExtendToStructure
728667 | Nivel 1 | 0.23 | 1.715 | 0.0343 | 0.007889 | 0.39445 | no
749229 | Nivel 3 | 0.23 | 1.715 | 0.0343 | 0.007889 | 0.39445 | no
749230 | Nivel 3 | 0.23 | 0.68 | 0.0136 | 0.003128 | 0.1564 | no
749395 | Nivel 3 | 0.23 | 1.715 | 0.0343 | 0.007889 | 0.39445 | no
749396 | Nivel 3 | 0.23 | 0.68 | 0.0136 | 0.003128 | 0.1564 | no
749597 | Nivel 3 | 0.23 | 1.715 | 0.0343 | 0.007889 | 0.39445 | no
749598 | Nivel 3 | 0.23 | 0.68 | 0.0136 | 0.003128 | 0.1564 | no
749771 | Nivel 3 | 0.23 | 1.715 | 0.0343 | 0.007889 | 0.39445 | no
749772 | Nivel 3 | 0.23 | 0.68 | 0.0136 | 0.003128 | 0.1564 | no
750796 | Nivel 4 | 0.23 | 1.715 | 0.0343 | 0.007889 | 0.39445 | no
750797 | Nivel 4 | 0.23 | 0.68 | 0.0136 | 0.003128 | 0.1564 | no
750962 | Nivel 4 | 0.23 | 1.715 | 0.0343 | 0.007889 | 0.39445 | no
750963 | Nivel 4 | 0.23 | 0.68 | 0.0136 | 0.003128 | 0.1564 | no
751164 | Nivel 4 | 0.23 | 1.715 | 0.0343 | 0.007889 | 0.39445 | no
751165 | Nivel 4 | 0.23 | 0.68 | 0.0136 | 0.003128 | 0.1564 | no
751338 | Nivel 4 | 0.23 | 1.715 | 0.0343 | 0.007889 | 0.39445 | no
751339 | Nivel 4 | 0.23 | 0.68 | 0.0136 | 0.003128 | 0.1564 | no
752363 | Nivel 5 | 0.23 | 1.715 | 0.0343 | 0.007889 | 0.39445 | no
752364 | Nivel 5 | 0.23 | 0.68 | 0.0136 | 0.003128 | 0.1564 | no
752529 | Nivel 5 | 0.23 | 1.715 | 0.0343 | 0.007889 | 0.39445 | no
752530 | Nivel 5 | 0.23 | 0.68 | 0.0136 | 0.003128 | 0.1564 | no
752731 | Nivel 5 | 0.23 | 1.715 | 0.0343 | 0.007889 | 0.39445 | no
752732 | Nivel 5 | 0.23 | 0.68 | 0.0136 | 0.003128 | 0.1564 | no
752905 | Nivel 5 | 0.23 | 1.715 | 0.0343 | 0.007889 | 0.39445 | no
752906 | Nivel 5 | 0.23 | 0.68 | 0.0136 | 0.003128 | 0.1564 | no
753930 | Nivel 6 | 0.23 | 1.715 | 0.0343 | 0.007889 | 0.39445 | no
753931 | Nivel 6 | 0.23 | 0.68 | 0.0136 | 0.003128 | 0.1564 | no
754096 | Nivel 6 | 0.23 | 1.715 | 0.0343 | 0.007889 | 0.39445 | no
754097 | Nivel 6 | 0.23 | 0.68 | 0.0136 | 0.003128 | 0.1564 | no
754298 | Nivel 6 | 0.23 | 1.715 | 0.0343 | 0.007889 | 0.39445 | no
754299 | Nivel 6 | 0.23 | 0.68 | 0.0136 | 0.003128 | 0.1564 | no
754472 | Nivel 6 | 0.23 | 1.715 | 0.0343 | 0.007889 | 0.39445 | no
754473 | Nivel 6 | 0.23 | 0.68 | 0.0136 | 0.003128 | 0.1564 | no
763883 | Nivel 7 | 0.5747 | 0.68 | 0.0136 | 0.00712232 | 0.356116 | yes
764018 | Nivel 7 | 0.45245 | 1.175 | 0.0235 | 0.00856164 | 0.428082 | yes
764412 | Nivel 7 | 0.5747 | 0.68 | 0.0136 | 0.00712232 | 0.356116 | yes
764413 | Nivel 7 | 0.45245 | 1.175 | 0.0235 | 0.00856164 | 0.428082 | yes
767788 | Nivel 7 | 0.5747 | 0.68 | 0.0136 | 0.00712232 | 0.356116 | yes
767789 | Nivel 7 | 0.45245 | 1.175 | 0.0235 | 0.00856164 | 0.428082 | yes
767987 | Nivel 7 | 0.5747 | 0.68 | 0.0136 | 0.00712232 | 0.356116 | yes
767988 | Nivel 7 | 0.45245 | 1.175 | 0.0235 | 0.00856164 | 0.428082 | yes
781338 | Nivel 1 | 0.23 | 1.71 | 0.0342 | 0.007866 | 0.3933 | no
781339 | Nivel 1 | 0.23 | 0.685 | 0.0137 | 0.003151 | 0.15755 | no
791910 | Nivel 2 | 0.23 | 1.715 | 0.0343 | 0.007889 | 0.39445 | no
791911 | Nivel 2 | 0.23 | 0.68 | 0.0136 | 0.003128 | 0.1564 | no
792075 | Nivel 2 | 0.23 | 1.715 | 0.0343 | 0.007889 | 0.39445 | no
792076 | Nivel 2 | 0.23 | 0.68 | 0.0136 | 0.003128 | 0.1564 | no
792273 | Nivel 2 | 0.23 | 1.715 | 0.0343 | 0.007889 | 0.39445 | no
792274 | Nivel 2 | 0.23 | 0.68 | 0.0136 | 0.003128 | 0.1564 | no
792446 | Nivel 2 | 0.23 | 1.715 | 0.0343 | 0.007889 | 0.39445 | no
792447 | Nivel 2 | 0.23 | 0.68 | 0.0136 | 0.003128 | 0.1564 | no
948619 | Nivel 1 | 0.23 | 1.715 | 0.0343 | 0.007889 | 0.39445 | no
948648 | Nivel 1 | 0.23 | 1.715 | 0.0343 | 0.007889 | 0.39445 | no
948789 | Nivel 1 | 0.23 | 0.68 | 0.0136 | 0.003128 | 0.1564 | no
948991 | Nivel 1 | 0.23 | 0.68 | 0.0136 | 0.003128 | 0.1564 | no
949001 | Nivel 1 | 0.23 | 0.68 | 0.0136 | 0.003128 | 0.1564 | no

# IfcWall: Basic Wall:C2010 - 0.002m - MI acabado de muro- Estuco+ pintura (25)
Type - PredefinedType: STANDARD
Type - Pset_WallCommon - IsExternal: yes; ThermalTransmittance: 104.5 kg/K/s3
Classification: 21-03 10 10 10 Uniformat (Uniformat); Material: Repello y pintura
Qto_WallBaseQuantities - Width: 0.002 m
Pset_EnvironmentalImpactIndicators - Reference: C2010 - 0.002m - MI acabado de muro- Estuco+ pintura; sets with these values: 2
Pset_WallCommon - LoadBearing: no; Reference: C2010 - 0.002m - MI acabado de muro- Estuco+ pintura
Name (Basic Wall:C2010 - 0.002m - MI acabado de muro- Estuco+ pintura:...) | In | Height (m) | Length (m) | GrossFootprintArea (m2) | GrossVolume (m3) | GrossSideArea (m2) = NetSideArea (m2) | NetVolume (m3) | ExtendToStructure
1722378 | Nivel 6 | 0.381575 | 1.3 | 0.0026 | 0.000992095 | 0.496047 | 0.000991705 | yes
1902427 | Nivel 1 | 0.25 | 0.774999 | 0.00155 | 0.000387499 | 0.19375 | 0.000387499 | no
1902786 | Nivel 1 | 0.25 | 0.774999 | 0.00155 | 0.000387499 | 0.19375 | 0.000387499 | no
1902918 | Nivel 2 | 0.25 | 0.774999 | 0.00155 | 0.000387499 | 0.19375 | 0.000387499 | no
1902921 | Nivel 2 | 0.25 | 0.774999 | 0.00155 | 0.000387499 | 0.19375 | 0.000387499 | no
1902924 | Nivel 2 | 0.25 | 0.774999 | 0.00155 | 0.000387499 | 0.19375 | 0.000387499 | no
1902927 | Nivel 2 | 0.25 | 0.774999 | 0.00155 | 0.000387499 | 0.19375 | 0.000387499 | no
1902930 | Nivel 3 | 0.25 | 0.774999 | 0.00155 | 0.000387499 | 0.19375 | 0.000387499 | no
1902933 | Nivel 3 | 0.25 | 0.774999 | 0.00155 | 0.000387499 | 0.19375 | 0.000387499 | no
1902936 | Nivel 3 | 0.25 | 0.774999 | 0.00155 | 0.000387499 | 0.19375 | 0.000387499 | no
1902939 | Nivel 3 | 0.25 | 0.774999 | 0.00155 | 0.000387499 | 0.19375 | 0.000387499 | no
1902942 | Nivel 4 | 0.25 | 0.774999 | 0.00155 | 0.000387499 | 0.19375 | 0.000387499 | no
1902945 | Nivel 4 | 0.25 | 0.774999 | 0.00155 | 0.000387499 | 0.19375 | 0.000387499 | no
1902948 | Nivel 4 | 0.25 | 0.774999 | 0.00155 | 0.000387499 | 0.19375 | 0.000387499 | no
1902951 | Nivel 4 | 0.25 | 0.774999 | 0.00155 | 0.000387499 | 0.19375 | 0.000387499 | no
1902954 | Nivel 5 | 0.25 | 0.774999 | 0.00155 | 0.000387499 | 0.19375 | 0.000387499 | no
1902957 | Nivel 5 | 0.25 | 0.774999 | 0.00155 | 0.000387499 | 0.19375 | 0.000387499 | no
1902960 | Nivel 5 | 0.25 | 0.774999 | 0.00155 | 0.000387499 | 0.19375 | 0.000387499 | no
1902963 | Nivel 5 | 0.25 | 0.774999 | 0.00155 | 0.000387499 | 0.19375 | 0.000387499 | no
1902966 | Nivel 1 | 0.25 | 0.774999 | 0.00155 | 0.000387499 | 0.19375 | 0.000387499 | no
1902969 | Nivel 1 | 0.25 | 0.774999 | 0.00155 | 0.000387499 | 0.19375 | 0.000387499 | no
1902972 | Nivel 1 | 0.25 | 0.774999 | 0.00155 | 0.000387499 | 0.19375 | 0.000387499 | no
1903022 | Nivel 1 | 0.25 | 0.774999 | 0.00155 | 0.000387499 | 0.19375 | 0.000387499 | no
1903131 | Nivel 1 | 0.25 | 0.774999 | 0.00155 | 0.000387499 | 0.19375 | 0.000387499 | no
1903203 | Nivel 1 | 0.25 | 0.774999 | 0.00155 | 0.000387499 | 0.19375 | 0.000387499 | no

# IfcWall: Basic Wall:C2010 - 0.25 x 0.35 - Enchape cerámico (72)
Type - PredefinedType: STANDARD
Type - Pset_WallCommon - IsExternal: yes
Classification: 21-03 20 10 10 Uniformat (Uniformat); Material: Ceramica 0.25m x 0.35m
Qto_WallBaseQuantities - Height: 1.97 m; Width: 0.01 m
Pset_EnvironmentalImpactIndicators - Reference: C2010 - 0.25 x 0.35 - Enchape cerámico; sets with these values: 2
Pset_WallCommon - LoadBearing: no; ExtendToStructure: no; Reference: C2010 - 0.25 x 0.35 - Enchape cerámico
Name (Basic Wall:C2010 - 0.25 x 0.35 - Enchape cerámico:...) | In | Length (m) | GrossFootprintArea (m2) | GrossVolume (m3) = NetVolume (m3) | GrossSideArea (m2) = NetSideArea (m2)
728589 | Nivel 1 | 0.81 | 0.0081 | 0.013253 | 1.3253
728669 | Nivel 1 | 0.81 | 0.0081 | 0.015957 | 1.5957
728670 | Nivel 1 | 1.165 | 0.01165 | 0.0229505 | 2.29505
749172 | Nivel 3 | 0.81 | 0.0081 | 0.013253 | 1.3253
749231 | Nivel 3 | 0.81 | 0.0081 | 0.015957 | 1.5957
749232 | Nivel 3 | 1.165 | 0.01165 | 0.0229505 | 2.29505
749340 | Nivel 3 | 0.81 | 0.0081 | 0.013253 | 1.3253
749397 | Nivel 3 | 0.81 | 0.0081 | 0.015957 | 1.5957
749398 | Nivel 3 | 1.165 | 0.01165 | 0.0229505 | 2.29505
749542 | Nivel 3 | 0.81 | 0.0081 | 0.013253 | 1.3253
749599 | Nivel 3 | 0.81 | 0.0081 | 0.015957 | 1.5957
749600 | Nivel 3 | 1.165 | 0.01165 | 0.0229505 | 2.29505
749716 | Nivel 3 | 0.81 | 0.0081 | 0.013253 | 1.3253
749773 | Nivel 3 | 0.81 | 0.0081 | 0.015957 | 1.5957
749774 | Nivel 3 | 1.165 | 0.01165 | 0.0229505 | 2.29505
750739 | Nivel 4 | 0.81 | 0.0081 | 0.013253 | 1.3253
750798 | Nivel 4 | 0.81 | 0.0081 | 0.015957 | 1.5957
750799 | Nivel 4 | 1.165 | 0.01165 | 0.0229505 | 2.29505
750907 | Nivel 4 | 0.81 | 0.0081 | 0.013253 | 1.3253
750964 | Nivel 4 | 0.81 | 0.0081 | 0.015957 | 1.5957
750965 | Nivel 4 | 1.165 | 0.01165 | 0.0229505 | 2.29505
751109 | Nivel 4 | 0.81 | 0.0081 | 0.013253 | 1.3253
751166 | Nivel 4 | 0.81 | 0.0081 | 0.015957 | 1.5957
751167 | Nivel 4 | 1.165 | 0.01165 | 0.0229505 | 2.29505
751283 | Nivel 4 | 0.81 | 0.0081 | 0.013253 | 1.3253
751340 | Nivel 4 | 0.81 | 0.0081 | 0.015957 | 1.5957
751341 | Nivel 4 | 1.165 | 0.01165 | 0.0229505 | 2.29505
752306 | Nivel 5 | 0.81 | 0.0081 | 0.013253 | 1.3253
752365 | Nivel 5 | 0.81 | 0.0081 | 0.015957 | 1.5957
752366 | Nivel 5 | 1.165 | 0.01165 | 0.0229505 | 2.29505
752474 | Nivel 5 | 0.81 | 0.0081 | 0.013253 | 1.3253
752531 | Nivel 5 | 0.81 | 0.0081 | 0.015957 | 1.5957
752532 | Nivel 5 | 1.165 | 0.01165 | 0.0229505 | 2.29505
752676 | Nivel 5 | 0.81 | 0.0081 | 0.013253 | 1.3253
752733 | Nivel 5 | 0.81 | 0.0081 | 0.015957 | 1.5957
752734 | Nivel 5 | 1.165 | 0.01165 | 0.0229505 | 2.29505
752850 | Nivel 5 | 0.81 | 0.0081 | 0.013253 | 1.3253
752907 | Nivel 5 | 0.81 | 0.0081 | 0.015957 | 1.5957
752908 | Nivel 5 | 1.165 | 0.01165 | 0.0229505 | 2.29505
753873 | Nivel 6 | 0.81 | 0.0081 | 0.013253 | 1.3253
753932 | Nivel 6 | 0.81 | 0.0081 | 0.015957 | 1.5957
753933 | Nivel 6 | 1.165 | 0.01165 | 0.0229505 | 2.29505
754041 | Nivel 6 | 0.81 | 0.0081 | 0.013253 | 1.3253
754098 | Nivel 6 | 0.81 | 0.0081 | 0.015957 | 1.5957
754099 | Nivel 6 | 1.165 | 0.01165 | 0.0229505 | 2.29505
754243 | Nivel 6 | 0.81 | 0.0081 | 0.013253 | 1.3253
754300 | Nivel 6 | 0.81 | 0.0081 | 0.015957 | 1.5957
754301 | Nivel 6 | 1.165 | 0.01165 | 0.0229505 | 2.29505
754417 | Nivel 6 | 0.81 | 0.0081 | 0.013253 | 1.3253
754474 | Nivel 6 | 0.81 | 0.0081 | 0.015957 | 1.5957
754475 | Nivel 6 | 1.165 | 0.01165 | 0.0229505 | 2.29505
781283 | Nivel 1 | 0.82 | 0.0082 | 0.01345 | 1.345
781340 | Nivel 1 | 0.82 | 0.0082 | 0.016154 | 1.6154
781341 | Nivel 1 | 1.165 | 0.01165 | 0.0229505 | 2.29505
791853 | Nivel 2 | 0.81 | 0.0081 | 0.013253 | 1.3253
791912 | Nivel 2 | 0.81 | 0.0081 | 0.015957 | 1.5957
791913 | Nivel 2 | 1.165 | 0.01165 | 0.0229505 | 2.29505
792020 | Nivel 2 | 0.81 | 0.0081 | 0.013253 | 1.3253
792077 | Nivel 2 | 0.81 | 0.0081 | 0.015957 | 1.5957
792078 | Nivel 2 | 1.165 | 0.01165 | 0.0229505 | 2.29505
792218 | Nivel 2 | 0.81 | 0.0081 | 0.013253 | 1.3253
792275 | Nivel 2 | 0.81 | 0.0081 | 0.015957 | 1.5957
792276 | Nivel 2 | 1.165 | 0.01165 | 0.0229505 | 2.29505
792391 | Nivel 2 | 0.81 | 0.0081 | 0.013253 | 1.3253
792448 | Nivel 2 | 0.81 | 0.0081 | 0.015957 | 1.5957
792449 | Nivel 2 | 1.165 | 0.01165 | 0.0229505 | 2.29505
872688 | Nivel 1 | 0.81 | 0.0081 | 0.013253 | 1.3253
872730 | Nivel 1 | 0.81 | 0.0081 | 0.015957 | 1.5957
872731 | Nivel 1 | 1.165 | 0.01165 | 0.0229505 | 2.29505
872886 | Nivel 1 | 0.81 | 0.0081 | 0.013253 | 1.3253
872928 | Nivel 1 | 0.81 | 0.0081 | 0.015957 | 1.5957
872929 | Nivel 1 | 1.165 | 0.01165 | 0.0229505 | 2.29505

# IfcWall: Basic Wall:C2010 - 0.28 x 0.45 - Salpicadero - Cerámica (72)
Type - PredefinedType: STANDARD
Type - Pset_WallCommon - IsExternal: yes
Classification: 21-03 20 10 10 Uniformat (Uniformat); Material: Ceramica Salpicadero 0.28m x 0.45m
Qto_WallBaseQuantities - Width: 0.01 m
Pset_EnvironmentalImpactIndicators - Reference: C2010 - 0.28 x 0.45 - Salpicadero - Cerámica; sets with these values: 2
Pset_WallCommon - LoadBearing: no; ExtendToStructure: no; Reference: C2010 - 0.28 x 0.45 - Salpicadero - Cerámica
Name (Basic Wall:C2010 - 0.28 x 0.45 - Salpicadero - Cerámica:...) | In | Height (m) | Length (m) | GrossFootprintArea (m2) | GrossVolume (m3) = NetVolume (m3) | GrossSideArea (m2) = NetSideArea (m2)
728672 | Nivel 1 | 0.56 | 0.52 | 0.0052 | 0.002912 | 0.2912
872733 | Nivel 1 | 0.6 | 0.52 | 0.0052 | 0.00312 | 0.312
1130152 | Nivel 1 | 0.56 | 1.49 | 0.0149 | 0.008344 | 0.8344
1130341 | Nivel 1 | 0.56 | 1.49 | 0.0149 | 0.008344 | 0.8344
1130664 | Nivel 2 | 0.56 | 1.51 | 0.0151 | 0.008456 | 0.8456
1131755 | Nivel 3 | 0.56 | 1.51 | 0.0151 | 0.008456 | 0.8456
1131795 | Nivel 3 | 0.56 | 1.51 | 0.0151 | 0.008456 | 0.8456
1131835 | Nivel 3 | 0.56 | 1.51 | 0.0151 | 0.008456 | 0.8456
1131875 | Nivel 3 | 0.56 | 1.51 | 0.0151 | 0.008456 | 0.8456
1131915 | Nivel 4 | 0.56 | 1.51 | 0.0151 | 0.008456 | 0.8456
1131955 | Nivel 4 | 0.56 | 1.51 | 0.0151 | 0.008456 | 0.8456
1131995 | Nivel 4 | 0.56 | 1.51 | 0.0151 | 0.008456 | 0.8456
1132035 | Nivel 4 | 0.56 | 1.51 | 0.0151 | 0.008456 | 0.8456
1132075 | Nivel 5 | 0.56 | 1.51 | 0.0151 | 0.008456 | 0.8456
1132115 | Nivel 5 | 0.56 | 1.51 | 0.0151 | 0.008456 | 0.8456
1132155 | Nivel 5 | 0.56 | 1.51 | 0.0151 | 0.008456 | 0.8456
1132195 | Nivel 5 | 0.56 | 1.51 | 0.0151 | 0.008456 | 0.8456
1132235 | Nivel 6 | 0.56 | 1.51 | 0.0151 | 0.008456 | 0.8456
1132275 | Nivel 6 | 0.56 | 1.51 | 0.0151 | 0.008456 | 0.8456
1132315 | Nivel 6 | 0.56 | 1.51 | 0.0151 | 0.008456 | 0.8456
1132355 | Nivel 6 | 0.56 | 1.51 | 0.0151 | 0.008456 | 0.8456
1132395 | Nivel 2 | 0.56 | 1.51 | 0.0151 | 0.008456 | 0.8456
1132435 | Nivel 2 | 0.56 | 1.51 | 0.0151 | 0.008456 | 0.8456
1132475 | Nivel 2 | 0.56 | 1.51 | 0.0151 | 0.008456 | 0.8456
1139902 | Nivel 1 | 0.56 | 1.5 | 0.015 | 0.0084 | 0.84
1666646 | Nivel 1 | 0.56 | 1.5 | 0.015 | 0.0084 | 0.84
1793707 | Nivel 1 | 0.28 | 0.5075 | 0.005075 | 0.001421 | 0.1421
1794360 | Nivel 1 | 0.28 | 0.45 | 0.0045 | 0.00126 | 0.126
1795306 | Nivel 1 | 0.28 | 0.45 | 0.0045 | 0.00126 | 0.126
1795636 | Nivel 1 | 0.28 | 0.5075 | 0.005075 | 0.001421 | 0.1421
1914649 | Nivel 1 | 0.56 | 0.5095 | 0.005095 | 0.0028532 | 0.28532
1915308 | Nivel 1 | 0.56 | 0.5095 | 0.005095 | 0.0028532 | 0.28532
1916390 | Nivel 2 | 0.28 | 0.4495 | 0.004495 | 0.0012586 | 0.12586
1918431 | Nivel 3 | 0.28 | 0.4495 | 0.004495 | 0.0012586 | 0.12586
1918437 | Nivel 3 | 0.28 | 0.4495 | 0.004495 | 0.0012586 | 0.12586
1918443 | Nivel 3 | 0.28 | 0.4495 | 0.004495 | 0.0012586 | 0.12586
1918449 | Nivel 3 | 0.28 | 0.4495 | 0.004495 | 0.0012586 | 0.12586
1918455 | Nivel 4 | 0.28 | 0.4495 | 0.004495 | 0.0012586 | 0.12586
1918461 | Nivel 4 | 0.28 | 0.4495 | 0.004495 | 0.0012586 | 0.12586
1918467 | Nivel 4 | 0.28 | 0.4495 | 0.004495 | 0.0012586 | 0.12586
1918473 | Nivel 4 | 0.28 | 0.4495 | 0.004495 | 0.0012586 | 0.12586
1918479 | Nivel 5 | 0.28 | 0.4495 | 0.004495 | 0.0012586 | 0.12586
1918485 | Nivel 5 | 0.28 | 0.4495 | 0.004495 | 0.0012586 | 0.12586
1918491 | Nivel 5 | 0.28 | 0.4495 | 0.004495 | 0.0012586 | 0.12586
1918497 | Nivel 5 | 0.28 | 0.4495 | 0.004495 | 0.0012586 | 0.12586
1918503 | Nivel 6 | 0.28 | 0.4495 | 0.004495 | 0.0012586 | 0.12586
1918509 | Nivel 6 | 0.28 | 0.4495 | 0.004495 | 0.0012586 | 0.12586
1918515 | Nivel 6 | 0.28 | 0.4495 | 0.004495 | 0.0012586 | 0.12586
1918521 | Nivel 6 | 0.28 | 0.4495 | 0.004495 | 0.0012586 | 0.12586
1918527 | Nivel 2 | 0.28 | 0.4495 | 0.004495 | 0.0012586 | 0.12586
1918533 | Nivel 2 | 0.28 | 0.4495 | 0.004495 | 0.0012586 | 0.12586
1918539 | Nivel 2 | 0.28 | 0.4495 | 0.004495 | 0.0012586 | 0.12586
1918885 | Nivel 2 | 0.56 | 0.51 | 0.0051 | 0.002856 | 0.2856
1920282 | Nivel 3 | 0.56 | 0.51 | 0.0051 | 0.002856 | 0.2856
1920293 | Nivel 3 | 0.56 | 0.51 | 0.0051 | 0.002856 | 0.2856
1920304 | Nivel 3 | 0.56 | 0.51 | 0.0051 | 0.002856 | 0.2856
1920315 | Nivel 3 | 0.56 | 0.51 | 0.0051 | 0.002856 | 0.2856
1920326 | Nivel 4 | 0.56 | 0.51 | 0.0051 | 0.002856 | 0.2856
1920337 | Nivel 4 | 0.56 | 0.51 | 0.0051 | 0.002856 | 0.2856
1920348 | Nivel 4 | 0.56 | 0.51 | 0.0051 | 0.002856 | 0.2856
1920359 | Nivel 4 | 0.56 | 0.51 | 0.0051 | 0.002856 | 0.2856
1920370 | Nivel 5 | 0.56 | 0.51 | 0.0051 | 0.002856 | 0.2856
1920381 | Nivel 5 | 0.56 | 0.51 | 0.0051 | 0.002856 | 0.2856
1920392 | Nivel 5 | 0.56 | 0.51 | 0.0051 | 0.002856 | 0.2856
1920403 | Nivel 5 | 0.56 | 0.51 | 0.0051 | 0.002856 | 0.2856
1920414 | Nivel 6 | 0.56 | 0.51 | 0.0051 | 0.002856 | 0.2856
1920425 | Nivel 6 | 0.56 | 0.51 | 0.0051 | 0.002856 | 0.2856
1920436 | Nivel 6 | 0.56 | 0.51 | 0.0051 | 0.002856 | 0.2856
1920447 | Nivel 6 | 0.56 | 0.51 | 0.0051 | 0.002856 | 0.2856
1920458 | Nivel 2 | 0.56 | 0.51 | 0.0051 | 0.002856 | 0.2856
1920469 | Nivel 2 | 0.56 | 0.51 | 0.0051 | 0.002856 | 0.2856
1920480 | Nivel 2 | 0.56 | 0.51 | 0.0051 | 0.002856 | 0.2856

# IfcWindow: B2020 - 6c Ventana corrediza - Aluminio + Vidrio:B2020 -2.13m x 1.750m - Ventana corrediza 2C - Aluminio + Vidrio (23)
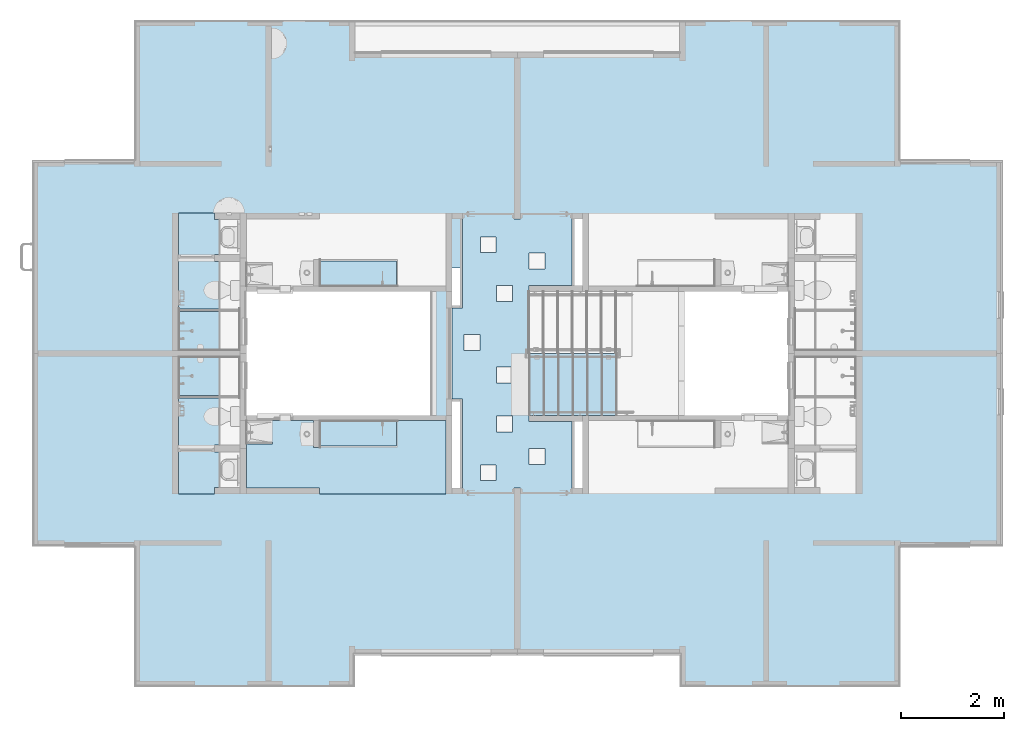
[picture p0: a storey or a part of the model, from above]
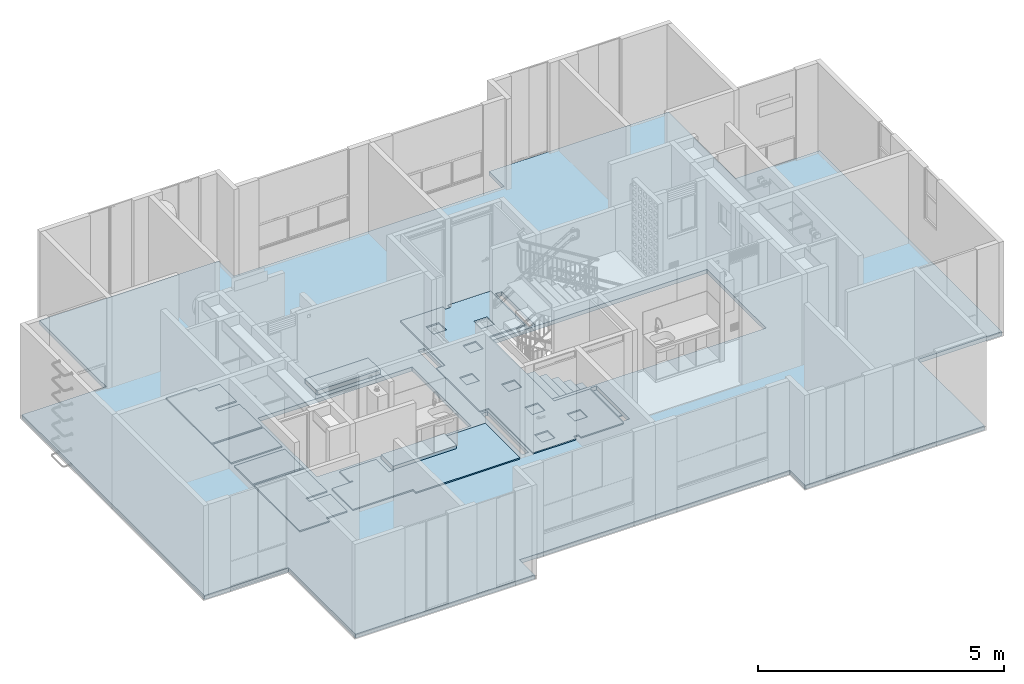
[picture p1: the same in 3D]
Properties of the parts of a building model (IFC4), part 6 of 6

# IfcWindow: B2020 - 6c Ventana corrediza - Aluminio + Vidrio:B2020 -2.13m x 1.750m - Ventana corrediza 2C - Aluminio + Vidrio (23)
Type - PredefinedType: WINDOW; Material: Aluminio, Vidrio, Alfajía en aluminio
Type - Pset_WindowCommon - IsExternal: yes; FireExit: yes; FireRating: 30
OverallHeight: 1.75 m; OverallWidth: 2.125 m; Classification: 21-02 20 20 10 Uniformat (Uniformat)
Pset_EnvironmentalImpactIndicators - Reference: B2020 -2.13m x 1.750m - Ventana corrediza 2C - Aluminio + Vidrio
Pset_WindowCommon - Reference: B2020 -2.13m x 1.750m - Ventana corrediza 2C - Aluminio + Vidrio
Qto_WindowBaseQuantities - Width: 2.125 m; Height: 1.75 m; Area: 3.71875 m2
Name (B2020 - 6c Ventana corrediza - Aluminio + Vidrio:B2020 -2.13m x 1.750m - Ventana corrediza 2C - Aluminio + Vidrio:...) | In
728590 | Nivel 1
872689 | Nivel 1
872887 | Nivel 1
1984143 | Nivel 2
1984267 | Nivel 3
1984270 | Nivel 3
1984273 | Nivel 3
1984276 | Nivel 3
1984279 | Nivel 4
1984282 | Nivel 4
1984285 | Nivel 4
1984288 | Nivel 4
1984291 | Nivel 5
1984294 | Nivel 5
1984297 | Nivel 5
1984300 | Nivel 5
1984303 | Nivel 6
1984306 | Nivel 6
1984309 | Nivel 6
1984312 | Nivel 6
1984315 | Nivel 2
1984318 | Nivel 2
1984321 | Nivel 2

# IfcWindow: B2020 - Ventana batiente - Aluminio + Vidrio:B2020 -0.52m x 1.1.25m - Ventana batiente 2C - Aluminio + Vidrio (10)
Type - PredefinedType: WINDOW; Material: Vidrio, Aluminio, <Unnamed>
Type - Pset_WindowCommon - IsExternal: yes
OverallHeight: 1.25 m; OverallWidth: 0.52 m; Classification: 21-02 20 20 10 Uniformat (Uniformat)
Pset_EnvironmentalImpactIndicators - Reference: B2020 -0.52m x 1.1.25m - Ventana batiente 2C - Aluminio + Vidrio
Pset_WindowCommon - Reference: B2020 -0.52m x 1.1.25m - Ventana batiente 2C - Aluminio + Vidrio
Qto_WindowBaseQuantities - Width: 0.52 m; Height: 1.25 m; Perimeter: 0.137679 m; Area: 0.65 m2
Name (B2020 - Ventana batiente - Aluminio + Vidrio:B2020 -0.52m x 1.1.25m - Ventana batiente 2C - Aluminio + Vidrio:...) | In
1143134 | Nivel 2
1145660 | Nivel 2
1145669 | Nivel 3
1145670 | Nivel 3
1145675 | Nivel 4
1145676 | Nivel 4
1145681 | Nivel 5
1145682 | Nivel 5
1145687 | Nivel 6
1145688 | Nivel 6

# IfcWindow: B2020 - Ventana corrediza - Aluminio + Vidrio:B2020 - 1.35m x 2.25m - Ventana corrediza 2C - Aluminio + Vidrio (24)
Type - PredefinedType: WINDOW; Material: Vidrio, Aluminio, <Unnamed>
Type - Pset_WindowCommon - IsExternal: yes; FireExit: yes; FireRating: 30
OverallWidth: 1.35 m; Classification: 21-02 20 20 10 Uniformat (Uniformat)
Pset_EnvironmentalImpactIndicators - Reference: B2020 - 1.35m x 2.25m - Ventana corrediza 2C - Aluminio + Vidrio
Pset_WindowCommon - Reference: B2020 - 1.35m x 2.25m - Ventana corrediza 2C - Aluminio + Vidrio
Qto_WindowBaseQuantities - Width: 1.35 m; Height: 2.25 m; Area: 3.0375 m2
Name (B2020 - Ventana corrediza - Aluminio + Vidrio:B2020 - 1.35m x 2.25m - Ventana corrediza 2C - Aluminio + Vidrio:...) | In | OverallHeight (m)
728564 | Nivel 1 | 2.25
749147 | Nivel 3 | 2.265
749315 | Nivel 3 | 2.265
749517 | Nivel 3 | 2.265
749691 | Nivel 3 | 2.265
750714 | Nivel 4 | 2.265
750882 | Nivel 4 | 2.265
751084 | Nivel 4 | 2.265
751258 | Nivel 4 | 2.265
752281 | Nivel 5 | 2.265
752449 | Nivel 5 | 2.265
752651 | Nivel 5 | 2.265
752825 | Nivel 5 | 2.265
753848 | Nivel 6 | 2.265
754016 | Nivel 6 | 2.265
754392 | Nivel 6 | 2.265
781258 | Nivel 1 | 2.25
791828 | Nivel 2 | 2.265
791995 | Nivel 2 | 2.265
792193 | Nivel 2 | 2.265
792366 | Nivel 2 | 2.265
872663 | Nivel 1 | 2.25
872861 | Nivel 1 | 2.25
1250795 | Nivel 6 | 2.25

# IfcWindow: B2020 - Ventana corrediza - Aluminio + Vidrio:B2020 -1.26m x 1.750m - Ventana corrediza 2C - Aluminio + Vidrio, B2020 - Ventana corrediza - Aluminio + Vidrio:B2020 -1.26m x 1.750m - Ventana corrediza 2C - Aluminio + Vidrio:1141275
In: Nivel 1
Type - PredefinedType: WINDOW; Material: Vidrio, Aluminio, <Unnamed>
Type - Pset_WindowCommon - IsExternal: no
OverallHeight: 1.75 m; OverallWidth: 1.26 m; Classification: 21-02 20 20 10 Uniformat (Uniformat)
Pset_EnvironmentalImpactIndicators - Reference: B2020 -1.26m x 1.750m - Ventana corrediza 2C - Aluminio + Vidrio
Pset_WindowCommon - IsExternal: yes; Reference: B2020 -1.26m x 1.750m - Ventana corrediza 2C - Aluminio + Vidrio
Qto_WindowBaseQuantities - Width: 1.26 m; Height: 1.75 m; Area: 2.205 m2

# IfcWindow: B2020 - Ventana corrediza - Aluminio+Vidrio:B2020 - 0.52 x 0.52 - Ventana corrediza - Aluminio+Vidrio (24)
Type - PredefinedType: WINDOW; Material: Aluminio, Vidrio
Type - Pset_WindowCommon - IsExternal: no
OverallHeight: 0.52 m; OverallWidth: 0.52 m; Classification: 21-02 20 20 10 Uniformat (Uniformat)
Pset_EnvironmentalImpactIndicators - Reference: B2020 - 0.52 x 0.52 - Ventana corrediza - Aluminio+Vidrio
Pset_WindowCommon - Reference: B2020 - 0.52 x 0.52 - Ventana corrediza - Aluminio+Vidrio
Qto_WindowBaseQuantities - Width: 0.52 m; Height: 0.52 m; Area: 0.2704 m2
Name (B2020 - Ventana corrediza - Aluminio+Vidrio:B2020 - 0.52 x 0.52 - Ventana corrediza - Aluminio+Vidrio:...) | In
728614 | Nivel 1
749197 | Nivel 3
749365 | Nivel 3
749567 | Nivel 3
749741 | Nivel 3
750764 | Nivel 4
750932 | Nivel 4
751134 | Nivel 4
751308 | Nivel 4
752331 | Nivel 5
752499 | Nivel 5
752701 | Nivel 5
752875 | Nivel 5
753898 | Nivel 6
754066 | Nivel 6
754268 | Nivel 6
754442 | Nivel 6
781308 | Nivel 1
791878 | Nivel 2
792045 | Nivel 2
792243 | Nivel 2
792416 | Nivel 2
872713 | Nivel 1
872911 | Nivel 1

# IfcWindow: B2020 - Ventana corrediza 2C - Aluminio + Vidrio:B2020 - 0.90m x 2.25m - Ventana corrediza 2C - Aluminio + Vidrio (24)
Type - PredefinedType: WINDOW; Material: Vidrio, <Unnamed>
Type - Pset_WindowCommon - IsExternal: no
OverallHeight: 2.25 m; OverallWidth: 0.9 m; Classification: 21-02 20 20 10 Uniformat (Uniformat)
Pset_EnvironmentalImpactIndicators - Reference: B2020 - 0.90m x 2.25m - Ventana corrediza 2C - Aluminio + Vidrio
Pset_WindowCommon - Reference: B2020 - 0.90m x 2.25m - Ventana corrediza 2C - Aluminio + Vidrio
Qto_WindowBaseQuantities - Width: 0.9 m; Height: 2.25 m; Area: 2.025 m2
Name (B2020 - Ventana corrediza 2C - Aluminio + Vidrio:B2020 - 0.90m x 2.25m - Ventana corrediza 2C - Aluminio + Vidrio:...) | In
728562 | Nivel 1 | Pset_WindowCommon - IsExternal: yes
749145 | Nivel 3
749313 | Nivel 3
749515 | Nivel 3
749689 | Nivel 3
752279 | Nivel 5
752447 | Nivel 5
752649 | Nivel 5
752823 | Nivel 5
781256 | Nivel 1
801582 | Nivel 2
801631 | Nivel 2
801680 | Nivel 2
801907 | Nivel 4
801925 | Nivel 4
801943 | Nivel 4
801961 | Nivel 4
802127 | Nivel 6
802145 | Nivel 6
802163 | Nivel 6
802181 | Nivel 6
872661 | Nivel 1
872859 | Nivel 1
998480 | Nivel 2

# IfcWindow: B2020 - Ventana corrediza 2C - Aluminio + Vidrio:B2020 - 1.02m x 2.25m - Ventana corrediza 2C - Aluminio + Vidrio (12)
Type - PredefinedType: WINDOW; Material: Vidrio, <Unnamed>
Type - Pset_WindowCommon - IsExternal: yes; FireExit: no; FireRating: 30
OverallHeight: 2.25 m; OverallWidth: 1.02 m; Classification: 21-02 20 20 10 Uniformat (Uniformat)
Pset_EnvironmentalImpactIndicators - Reference: B2020 - 1.02m x 2.25m - Ventana corrediza 2C - Aluminio + Vidrio
Pset_WindowCommon - Reference: B2020 - 1.02m x 2.25m - Ventana corrediza 2C - Aluminio + Vidrio
Qto_WindowBaseQuantities - Width: 1.02 m; Height: 2.25 m; Area: 2.295 m2
Name (B2020 - Ventana corrediza 2C - Aluminio + Vidrio:B2020 - 1.02m x 2.25m - Ventana corrediza 2C - Aluminio + Vidrio:...) | In
749690 | Nivel 3
752280 | Nivel 5
752824 | Nivel 5
781257 | Nivel 1
801632 | Nivel 2
801908 | Nivel 4
801944 | Nivel 4
802128 | Nivel 6
802164 | Nivel 6
872662 | Nivel 1
998481 | Nivel 2
2050076 | Nivel 3

# IfcWindow: B2020 - Ventana corrediza 2C - Aluminio + Vidrio:B2020 - 1.02m x 2.25m - Ventana corrediza 2C - Aluminio + Vidrio (12)
Type - PredefinedType: WINDOW; Material: Vidrio, <Unnamed>
Type - Pset_WindowCommon - IsExternal: yes; FireRating: 30; FireExit: no
OverallHeight: 2.25 m; OverallWidth: 1.02 m; Classification: 21-02 20 20 10 Uniformat (Uniformat)
Pset_EnvironmentalImpactIndicators - Reference: B2020 - 1.02m x 2.25m - Ventana corrediza 2C - Aluminio + Vidrio
Pset_WindowCommon - Reference: B2020 - 1.02m x 2.25m - Ventana corrediza 2C - Aluminio + Vidrio
Qto_WindowBaseQuantities - Width: 1.02 m; Height: 2.25 m; Area: 2.295 m2
Name (B2020 - Ventana corrediza 2C - Aluminio + Vidrio:B2020 - 1.02m x 2.25m - Ventana corrediza 2C - Aluminio + Vidrio:...) | In
728563 | Nivel 1
749314 | Nivel 3
749516 | Nivel 3
752448 | Nivel 5
752650 | Nivel 5
801583 | Nivel 2
801681 | Nivel 2
801926 | Nivel 4
801962 | Nivel 4
802146 | Nivel 6
802182 | Nivel 6
872860 | Nivel 1

# IfcWindow: B2020 - Ventana corrediza con rejilla - Aluminio+Vidrio:B2020 - 1.15 x 0.70 - Ventana corrediza con rejilla - Aluminio+Vidrio (20)
Type - PredefinedType: WINDOW; Material: Vidrio, Aluminio
Type - Pset_WindowCommon - IsExternal: no
OverallHeight: 1.15 m; OverallWidth: 0.7 m; Classification: 21-02 20 20 10 Uniformat (Uniformat)
Pset_EnvironmentalImpactIndicators - Reference: B2020 - 1.15 x 0.70 - Ventana corrediza con rejilla - Aluminio+Vidrio
Pset_WindowCommon - Reference: B2020 - 1.15 x 0.70 - Ventana corrediza con rejilla - Aluminio+Vidrio
Qto_WindowBaseQuantities - Width: 0.7 m; Height: 1.15 m; Area: 0.805 m2
Name (B2020 - Ventana corrediza con rejilla - Aluminio+Vidrio:B2020 - 1.15 x 0.70 - Ventana corrediza con rejilla - Aluminio+Vidrio:...) | In
791896 | Nivel 2 | Pset_WindowCommon - IsExternal: yes
792259 | Nivel 2
1330990 | Nivel 2
1330992 | Nivel 2
1332195 | Nivel 3
1332198 | Nivel 3
1332207 | Nivel 4
1332210 | Nivel 4
1332219 | Nivel 5
1332222 | Nivel 5
1332231 | Nivel 6
1332234 | Nivel 6
1332444 | Nivel 3
1332447 | Nivel 3
1332471 | Nivel 4
1332474 | Nivel 4
1332498 | Nivel 5
1332501 | Nivel 5
1332544 | Nivel 6
1332547 | Nivel 6

# IfcWindow: B2070 - Rejilla de ventilación - Aluminio:B2070 - 0.15m x 0.20m - Rejilla de ventilación - Aluminio (20)
Type - PredefinedType: WINDOW; Material: <Unnamed>, Rejilla plastica
Type - Pset_WindowCommon - IsExternal: no
OverallHeight: 0.15 m; OverallWidth: 0.2 m; Classification: 21-02 20 70 50 Uniformat (Uniformat)
Pset_EnvironmentalImpactIndicators - Reference: B2070 - 0.15m x 0.20m - Rejilla de ventilación - Aluminio
Pset_WindowCommon - Reference: B2070 - 0.15m x 0.20m - Rejilla de ventilación - Aluminio
Qto_WindowBaseQuantities - Width: 0.2 m; Height: 0.15 m; Area: 0.03 m2
Name (B2070 - Rejilla de ventilación - Aluminio:B2070 - 0.15m x 0.20m - Rejilla de ventilación - Aluminio:...) | In
791957 | Nivel 2 | Pset_WindowCommon - IsExternal: yes
792320 | Nivel 2
1330991 | Nivel 2
1330993 | Nivel 2
1332196 | Nivel 3
1332199 | Nivel 3
1332208 | Nivel 4
1332211 | Nivel 4
1332220 | Nivel 5
1332223 | Nivel 5
1332232 | Nivel 6
1332235 | Nivel 6
1332445 | Nivel 3
1332448 | Nivel 3
1332472 | Nivel 4
1332475 | Nivel 4
1332499 | Nivel 5
1332502 | Nivel 5
1332545 | Nivel 6
1332548 | Nivel 6
